VERSION 5.8 ;
BUSBITCHARS "[]" ;
DIVIDERCHAR "/" ;
UNITS
    DATABASE MICRONS 1000 ;
END UNITS

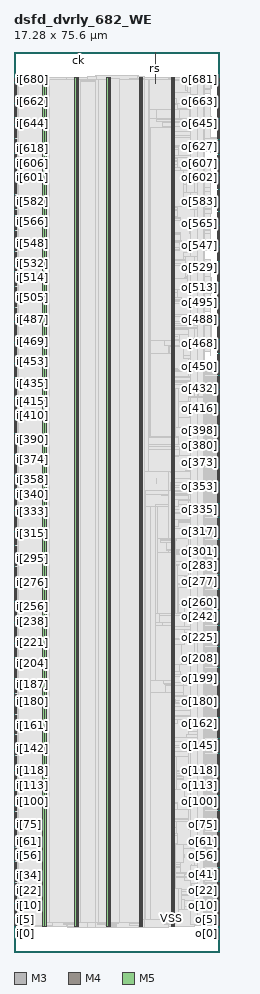
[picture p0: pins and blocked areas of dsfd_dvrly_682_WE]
MACRO dsfd_dvrly_682_WE
  FOREIGN dsfd_dvrly_682_WE 0 0 ;
  CLASS BLOCK ;
  SIZE 17.28 BY 75.6 ;
  PIN ck
    DIRECTION INPUT ;
    USE SIGNAL ;
    PORT
      LAYER M3 ;
        RECT  5.4 75.456 5.418 75.6 ;
    END
    PORT
      LAYER M3 ;
        RECT  5.4 74.683 5.418 75.468 ;
    END
  END ck
  PIN ck_o
    DIRECTION OUTPUT ;
    USE SIGNAL ;
    PORT
      LAYER M4 ;
        RECT  17.088 73.392 17.28 73.416 ;
    END
  END ck_o
  PIN i[0]
    DIRECTION INPUT ;
    USE SIGNAL ;
    PORT
      LAYER M4 ;
        RECT  0 2.208 0.192 2.232 ;
    END
  END i[0]
  PIN i[100]
    DIRECTION INPUT ;
    USE SIGNAL ;
    PORT
      LAYER M4 ;
        RECT  0 12.672 0.192 12.696 ;
    END
  END i[100]
  PIN i[101]
    DIRECTION INPUT ;
    USE SIGNAL ;
    PORT
      LAYER M4 ;
        RECT  0 12.768 0.192 12.792 ;
    END
  END i[101]
  PIN i[102]
    DIRECTION INPUT ;
    USE SIGNAL ;
    PORT
      LAYER M4 ;
        RECT  0 12.864 0.192 12.888 ;
    END
  END i[102]
  PIN i[103]
    DIRECTION INPUT ;
    USE SIGNAL ;
    PORT
      LAYER M4 ;
        RECT  0 13.008 0.192 13.032 ;
    END
  END i[103]
  PIN i[104]
    DIRECTION INPUT ;
    USE SIGNAL ;
    PORT
      LAYER M4 ;
        RECT  0 13.104 0.192 13.128 ;
    END
  END i[104]
  PIN i[105]
    DIRECTION INPUT ;
    USE SIGNAL ;
    PORT
      LAYER M4 ;
        RECT  0 13.2 0.192 13.224 ;
    END
  END i[105]
  PIN i[106]
    DIRECTION INPUT ;
    USE SIGNAL ;
    PORT
      LAYER M4 ;
        RECT  0 13.296 0.192 13.32 ;
    END
  END i[106]
  PIN i[107]
    DIRECTION INPUT ;
    USE SIGNAL ;
    PORT
      LAYER M4 ;
        RECT  0 13.392 0.192 13.416 ;
    END
  END i[107]
  PIN i[108]
    DIRECTION INPUT ;
    USE SIGNAL ;
    PORT
      LAYER M4 ;
        RECT  0 13.488 0.192 13.512 ;
    END
  END i[108]
  PIN i[109]
    DIRECTION INPUT ;
    USE SIGNAL ;
    PORT
      LAYER M4 ;
        RECT  0 13.632 0.192 13.656 ;
    END
  END i[109]
  PIN i[10]
    DIRECTION INPUT ;
    USE SIGNAL ;
    PORT
      LAYER M4 ;
        RECT  0 3.264 0.192 3.288 ;
    END
  END i[10]
  PIN i[110]
    DIRECTION INPUT ;
    USE SIGNAL ;
    PORT
      LAYER M4 ;
        RECT  0 13.728 0.192 13.752 ;
    END
  END i[110]
  PIN i[111]
    DIRECTION INPUT ;
    USE SIGNAL ;
    PORT
      LAYER M4 ;
        RECT  0 13.824 0.192 13.848 ;
    END
  END i[111]
  PIN i[112]
    DIRECTION INPUT ;
    USE SIGNAL ;
    PORT
      LAYER M4 ;
        RECT  0 13.92 0.192 13.944 ;
    END
  END i[112]
  PIN i[113]
    DIRECTION INPUT ;
    USE SIGNAL ;
    PORT
      LAYER M4 ;
        RECT  0 14.016 0.192 14.04 ;
    END
  END i[113]
  PIN i[114]
    DIRECTION INPUT ;
    USE SIGNAL ;
    PORT
      LAYER M4 ;
        RECT  0 14.16 0.192 14.184 ;
    END
  END i[114]
  PIN i[115]
    DIRECTION INPUT ;
    USE SIGNAL ;
    PORT
      LAYER M4 ;
        RECT  0 14.256 0.192 14.28 ;
    END
  END i[115]
  PIN i[116]
    DIRECTION INPUT ;
    USE SIGNAL ;
    PORT
      LAYER M4 ;
        RECT  0 14.352 0.192 14.376 ;
    END
  END i[116]
  PIN i[117]
    DIRECTION INPUT ;
    USE SIGNAL ;
    PORT
      LAYER M4 ;
        RECT  0 14.448 0.192 14.472 ;
    END
  END i[117]
  PIN i[118]
    DIRECTION INPUT ;
    USE SIGNAL ;
    PORT
      LAYER M4 ;
        RECT  0 14.544 0.192 14.568 ;
    END
  END i[118]
  PIN i[119]
    DIRECTION INPUT ;
    USE SIGNAL ;
    PORT
      LAYER M4 ;
        RECT  0 14.64 0.192 14.664 ;
    END
  END i[119]
  PIN i[11]
    DIRECTION INPUT ;
    USE SIGNAL ;
    PORT
      LAYER M4 ;
        RECT  0 3.36 0.192 3.384 ;
    END
  END i[11]
  PIN i[120]
    DIRECTION INPUT ;
    USE SIGNAL ;
    PORT
      LAYER M4 ;
        RECT  0 14.784 0.192 14.808 ;
    END
  END i[120]
  PIN i[121]
    DIRECTION INPUT ;
    USE SIGNAL ;
    PORT
      LAYER M4 ;
        RECT  0 14.88 0.192 14.904 ;
    END
  END i[121]
  PIN i[122]
    DIRECTION INPUT ;
    USE SIGNAL ;
    PORT
      LAYER M4 ;
        RECT  0 14.976 0.192 15 ;
    END
  END i[122]
  PIN i[123]
    DIRECTION INPUT ;
    USE SIGNAL ;
    PORT
      LAYER M4 ;
        RECT  0 15.072 0.192 15.096 ;
    END
  END i[123]
  PIN i[124]
    DIRECTION INPUT ;
    USE SIGNAL ;
    PORT
      LAYER M4 ;
        RECT  0 15.168 0.192 15.192 ;
    END
  END i[124]
  PIN i[125]
    DIRECTION INPUT ;
    USE SIGNAL ;
    PORT
      LAYER M4 ;
        RECT  0 15.312 0.192 15.336 ;
    END
  END i[125]
  PIN i[126]
    DIRECTION INPUT ;
    USE SIGNAL ;
    PORT
      LAYER M4 ;
        RECT  0 15.408 0.192 15.432 ;
    END
  END i[126]
  PIN i[127]
    DIRECTION INPUT ;
    USE SIGNAL ;
    PORT
      LAYER M4 ;
        RECT  0 15.504 0.192 15.528 ;
    END
  END i[127]
  PIN i[128]
    DIRECTION INPUT ;
    USE SIGNAL ;
    PORT
      LAYER M4 ;
        RECT  0 15.6 0.192 15.624 ;
    END
  END i[128]
  PIN i[129]
    DIRECTION INPUT ;
    USE SIGNAL ;
    PORT
      LAYER M4 ;
        RECT  0 15.696 0.192 15.72 ;
    END
  END i[129]
  PIN i[12]
    DIRECTION INPUT ;
    USE SIGNAL ;
    PORT
      LAYER M4 ;
        RECT  0 3.456 0.192 3.48 ;
    END
  END i[12]
  PIN i[130]
    DIRECTION INPUT ;
    USE SIGNAL ;
    PORT
      LAYER M4 ;
        RECT  0 15.792 0.192 15.816 ;
    END
  END i[130]
  PIN i[131]
    DIRECTION INPUT ;
    USE SIGNAL ;
    PORT
      LAYER M4 ;
        RECT  0 15.936 0.192 15.96 ;
    END
  END i[131]
  PIN i[132]
    DIRECTION INPUT ;
    USE SIGNAL ;
    PORT
      LAYER M4 ;
        RECT  0 16.032 0.192 16.056 ;
    END
  END i[132]
  PIN i[133]
    DIRECTION INPUT ;
    USE SIGNAL ;
    PORT
      LAYER M4 ;
        RECT  0 16.128 0.192 16.152 ;
    END
  END i[133]
  PIN i[134]
    DIRECTION INPUT ;
    USE SIGNAL ;
    PORT
      LAYER M4 ;
        RECT  0 16.224 0.192 16.248 ;
    END
  END i[134]
  PIN i[135]
    DIRECTION INPUT ;
    USE SIGNAL ;
    PORT
      LAYER M4 ;
        RECT  0 16.32 0.192 16.344 ;
    END
  END i[135]
  PIN i[136]
    DIRECTION INPUT ;
    USE SIGNAL ;
    PORT
      LAYER M4 ;
        RECT  0 16.416 0.192 16.44 ;
    END
  END i[136]
  PIN i[137]
    DIRECTION INPUT ;
    USE SIGNAL ;
    PORT
      LAYER M4 ;
        RECT  0 16.56 0.192 16.584 ;
    END
  END i[137]
  PIN i[138]
    DIRECTION INPUT ;
    USE SIGNAL ;
    PORT
      LAYER M4 ;
        RECT  0 16.656 0.192 16.68 ;
    END
  END i[138]
  PIN i[139]
    DIRECTION INPUT ;
    USE SIGNAL ;
    PORT
      LAYER M4 ;
        RECT  0 16.752 0.192 16.776 ;
    END
  END i[139]
  PIN i[13]
    DIRECTION INPUT ;
    USE SIGNAL ;
    PORT
      LAYER M4 ;
        RECT  0 3.6 0.192 3.624 ;
    END
  END i[13]
  PIN i[140]
    DIRECTION INPUT ;
    USE SIGNAL ;
    PORT
      LAYER M4 ;
        RECT  0 16.848 0.192 16.872 ;
    END
  END i[140]
  PIN i[141]
    DIRECTION INPUT ;
    USE SIGNAL ;
    PORT
      LAYER M4 ;
        RECT  0 16.944 0.192 16.968 ;
    END
  END i[141]
  PIN i[142]
    DIRECTION INPUT ;
    USE SIGNAL ;
    PORT
      LAYER M4 ;
        RECT  0 17.088 0.192 17.112 ;
    END
  END i[142]
  PIN i[143]
    DIRECTION INPUT ;
    USE SIGNAL ;
    PORT
      LAYER M4 ;
        RECT  0 17.184 0.192 17.208 ;
    END
  END i[143]
  PIN i[144]
    DIRECTION INPUT ;
    USE SIGNAL ;
    PORT
      LAYER M4 ;
        RECT  0 17.28 0.192 17.304 ;
    END
  END i[144]
  PIN i[145]
    DIRECTION INPUT ;
    USE SIGNAL ;
    PORT
      LAYER M4 ;
        RECT  0 17.376 0.192 17.4 ;
    END
  END i[145]
  PIN i[146]
    DIRECTION INPUT ;
    USE SIGNAL ;
    PORT
      LAYER M4 ;
        RECT  0 17.472 0.192 17.496 ;
    END
  END i[146]
  PIN i[147]
    DIRECTION INPUT ;
    USE SIGNAL ;
    PORT
      LAYER M4 ;
        RECT  0 17.568 0.192 17.592 ;
    END
  END i[147]
  PIN i[148]
    DIRECTION INPUT ;
    USE SIGNAL ;
    PORT
      LAYER M4 ;
        RECT  0 17.712 0.192 17.736 ;
    END
  END i[148]
  PIN i[149]
    DIRECTION INPUT ;
    USE SIGNAL ;
    PORT
      LAYER M4 ;
        RECT  0 17.808 0.192 17.832 ;
    END
  END i[149]
  PIN i[14]
    DIRECTION INPUT ;
    USE SIGNAL ;
    PORT
      LAYER M4 ;
        RECT  0 3.696 0.192 3.72 ;
    END
  END i[14]
  PIN i[150]
    DIRECTION INPUT ;
    USE SIGNAL ;
    PORT
      LAYER M4 ;
        RECT  0 17.904 0.192 17.928 ;
    END
  END i[150]
  PIN i[151]
    DIRECTION INPUT ;
    USE SIGNAL ;
    PORT
      LAYER M4 ;
        RECT  0 18 0.192 18.024 ;
    END
  END i[151]
  PIN i[152]
    DIRECTION INPUT ;
    USE SIGNAL ;
    PORT
      LAYER M4 ;
        RECT  0 18.096 0.192 18.12 ;
    END
  END i[152]
  PIN i[153]
    DIRECTION INPUT ;
    USE SIGNAL ;
    PORT
      LAYER M4 ;
        RECT  0 18.192 0.192 18.216 ;
    END
  END i[153]
  PIN i[154]
    DIRECTION INPUT ;
    USE SIGNAL ;
    PORT
      LAYER M4 ;
        RECT  0 18.336 0.192 18.36 ;
    END
  END i[154]
  PIN i[155]
    DIRECTION INPUT ;
    USE SIGNAL ;
    PORT
      LAYER M4 ;
        RECT  0 18.432 0.192 18.456 ;
    END
  END i[155]
  PIN i[156]
    DIRECTION INPUT ;
    USE SIGNAL ;
    PORT
      LAYER M4 ;
        RECT  0 18.528 0.192 18.552 ;
    END
  END i[156]
  PIN i[157]
    DIRECTION INPUT ;
    USE SIGNAL ;
    PORT
      LAYER M4 ;
        RECT  0 18.624 0.192 18.648 ;
    END
  END i[157]
  PIN i[158]
    DIRECTION INPUT ;
    USE SIGNAL ;
    PORT
      LAYER M4 ;
        RECT  0 18.72 0.192 18.744 ;
    END
  END i[158]
  PIN i[159]
    DIRECTION INPUT ;
    USE SIGNAL ;
    PORT
      LAYER M4 ;
        RECT  0 18.864 0.192 18.888 ;
    END
  END i[159]
  PIN i[15]
    DIRECTION INPUT ;
    USE SIGNAL ;
    PORT
      LAYER M4 ;
        RECT  0 3.792 0.192 3.816 ;
    END
  END i[15]
  PIN i[160]
    DIRECTION INPUT ;
    USE SIGNAL ;
    PORT
      LAYER M4 ;
        RECT  0 18.96 0.192 18.984 ;
    END
  END i[160]
  PIN i[161]
    DIRECTION INPUT ;
    USE SIGNAL ;
    PORT
      LAYER M4 ;
        RECT  0 19.056 0.192 19.08 ;
    END
  END i[161]
  PIN i[162]
    DIRECTION INPUT ;
    USE SIGNAL ;
    PORT
      LAYER M4 ;
        RECT  0 19.152 0.192 19.176 ;
    END
  END i[162]
  PIN i[163]
    DIRECTION INPUT ;
    USE SIGNAL ;
    PORT
      LAYER M4 ;
        RECT  0 19.248 0.192 19.272 ;
    END
  END i[163]
  PIN i[164]
    DIRECTION INPUT ;
    USE SIGNAL ;
    PORT
      LAYER M4 ;
        RECT  0 19.344 0.192 19.368 ;
    END
  END i[164]
  PIN i[165]
    DIRECTION INPUT ;
    USE SIGNAL ;
    PORT
      LAYER M4 ;
        RECT  0 19.488 0.192 19.512 ;
    END
  END i[165]
  PIN i[166]
    DIRECTION INPUT ;
    USE SIGNAL ;
    PORT
      LAYER M4 ;
        RECT  0 19.584 0.192 19.608 ;
    END
  END i[166]
  PIN i[167]
    DIRECTION INPUT ;
    USE SIGNAL ;
    PORT
      LAYER M4 ;
        RECT  0 19.68 0.192 19.704 ;
    END
  END i[167]
  PIN i[168]
    DIRECTION INPUT ;
    USE SIGNAL ;
    PORT
      LAYER M4 ;
        RECT  0 19.776 0.192 19.8 ;
    END
  END i[168]
  PIN i[169]
    DIRECTION INPUT ;
    USE SIGNAL ;
    PORT
      LAYER M4 ;
        RECT  0 19.872 0.192 19.896 ;
    END
  END i[169]
  PIN i[16]
    DIRECTION INPUT ;
    USE SIGNAL ;
    PORT
      LAYER M4 ;
        RECT  0 3.888 0.192 3.912 ;
    END
  END i[16]
  PIN i[170]
    DIRECTION INPUT ;
    USE SIGNAL ;
    PORT
      LAYER M4 ;
        RECT  0 20.016 0.192 20.04 ;
    END
  END i[170]
  PIN i[171]
    DIRECTION INPUT ;
    USE SIGNAL ;
    PORT
      LAYER M4 ;
        RECT  0 20.112 0.192 20.136 ;
    END
  END i[171]
  PIN i[172]
    DIRECTION INPUT ;
    USE SIGNAL ;
    PORT
      LAYER M4 ;
        RECT  0 20.208 0.192 20.232 ;
    END
  END i[172]
  PIN i[173]
    DIRECTION INPUT ;
    USE SIGNAL ;
    PORT
      LAYER M4 ;
        RECT  0 20.304 0.192 20.328 ;
    END
  END i[173]
  PIN i[174]
    DIRECTION INPUT ;
    USE SIGNAL ;
    PORT
      LAYER M4 ;
        RECT  0 20.4 0.192 20.424 ;
    END
  END i[174]
  PIN i[175]
    DIRECTION INPUT ;
    USE SIGNAL ;
    PORT
      LAYER M4 ;
        RECT  0 20.496 0.192 20.52 ;
    END
  END i[175]
  PIN i[176]
    DIRECTION INPUT ;
    USE SIGNAL ;
    PORT
      LAYER M4 ;
        RECT  0 20.64 0.192 20.664 ;
    END
  END i[176]
  PIN i[177]
    DIRECTION INPUT ;
    USE SIGNAL ;
    PORT
      LAYER M4 ;
        RECT  0 20.736 0.192 20.76 ;
    END
  END i[177]
  PIN i[178]
    DIRECTION INPUT ;
    USE SIGNAL ;
    PORT
      LAYER M4 ;
        RECT  0 20.832 0.192 20.856 ;
    END
  END i[178]
  PIN i[179]
    DIRECTION INPUT ;
    USE SIGNAL ;
    PORT
      LAYER M4 ;
        RECT  0 20.928 0.192 20.952 ;
    END
  END i[179]
  PIN i[17]
    DIRECTION INPUT ;
    USE SIGNAL ;
    PORT
      LAYER M4 ;
        RECT  0 3.984 0.192 4.008 ;
    END
  END i[17]
  PIN i[180]
    DIRECTION INPUT ;
    USE SIGNAL ;
    PORT
      LAYER M4 ;
        RECT  0 21.024 0.192 21.048 ;
    END
  END i[180]
  PIN i[181]
    DIRECTION INPUT ;
    USE SIGNAL ;
    PORT
      LAYER M4 ;
        RECT  0 21.12 0.192 21.144 ;
    END
  END i[181]
  PIN i[182]
    DIRECTION INPUT ;
    USE SIGNAL ;
    PORT
      LAYER M4 ;
        RECT  0 21.264 0.192 21.288 ;
    END
  END i[182]
  PIN i[183]
    DIRECTION INPUT ;
    USE SIGNAL ;
    PORT
      LAYER M4 ;
        RECT  0 21.36 0.192 21.384 ;
    END
  END i[183]
  PIN i[184]
    DIRECTION INPUT ;
    USE SIGNAL ;
    PORT
      LAYER M4 ;
        RECT  0 21.456 0.192 21.48 ;
    END
  END i[184]
  PIN i[185]
    DIRECTION INPUT ;
    USE SIGNAL ;
    PORT
      LAYER M4 ;
        RECT  0 21.552 0.192 21.576 ;
    END
  END i[185]
  PIN i[186]
    DIRECTION INPUT ;
    USE SIGNAL ;
    PORT
      LAYER M4 ;
        RECT  0 21.648 0.192 21.672 ;
    END
  END i[186]
  PIN i[187]
    DIRECTION INPUT ;
    USE SIGNAL ;
    PORT
      LAYER M4 ;
        RECT  0 21.792 0.192 21.816 ;
    END
  END i[187]
  PIN i[188]
    DIRECTION INPUT ;
    USE SIGNAL ;
    PORT
      LAYER M4 ;
        RECT  0 21.888 0.192 21.912 ;
    END
  END i[188]
  PIN i[189]
    DIRECTION INPUT ;
    USE SIGNAL ;
    PORT
      LAYER M4 ;
        RECT  0 21.984 0.192 22.008 ;
    END
  END i[189]
  PIN i[18]
    DIRECTION INPUT ;
    USE SIGNAL ;
    PORT
      LAYER M4 ;
        RECT  0 4.128 0.192 4.152 ;
    END
  END i[18]
  PIN i[190]
    DIRECTION INPUT ;
    USE SIGNAL ;
    PORT
      LAYER M4 ;
        RECT  0 22.08 0.192 22.104 ;
    END
  END i[190]
  PIN i[191]
    DIRECTION INPUT ;
    USE SIGNAL ;
    PORT
      LAYER M4 ;
        RECT  0 22.176 0.192 22.2 ;
    END
  END i[191]
  PIN i[192]
    DIRECTION INPUT ;
    USE SIGNAL ;
    PORT
      LAYER M4 ;
        RECT  0 22.272 0.192 22.296 ;
    END
  END i[192]
  PIN i[193]
    DIRECTION INPUT ;
    USE SIGNAL ;
    PORT
      LAYER M4 ;
        RECT  0 22.416 0.192 22.44 ;
    END
  END i[193]
  PIN i[194]
    DIRECTION INPUT ;
    USE SIGNAL ;
    PORT
      LAYER M4 ;
        RECT  0 22.512 0.192 22.536 ;
    END
  END i[194]
  PIN i[195]
    DIRECTION INPUT ;
    USE SIGNAL ;
    PORT
      LAYER M4 ;
        RECT  0 22.608 0.192 22.632 ;
    END
  END i[195]
  PIN i[196]
    DIRECTION INPUT ;
    USE SIGNAL ;
    PORT
      LAYER M4 ;
        RECT  0 22.704 0.192 22.728 ;
    END
  END i[196]
  PIN i[197]
    DIRECTION INPUT ;
    USE SIGNAL ;
    PORT
      LAYER M4 ;
        RECT  0 22.8 0.192 22.824 ;
    END
  END i[197]
  PIN i[198]
    DIRECTION INPUT ;
    USE SIGNAL ;
    PORT
      LAYER M4 ;
        RECT  0 22.896 0.192 22.92 ;
    END
  END i[198]
  PIN i[199]
    DIRECTION INPUT ;
    USE SIGNAL ;
    PORT
      LAYER M4 ;
        RECT  0 23.04 0.192 23.064 ;
    END
  END i[199]
  PIN i[19]
    DIRECTION INPUT ;
    USE SIGNAL ;
    PORT
      LAYER M4 ;
        RECT  0 4.224 0.192 4.248 ;
    END
  END i[19]
  PIN i[1]
    DIRECTION INPUT ;
    USE SIGNAL ;
    PORT
      LAYER M4 ;
        RECT  0 2.352 0.192 2.376 ;
    END
  END i[1]
  PIN i[200]
    DIRECTION INPUT ;
    USE SIGNAL ;
    PORT
      LAYER M4 ;
        RECT  0 23.136 0.192 23.16 ;
    END
  END i[200]
  PIN i[201]
    DIRECTION INPUT ;
    USE SIGNAL ;
    PORT
      LAYER M4 ;
        RECT  0 23.232 0.192 23.256 ;
    END
  END i[201]
  PIN i[202]
    DIRECTION INPUT ;
    USE SIGNAL ;
    PORT
      LAYER M4 ;
        RECT  0 23.328 0.192 23.352 ;
    END
  END i[202]
  PIN i[203]
    DIRECTION INPUT ;
    USE SIGNAL ;
    PORT
      LAYER M4 ;
        RECT  0 23.424 0.192 23.448 ;
    END
  END i[203]
  PIN i[204]
    DIRECTION INPUT ;
    USE SIGNAL ;
    PORT
      LAYER M4 ;
        RECT  0 23.568 0.192 23.592 ;
    END
  END i[204]
  PIN i[205]
    DIRECTION INPUT ;
    USE SIGNAL ;
    PORT
      LAYER M4 ;
        RECT  0 23.664 0.192 23.688 ;
    END
  END i[205]
  PIN i[206]
    DIRECTION INPUT ;
    USE SIGNAL ;
    PORT
      LAYER M4 ;
        RECT  0 23.76 0.192 23.784 ;
    END
  END i[206]
  PIN i[207]
    DIRECTION INPUT ;
    USE SIGNAL ;
    PORT
      LAYER M4 ;
        RECT  0 23.856 0.192 23.88 ;
    END
  END i[207]
  PIN i[208]
    DIRECTION INPUT ;
    USE SIGNAL ;
    PORT
      LAYER M4 ;
        RECT  0 23.952 0.192 23.976 ;
    END
  END i[208]
  PIN i[209]
    DIRECTION INPUT ;
    USE SIGNAL ;
    PORT
      LAYER M4 ;
        RECT  0 24.048 0.192 24.072 ;
    END
  END i[209]
  PIN i[20]
    DIRECTION INPUT ;
    USE SIGNAL ;
    PORT
      LAYER M4 ;
        RECT  0 4.32 0.192 4.344 ;
    END
  END i[20]
  PIN i[210]
    DIRECTION INPUT ;
    USE SIGNAL ;
    PORT
      LAYER M4 ;
        RECT  0 24.192 0.192 24.216 ;
    END
  END i[210]
  PIN i[211]
    DIRECTION INPUT ;
    USE SIGNAL ;
    PORT
      LAYER M4 ;
        RECT  0 24.288 0.192 24.312 ;
    END
  END i[211]
  PIN i[212]
    DIRECTION INPUT ;
    USE SIGNAL ;
    PORT
      LAYER M4 ;
        RECT  0 24.384 0.192 24.408 ;
    END
  END i[212]
  PIN i[213]
    DIRECTION INPUT ;
    USE SIGNAL ;
    PORT
      LAYER M4 ;
        RECT  0 24.48 0.192 24.504 ;
    END
  END i[213]
  PIN i[214]
    DIRECTION INPUT ;
    USE SIGNAL ;
    PORT
      LAYER M4 ;
        RECT  0 24.576 0.192 24.6 ;
    END
  END i[214]
  PIN i[215]
    DIRECTION INPUT ;
    USE SIGNAL ;
    PORT
      LAYER M4 ;
        RECT  0 24.672 0.192 24.696 ;
    END
  END i[215]
  PIN i[216]
    DIRECTION INPUT ;
    USE SIGNAL ;
    PORT
      LAYER M4 ;
        RECT  0 24.816 0.192 24.84 ;
    END
  END i[216]
  PIN i[217]
    DIRECTION INPUT ;
    USE SIGNAL ;
    PORT
      LAYER M4 ;
        RECT  0 24.912 0.192 24.936 ;
    END
  END i[217]
  PIN i[218]
    DIRECTION INPUT ;
    USE SIGNAL ;
    PORT
      LAYER M4 ;
        RECT  0 25.008 0.192 25.032 ;
    END
  END i[218]
  PIN i[219]
    DIRECTION INPUT ;
    USE SIGNAL ;
    PORT
      LAYER M4 ;
        RECT  0 25.104 0.192 25.128 ;
    END
  END i[219]
  PIN i[21]
    DIRECTION INPUT ;
    USE SIGNAL ;
    PORT
      LAYER M4 ;
        RECT  0 4.416 0.192 4.44 ;
    END
  END i[21]
  PIN i[220]
    DIRECTION INPUT ;
    USE SIGNAL ;
    PORT
      LAYER M4 ;
        RECT  0 25.2 0.192 25.224 ;
    END
  END i[220]
  PIN i[221]
    DIRECTION INPUT ;
    USE SIGNAL ;
    PORT
      LAYER M4 ;
        RECT  0 25.344 0.192 25.368 ;
    END
  END i[221]
  PIN i[222]
    DIRECTION INPUT ;
    USE SIGNAL ;
    PORT
      LAYER M4 ;
        RECT  0 25.44 0.192 25.464 ;
    END
  END i[222]
  PIN i[223]
    DIRECTION INPUT ;
    USE SIGNAL ;
    PORT
      LAYER M4 ;
        RECT  0 25.536 0.192 25.56 ;
    END
  END i[223]
  PIN i[224]
    DIRECTION INPUT ;
    USE SIGNAL ;
    PORT
      LAYER M4 ;
        RECT  0 25.632 0.192 25.656 ;
    END
  END i[224]
  PIN i[225]
    DIRECTION INPUT ;
    USE SIGNAL ;
    PORT
      LAYER M4 ;
        RECT  0 25.728 0.192 25.752 ;
    END
  END i[225]
  PIN i[226]
    DIRECTION INPUT ;
    USE SIGNAL ;
    PORT
      LAYER M4 ;
        RECT  0 25.824 0.192 25.848 ;
    END
  END i[226]
  PIN i[227]
    DIRECTION INPUT ;
    USE SIGNAL ;
    PORT
      LAYER M4 ;
        RECT  0 25.968 0.192 25.992 ;
    END
  END i[227]
  PIN i[228]
    DIRECTION INPUT ;
    USE SIGNAL ;
    PORT
      LAYER M4 ;
        RECT  0 26.064 0.192 26.088 ;
    END
  END i[228]
  PIN i[229]
    DIRECTION INPUT ;
    USE SIGNAL ;
    PORT
      LAYER M4 ;
        RECT  0 26.16 0.192 26.184 ;
    END
  END i[229]
  PIN i[22]
    DIRECTION INPUT ;
    USE SIGNAL ;
    PORT
      LAYER M4 ;
        RECT  0 4.512 0.192 4.536 ;
    END
  END i[22]
  PIN i[230]
    DIRECTION INPUT ;
    USE SIGNAL ;
    PORT
      LAYER M4 ;
        RECT  0 26.256 0.192 26.28 ;
    END
  END i[230]
  PIN i[231]
    DIRECTION INPUT ;
    USE SIGNAL ;
    PORT
      LAYER M4 ;
        RECT  0 26.352 0.192 26.376 ;
    END
  END i[231]
  PIN i[232]
    DIRECTION INPUT ;
    USE SIGNAL ;
    PORT
      LAYER M4 ;
        RECT  0 26.448 0.192 26.472 ;
    END
  END i[232]
  PIN i[233]
    DIRECTION INPUT ;
    USE SIGNAL ;
    PORT
      LAYER M4 ;
        RECT  0 26.592 0.192 26.616 ;
    END
  END i[233]
  PIN i[234]
    DIRECTION INPUT ;
    USE SIGNAL ;
    PORT
      LAYER M4 ;
        RECT  0 26.688 0.192 26.712 ;
    END
  END i[234]
  PIN i[235]
    DIRECTION INPUT ;
    USE SIGNAL ;
    PORT
      LAYER M4 ;
        RECT  0 26.784 0.192 26.808 ;
    END
  END i[235]
  PIN i[236]
    DIRECTION INPUT ;
    USE SIGNAL ;
    PORT
      LAYER M4 ;
        RECT  0 26.88 0.192 26.904 ;
    END
  END i[236]
  PIN i[237]
    DIRECTION INPUT ;
    USE SIGNAL ;
    PORT
      LAYER M4 ;
        RECT  0 26.976 0.192 27 ;
    END
  END i[237]
  PIN i[238]
    DIRECTION INPUT ;
    USE SIGNAL ;
    PORT
      LAYER M4 ;
        RECT  0 27.12 0.192 27.144 ;
    END
  END i[238]
  PIN i[239]
    DIRECTION INPUT ;
    USE SIGNAL ;
    PORT
      LAYER M4 ;
        RECT  0 27.216 0.192 27.24 ;
    END
  END i[239]
  PIN i[23]
    DIRECTION INPUT ;
    USE SIGNAL ;
    PORT
      LAYER M4 ;
        RECT  0 4.608 0.192 4.632 ;
    END
  END i[23]
  PIN i[240]
    DIRECTION INPUT ;
    USE SIGNAL ;
    PORT
      LAYER M4 ;
        RECT  0 27.312 0.192 27.336 ;
    END
  END i[240]
  PIN i[241]
    DIRECTION INPUT ;
    USE SIGNAL ;
    PORT
      LAYER M4 ;
        RECT  0 27.408 0.192 27.432 ;
    END
  END i[241]
  PIN i[242]
    DIRECTION INPUT ;
    USE SIGNAL ;
    PORT
      LAYER M4 ;
        RECT  0 27.504 0.192 27.528 ;
    END
  END i[242]
  PIN i[243]
    DIRECTION INPUT ;
    USE SIGNAL ;
    PORT
      LAYER M4 ;
        RECT  0 27.6 0.192 27.624 ;
    END
  END i[243]
  PIN i[244]
    DIRECTION INPUT ;
    USE SIGNAL ;
    PORT
      LAYER M4 ;
        RECT  0 27.744 0.192 27.768 ;
    END
  END i[244]
  PIN i[245]
    DIRECTION INPUT ;
    USE SIGNAL ;
    PORT
      LAYER M4 ;
        RECT  0 27.84 0.192 27.864 ;
    END
  END i[245]
  PIN i[246]
    DIRECTION INPUT ;
    USE SIGNAL ;
    PORT
      LAYER M4 ;
        RECT  0 27.936 0.192 27.96 ;
    END
  END i[246]
  PIN i[247]
    DIRECTION INPUT ;
    USE SIGNAL ;
    PORT
      LAYER M4 ;
        RECT  0 28.032 0.192 28.056 ;
    END
  END i[247]
  PIN i[248]
    DIRECTION INPUT ;
    USE SIGNAL ;
    PORT
      LAYER M4 ;
        RECT  0 28.128 0.192 28.152 ;
    END
  END i[248]
  PIN i[249]
    DIRECTION INPUT ;
    USE SIGNAL ;
    PORT
      LAYER M4 ;
        RECT  0 28.272 0.192 28.296 ;
    END
  END i[249]
  PIN i[24]
    DIRECTION INPUT ;
    USE SIGNAL ;
    PORT
      LAYER M4 ;
        RECT  0 4.752 0.192 4.776 ;
    END
  END i[24]
  PIN i[250]
    DIRECTION INPUT ;
    USE SIGNAL ;
    PORT
      LAYER M4 ;
        RECT  0 28.368 0.192 28.392 ;
    END
  END i[250]
  PIN i[251]
    DIRECTION INPUT ;
    USE SIGNAL ;
    PORT
      LAYER M4 ;
        RECT  0 28.464 0.192 28.488 ;
    END
  END i[251]
  PIN i[252]
    DIRECTION INPUT ;
    USE SIGNAL ;
    PORT
      LAYER M4 ;
        RECT  0 28.56 0.192 28.584 ;
    END
  END i[252]
  PIN i[253]
    DIRECTION INPUT ;
    USE SIGNAL ;
    PORT
      LAYER M4 ;
        RECT  0 28.656 0.192 28.68 ;
    END
  END i[253]
  PIN i[254]
    DIRECTION INPUT ;
    USE SIGNAL ;
    PORT
      LAYER M4 ;
        RECT  0 28.752 0.192 28.776 ;
    END
  END i[254]
  PIN i[255]
    DIRECTION INPUT ;
    USE SIGNAL ;
    PORT
      LAYER M4 ;
        RECT  0 28.896 0.192 28.92 ;
    END
  END i[255]
  PIN i[256]
    DIRECTION INPUT ;
    USE SIGNAL ;
    PORT
      LAYER M4 ;
        RECT  0 28.992 0.192 29.016 ;
    END
  END i[256]
  PIN i[257]
    DIRECTION INPUT ;
    USE SIGNAL ;
    PORT
      LAYER M4 ;
        RECT  0 29.088 0.192 29.112 ;
    END
  END i[257]
  PIN i[258]
    DIRECTION INPUT ;
    USE SIGNAL ;
    PORT
      LAYER M4 ;
        RECT  0 29.184 0.192 29.208 ;
    END
  END i[258]
  PIN i[259]
    DIRECTION INPUT ;
    USE SIGNAL ;
    PORT
      LAYER M4 ;
        RECT  0 29.28 0.192 29.304 ;
    END
  END i[259]
  PIN i[25]
    DIRECTION INPUT ;
    USE SIGNAL ;
    PORT
      LAYER M4 ;
        RECT  0 4.848 0.192 4.872 ;
    END
  END i[25]
  PIN i[260]
    DIRECTION INPUT ;
    USE SIGNAL ;
    PORT
      LAYER M4 ;
        RECT  0 29.376 0.192 29.4 ;
    END
  END i[260]
  PIN i[261]
    DIRECTION INPUT ;
    USE SIGNAL ;
    PORT
      LAYER M4 ;
        RECT  0 29.52 0.192 29.544 ;
    END
  END i[261]
  PIN i[262]
    DIRECTION INPUT ;
    USE SIGNAL ;
    PORT
      LAYER M4 ;
        RECT  0 29.616 0.192 29.64 ;
    END
  END i[262]
  PIN i[263]
    DIRECTION INPUT ;
    USE SIGNAL ;
    PORT
      LAYER M4 ;
        RECT  0 29.712 0.192 29.736 ;
    END
  END i[263]
  PIN i[264]
    DIRECTION INPUT ;
    USE SIGNAL ;
    PORT
      LAYER M4 ;
        RECT  0 29.808 0.192 29.832 ;
    END
  END i[264]
  PIN i[265]
    DIRECTION INPUT ;
    USE SIGNAL ;
    PORT
      LAYER M4 ;
        RECT  0 29.904 0.192 29.928 ;
    END
  END i[265]
  PIN i[266]
    DIRECTION INPUT ;
    USE SIGNAL ;
    PORT
      LAYER M4 ;
        RECT  0 30.048 0.192 30.072 ;
    END
  END i[266]
  PIN i[267]
    DIRECTION INPUT ;
    USE SIGNAL ;
    PORT
      LAYER M4 ;
        RECT  0 30.144 0.192 30.168 ;
    END
  END i[267]
  PIN i[268]
    DIRECTION INPUT ;
    USE SIGNAL ;
    PORT
      LAYER M4 ;
        RECT  0 30.24 0.192 30.264 ;
    END
  END i[268]
  PIN i[269]
    DIRECTION INPUT ;
    USE SIGNAL ;
    PORT
      LAYER M4 ;
        RECT  0 30.336 0.192 30.36 ;
    END
  END i[269]
  PIN i[26]
    DIRECTION INPUT ;
    USE SIGNAL ;
    PORT
      LAYER M4 ;
        RECT  0 4.944 0.192 4.968 ;
    END
  END i[26]
  PIN i[270]
    DIRECTION INPUT ;
    USE SIGNAL ;
    PORT
      LAYER M4 ;
        RECT  0 30.432 0.192 30.456 ;
    END
  END i[270]
  PIN i[271]
    DIRECTION INPUT ;
    USE SIGNAL ;
    PORT
      LAYER M4 ;
        RECT  0 30.528 0.192 30.552 ;
    END
  END i[271]
  PIN i[272]
    DIRECTION INPUT ;
    USE SIGNAL ;
    PORT
      LAYER M4 ;
        RECT  0 30.672 0.192 30.696 ;
    END
  END i[272]
  PIN i[273]
    DIRECTION INPUT ;
    USE SIGNAL ;
    PORT
      LAYER M4 ;
        RECT  0 30.768 0.192 30.792 ;
    END
  END i[273]
  PIN i[274]
    DIRECTION INPUT ;
    USE SIGNAL ;
    PORT
      LAYER M4 ;
        RECT  0 30.864 0.192 30.888 ;
    END
  END i[274]
  PIN i[275]
    DIRECTION INPUT ;
    USE SIGNAL ;
    PORT
      LAYER M4 ;
        RECT  0 30.96 0.192 30.984 ;
    END
  END i[275]
  PIN i[276]
    DIRECTION INPUT ;
    USE SIGNAL ;
    PORT
      LAYER M4 ;
        RECT  0 31.056 0.192 31.08 ;
    END
  END i[276]
  PIN i[277]
    DIRECTION INPUT ;
    USE SIGNAL ;
    PORT
      LAYER M4 ;
        RECT  0 31.152 0.192 31.176 ;
    END
  END i[277]
  PIN i[278]
    DIRECTION INPUT ;
    USE SIGNAL ;
    PORT
      LAYER M4 ;
        RECT  0 31.296 0.192 31.32 ;
    END
  END i[278]
  PIN i[279]
    DIRECTION INPUT ;
    USE SIGNAL ;
    PORT
      LAYER M4 ;
        RECT  0 31.392 0.192 31.416 ;
    END
  END i[279]
  PIN i[27]
    DIRECTION INPUT ;
    USE SIGNAL ;
    PORT
      LAYER M4 ;
        RECT  0 5.04 0.192 5.064 ;
    END
  END i[27]
  PIN i[280]
    DIRECTION INPUT ;
    USE SIGNAL ;
    PORT
      LAYER M4 ;
        RECT  0 31.488 0.192 31.512 ;
    END
  END i[280]
  PIN i[281]
    DIRECTION INPUT ;
    USE SIGNAL ;
    PORT
      LAYER M4 ;
        RECT  0 31.584 0.192 31.608 ;
    END
  END i[281]
  PIN i[282]
    DIRECTION INPUT ;
    USE SIGNAL ;
    PORT
      LAYER M4 ;
        RECT  0 31.68 0.192 31.704 ;
    END
  END i[282]
  PIN i[283]
    DIRECTION INPUT ;
    USE SIGNAL ;
    PORT
      LAYER M4 ;
        RECT  0 31.824 0.192 31.848 ;
    END
  END i[283]
  PIN i[284]
    DIRECTION INPUT ;
    USE SIGNAL ;
    PORT
      LAYER M4 ;
        RECT  0 31.92 0.192 31.944 ;
    END
  END i[284]
  PIN i[285]
    DIRECTION INPUT ;
    USE SIGNAL ;
    PORT
      LAYER M4 ;
        RECT  0 32.016 0.192 32.04 ;
    END
  END i[285]
  PIN i[286]
    DIRECTION INPUT ;
    USE SIGNAL ;
    PORT
      LAYER M4 ;
        RECT  0 32.112 0.192 32.136 ;
    END
  END i[286]
  PIN i[287]
    DIRECTION INPUT ;
    USE SIGNAL ;
    PORT
      LAYER M4 ;
        RECT  0 32.208 0.192 32.232 ;
    END
  END i[287]
  PIN i[288]
    DIRECTION INPUT ;
    USE SIGNAL ;
    PORT
      LAYER M4 ;
        RECT  0 32.304 0.192 32.328 ;
    END
  END i[288]
  PIN i[289]
    DIRECTION INPUT ;
    USE SIGNAL ;
    PORT
      LAYER M4 ;
        RECT  0 32.448 0.192 32.472 ;
    END
  END i[289]
  PIN i[28]
    DIRECTION INPUT ;
    USE SIGNAL ;
    PORT
      LAYER M4 ;
        RECT  0 5.136 0.192 5.16 ;
    END
  END i[28]
  PIN i[290]
    DIRECTION INPUT ;
    USE SIGNAL ;
    PORT
      LAYER M4 ;
        RECT  0 32.544 0.192 32.568 ;
    END
  END i[290]
  PIN i[291]
    DIRECTION INPUT ;
    USE SIGNAL ;
    PORT
      LAYER M4 ;
        RECT  0 32.64 0.192 32.664 ;
    END
  END i[291]
  PIN i[292]
    DIRECTION INPUT ;
    USE SIGNAL ;
    PORT
      LAYER M4 ;
        RECT  0 32.736 0.192 32.76 ;
    END
  END i[292]
  PIN i[293]
    DIRECTION INPUT ;
    USE SIGNAL ;
    PORT
      LAYER M4 ;
        RECT  0 32.832 0.192 32.856 ;
    END
  END i[293]
  PIN i[294]
    DIRECTION INPUT ;
    USE SIGNAL ;
    PORT
      LAYER M4 ;
        RECT  0 32.928 0.192 32.952 ;
    END
  END i[294]
  PIN i[295]
    DIRECTION INPUT ;
    USE SIGNAL ;
    PORT
      LAYER M4 ;
        RECT  0 33.072 0.192 33.096 ;
    END
  END i[295]
  PIN i[296]
    DIRECTION INPUT ;
    USE SIGNAL ;
    PORT
      LAYER M4 ;
        RECT  0 33.168 0.192 33.192 ;
    END
  END i[296]
  PIN i[297]
    DIRECTION INPUT ;
    USE SIGNAL ;
    PORT
      LAYER M4 ;
        RECT  0 33.264 0.192 33.288 ;
    END
  END i[297]
  PIN i[298]
    DIRECTION INPUT ;
    USE SIGNAL ;
    PORT
      LAYER M4 ;
        RECT  0 33.36 0.192 33.384 ;
    END
  END i[298]
  PIN i[299]
    DIRECTION INPUT ;
    USE SIGNAL ;
    PORT
      LAYER M4 ;
        RECT  0 33.456 0.192 33.48 ;
    END
  END i[299]
  PIN i[29]
    DIRECTION INPUT ;
    USE SIGNAL ;
    PORT
      LAYER M4 ;
        RECT  0 5.232 0.192 5.256 ;
    END
  END i[29]
  PIN i[2]
    DIRECTION INPUT ;
    USE SIGNAL ;
    PORT
      LAYER M4 ;
        RECT  0 2.448 0.192 2.472 ;
    END
  END i[2]
  PIN i[300]
    DIRECTION INPUT ;
    USE SIGNAL ;
    PORT
      LAYER M4 ;
        RECT  0 33.6 0.192 33.624 ;
    END
  END i[300]
  PIN i[301]
    DIRECTION INPUT ;
    USE SIGNAL ;
    PORT
      LAYER M4 ;
        RECT  0 33.696 0.192 33.72 ;
    END
  END i[301]
  PIN i[302]
    DIRECTION INPUT ;
    USE SIGNAL ;
    PORT
      LAYER M4 ;
        RECT  0 33.792 0.192 33.816 ;
    END
  END i[302]
  PIN i[303]
    DIRECTION INPUT ;
    USE SIGNAL ;
    PORT
      LAYER M4 ;
        RECT  0 33.888 0.192 33.912 ;
    END
  END i[303]
  PIN i[304]
    DIRECTION INPUT ;
    USE SIGNAL ;
    PORT
      LAYER M4 ;
        RECT  0 33.984 0.192 34.008 ;
    END
  END i[304]
  PIN i[305]
    DIRECTION INPUT ;
    USE SIGNAL ;
    PORT
      LAYER M4 ;
        RECT  0 34.08 0.192 34.104 ;
    END
  END i[305]
  PIN i[306]
    DIRECTION INPUT ;
    USE SIGNAL ;
    PORT
      LAYER M4 ;
        RECT  0 34.224 0.192 34.248 ;
    END
  END i[306]
  PIN i[307]
    DIRECTION INPUT ;
    USE SIGNAL ;
    PORT
      LAYER M4 ;
        RECT  0 34.32 0.192 34.344 ;
    END
  END i[307]
  PIN i[308]
    DIRECTION INPUT ;
    USE SIGNAL ;
    PORT
      LAYER M4 ;
        RECT  0 34.416 0.192 34.44 ;
    END
  END i[308]
  PIN i[309]
    DIRECTION INPUT ;
    USE SIGNAL ;
    PORT
      LAYER M4 ;
        RECT  0 34.512 0.192 34.536 ;
    END
  END i[309]
  PIN i[30]
    DIRECTION INPUT ;
    USE SIGNAL ;
    PORT
      LAYER M4 ;
        RECT  0 5.376 0.192 5.4 ;
    END
  END i[30]
  PIN i[310]
    DIRECTION INPUT ;
    USE SIGNAL ;
    PORT
      LAYER M4 ;
        RECT  0 34.608 0.192 34.632 ;
    END
  END i[310]
  PIN i[311]
    DIRECTION INPUT ;
    USE SIGNAL ;
    PORT
      LAYER M4 ;
        RECT  0 34.752 0.192 34.776 ;
    END
  END i[311]
  PIN i[312]
    DIRECTION INPUT ;
    USE SIGNAL ;
    PORT
      LAYER M4 ;
        RECT  0 34.848 0.192 34.872 ;
    END
  END i[312]
  PIN i[313]
    DIRECTION INPUT ;
    USE SIGNAL ;
    PORT
      LAYER M4 ;
        RECT  0 34.944 0.192 34.968 ;
    END
  END i[313]
  PIN i[314]
    DIRECTION INPUT ;
    USE SIGNAL ;
    PORT
      LAYER M4 ;
        RECT  0 35.04 0.192 35.064 ;
    END
  END i[314]
  PIN i[315]
    DIRECTION INPUT ;
    USE SIGNAL ;
    PORT
      LAYER M4 ;
        RECT  0 35.136 0.192 35.16 ;
    END
  END i[315]
  PIN i[316]
    DIRECTION INPUT ;
    USE SIGNAL ;
    PORT
      LAYER M4 ;
        RECT  0 35.232 0.192 35.256 ;
    END
  END i[316]
  PIN i[317]
    DIRECTION INPUT ;
    USE SIGNAL ;
    PORT
      LAYER M4 ;
        RECT  0 35.376 0.192 35.4 ;
    END
  END i[317]
  PIN i[318]
    DIRECTION INPUT ;
    USE SIGNAL ;
    PORT
      LAYER M4 ;
        RECT  0 35.472 0.192 35.496 ;
    END
  END i[318]
  PIN i[319]
    DIRECTION INPUT ;
    USE SIGNAL ;
    PORT
      LAYER M4 ;
        RECT  0 35.568 0.192 35.592 ;
    END
  END i[319]
  PIN i[31]
    DIRECTION INPUT ;
    USE SIGNAL ;
    PORT
      LAYER M4 ;
        RECT  0 5.472 0.192 5.496 ;
    END
  END i[31]
  PIN i[320]
    DIRECTION INPUT ;
    USE SIGNAL ;
    PORT
      LAYER M4 ;
        RECT  0 35.664 0.192 35.688 ;
    END
  END i[320]
  PIN i[321]
    DIRECTION INPUT ;
    USE SIGNAL ;
    PORT
      LAYER M4 ;
        RECT  0 35.76 0.192 35.784 ;
    END
  END i[321]
  PIN i[322]
    DIRECTION INPUT ;
    USE SIGNAL ;
    PORT
      LAYER M4 ;
        RECT  0 35.856 0.192 35.88 ;
    END
  END i[322]
  PIN i[323]
    DIRECTION INPUT ;
    USE SIGNAL ;
    PORT
      LAYER M4 ;
        RECT  0 36 0.192 36.024 ;
    END
  END i[323]
  PIN i[324]
    DIRECTION INPUT ;
    USE SIGNAL ;
    PORT
      LAYER M4 ;
        RECT  0 36.096 0.192 36.12 ;
    END
  END i[324]
  PIN i[325]
    DIRECTION INPUT ;
    USE SIGNAL ;
    PORT
      LAYER M4 ;
        RECT  0 36.192 0.192 36.216 ;
    END
  END i[325]
  PIN i[326]
    DIRECTION INPUT ;
    USE SIGNAL ;
    PORT
      LAYER M4 ;
        RECT  0 36.288 0.192 36.312 ;
    END
  END i[326]
  PIN i[327]
    DIRECTION INPUT ;
    USE SIGNAL ;
    PORT
      LAYER M4 ;
        RECT  0 36.384 0.192 36.408 ;
    END
  END i[327]
  PIN i[328]
    DIRECTION INPUT ;
    USE SIGNAL ;
    PORT
      LAYER M4 ;
        RECT  0 36.528 0.192 36.552 ;
    END
  END i[328]
  PIN i[329]
    DIRECTION INPUT ;
    USE SIGNAL ;
    PORT
      LAYER M4 ;
        RECT  0 36.624 0.192 36.648 ;
    END
  END i[329]
  PIN i[32]
    DIRECTION INPUT ;
    USE SIGNAL ;
    PORT
      LAYER M4 ;
        RECT  0 5.568 0.192 5.592 ;
    END
  END i[32]
  PIN i[330]
    DIRECTION INPUT ;
    USE SIGNAL ;
    PORT
      LAYER M4 ;
        RECT  0 36.72 0.192 36.744 ;
    END
  END i[330]
  PIN i[331]
    DIRECTION INPUT ;
    USE SIGNAL ;
    PORT
      LAYER M4 ;
        RECT  0 36.816 0.192 36.84 ;
    END
  END i[331]
  PIN i[332]
    DIRECTION INPUT ;
    USE SIGNAL ;
    PORT
      LAYER M4 ;
        RECT  0 36.912 0.192 36.936 ;
    END
  END i[332]
  PIN i[333]
    DIRECTION INPUT ;
    USE SIGNAL ;
    PORT
      LAYER M4 ;
        RECT  0 37.008 0.192 37.032 ;
    END
  END i[333]
  PIN i[334]
    DIRECTION INPUT ;
    USE SIGNAL ;
    PORT
      LAYER M4 ;
        RECT  0 37.152 0.192 37.176 ;
    END
  END i[334]
  PIN i[335]
    DIRECTION INPUT ;
    USE SIGNAL ;
    PORT
      LAYER M4 ;
        RECT  0 37.248 0.192 37.272 ;
    END
  END i[335]
  PIN i[336]
    DIRECTION INPUT ;
    USE SIGNAL ;
    PORT
      LAYER M4 ;
        RECT  0 37.344 0.192 37.368 ;
    END
  END i[336]
  PIN i[337]
    DIRECTION INPUT ;
    USE SIGNAL ;
    PORT
      LAYER M4 ;
        RECT  0 37.44 0.192 37.464 ;
    END
  END i[337]
  PIN i[338]
    DIRECTION INPUT ;
    USE SIGNAL ;
    PORT
      LAYER M4 ;
        RECT  0 37.536 0.192 37.56 ;
    END
  END i[338]
  PIN i[339]
    DIRECTION INPUT ;
    USE SIGNAL ;
    PORT
      LAYER M4 ;
        RECT  0 37.632 0.192 37.656 ;
    END
  END i[339]
  PIN i[33]
    DIRECTION INPUT ;
    USE SIGNAL ;
    PORT
      LAYER M4 ;
        RECT  0 5.664 0.192 5.688 ;
    END
  END i[33]
  PIN i[340]
    DIRECTION INPUT ;
    USE SIGNAL ;
    PORT
      LAYER M4 ;
        RECT  0 37.776 0.192 37.8 ;
    END
  END i[340]
  PIN i[341]
    DIRECTION INPUT ;
    USE SIGNAL ;
    PORT
      LAYER M4 ;
        RECT  0 37.872 0.192 37.896 ;
    END
  END i[341]
  PIN i[342]
    DIRECTION INPUT ;
    USE SIGNAL ;
    PORT
      LAYER M4 ;
        RECT  0 37.968 0.192 37.992 ;
    END
  END i[342]
  PIN i[343]
    DIRECTION INPUT ;
    USE SIGNAL ;
    PORT
      LAYER M4 ;
        RECT  0 38.064 0.192 38.088 ;
    END
  END i[343]
  PIN i[344]
    DIRECTION INPUT ;
    USE SIGNAL ;
    PORT
      LAYER M4 ;
        RECT  0 38.16 0.192 38.184 ;
    END
  END i[344]
  PIN i[345]
    DIRECTION INPUT ;
    USE SIGNAL ;
    PORT
      LAYER M4 ;
        RECT  0 38.304 0.192 38.328 ;
    END
  END i[345]
  PIN i[346]
    DIRECTION INPUT ;
    USE SIGNAL ;
    PORT
      LAYER M4 ;
        RECT  0 38.4 0.192 38.424 ;
    END
  END i[346]
  PIN i[347]
    DIRECTION INPUT ;
    USE SIGNAL ;
    PORT
      LAYER M4 ;
        RECT  0 38.496 0.192 38.52 ;
    END
  END i[347]
  PIN i[348]
    DIRECTION INPUT ;
    USE SIGNAL ;
    PORT
      LAYER M4 ;
        RECT  0 38.592 0.192 38.616 ;
    END
  END i[348]
  PIN i[349]
    DIRECTION INPUT ;
    USE SIGNAL ;
    PORT
      LAYER M4 ;
        RECT  0 38.688 0.192 38.712 ;
    END
  END i[349]
  PIN i[34]
    DIRECTION INPUT ;
    USE SIGNAL ;
    PORT
      LAYER M4 ;
        RECT  0 5.76 0.192 5.784 ;
    END
  END i[34]
  PIN i[350]
    DIRECTION INPUT ;
    USE SIGNAL ;
    PORT
      LAYER M4 ;
        RECT  0 38.784 0.192 38.808 ;
    END
  END i[350]
  PIN i[351]
    DIRECTION INPUT ;
    USE SIGNAL ;
    PORT
      LAYER M4 ;
        RECT  0 38.928 0.192 38.952 ;
    END
  END i[351]
  PIN i[352]
    DIRECTION INPUT ;
    USE SIGNAL ;
    PORT
      LAYER M4 ;
        RECT  0 39.024 0.192 39.048 ;
    END
  END i[352]
  PIN i[353]
    DIRECTION INPUT ;
    USE SIGNAL ;
    PORT
      LAYER M4 ;
        RECT  0 39.12 0.192 39.144 ;
    END
  END i[353]
  PIN i[354]
    DIRECTION INPUT ;
    USE SIGNAL ;
    PORT
      LAYER M4 ;
        RECT  0 39.216 0.192 39.24 ;
    END
  END i[354]
  PIN i[355]
    DIRECTION INPUT ;
    USE SIGNAL ;
    PORT
      LAYER M4 ;
        RECT  0 39.312 0.192 39.336 ;
    END
  END i[355]
  PIN i[356]
    DIRECTION INPUT ;
    USE SIGNAL ;
    PORT
      LAYER M4 ;
        RECT  0 39.408 0.192 39.432 ;
    END
  END i[356]
  PIN i[357]
    DIRECTION INPUT ;
    USE SIGNAL ;
    PORT
      LAYER M4 ;
        RECT  0 39.552 0.192 39.576 ;
    END
  END i[357]
  PIN i[358]
    DIRECTION INPUT ;
    USE SIGNAL ;
    PORT
      LAYER M4 ;
        RECT  0 39.648 0.192 39.672 ;
    END
  END i[358]
  PIN i[359]
    DIRECTION INPUT ;
    USE SIGNAL ;
    PORT
      LAYER M4 ;
        RECT  0 39.744 0.192 39.768 ;
    END
  END i[359]
  PIN i[35]
    DIRECTION INPUT ;
    USE SIGNAL ;
    PORT
      LAYER M4 ;
        RECT  0 5.904 0.192 5.928 ;
    END
  END i[35]
  PIN i[360]
    DIRECTION INPUT ;
    USE SIGNAL ;
    PORT
      LAYER M4 ;
        RECT  0 39.84 0.192 39.864 ;
    END
  END i[360]
  PIN i[361]
    DIRECTION INPUT ;
    USE SIGNAL ;
    PORT
      LAYER M4 ;
        RECT  0 39.936 0.192 39.96 ;
    END
  END i[361]
  PIN i[362]
    DIRECTION INPUT ;
    USE SIGNAL ;
    PORT
      LAYER M4 ;
        RECT  0 40.08 0.192 40.104 ;
    END
  END i[362]
  PIN i[363]
    DIRECTION INPUT ;
    USE SIGNAL ;
    PORT
      LAYER M4 ;
        RECT  0 40.176 0.192 40.2 ;
    END
  END i[363]
  PIN i[364]
    DIRECTION INPUT ;
    USE SIGNAL ;
    PORT
      LAYER M4 ;
        RECT  0 40.272 0.192 40.296 ;
    END
  END i[364]
  PIN i[365]
    DIRECTION INPUT ;
    USE SIGNAL ;
    PORT
      LAYER M4 ;
        RECT  0 40.368 0.192 40.392 ;
    END
  END i[365]
  PIN i[366]
    DIRECTION INPUT ;
    USE SIGNAL ;
    PORT
      LAYER M4 ;
        RECT  0 40.464 0.192 40.488 ;
    END
  END i[366]
  PIN i[367]
    DIRECTION INPUT ;
    USE SIGNAL ;
    PORT
      LAYER M4 ;
        RECT  0 40.56 0.192 40.584 ;
    END
  END i[367]
  PIN i[368]
    DIRECTION INPUT ;
    USE SIGNAL ;
    PORT
      LAYER M4 ;
        RECT  0 40.704 0.192 40.728 ;
    END
  END i[368]
  PIN i[369]
    DIRECTION INPUT ;
    USE SIGNAL ;
    PORT
      LAYER M4 ;
        RECT  0 40.8 0.192 40.824 ;
    END
  END i[369]
  PIN i[36]
    DIRECTION INPUT ;
    USE SIGNAL ;
    PORT
      LAYER M4 ;
        RECT  0 6 0.192 6.024 ;
    END
  END i[36]
  PIN i[370]
    DIRECTION INPUT ;
    USE SIGNAL ;
    PORT
      LAYER M4 ;
        RECT  0 40.896 0.192 40.92 ;
    END
  END i[370]
  PIN i[371]
    DIRECTION INPUT ;
    USE SIGNAL ;
    PORT
      LAYER M4 ;
        RECT  0 40.992 0.192 41.016 ;
    END
  END i[371]
  PIN i[372]
    DIRECTION INPUT ;
    USE SIGNAL ;
    PORT
      LAYER M4 ;
        RECT  0 41.088 0.192 41.112 ;
    END
  END i[372]
  PIN i[373]
    DIRECTION INPUT ;
    USE SIGNAL ;
    PORT
      LAYER M4 ;
        RECT  0 41.232 0.192 41.256 ;
    END
  END i[373]
  PIN i[374]
    DIRECTION INPUT ;
    USE SIGNAL ;
    PORT
      LAYER M4 ;
        RECT  0 41.328 0.192 41.352 ;
    END
  END i[374]
  PIN i[375]
    DIRECTION INPUT ;
    USE SIGNAL ;
    PORT
      LAYER M4 ;
        RECT  0 41.424 0.192 41.448 ;
    END
  END i[375]
  PIN i[376]
    DIRECTION INPUT ;
    USE SIGNAL ;
    PORT
      LAYER M4 ;
        RECT  0 41.52 0.192 41.544 ;
    END
  END i[376]
  PIN i[377]
    DIRECTION INPUT ;
    USE SIGNAL ;
    PORT
      LAYER M4 ;
        RECT  0 41.616 0.192 41.64 ;
    END
  END i[377]
  PIN i[378]
    DIRECTION INPUT ;
    USE SIGNAL ;
    PORT
      LAYER M4 ;
        RECT  0 41.712 0.192 41.736 ;
    END
  END i[378]
  PIN i[379]
    DIRECTION INPUT ;
    USE SIGNAL ;
    PORT
      LAYER M4 ;
        RECT  0 41.856 0.192 41.88 ;
    END
  END i[379]
  PIN i[37]
    DIRECTION INPUT ;
    USE SIGNAL ;
    PORT
      LAYER M4 ;
        RECT  0 6.096 0.192 6.12 ;
    END
  END i[37]
  PIN i[380]
    DIRECTION INPUT ;
    USE SIGNAL ;
    PORT
      LAYER M4 ;
        RECT  0 41.952 0.192 41.976 ;
    END
  END i[380]
  PIN i[381]
    DIRECTION INPUT ;
    USE SIGNAL ;
    PORT
      LAYER M4 ;
        RECT  0 42.048 0.192 42.072 ;
    END
  END i[381]
  PIN i[382]
    DIRECTION INPUT ;
    USE SIGNAL ;
    PORT
      LAYER M4 ;
        RECT  0 42.144 0.192 42.168 ;
    END
  END i[382]
  PIN i[383]
    DIRECTION INPUT ;
    USE SIGNAL ;
    PORT
      LAYER M4 ;
        RECT  0 42.24 0.192 42.264 ;
    END
  END i[383]
  PIN i[384]
    DIRECTION INPUT ;
    USE SIGNAL ;
    PORT
      LAYER M4 ;
        RECT  0 42.336 0.192 42.36 ;
    END
  END i[384]
  PIN i[385]
    DIRECTION INPUT ;
    USE SIGNAL ;
    PORT
      LAYER M4 ;
        RECT  0 42.48 0.192 42.504 ;
    END
  END i[385]
  PIN i[386]
    DIRECTION INPUT ;
    USE SIGNAL ;
    PORT
      LAYER M4 ;
        RECT  0 42.576 0.192 42.6 ;
    END
  END i[386]
  PIN i[387]
    DIRECTION INPUT ;
    USE SIGNAL ;
    PORT
      LAYER M4 ;
        RECT  0 42.672 0.192 42.696 ;
    END
  END i[387]
  PIN i[388]
    DIRECTION INPUT ;
    USE SIGNAL ;
    PORT
      LAYER M4 ;
        RECT  0 42.768 0.192 42.792 ;
    END
  END i[388]
  PIN i[389]
    DIRECTION INPUT ;
    USE SIGNAL ;
    PORT
      LAYER M4 ;
        RECT  0 42.864 0.192 42.888 ;
    END
  END i[389]
  PIN i[38]
    DIRECTION INPUT ;
    USE SIGNAL ;
    PORT
      LAYER M4 ;
        RECT  0 6.192 0.192 6.216 ;
    END
  END i[38]
  PIN i[390]
    DIRECTION INPUT ;
    USE SIGNAL ;
    PORT
      LAYER M4 ;
        RECT  0 43.008 0.192 43.032 ;
    END
  END i[390]
  PIN i[391]
    DIRECTION INPUT ;
    USE SIGNAL ;
    PORT
      LAYER M4 ;
        RECT  0 43.104 0.192 43.128 ;
    END
  END i[391]
  PIN i[392]
    DIRECTION INPUT ;
    USE SIGNAL ;
    PORT
      LAYER M4 ;
        RECT  0 43.2 0.192 43.224 ;
    END
  END i[392]
  PIN i[393]
    DIRECTION INPUT ;
    USE SIGNAL ;
    PORT
      LAYER M4 ;
        RECT  0 43.296 0.192 43.32 ;
    END
  END i[393]
  PIN i[394]
    DIRECTION INPUT ;
    USE SIGNAL ;
    PORT
      LAYER M4 ;
        RECT  0 43.392 0.192 43.416 ;
    END
  END i[394]
  PIN i[395]
    DIRECTION INPUT ;
    USE SIGNAL ;
    PORT
      LAYER M4 ;
        RECT  0 43.488 0.192 43.512 ;
    END
  END i[395]
  PIN i[396]
    DIRECTION INPUT ;
    USE SIGNAL ;
    PORT
      LAYER M4 ;
        RECT  0 43.632 0.192 43.656 ;
    END
  END i[396]
  PIN i[397]
    DIRECTION INPUT ;
    USE SIGNAL ;
    PORT
      LAYER M4 ;
        RECT  0 43.728 0.192 43.752 ;
    END
  END i[397]
  PIN i[398]
    DIRECTION INPUT ;
    USE SIGNAL ;
    PORT
      LAYER M4 ;
        RECT  0 43.824 0.192 43.848 ;
    END
  END i[398]
  PIN i[399]
    DIRECTION INPUT ;
    USE SIGNAL ;
    PORT
      LAYER M4 ;
        RECT  0 43.92 0.192 43.944 ;
    END
  END i[399]
  PIN i[39]
    DIRECTION INPUT ;
    USE SIGNAL ;
    PORT
      LAYER M4 ;
        RECT  0 6.288 0.192 6.312 ;
    END
  END i[39]
  PIN i[3]
    DIRECTION INPUT ;
    USE SIGNAL ;
    PORT
      LAYER M4 ;
        RECT  0 2.544 0.192 2.568 ;
    END
  END i[3]
  PIN i[400]
    DIRECTION INPUT ;
    USE SIGNAL ;
    PORT
      LAYER M4 ;
        RECT  0 44.016 0.192 44.04 ;
    END
  END i[400]
  PIN i[401]
    DIRECTION INPUT ;
    USE SIGNAL ;
    PORT
      LAYER M4 ;
        RECT  0 44.112 0.192 44.136 ;
    END
  END i[401]
  PIN i[402]
    DIRECTION INPUT ;
    USE SIGNAL ;
    PORT
      LAYER M4 ;
        RECT  0 44.256 0.192 44.28 ;
    END
  END i[402]
  PIN i[403]
    DIRECTION INPUT ;
    USE SIGNAL ;
    PORT
      LAYER M4 ;
        RECT  0 44.352 0.192 44.376 ;
    END
  END i[403]
  PIN i[404]
    DIRECTION INPUT ;
    USE SIGNAL ;
    PORT
      LAYER M4 ;
        RECT  0 44.448 0.192 44.472 ;
    END
  END i[404]
  PIN i[405]
    DIRECTION INPUT ;
    USE SIGNAL ;
    PORT
      LAYER M4 ;
        RECT  0 44.544 0.192 44.568 ;
    END
  END i[405]
  PIN i[406]
    DIRECTION INPUT ;
    USE SIGNAL ;
    PORT
      LAYER M4 ;
        RECT  0 44.64 0.192 44.664 ;
    END
  END i[406]
  PIN i[407]
    DIRECTION INPUT ;
    USE SIGNAL ;
    PORT
      LAYER M4 ;
        RECT  0 44.784 0.192 44.808 ;
    END
  END i[407]
  PIN i[408]
    DIRECTION INPUT ;
    USE SIGNAL ;
    PORT
      LAYER M4 ;
        RECT  0 44.88 0.192 44.904 ;
    END
  END i[408]
  PIN i[409]
    DIRECTION INPUT ;
    USE SIGNAL ;
    PORT
      LAYER M4 ;
        RECT  0 44.976 0.192 45 ;
    END
  END i[409]
  PIN i[40]
    DIRECTION INPUT ;
    USE SIGNAL ;
    PORT
      LAYER M4 ;
        RECT  0 6.384 0.192 6.408 ;
    END
  END i[40]
  PIN i[410]
    DIRECTION INPUT ;
    USE SIGNAL ;
    PORT
      LAYER M4 ;
        RECT  0 45.072 0.192 45.096 ;
    END
  END i[410]
  PIN i[411]
    DIRECTION INPUT ;
    USE SIGNAL ;
    PORT
      LAYER M4 ;
        RECT  0 45.168 0.192 45.192 ;
    END
  END i[411]
  PIN i[412]
    DIRECTION INPUT ;
    USE SIGNAL ;
    PORT
      LAYER M4 ;
        RECT  0 45.264 0.192 45.288 ;
    END
  END i[412]
  PIN i[413]
    DIRECTION INPUT ;
    USE SIGNAL ;
    PORT
      LAYER M4 ;
        RECT  0 45.408 0.192 45.432 ;
    END
  END i[413]
  PIN i[414]
    DIRECTION INPUT ;
    USE SIGNAL ;
    PORT
      LAYER M4 ;
        RECT  0 45.504 0.192 45.528 ;
    END
  END i[414]
  PIN i[415]
    DIRECTION INPUT ;
    USE SIGNAL ;
    PORT
      LAYER M4 ;
        RECT  0 45.6 0.192 45.624 ;
    END
  END i[415]
  PIN i[416]
    DIRECTION INPUT ;
    USE SIGNAL ;
    PORT
      LAYER M4 ;
        RECT  0 45.696 0.192 45.72 ;
    END
  END i[416]
  PIN i[417]
    DIRECTION INPUT ;
    USE SIGNAL ;
    PORT
      LAYER M4 ;
        RECT  0 45.792 0.192 45.816 ;
    END
  END i[417]
  PIN i[418]
    DIRECTION INPUT ;
    USE SIGNAL ;
    PORT
      LAYER M4 ;
        RECT  0 45.936 0.192 45.96 ;
    END
  END i[418]
  PIN i[419]
    DIRECTION INPUT ;
    USE SIGNAL ;
    PORT
      LAYER M4 ;
        RECT  0 46.032 0.192 46.056 ;
    END
  END i[419]
  PIN i[41]
    DIRECTION INPUT ;
    USE SIGNAL ;
    PORT
      LAYER M4 ;
        RECT  0 6.528 0.192 6.552 ;
    END
  END i[41]
  PIN i[420]
    DIRECTION INPUT ;
    USE SIGNAL ;
    PORT
      LAYER M4 ;
        RECT  0 46.128 0.192 46.152 ;
    END
  END i[420]
  PIN i[421]
    DIRECTION INPUT ;
    USE SIGNAL ;
    PORT
      LAYER M4 ;
        RECT  0 46.224 0.192 46.248 ;
    END
  END i[421]
  PIN i[422]
    DIRECTION INPUT ;
    USE SIGNAL ;
    PORT
      LAYER M4 ;
        RECT  0 46.32 0.192 46.344 ;
    END
  END i[422]
  PIN i[423]
    DIRECTION INPUT ;
    USE SIGNAL ;
    PORT
      LAYER M4 ;
        RECT  0 46.416 0.192 46.44 ;
    END
  END i[423]
  PIN i[424]
    DIRECTION INPUT ;
    USE SIGNAL ;
    PORT
      LAYER M4 ;
        RECT  0 46.56 0.192 46.584 ;
    END
  END i[424]
  PIN i[425]
    DIRECTION INPUT ;
    USE SIGNAL ;
    PORT
      LAYER M4 ;
        RECT  0 46.656 0.192 46.68 ;
    END
  END i[425]
  PIN i[426]
    DIRECTION INPUT ;
    USE SIGNAL ;
    PORT
      LAYER M4 ;
        RECT  0 46.752 0.192 46.776 ;
    END
  END i[426]
  PIN i[427]
    DIRECTION INPUT ;
    USE SIGNAL ;
    PORT
      LAYER M4 ;
        RECT  0 46.848 0.192 46.872 ;
    END
  END i[427]
  PIN i[428]
    DIRECTION INPUT ;
    USE SIGNAL ;
    PORT
      LAYER M4 ;
        RECT  0 46.944 0.192 46.968 ;
    END
  END i[428]
  PIN i[429]
    DIRECTION INPUT ;
    USE SIGNAL ;
    PORT
      LAYER M4 ;
        RECT  0 47.04 0.192 47.064 ;
    END
  END i[429]
  PIN i[42]
    DIRECTION INPUT ;
    USE SIGNAL ;
    PORT
      LAYER M4 ;
        RECT  0 6.624 0.192 6.648 ;
    END
  END i[42]
  PIN i[430]
    DIRECTION INPUT ;
    USE SIGNAL ;
    PORT
      LAYER M4 ;
        RECT  0 47.184 0.192 47.208 ;
    END
  END i[430]
  PIN i[431]
    DIRECTION INPUT ;
    USE SIGNAL ;
    PORT
      LAYER M4 ;
        RECT  0 47.28 0.192 47.304 ;
    END
  END i[431]
  PIN i[432]
    DIRECTION INPUT ;
    USE SIGNAL ;
    PORT
      LAYER M4 ;
        RECT  0 47.376 0.192 47.4 ;
    END
  END i[432]
  PIN i[433]
    DIRECTION INPUT ;
    USE SIGNAL ;
    PORT
      LAYER M4 ;
        RECT  0 47.472 0.192 47.496 ;
    END
  END i[433]
  PIN i[434]
    DIRECTION INPUT ;
    USE SIGNAL ;
    PORT
      LAYER M4 ;
        RECT  0 47.568 0.192 47.592 ;
    END
  END i[434]
  PIN i[435]
    DIRECTION INPUT ;
    USE SIGNAL ;
    PORT
      LAYER M4 ;
        RECT  0 47.712 0.192 47.736 ;
    END
  END i[435]
  PIN i[436]
    DIRECTION INPUT ;
    USE SIGNAL ;
    PORT
      LAYER M4 ;
        RECT  0 47.808 0.192 47.832 ;
    END
  END i[436]
  PIN i[437]
    DIRECTION INPUT ;
    USE SIGNAL ;
    PORT
      LAYER M4 ;
        RECT  0 47.904 0.192 47.928 ;
    END
  END i[437]
  PIN i[438]
    DIRECTION INPUT ;
    USE SIGNAL ;
    PORT
      LAYER M4 ;
        RECT  0 48 0.192 48.024 ;
    END
  END i[438]
  PIN i[439]
    DIRECTION INPUT ;
    USE SIGNAL ;
    PORT
      LAYER M4 ;
        RECT  0 48.096 0.192 48.12 ;
    END
  END i[439]
  PIN i[43]
    DIRECTION INPUT ;
    USE SIGNAL ;
    PORT
      LAYER M4 ;
        RECT  0 6.72 0.192 6.744 ;
    END
  END i[43]
  PIN i[440]
    DIRECTION INPUT ;
    USE SIGNAL ;
    PORT
      LAYER M4 ;
        RECT  0 48.192 0.192 48.216 ;
    END
  END i[440]
  PIN i[441]
    DIRECTION INPUT ;
    USE SIGNAL ;
    PORT
      LAYER M4 ;
        RECT  0 48.336 0.192 48.36 ;
    END
  END i[441]
  PIN i[442]
    DIRECTION INPUT ;
    USE SIGNAL ;
    PORT
      LAYER M4 ;
        RECT  0 48.432 0.192 48.456 ;
    END
  END i[442]
  PIN i[443]
    DIRECTION INPUT ;
    USE SIGNAL ;
    PORT
      LAYER M4 ;
        RECT  0 48.528 0.192 48.552 ;
    END
  END i[443]
  PIN i[444]
    DIRECTION INPUT ;
    USE SIGNAL ;
    PORT
      LAYER M4 ;
        RECT  0 48.624 0.192 48.648 ;
    END
  END i[444]
  PIN i[445]
    DIRECTION INPUT ;
    USE SIGNAL ;
    PORT
      LAYER M4 ;
        RECT  0 48.72 0.192 48.744 ;
    END
  END i[445]
  PIN i[446]
    DIRECTION INPUT ;
    USE SIGNAL ;
    PORT
      LAYER M4 ;
        RECT  0 48.816 0.192 48.84 ;
    END
  END i[446]
  PIN i[447]
    DIRECTION INPUT ;
    USE SIGNAL ;
    PORT
      LAYER M4 ;
        RECT  0 48.96 0.192 48.984 ;
    END
  END i[447]
  PIN i[448]
    DIRECTION INPUT ;
    USE SIGNAL ;
    PORT
      LAYER M4 ;
        RECT  0 49.056 0.192 49.08 ;
    END
  END i[448]
  PIN i[449]
    DIRECTION INPUT ;
    USE SIGNAL ;
    PORT
      LAYER M4 ;
        RECT  0 49.152 0.192 49.176 ;
    END
  END i[449]
  PIN i[44]
    DIRECTION INPUT ;
    USE SIGNAL ;
    PORT
      LAYER M4 ;
        RECT  0 6.816 0.192 6.84 ;
    END
  END i[44]
  PIN i[450]
    DIRECTION INPUT ;
    USE SIGNAL ;
    PORT
      LAYER M4 ;
        RECT  0 49.248 0.192 49.272 ;
    END
  END i[450]
  PIN i[451]
    DIRECTION INPUT ;
    USE SIGNAL ;
    PORT
      LAYER M4 ;
        RECT  0 49.344 0.192 49.368 ;
    END
  END i[451]
  PIN i[452]
    DIRECTION INPUT ;
    USE SIGNAL ;
    PORT
      LAYER M4 ;
        RECT  0 49.488 0.192 49.512 ;
    END
  END i[452]
  PIN i[453]
    DIRECTION INPUT ;
    USE SIGNAL ;
    PORT
      LAYER M4 ;
        RECT  0 49.584 0.192 49.608 ;
    END
  END i[453]
  PIN i[454]
    DIRECTION INPUT ;
    USE SIGNAL ;
    PORT
      LAYER M4 ;
        RECT  0 49.68 0.192 49.704 ;
    END
  END i[454]
  PIN i[455]
    DIRECTION INPUT ;
    USE SIGNAL ;
    PORT
      LAYER M4 ;
        RECT  0 49.776 0.192 49.8 ;
    END
  END i[455]
  PIN i[456]
    DIRECTION INPUT ;
    USE SIGNAL ;
    PORT
      LAYER M4 ;
        RECT  0 49.872 0.192 49.896 ;
    END
  END i[456]
  PIN i[457]
    DIRECTION INPUT ;
    USE SIGNAL ;
    PORT
      LAYER M4 ;
        RECT  0 49.968 0.192 49.992 ;
    END
  END i[457]
  PIN i[458]
    DIRECTION INPUT ;
    USE SIGNAL ;
    PORT
      LAYER M4 ;
        RECT  0 50.112 0.192 50.136 ;
    END
  END i[458]
  PIN i[459]
    DIRECTION INPUT ;
    USE SIGNAL ;
    PORT
      LAYER M4 ;
        RECT  0 50.208 0.192 50.232 ;
    END
  END i[459]
  PIN i[45]
    DIRECTION INPUT ;
    USE SIGNAL ;
    PORT
      LAYER M4 ;
        RECT  0 6.912 0.192 6.936 ;
    END
  END i[45]
  PIN i[460]
    DIRECTION INPUT ;
    USE SIGNAL ;
    PORT
      LAYER M4 ;
        RECT  0 50.304 0.192 50.328 ;
    END
  END i[460]
  PIN i[461]
    DIRECTION INPUT ;
    USE SIGNAL ;
    PORT
      LAYER M4 ;
        RECT  0 50.4 0.192 50.424 ;
    END
  END i[461]
  PIN i[462]
    DIRECTION INPUT ;
    USE SIGNAL ;
    PORT
      LAYER M4 ;
        RECT  0 50.496 0.192 50.52 ;
    END
  END i[462]
  PIN i[463]
    DIRECTION INPUT ;
    USE SIGNAL ;
    PORT
      LAYER M4 ;
        RECT  0 50.592 0.192 50.616 ;
    END
  END i[463]
  PIN i[464]
    DIRECTION INPUT ;
    USE SIGNAL ;
    PORT
      LAYER M4 ;
        RECT  0 50.736 0.192 50.76 ;
    END
  END i[464]
  PIN i[465]
    DIRECTION INPUT ;
    USE SIGNAL ;
    PORT
      LAYER M4 ;
        RECT  0 50.832 0.192 50.856 ;
    END
  END i[465]
  PIN i[466]
    DIRECTION INPUT ;
    USE SIGNAL ;
    PORT
      LAYER M4 ;
        RECT  0 50.928 0.192 50.952 ;
    END
  END i[466]
  PIN i[467]
    DIRECTION INPUT ;
    USE SIGNAL ;
    PORT
      LAYER M4 ;
        RECT  0 51.024 0.192 51.048 ;
    END
  END i[467]
  PIN i[468]
    DIRECTION INPUT ;
    USE SIGNAL ;
    PORT
      LAYER M4 ;
        RECT  0 51.12 0.192 51.144 ;
    END
  END i[468]
  PIN i[469]
    DIRECTION INPUT ;
    USE SIGNAL ;
    PORT
      LAYER M4 ;
        RECT  0 51.264 0.192 51.288 ;
    END
  END i[469]
  PIN i[46]
    DIRECTION INPUT ;
    USE SIGNAL ;
    PORT
      LAYER M4 ;
        RECT  0 7.056 0.192 7.08 ;
    END
  END i[46]
  PIN i[470]
    DIRECTION INPUT ;
    USE SIGNAL ;
    PORT
      LAYER M4 ;
        RECT  0 51.36 0.192 51.384 ;
    END
  END i[470]
  PIN i[471]
    DIRECTION INPUT ;
    USE SIGNAL ;
    PORT
      LAYER M4 ;
        RECT  0 51.456 0.192 51.48 ;
    END
  END i[471]
  PIN i[472]
    DIRECTION INPUT ;
    USE SIGNAL ;
    PORT
      LAYER M4 ;
        RECT  0 51.552 0.192 51.576 ;
    END
  END i[472]
  PIN i[473]
    DIRECTION INPUT ;
    USE SIGNAL ;
    PORT
      LAYER M4 ;
        RECT  0 51.648 0.192 51.672 ;
    END
  END i[473]
  PIN i[474]
    DIRECTION INPUT ;
    USE SIGNAL ;
    PORT
      LAYER M4 ;
        RECT  0 51.744 0.192 51.768 ;
    END
  END i[474]
  PIN i[475]
    DIRECTION INPUT ;
    USE SIGNAL ;
    PORT
      LAYER M4 ;
        RECT  0 51.888 0.192 51.912 ;
    END
  END i[475]
  PIN i[476]
    DIRECTION INPUT ;
    USE SIGNAL ;
    PORT
      LAYER M4 ;
        RECT  0 51.984 0.192 52.008 ;
    END
  END i[476]
  PIN i[477]
    DIRECTION INPUT ;
    USE SIGNAL ;
    PORT
      LAYER M4 ;
        RECT  0 52.08 0.192 52.104 ;
    END
  END i[477]
  PIN i[478]
    DIRECTION INPUT ;
    USE SIGNAL ;
    PORT
      LAYER M4 ;
        RECT  0 52.176 0.192 52.2 ;
    END
  END i[478]
  PIN i[479]
    DIRECTION INPUT ;
    USE SIGNAL ;
    PORT
      LAYER M4 ;
        RECT  0 52.272 0.192 52.296 ;
    END
  END i[479]
  PIN i[47]
    DIRECTION INPUT ;
    USE SIGNAL ;
    PORT
      LAYER M4 ;
        RECT  0 7.152 0.192 7.176 ;
    END
  END i[47]
  PIN i[480]
    DIRECTION INPUT ;
    USE SIGNAL ;
    PORT
      LAYER M4 ;
        RECT  0 52.416 0.192 52.44 ;
    END
  END i[480]
  PIN i[481]
    DIRECTION INPUT ;
    USE SIGNAL ;
    PORT
      LAYER M4 ;
        RECT  0 52.512 0.192 52.536 ;
    END
  END i[481]
  PIN i[482]
    DIRECTION INPUT ;
    USE SIGNAL ;
    PORT
      LAYER M4 ;
        RECT  0 52.608 0.192 52.632 ;
    END
  END i[482]
  PIN i[483]
    DIRECTION INPUT ;
    USE SIGNAL ;
    PORT
      LAYER M4 ;
        RECT  0 52.704 0.192 52.728 ;
    END
  END i[483]
  PIN i[484]
    DIRECTION INPUT ;
    USE SIGNAL ;
    PORT
      LAYER M4 ;
        RECT  0 52.8 0.192 52.824 ;
    END
  END i[484]
  PIN i[485]
    DIRECTION INPUT ;
    USE SIGNAL ;
    PORT
      LAYER M4 ;
        RECT  0 52.896 0.192 52.92 ;
    END
  END i[485]
  PIN i[486]
    DIRECTION INPUT ;
    USE SIGNAL ;
    PORT
      LAYER M4 ;
        RECT  0 53.04 0.192 53.064 ;
    END
  END i[486]
  PIN i[487]
    DIRECTION INPUT ;
    USE SIGNAL ;
    PORT
      LAYER M4 ;
        RECT  0 53.136 0.192 53.16 ;
    END
  END i[487]
  PIN i[488]
    DIRECTION INPUT ;
    USE SIGNAL ;
    PORT
      LAYER M4 ;
        RECT  0 53.232 0.192 53.256 ;
    END
  END i[488]
  PIN i[489]
    DIRECTION INPUT ;
    USE SIGNAL ;
    PORT
      LAYER M4 ;
        RECT  0 53.328 0.192 53.352 ;
    END
  END i[489]
  PIN i[48]
    DIRECTION INPUT ;
    USE SIGNAL ;
    PORT
      LAYER M4 ;
        RECT  0 7.248 0.192 7.272 ;
    END
  END i[48]
  PIN i[490]
    DIRECTION INPUT ;
    USE SIGNAL ;
    PORT
      LAYER M4 ;
        RECT  0 53.424 0.192 53.448 ;
    END
  END i[490]
  PIN i[491]
    DIRECTION INPUT ;
    USE SIGNAL ;
    PORT
      LAYER M4 ;
        RECT  0 53.52 0.192 53.544 ;
    END
  END i[491]
  PIN i[492]
    DIRECTION INPUT ;
    USE SIGNAL ;
    PORT
      LAYER M4 ;
        RECT  0 53.664 0.192 53.688 ;
    END
  END i[492]
  PIN i[493]
    DIRECTION INPUT ;
    USE SIGNAL ;
    PORT
      LAYER M4 ;
        RECT  0 53.76 0.192 53.784 ;
    END
  END i[493]
  PIN i[494]
    DIRECTION INPUT ;
    USE SIGNAL ;
    PORT
      LAYER M4 ;
        RECT  0 53.856 0.192 53.88 ;
    END
  END i[494]
  PIN i[495]
    DIRECTION INPUT ;
    USE SIGNAL ;
    PORT
      LAYER M4 ;
        RECT  0 53.952 0.192 53.976 ;
    END
  END i[495]
  PIN i[496]
    DIRECTION INPUT ;
    USE SIGNAL ;
    PORT
      LAYER M4 ;
        RECT  0 54.048 0.192 54.072 ;
    END
  END i[496]
  PIN i[497]
    DIRECTION INPUT ;
    USE SIGNAL ;
    PORT
      LAYER M4 ;
        RECT  0 54.192 0.192 54.216 ;
    END
  END i[497]
  PIN i[498]
    DIRECTION INPUT ;
    USE SIGNAL ;
    PORT
      LAYER M4 ;
        RECT  0 54.288 0.192 54.312 ;
    END
  END i[498]
  PIN i[499]
    DIRECTION INPUT ;
    USE SIGNAL ;
    PORT
      LAYER M4 ;
        RECT  0 54.384 0.192 54.408 ;
    END
  END i[499]
  PIN i[49]
    DIRECTION INPUT ;
    USE SIGNAL ;
    PORT
      LAYER M4 ;
        RECT  0 7.344 0.192 7.368 ;
    END
  END i[49]
  PIN i[4]
    DIRECTION INPUT ;
    USE SIGNAL ;
    PORT
      LAYER M4 ;
        RECT  0 2.64 0.192 2.664 ;
    END
  END i[4]
  PIN i[500]
    DIRECTION INPUT ;
    USE SIGNAL ;
    PORT
      LAYER M4 ;
        RECT  0 54.48 0.192 54.504 ;
    END
  END i[500]
  PIN i[501]
    DIRECTION INPUT ;
    USE SIGNAL ;
    PORT
      LAYER M4 ;
        RECT  0 54.576 0.192 54.6 ;
    END
  END i[501]
  PIN i[502]
    DIRECTION INPUT ;
    USE SIGNAL ;
    PORT
      LAYER M4 ;
        RECT  0 54.672 0.192 54.696 ;
    END
  END i[502]
  PIN i[503]
    DIRECTION INPUT ;
    USE SIGNAL ;
    PORT
      LAYER M4 ;
        RECT  0 54.816 0.192 54.84 ;
    END
  END i[503]
  PIN i[504]
    DIRECTION INPUT ;
    USE SIGNAL ;
    PORT
      LAYER M4 ;
        RECT  0 54.912 0.192 54.936 ;
    END
  END i[504]
  PIN i[505]
    DIRECTION INPUT ;
    USE SIGNAL ;
    PORT
      LAYER M4 ;
        RECT  0 55.008 0.192 55.032 ;
    END
  END i[505]
  PIN i[506]
    DIRECTION INPUT ;
    USE SIGNAL ;
    PORT
      LAYER M4 ;
        RECT  0 55.104 0.192 55.128 ;
    END
  END i[506]
  PIN i[507]
    DIRECTION INPUT ;
    USE SIGNAL ;
    PORT
      LAYER M4 ;
        RECT  0 55.2 0.192 55.224 ;
    END
  END i[507]
  PIN i[508]
    DIRECTION INPUT ;
    USE SIGNAL ;
    PORT
      LAYER M4 ;
        RECT  0 55.296 0.192 55.32 ;
    END
  END i[508]
  PIN i[509]
    DIRECTION INPUT ;
    USE SIGNAL ;
    PORT
      LAYER M4 ;
        RECT  0 55.44 0.192 55.464 ;
    END
  END i[509]
  PIN i[50]
    DIRECTION INPUT ;
    USE SIGNAL ;
    PORT
      LAYER M4 ;
        RECT  0 7.44 0.192 7.464 ;
    END
  END i[50]
  PIN i[510]
    DIRECTION INPUT ;
    USE SIGNAL ;
    PORT
      LAYER M4 ;
        RECT  0 55.536 0.192 55.56 ;
    END
  END i[510]
  PIN i[511]
    DIRECTION INPUT ;
    USE SIGNAL ;
    PORT
      LAYER M4 ;
        RECT  0 55.632 0.192 55.656 ;
    END
  END i[511]
  PIN i[512]
    DIRECTION INPUT ;
    USE SIGNAL ;
    PORT
      LAYER M4 ;
        RECT  0 55.728 0.192 55.752 ;
    END
  END i[512]
  PIN i[513]
    DIRECTION INPUT ;
    USE SIGNAL ;
    PORT
      LAYER M4 ;
        RECT  0 55.824 0.192 55.848 ;
    END
  END i[513]
  PIN i[514]
    DIRECTION INPUT ;
    USE SIGNAL ;
    PORT
      LAYER M4 ;
        RECT  0 55.968 0.192 55.992 ;
    END
  END i[514]
  PIN i[515]
    DIRECTION INPUT ;
    USE SIGNAL ;
    PORT
      LAYER M4 ;
        RECT  0 56.064 0.192 56.088 ;
    END
  END i[515]
  PIN i[516]
    DIRECTION INPUT ;
    USE SIGNAL ;
    PORT
      LAYER M4 ;
        RECT  0 56.16 0.192 56.184 ;
    END
  END i[516]
  PIN i[517]
    DIRECTION INPUT ;
    USE SIGNAL ;
    PORT
      LAYER M4 ;
        RECT  0 56.256 0.192 56.28 ;
    END
  END i[517]
  PIN i[518]
    DIRECTION INPUT ;
    USE SIGNAL ;
    PORT
      LAYER M4 ;
        RECT  0 56.352 0.192 56.376 ;
    END
  END i[518]
  PIN i[519]
    DIRECTION INPUT ;
    USE SIGNAL ;
    PORT
      LAYER M4 ;
        RECT  0 56.448 0.192 56.472 ;
    END
  END i[519]
  PIN i[51]
    DIRECTION INPUT ;
    USE SIGNAL ;
    PORT
      LAYER M4 ;
        RECT  0 7.536 0.192 7.56 ;
    END
  END i[51]
  PIN i[520]
    DIRECTION INPUT ;
    USE SIGNAL ;
    PORT
      LAYER M4 ;
        RECT  0 56.592 0.192 56.616 ;
    END
  END i[520]
  PIN i[521]
    DIRECTION INPUT ;
    USE SIGNAL ;
    PORT
      LAYER M4 ;
        RECT  0 56.688 0.192 56.712 ;
    END
  END i[521]
  PIN i[522]
    DIRECTION INPUT ;
    USE SIGNAL ;
    PORT
      LAYER M4 ;
        RECT  0 56.784 0.192 56.808 ;
    END
  END i[522]
  PIN i[523]
    DIRECTION INPUT ;
    USE SIGNAL ;
    PORT
      LAYER M4 ;
        RECT  0 56.88 0.192 56.904 ;
    END
  END i[523]
  PIN i[524]
    DIRECTION INPUT ;
    USE SIGNAL ;
    PORT
      LAYER M4 ;
        RECT  0 56.976 0.192 57 ;
    END
  END i[524]
  PIN i[525]
    DIRECTION INPUT ;
    USE SIGNAL ;
    PORT
      LAYER M4 ;
        RECT  0 57.072 0.192 57.096 ;
    END
  END i[525]
  PIN i[526]
    DIRECTION INPUT ;
    USE SIGNAL ;
    PORT
      LAYER M4 ;
        RECT  0 57.216 0.192 57.24 ;
    END
  END i[526]
  PIN i[527]
    DIRECTION INPUT ;
    USE SIGNAL ;
    PORT
      LAYER M4 ;
        RECT  0 57.312 0.192 57.336 ;
    END
  END i[527]
  PIN i[528]
    DIRECTION INPUT ;
    USE SIGNAL ;
    PORT
      LAYER M4 ;
        RECT  0 57.408 0.192 57.432 ;
    END
  END i[528]
  PIN i[529]
    DIRECTION INPUT ;
    USE SIGNAL ;
    PORT
      LAYER M4 ;
        RECT  0 57.504 0.192 57.528 ;
    END
  END i[529]
  PIN i[52]
    DIRECTION INPUT ;
    USE SIGNAL ;
    PORT
      LAYER M4 ;
        RECT  0 7.68 0.192 7.704 ;
    END
  END i[52]
  PIN i[530]
    DIRECTION INPUT ;
    USE SIGNAL ;
    PORT
      LAYER M4 ;
        RECT  0 57.6 0.192 57.624 ;
    END
  END i[530]
  PIN i[531]
    DIRECTION INPUT ;
    USE SIGNAL ;
    PORT
      LAYER M4 ;
        RECT  0 57.744 0.192 57.768 ;
    END
  END i[531]
  PIN i[532]
    DIRECTION INPUT ;
    USE SIGNAL ;
    PORT
      LAYER M4 ;
        RECT  0 57.84 0.192 57.864 ;
    END
  END i[532]
  PIN i[533]
    DIRECTION INPUT ;
    USE SIGNAL ;
    PORT
      LAYER M4 ;
        RECT  0 57.936 0.192 57.96 ;
    END
  END i[533]
  PIN i[534]
    DIRECTION INPUT ;
    USE SIGNAL ;
    PORT
      LAYER M4 ;
        RECT  0 58.032 0.192 58.056 ;
    END
  END i[534]
  PIN i[535]
    DIRECTION INPUT ;
    USE SIGNAL ;
    PORT
      LAYER M4 ;
        RECT  0 58.128 0.192 58.152 ;
    END
  END i[535]
  PIN i[536]
    DIRECTION INPUT ;
    USE SIGNAL ;
    PORT
      LAYER M4 ;
        RECT  0 58.224 0.192 58.248 ;
    END
  END i[536]
  PIN i[537]
    DIRECTION INPUT ;
    USE SIGNAL ;
    PORT
      LAYER M4 ;
        RECT  0 58.368 0.192 58.392 ;
    END
  END i[537]
  PIN i[538]
    DIRECTION INPUT ;
    USE SIGNAL ;
    PORT
      LAYER M4 ;
        RECT  0 58.464 0.192 58.488 ;
    END
  END i[538]
  PIN i[539]
    DIRECTION INPUT ;
    USE SIGNAL ;
    PORT
      LAYER M4 ;
        RECT  0 58.56 0.192 58.584 ;
    END
  END i[539]
  PIN i[53]
    DIRECTION INPUT ;
    USE SIGNAL ;
    PORT
      LAYER M4 ;
        RECT  0 7.776 0.192 7.8 ;
    END
  END i[53]
  PIN i[540]
    DIRECTION INPUT ;
    USE SIGNAL ;
    PORT
      LAYER M4 ;
        RECT  0 58.656 0.192 58.68 ;
    END
  END i[540]
  PIN i[541]
    DIRECTION INPUT ;
    USE SIGNAL ;
    PORT
      LAYER M4 ;
        RECT  0 58.752 0.192 58.776 ;
    END
  END i[541]
  PIN i[542]
    DIRECTION INPUT ;
    USE SIGNAL ;
    PORT
      LAYER M4 ;
        RECT  0 58.896 0.192 58.92 ;
    END
  END i[542]
  PIN i[543]
    DIRECTION INPUT ;
    USE SIGNAL ;
    PORT
      LAYER M4 ;
        RECT  0 58.992 0.192 59.016 ;
    END
  END i[543]
  PIN i[544]
    DIRECTION INPUT ;
    USE SIGNAL ;
    PORT
      LAYER M4 ;
        RECT  0 59.088 0.192 59.112 ;
    END
  END i[544]
  PIN i[545]
    DIRECTION INPUT ;
    USE SIGNAL ;
    PORT
      LAYER M4 ;
        RECT  0 59.184 0.192 59.208 ;
    END
  END i[545]
  PIN i[546]
    DIRECTION INPUT ;
    USE SIGNAL ;
    PORT
      LAYER M4 ;
        RECT  0 59.28 0.192 59.304 ;
    END
  END i[546]
  PIN i[547]
    DIRECTION INPUT ;
    USE SIGNAL ;
    PORT
      LAYER M4 ;
        RECT  0 59.376 0.192 59.4 ;
    END
  END i[547]
  PIN i[548]
    DIRECTION INPUT ;
    USE SIGNAL ;
    PORT
      LAYER M4 ;
        RECT  0 59.52 0.192 59.544 ;
    END
  END i[548]
  PIN i[549]
    DIRECTION INPUT ;
    USE SIGNAL ;
    PORT
      LAYER M4 ;
        RECT  0 59.616 0.192 59.64 ;
    END
  END i[549]
  PIN i[54]
    DIRECTION INPUT ;
    USE SIGNAL ;
    PORT
      LAYER M4 ;
        RECT  0 7.872 0.192 7.896 ;
    END
  END i[54]
  PIN i[550]
    DIRECTION INPUT ;
    USE SIGNAL ;
    PORT
      LAYER M4 ;
        RECT  0 59.712 0.192 59.736 ;
    END
  END i[550]
  PIN i[551]
    DIRECTION INPUT ;
    USE SIGNAL ;
    PORT
      LAYER M4 ;
        RECT  0 59.808 0.192 59.832 ;
    END
  END i[551]
  PIN i[552]
    DIRECTION INPUT ;
    USE SIGNAL ;
    PORT
      LAYER M4 ;
        RECT  0 59.904 0.192 59.928 ;
    END
  END i[552]
  PIN i[553]
    DIRECTION INPUT ;
    USE SIGNAL ;
    PORT
      LAYER M4 ;
        RECT  0 60 0.192 60.024 ;
    END
  END i[553]
  PIN i[554]
    DIRECTION INPUT ;
    USE SIGNAL ;
    PORT
      LAYER M4 ;
        RECT  0 60.144 0.192 60.168 ;
    END
  END i[554]
  PIN i[555]
    DIRECTION INPUT ;
    USE SIGNAL ;
    PORT
      LAYER M4 ;
        RECT  0 60.24 0.192 60.264 ;
    END
  END i[555]
  PIN i[556]
    DIRECTION INPUT ;
    USE SIGNAL ;
    PORT
      LAYER M4 ;
        RECT  0 60.336 0.192 60.36 ;
    END
  END i[556]
  PIN i[557]
    DIRECTION INPUT ;
    USE SIGNAL ;
    PORT
      LAYER M4 ;
        RECT  0 60.432 0.192 60.456 ;
    END
  END i[557]
  PIN i[558]
    DIRECTION INPUT ;
    USE SIGNAL ;
    PORT
      LAYER M4 ;
        RECT  0 60.528 0.192 60.552 ;
    END
  END i[558]
  PIN i[559]
    DIRECTION INPUT ;
    USE SIGNAL ;
    PORT
      LAYER M4 ;
        RECT  0 60.672 0.192 60.696 ;
    END
  END i[559]
  PIN i[55]
    DIRECTION INPUT ;
    USE SIGNAL ;
    PORT
      LAYER M4 ;
        RECT  0 7.968 0.192 7.992 ;
    END
  END i[55]
  PIN i[560]
    DIRECTION INPUT ;
    USE SIGNAL ;
    PORT
      LAYER M4 ;
        RECT  0 60.768 0.192 60.792 ;
    END
  END i[560]
  PIN i[561]
    DIRECTION INPUT ;
    USE SIGNAL ;
    PORT
      LAYER M4 ;
        RECT  0 60.864 0.192 60.888 ;
    END
  END i[561]
  PIN i[562]
    DIRECTION INPUT ;
    USE SIGNAL ;
    PORT
      LAYER M4 ;
        RECT  0 60.96 0.192 60.984 ;
    END
  END i[562]
  PIN i[563]
    DIRECTION INPUT ;
    USE SIGNAL ;
    PORT
      LAYER M4 ;
        RECT  0 61.056 0.192 61.08 ;
    END
  END i[563]
  PIN i[564]
    DIRECTION INPUT ;
    USE SIGNAL ;
    PORT
      LAYER M4 ;
        RECT  0 61.152 0.192 61.176 ;
    END
  END i[564]
  PIN i[565]
    DIRECTION INPUT ;
    USE SIGNAL ;
    PORT
      LAYER M4 ;
        RECT  0 61.296 0.192 61.32 ;
    END
  END i[565]
  PIN i[566]
    DIRECTION INPUT ;
    USE SIGNAL ;
    PORT
      LAYER M4 ;
        RECT  0 61.392 0.192 61.416 ;
    END
  END i[566]
  PIN i[567]
    DIRECTION INPUT ;
    USE SIGNAL ;
    PORT
      LAYER M4 ;
        RECT  0 61.488 0.192 61.512 ;
    END
  END i[567]
  PIN i[568]
    DIRECTION INPUT ;
    USE SIGNAL ;
    PORT
      LAYER M4 ;
        RECT  0 61.584 0.192 61.608 ;
    END
  END i[568]
  PIN i[569]
    DIRECTION INPUT ;
    USE SIGNAL ;
    PORT
      LAYER M4 ;
        RECT  0 61.68 0.192 61.704 ;
    END
  END i[569]
  PIN i[56]
    DIRECTION INPUT ;
    USE SIGNAL ;
    PORT
      LAYER M4 ;
        RECT  0 8.064 0.192 8.088 ;
    END
  END i[56]
  PIN i[570]
    DIRECTION INPUT ;
    USE SIGNAL ;
    PORT
      LAYER M4 ;
        RECT  0 61.776 0.192 61.8 ;
    END
  END i[570]
  PIN i[571]
    DIRECTION INPUT ;
    USE SIGNAL ;
    PORT
      LAYER M4 ;
        RECT  0 61.92 0.192 61.944 ;
    END
  END i[571]
  PIN i[572]
    DIRECTION INPUT ;
    USE SIGNAL ;
    PORT
      LAYER M4 ;
        RECT  0 62.016 0.192 62.04 ;
    END
  END i[572]
  PIN i[573]
    DIRECTION INPUT ;
    USE SIGNAL ;
    PORT
      LAYER M4 ;
        RECT  0 62.112 0.192 62.136 ;
    END
  END i[573]
  PIN i[574]
    DIRECTION INPUT ;
    USE SIGNAL ;
    PORT
      LAYER M4 ;
        RECT  0 62.208 0.192 62.232 ;
    END
  END i[574]
  PIN i[575]
    DIRECTION INPUT ;
    USE SIGNAL ;
    PORT
      LAYER M4 ;
        RECT  0 62.304 0.192 62.328 ;
    END
  END i[575]
  PIN i[576]
    DIRECTION INPUT ;
    USE SIGNAL ;
    PORT
      LAYER M4 ;
        RECT  0 62.448 0.192 62.472 ;
    END
  END i[576]
  PIN i[577]
    DIRECTION INPUT ;
    USE SIGNAL ;
    PORT
      LAYER M4 ;
        RECT  0 62.544 0.192 62.568 ;
    END
  END i[577]
  PIN i[578]
    DIRECTION INPUT ;
    USE SIGNAL ;
    PORT
      LAYER M4 ;
        RECT  0 62.64 0.192 62.664 ;
    END
  END i[578]
  PIN i[579]
    DIRECTION INPUT ;
    USE SIGNAL ;
    PORT
      LAYER M4 ;
        RECT  0 62.736 0.192 62.76 ;
    END
  END i[579]
  PIN i[57]
    DIRECTION INPUT ;
    USE SIGNAL ;
    PORT
      LAYER M4 ;
        RECT  0 8.16 0.192 8.184 ;
    END
  END i[57]
  PIN i[580]
    DIRECTION INPUT ;
    USE SIGNAL ;
    PORT
      LAYER M4 ;
        RECT  0 62.832 0.192 62.856 ;
    END
  END i[580]
  PIN i[581]
    DIRECTION INPUT ;
    USE SIGNAL ;
    PORT
      LAYER M4 ;
        RECT  0 62.928 0.192 62.952 ;
    END
  END i[581]
  PIN i[582]
    DIRECTION INPUT ;
    USE SIGNAL ;
    PORT
      LAYER M4 ;
        RECT  0 63.072 0.192 63.096 ;
    END
  END i[582]
  PIN i[583]
    DIRECTION INPUT ;
    USE SIGNAL ;
    PORT
      LAYER M4 ;
        RECT  0 63.168 0.192 63.192 ;
    END
  END i[583]
  PIN i[584]
    DIRECTION INPUT ;
    USE SIGNAL ;
    PORT
      LAYER M4 ;
        RECT  0 63.264 0.192 63.288 ;
    END
  END i[584]
  PIN i[585]
    DIRECTION INPUT ;
    USE SIGNAL ;
    PORT
      LAYER M4 ;
        RECT  0 63.36 0.192 63.384 ;
    END
  END i[585]
  PIN i[586]
    DIRECTION INPUT ;
    USE SIGNAL ;
    PORT
      LAYER M4 ;
        RECT  0 63.456 0.192 63.48 ;
    END
  END i[586]
  PIN i[587]
    DIRECTION INPUT ;
    USE SIGNAL ;
    PORT
      LAYER M4 ;
        RECT  0 63.552 0.192 63.576 ;
    END
  END i[587]
  PIN i[588]
    DIRECTION INPUT ;
    USE SIGNAL ;
    PORT
      LAYER M4 ;
        RECT  0 63.696 0.192 63.72 ;
    END
  END i[588]
  PIN i[589]
    DIRECTION INPUT ;
    USE SIGNAL ;
    PORT
      LAYER M4 ;
        RECT  0 63.792 0.192 63.816 ;
    END
  END i[589]
  PIN i[58]
    DIRECTION INPUT ;
    USE SIGNAL ;
    PORT
      LAYER M4 ;
        RECT  0 8.304 0.192 8.328 ;
    END
  END i[58]
  PIN i[590]
    DIRECTION INPUT ;
    USE SIGNAL ;
    PORT
      LAYER M4 ;
        RECT  0 63.888 0.192 63.912 ;
    END
  END i[590]
  PIN i[591]
    DIRECTION INPUT ;
    USE SIGNAL ;
    PORT
      LAYER M4 ;
        RECT  0 63.984 0.192 64.008 ;
    END
  END i[591]
  PIN i[592]
    DIRECTION INPUT ;
    USE SIGNAL ;
    PORT
      LAYER M4 ;
        RECT  0 64.08 0.192 64.104 ;
    END
  END i[592]
  PIN i[593]
    DIRECTION INPUT ;
    USE SIGNAL ;
    PORT
      LAYER M4 ;
        RECT  0 64.224 0.192 64.248 ;
    END
  END i[593]
  PIN i[594]
    DIRECTION INPUT ;
    USE SIGNAL ;
    PORT
      LAYER M4 ;
        RECT  0 64.32 0.192 64.344 ;
    END
  END i[594]
  PIN i[595]
    DIRECTION INPUT ;
    USE SIGNAL ;
    PORT
      LAYER M4 ;
        RECT  0 64.416 0.192 64.44 ;
    END
  END i[595]
  PIN i[596]
    DIRECTION INPUT ;
    USE SIGNAL ;
    PORT
      LAYER M4 ;
        RECT  0 64.512 0.192 64.536 ;
    END
  END i[596]
  PIN i[597]
    DIRECTION INPUT ;
    USE SIGNAL ;
    PORT
      LAYER M4 ;
        RECT  0 64.608 0.192 64.632 ;
    END
  END i[597]
  PIN i[598]
    DIRECTION INPUT ;
    USE SIGNAL ;
    PORT
      LAYER M4 ;
        RECT  0 64.704 0.192 64.728 ;
    END
  END i[598]
  PIN i[599]
    DIRECTION INPUT ;
    USE SIGNAL ;
    PORT
      LAYER M4 ;
        RECT  0 64.848 0.192 64.872 ;
    END
  END i[599]
  PIN i[59]
    DIRECTION INPUT ;
    USE SIGNAL ;
    PORT
      LAYER M4 ;
        RECT  0 8.4 0.192 8.424 ;
    END
  END i[59]
  PIN i[5]
    DIRECTION INPUT ;
    USE SIGNAL ;
    PORT
      LAYER M4 ;
        RECT  0 2.736 0.192 2.76 ;
    END
  END i[5]
  PIN i[600]
    DIRECTION INPUT ;
    USE SIGNAL ;
    PORT
      LAYER M4 ;
        RECT  0 64.944 0.192 64.968 ;
    END
  END i[600]
  PIN i[601]
    DIRECTION INPUT ;
    USE SIGNAL ;
    PORT
      LAYER M4 ;
        RECT  0 65.04 0.192 65.064 ;
    END
  END i[601]
  PIN i[602]
    DIRECTION INPUT ;
    USE SIGNAL ;
    PORT
      LAYER M4 ;
        RECT  0 65.136 0.192 65.16 ;
    END
  END i[602]
  PIN i[603]
    DIRECTION INPUT ;
    USE SIGNAL ;
    PORT
      LAYER M4 ;
        RECT  0 65.232 0.192 65.256 ;
    END
  END i[603]
  PIN i[604]
    DIRECTION INPUT ;
    USE SIGNAL ;
    PORT
      LAYER M4 ;
        RECT  0 65.328 0.192 65.352 ;
    END
  END i[604]
  PIN i[605]
    DIRECTION INPUT ;
    USE SIGNAL ;
    PORT
      LAYER M4 ;
        RECT  0 65.472 0.192 65.496 ;
    END
  END i[605]
  PIN i[606]
    DIRECTION INPUT ;
    USE SIGNAL ;
    PORT
      LAYER M4 ;
        RECT  0 65.568 0.192 65.592 ;
    END
  END i[606]
  PIN i[607]
    DIRECTION INPUT ;
    USE SIGNAL ;
    PORT
      LAYER M4 ;
        RECT  0 65.664 0.192 65.688 ;
    END
  END i[607]
  PIN i[608]
    DIRECTION INPUT ;
    USE SIGNAL ;
    PORT
      LAYER M4 ;
        RECT  0 65.76 0.192 65.784 ;
    END
  END i[608]
  PIN i[609]
    DIRECTION INPUT ;
    USE SIGNAL ;
    PORT
      LAYER M4 ;
        RECT  0 65.856 0.192 65.88 ;
    END
  END i[609]
  PIN i[60]
    DIRECTION INPUT ;
    USE SIGNAL ;
    PORT
      LAYER M4 ;
        RECT  0 8.496 0.192 8.52 ;
    END
  END i[60]
  PIN i[610]
    DIRECTION INPUT ;
    USE SIGNAL ;
    PORT
      LAYER M4 ;
        RECT  0 66 0.192 66.024 ;
    END
  END i[610]
  PIN i[611]
    DIRECTION INPUT ;
    USE SIGNAL ;
    PORT
      LAYER M4 ;
        RECT  0 66.096 0.192 66.12 ;
    END
  END i[611]
  PIN i[612]
    DIRECTION INPUT ;
    USE SIGNAL ;
    PORT
      LAYER M4 ;
        RECT  0 66.192 0.192 66.216 ;
    END
  END i[612]
  PIN i[613]
    DIRECTION INPUT ;
    USE SIGNAL ;
    PORT
      LAYER M4 ;
        RECT  0 66.288 0.192 66.312 ;
    END
  END i[613]
  PIN i[614]
    DIRECTION INPUT ;
    USE SIGNAL ;
    PORT
      LAYER M4 ;
        RECT  0 66.384 0.192 66.408 ;
    END
  END i[614]
  PIN i[615]
    DIRECTION INPUT ;
    USE SIGNAL ;
    PORT
      LAYER M4 ;
        RECT  0 66.48 0.192 66.504 ;
    END
  END i[615]
  PIN i[616]
    DIRECTION INPUT ;
    USE SIGNAL ;
    PORT
      LAYER M4 ;
        RECT  0 66.624 0.192 66.648 ;
    END
  END i[616]
  PIN i[617]
    DIRECTION INPUT ;
    USE SIGNAL ;
    PORT
      LAYER M4 ;
        RECT  0 66.72 0.192 66.744 ;
    END
  END i[617]
  PIN i[618]
    DIRECTION INPUT ;
    USE SIGNAL ;
    PORT
      LAYER M4 ;
        RECT  0 66.816 0.192 66.84 ;
    END
  END i[618]
  PIN i[619]
    DIRECTION INPUT ;
    USE SIGNAL ;
    PORT
      LAYER M4 ;
        RECT  0 66.912 0.192 66.936 ;
    END
  END i[619]
  PIN i[61]
    DIRECTION INPUT ;
    USE SIGNAL ;
    PORT
      LAYER M4 ;
        RECT  0 8.592 0.192 8.616 ;
    END
  END i[61]
  PIN i[620]
    DIRECTION INPUT ;
    USE SIGNAL ;
    PORT
      LAYER M4 ;
        RECT  0 67.008 0.192 67.032 ;
    END
  END i[620]
  PIN i[621]
    DIRECTION INPUT ;
    USE SIGNAL ;
    PORT
      LAYER M4 ;
        RECT  0 67.152 0.192 67.176 ;
    END
  END i[621]
  PIN i[622]
    DIRECTION INPUT ;
    USE SIGNAL ;
    PORT
      LAYER M4 ;
        RECT  0 67.248 0.192 67.272 ;
    END
  END i[622]
  PIN i[623]
    DIRECTION INPUT ;
    USE SIGNAL ;
    PORT
      LAYER M4 ;
        RECT  0 67.344 0.192 67.368 ;
    END
  END i[623]
  PIN i[624]
    DIRECTION INPUT ;
    USE SIGNAL ;
    PORT
      LAYER M4 ;
        RECT  0 67.44 0.192 67.464 ;
    END
  END i[624]
  PIN i[625]
    DIRECTION INPUT ;
    USE SIGNAL ;
    PORT
      LAYER M4 ;
        RECT  0 67.536 0.192 67.56 ;
    END
  END i[625]
  PIN i[626]
    DIRECTION INPUT ;
    USE SIGNAL ;
    PORT
      LAYER M4 ;
        RECT  0 67.632 0.192 67.656 ;
    END
  END i[626]
  PIN i[627]
    DIRECTION INPUT ;
    USE SIGNAL ;
    PORT
      LAYER M4 ;
        RECT  0 67.776 0.192 67.8 ;
    END
  END i[627]
  PIN i[628]
    DIRECTION INPUT ;
    USE SIGNAL ;
    PORT
      LAYER M4 ;
        RECT  0 67.872 0.192 67.896 ;
    END
  END i[628]
  PIN i[629]
    DIRECTION INPUT ;
    USE SIGNAL ;
    PORT
      LAYER M4 ;
        RECT  0 67.968 0.192 67.992 ;
    END
  END i[629]
  PIN i[62]
    DIRECTION INPUT ;
    USE SIGNAL ;
    PORT
      LAYER M4 ;
        RECT  0 8.688 0.192 8.712 ;
    END
  END i[62]
  PIN i[630]
    DIRECTION INPUT ;
    USE SIGNAL ;
    PORT
      LAYER M4 ;
        RECT  0 68.064 0.192 68.088 ;
    END
  END i[630]
  PIN i[631]
    DIRECTION INPUT ;
    USE SIGNAL ;
    PORT
      LAYER M4 ;
        RECT  0 68.16 0.192 68.184 ;
    END
  END i[631]
  PIN i[632]
    DIRECTION INPUT ;
    USE SIGNAL ;
    PORT
      LAYER M4 ;
        RECT  0 68.256 0.192 68.28 ;
    END
  END i[632]
  PIN i[633]
    DIRECTION INPUT ;
    USE SIGNAL ;
    PORT
      LAYER M4 ;
        RECT  0 68.4 0.192 68.424 ;
    END
  END i[633]
  PIN i[634]
    DIRECTION INPUT ;
    USE SIGNAL ;
    PORT
      LAYER M4 ;
        RECT  0 68.496 0.192 68.52 ;
    END
  END i[634]
  PIN i[635]
    DIRECTION INPUT ;
    USE SIGNAL ;
    PORT
      LAYER M4 ;
        RECT  0 68.592 0.192 68.616 ;
    END
  END i[635]
  PIN i[636]
    DIRECTION INPUT ;
    USE SIGNAL ;
    PORT
      LAYER M4 ;
        RECT  0 68.688 0.192 68.712 ;
    END
  END i[636]
  PIN i[637]
    DIRECTION INPUT ;
    USE SIGNAL ;
    PORT
      LAYER M4 ;
        RECT  0 68.784 0.192 68.808 ;
    END
  END i[637]
  PIN i[638]
    DIRECTION INPUT ;
    USE SIGNAL ;
    PORT
      LAYER M4 ;
        RECT  0 68.928 0.192 68.952 ;
    END
  END i[638]
  PIN i[639]
    DIRECTION INPUT ;
    USE SIGNAL ;
    PORT
      LAYER M4 ;
        RECT  0 69.024 0.192 69.048 ;
    END
  END i[639]
  PIN i[63]
    DIRECTION INPUT ;
    USE SIGNAL ;
    PORT
      LAYER M4 ;
        RECT  0 8.832 0.192 8.856 ;
    END
  END i[63]
  PIN i[640]
    DIRECTION INPUT ;
    USE SIGNAL ;
    PORT
      LAYER M4 ;
        RECT  0 69.12 0.192 69.144 ;
    END
  END i[640]
  PIN i[641]
    DIRECTION INPUT ;
    USE SIGNAL ;
    PORT
      LAYER M4 ;
        RECT  0 69.216 0.192 69.24 ;
    END
  END i[641]
  PIN i[642]
    DIRECTION INPUT ;
    USE SIGNAL ;
    PORT
      LAYER M4 ;
        RECT  0 69.312 0.192 69.336 ;
    END
  END i[642]
  PIN i[643]
    DIRECTION INPUT ;
    USE SIGNAL ;
    PORT
      LAYER M4 ;
        RECT  0 69.408 0.192 69.432 ;
    END
  END i[643]
  PIN i[644]
    DIRECTION INPUT ;
    USE SIGNAL ;
    PORT
      LAYER M4 ;
        RECT  0 69.552 0.192 69.576 ;
    END
  END i[644]
  PIN i[645]
    DIRECTION INPUT ;
    USE SIGNAL ;
    PORT
      LAYER M4 ;
        RECT  0 69.648 0.192 69.672 ;
    END
  END i[645]
  PIN i[646]
    DIRECTION INPUT ;
    USE SIGNAL ;
    PORT
      LAYER M4 ;
        RECT  0 69.744 0.192 69.768 ;
    END
  END i[646]
  PIN i[647]
    DIRECTION INPUT ;
    USE SIGNAL ;
    PORT
      LAYER M4 ;
        RECT  0 69.84 0.192 69.864 ;
    END
  END i[647]
  PIN i[648]
    DIRECTION INPUT ;
    USE SIGNAL ;
    PORT
      LAYER M4 ;
        RECT  0 69.936 0.192 69.96 ;
    END
  END i[648]
  PIN i[649]
    DIRECTION INPUT ;
    USE SIGNAL ;
    PORT
      LAYER M4 ;
        RECT  0 70.032 0.192 70.056 ;
    END
  END i[649]
  PIN i[64]
    DIRECTION INPUT ;
    USE SIGNAL ;
    PORT
      LAYER M4 ;
        RECT  0 8.928 0.192 8.952 ;
    END
  END i[64]
  PIN i[650]
    DIRECTION INPUT ;
    USE SIGNAL ;
    PORT
      LAYER M4 ;
        RECT  0 70.176 0.192 70.2 ;
    END
  END i[650]
  PIN i[651]
    DIRECTION INPUT ;
    USE SIGNAL ;
    PORT
      LAYER M4 ;
        RECT  0 70.272 0.192 70.296 ;
    END
  END i[651]
  PIN i[652]
    DIRECTION INPUT ;
    USE SIGNAL ;
    PORT
      LAYER M4 ;
        RECT  0 70.368 0.192 70.392 ;
    END
  END i[652]
  PIN i[653]
    DIRECTION INPUT ;
    USE SIGNAL ;
    PORT
      LAYER M4 ;
        RECT  0 70.464 0.192 70.488 ;
    END
  END i[653]
  PIN i[654]
    DIRECTION INPUT ;
    USE SIGNAL ;
    PORT
      LAYER M4 ;
        RECT  0 70.56 0.192 70.584 ;
    END
  END i[654]
  PIN i[655]
    DIRECTION INPUT ;
    USE SIGNAL ;
    PORT
      LAYER M4 ;
        RECT  0 70.704 0.192 70.728 ;
    END
  END i[655]
  PIN i[656]
    DIRECTION INPUT ;
    USE SIGNAL ;
    PORT
      LAYER M4 ;
        RECT  0 70.8 0.192 70.824 ;
    END
  END i[656]
  PIN i[657]
    DIRECTION INPUT ;
    USE SIGNAL ;
    PORT
      LAYER M4 ;
        RECT  0 70.896 0.192 70.92 ;
    END
  END i[657]
  PIN i[658]
    DIRECTION INPUT ;
    USE SIGNAL ;
    PORT
      LAYER M4 ;
        RECT  0 70.992 0.192 71.016 ;
    END
  END i[658]
  PIN i[659]
    DIRECTION INPUT ;
    USE SIGNAL ;
    PORT
      LAYER M4 ;
        RECT  0 71.088 0.192 71.112 ;
    END
  END i[659]
  PIN i[65]
    DIRECTION INPUT ;
    USE SIGNAL ;
    PORT
      LAYER M4 ;
        RECT  0 9.024 0.192 9.048 ;
    END
  END i[65]
  PIN i[660]
    DIRECTION INPUT ;
    USE SIGNAL ;
    PORT
      LAYER M4 ;
        RECT  0 71.184 0.192 71.208 ;
    END
  END i[660]
  PIN i[661]
    DIRECTION INPUT ;
    USE SIGNAL ;
    PORT
      LAYER M4 ;
        RECT  0 71.328 0.192 71.352 ;
    END
  END i[661]
  PIN i[662]
    DIRECTION INPUT ;
    USE SIGNAL ;
    PORT
      LAYER M4 ;
        RECT  0 71.424 0.192 71.448 ;
    END
  END i[662]
  PIN i[663]
    DIRECTION INPUT ;
    USE SIGNAL ;
    PORT
      LAYER M4 ;
        RECT  0 71.52 0.192 71.544 ;
    END
  END i[663]
  PIN i[664]
    DIRECTION INPUT ;
    USE SIGNAL ;
    PORT
      LAYER M4 ;
        RECT  0 71.616 0.192 71.64 ;
    END
  END i[664]
  PIN i[665]
    DIRECTION INPUT ;
    USE SIGNAL ;
    PORT
      LAYER M4 ;
        RECT  0 71.712 0.192 71.736 ;
    END
  END i[665]
  PIN i[666]
    DIRECTION INPUT ;
    USE SIGNAL ;
    PORT
      LAYER M4 ;
        RECT  0 71.856 0.192 71.88 ;
    END
  END i[666]
  PIN i[667]
    DIRECTION INPUT ;
    USE SIGNAL ;
    PORT
      LAYER M4 ;
        RECT  0 71.952 0.192 71.976 ;
    END
  END i[667]
  PIN i[668]
    DIRECTION INPUT ;
    USE SIGNAL ;
    PORT
      LAYER M4 ;
        RECT  0 72.048 0.192 72.072 ;
    END
  END i[668]
  PIN i[669]
    DIRECTION INPUT ;
    USE SIGNAL ;
    PORT
      LAYER M4 ;
        RECT  0 72.144 0.192 72.168 ;
    END
  END i[669]
  PIN i[66]
    DIRECTION INPUT ;
    USE SIGNAL ;
    PORT
      LAYER M4 ;
        RECT  0 9.12 0.192 9.144 ;
    END
  END i[66]
  PIN i[670]
    DIRECTION INPUT ;
    USE SIGNAL ;
    PORT
      LAYER M4 ;
        RECT  0 72.24 0.192 72.264 ;
    END
  END i[670]
  PIN i[671]
    DIRECTION INPUT ;
    USE SIGNAL ;
    PORT
      LAYER M4 ;
        RECT  0 72.336 0.192 72.36 ;
    END
  END i[671]
  PIN i[672]
    DIRECTION INPUT ;
    USE SIGNAL ;
    PORT
      LAYER M4 ;
        RECT  0 72.48 0.192 72.504 ;
    END
  END i[672]
  PIN i[673]
    DIRECTION INPUT ;
    USE SIGNAL ;
    PORT
      LAYER M4 ;
        RECT  0 72.576 0.192 72.6 ;
    END
  END i[673]
  PIN i[674]
    DIRECTION INPUT ;
    USE SIGNAL ;
    PORT
      LAYER M4 ;
        RECT  0 72.672 0.192 72.696 ;
    END
  END i[674]
  PIN i[675]
    DIRECTION INPUT ;
    USE SIGNAL ;
    PORT
      LAYER M4 ;
        RECT  0 72.768 0.192 72.792 ;
    END
  END i[675]
  PIN i[676]
    DIRECTION INPUT ;
    USE SIGNAL ;
    PORT
      LAYER M4 ;
        RECT  0 72.864 0.192 72.888 ;
    END
  END i[676]
  PIN i[677]
    DIRECTION INPUT ;
    USE SIGNAL ;
    PORT
      LAYER M4 ;
        RECT  0 72.96 0.192 72.984 ;
    END
  END i[677]
  PIN i[678]
    DIRECTION INPUT ;
    USE SIGNAL ;
    PORT
      LAYER M4 ;
        RECT  0 73.104 0.192 73.128 ;
    END
  END i[678]
  PIN i[679]
    DIRECTION INPUT ;
    USE SIGNAL ;
    PORT
      LAYER M4 ;
        RECT  0 73.2 0.192 73.224 ;
    END
  END i[679]
  PIN i[67]
    DIRECTION INPUT ;
    USE SIGNAL ;
    PORT
      LAYER M4 ;
        RECT  0 9.216 0.192 9.24 ;
    END
  END i[67]
  PIN i[680]
    DIRECTION INPUT ;
    USE SIGNAL ;
    PORT
      LAYER M4 ;
        RECT  0 73.296 0.192 73.32 ;
    END
  END i[680]
  PIN i[681]
    DIRECTION INPUT ;
    USE SIGNAL ;
    PORT
      LAYER M4 ;
        RECT  0 73.392 0.192 73.416 ;
    END
  END i[681]
  PIN i[68]
    DIRECTION INPUT ;
    USE SIGNAL ;
    PORT
      LAYER M4 ;
        RECT  0 9.312 0.192 9.336 ;
    END
  END i[68]
  PIN i[69]
    DIRECTION INPUT ;
    USE SIGNAL ;
    PORT
      LAYER M4 ;
        RECT  0 9.456 0.192 9.48 ;
    END
  END i[69]
  PIN i[6]
    DIRECTION INPUT ;
    USE SIGNAL ;
    PORT
      LAYER M4 ;
        RECT  0 2.832 0.192 2.856 ;
    END
  END i[6]
  PIN i[70]
    DIRECTION INPUT ;
    USE SIGNAL ;
    PORT
      LAYER M4 ;
        RECT  0 9.552 0.192 9.576 ;
    END
  END i[70]
  PIN i[71]
    DIRECTION INPUT ;
    USE SIGNAL ;
    PORT
      LAYER M4 ;
        RECT  0 9.648 0.192 9.672 ;
    END
  END i[71]
  PIN i[72]
    DIRECTION INPUT ;
    USE SIGNAL ;
    PORT
      LAYER M4 ;
        RECT  0 9.744 0.192 9.768 ;
    END
  END i[72]
  PIN i[73]
    DIRECTION INPUT ;
    USE SIGNAL ;
    PORT
      LAYER M4 ;
        RECT  0 9.84 0.192 9.864 ;
    END
  END i[73]
  PIN i[74]
    DIRECTION INPUT ;
    USE SIGNAL ;
    PORT
      LAYER M4 ;
        RECT  0 9.936 0.192 9.96 ;
    END
  END i[74]
  PIN i[75]
    DIRECTION INPUT ;
    USE SIGNAL ;
    PORT
      LAYER M4 ;
        RECT  0 10.08 0.192 10.104 ;
    END
  END i[75]
  PIN i[76]
    DIRECTION INPUT ;
    USE SIGNAL ;
    PORT
      LAYER M4 ;
        RECT  0 10.176 0.192 10.2 ;
    END
  END i[76]
  PIN i[77]
    DIRECTION INPUT ;
    USE SIGNAL ;
    PORT
      LAYER M4 ;
        RECT  0 10.272 0.192 10.296 ;
    END
  END i[77]
  PIN i[78]
    DIRECTION INPUT ;
    USE SIGNAL ;
    PORT
      LAYER M4 ;
        RECT  0 10.368 0.192 10.392 ;
    END
  END i[78]
  PIN i[79]
    DIRECTION INPUT ;
    USE SIGNAL ;
    PORT
      LAYER M4 ;
        RECT  0 10.464 0.192 10.488 ;
    END
  END i[79]
  PIN i[7]
    DIRECTION INPUT ;
    USE SIGNAL ;
    PORT
      LAYER M4 ;
        RECT  0 2.976 0.192 3 ;
    END
  END i[7]
  PIN i[80]
    DIRECTION INPUT ;
    USE SIGNAL ;
    PORT
      LAYER M4 ;
        RECT  0 10.608 0.192 10.632 ;
    END
  END i[80]
  PIN i[81]
    DIRECTION INPUT ;
    USE SIGNAL ;
    PORT
      LAYER M4 ;
        RECT  0 10.704 0.192 10.728 ;
    END
  END i[81]
  PIN i[82]
    DIRECTION INPUT ;
    USE SIGNAL ;
    PORT
      LAYER M4 ;
        RECT  0 10.8 0.192 10.824 ;
    END
  END i[82]
  PIN i[83]
    DIRECTION INPUT ;
    USE SIGNAL ;
    PORT
      LAYER M4 ;
        RECT  0 10.896 0.192 10.92 ;
    END
  END i[83]
  PIN i[84]
    DIRECTION INPUT ;
    USE SIGNAL ;
    PORT
      LAYER M4 ;
        RECT  0 10.992 0.192 11.016 ;
    END
  END i[84]
  PIN i[85]
    DIRECTION INPUT ;
    USE SIGNAL ;
    PORT
      LAYER M4 ;
        RECT  0 11.088 0.192 11.112 ;
    END
  END i[85]
  PIN i[86]
    DIRECTION INPUT ;
    USE SIGNAL ;
    PORT
      LAYER M4 ;
        RECT  0 11.232 0.192 11.256 ;
    END
  END i[86]
  PIN i[87]
    DIRECTION INPUT ;
    USE SIGNAL ;
    PORT
      LAYER M4 ;
        RECT  0 11.328 0.192 11.352 ;
    END
  END i[87]
  PIN i[88]
    DIRECTION INPUT ;
    USE SIGNAL ;
    PORT
      LAYER M4 ;
        RECT  0 11.424 0.192 11.448 ;
    END
  END i[88]
  PIN i[89]
    DIRECTION INPUT ;
    USE SIGNAL ;
    PORT
      LAYER M4 ;
        RECT  0 11.52 0.192 11.544 ;
    END
  END i[89]
  PIN i[8]
    DIRECTION INPUT ;
    USE SIGNAL ;
    PORT
      LAYER M4 ;
        RECT  0 3.072 0.192 3.096 ;
    END
  END i[8]
  PIN i[90]
    DIRECTION INPUT ;
    USE SIGNAL ;
    PORT
      LAYER M4 ;
        RECT  0 11.616 0.192 11.64 ;
    END
  END i[90]
  PIN i[91]
    DIRECTION INPUT ;
    USE SIGNAL ;
    PORT
      LAYER M4 ;
        RECT  0 11.712 0.192 11.736 ;
    END
  END i[91]
  PIN i[92]
    DIRECTION INPUT ;
    USE SIGNAL ;
    PORT
      LAYER M4 ;
        RECT  0 11.856 0.192 11.88 ;
    END
  END i[92]
  PIN i[93]
    DIRECTION INPUT ;
    USE SIGNAL ;
    PORT
      LAYER M4 ;
        RECT  0 11.952 0.192 11.976 ;
    END
  END i[93]
  PIN i[94]
    DIRECTION INPUT ;
    USE SIGNAL ;
    PORT
      LAYER M4 ;
        RECT  0 12.048 0.192 12.072 ;
    END
  END i[94]
  PIN i[95]
    DIRECTION INPUT ;
    USE SIGNAL ;
    PORT
      LAYER M4 ;
        RECT  0 12.144 0.192 12.168 ;
    END
  END i[95]
  PIN i[96]
    DIRECTION INPUT ;
    USE SIGNAL ;
    PORT
      LAYER M4 ;
        RECT  0 12.24 0.192 12.264 ;
    END
  END i[96]
  PIN i[97]
    DIRECTION INPUT ;
    USE SIGNAL ;
    PORT
      LAYER M4 ;
        RECT  0 12.384 0.192 12.408 ;
    END
  END i[97]
  PIN i[98]
    DIRECTION INPUT ;
    USE SIGNAL ;
    PORT
      LAYER M4 ;
        RECT  0 12.48 0.192 12.504 ;
    END
  END i[98]
  PIN i[99]
    DIRECTION INPUT ;
    USE SIGNAL ;
    PORT
      LAYER M4 ;
        RECT  0 12.576 0.192 12.6 ;
    END
  END i[99]
  PIN i[9]
    DIRECTION INPUT ;
    USE SIGNAL ;
    PORT
      LAYER M4 ;
        RECT  0 3.168 0.192 3.192 ;
    END
  END i[9]
  PIN o[0]
    DIRECTION OUTPUT ;
    USE SIGNAL ;
    PORT
      LAYER M4 ;
        RECT  17.088 2.208 17.28 2.232 ;
    END
  END o[0]
  PIN o[100]
    DIRECTION OUTPUT ;
    USE SIGNAL ;
    PORT
      LAYER M4 ;
        RECT  17.088 12.672 17.28 12.696 ;
    END
  END o[100]
  PIN o[101]
    DIRECTION OUTPUT ;
    USE SIGNAL ;
    PORT
      LAYER M4 ;
        RECT  17.088 12.768 17.28 12.792 ;
    END
  END o[101]
  PIN o[102]
    DIRECTION OUTPUT ;
    USE SIGNAL ;
    PORT
      LAYER M4 ;
        RECT  17.088 12.864 17.28 12.888 ;
    END
  END o[102]
  PIN o[103]
    DIRECTION OUTPUT ;
    USE SIGNAL ;
    PORT
      LAYER M4 ;
        RECT  17.088 12.96 17.28 12.984 ;
    END
  END o[103]
  PIN o[104]
    DIRECTION OUTPUT ;
    USE SIGNAL ;
    PORT
      LAYER M4 ;
        RECT  17.088 13.056 17.28 13.08 ;
    END
  END o[104]
  PIN o[105]
    DIRECTION OUTPUT ;
    USE SIGNAL ;
    PORT
      LAYER M4 ;
        RECT  17.088 13.2 17.28 13.224 ;
    END
  END o[105]
  PIN o[106]
    DIRECTION OUTPUT ;
    USE SIGNAL ;
    PORT
      LAYER M4 ;
        RECT  17.088 13.296 17.28 13.32 ;
    END
  END o[106]
  PIN o[107]
    DIRECTION OUTPUT ;
    USE SIGNAL ;
    PORT
      LAYER M4 ;
        RECT  17.088 13.392 17.28 13.416 ;
    END
  END o[107]
  PIN o[108]
    DIRECTION OUTPUT ;
    USE SIGNAL ;
    PORT
      LAYER M4 ;
        RECT  17.088 13.488 17.28 13.512 ;
    END
  END o[108]
  PIN o[109]
    DIRECTION OUTPUT ;
    USE SIGNAL ;
    PORT
      LAYER M4 ;
        RECT  17.088 13.584 17.28 13.608 ;
    END
  END o[109]
  PIN o[10]
    DIRECTION OUTPUT ;
    USE SIGNAL ;
    PORT
      LAYER M4 ;
        RECT  17.088 3.264 17.28 3.288 ;
    END
  END o[10]
  PIN o[110]
    DIRECTION OUTPUT ;
    USE SIGNAL ;
    PORT
      LAYER M4 ;
        RECT  17.088 13.728 17.28 13.752 ;
    END
  END o[110]
  PIN o[111]
    DIRECTION OUTPUT ;
    USE SIGNAL ;
    PORT
      LAYER M4 ;
        RECT  17.088 13.824 17.28 13.848 ;
    END
  END o[111]
  PIN o[112]
    DIRECTION OUTPUT ;
    USE SIGNAL ;
    PORT
      LAYER M4 ;
        RECT  17.088 13.92 17.28 13.944 ;
    END
  END o[112]
  PIN o[113]
    DIRECTION OUTPUT ;
    USE SIGNAL ;
    PORT
      LAYER M4 ;
        RECT  17.088 14.016 17.28 14.04 ;
    END
  END o[113]
  PIN o[114]
    DIRECTION OUTPUT ;
    USE SIGNAL ;
    PORT
      LAYER M4 ;
        RECT  17.088 14.112 17.28 14.136 ;
    END
  END o[114]
  PIN o[115]
    DIRECTION OUTPUT ;
    USE SIGNAL ;
    PORT
      LAYER M4 ;
        RECT  17.088 14.208 17.28 14.232 ;
    END
  END o[115]
  PIN o[116]
    DIRECTION OUTPUT ;
    USE SIGNAL ;
    PORT
      LAYER M4 ;
        RECT  17.088 14.352 17.28 14.376 ;
    END
  END o[116]
  PIN o[117]
    DIRECTION OUTPUT ;
    USE SIGNAL ;
    PORT
      LAYER M4 ;
        RECT  17.088 14.448 17.28 14.472 ;
    END
  END o[117]
  PIN o[118]
    DIRECTION OUTPUT ;
    USE SIGNAL ;
    PORT
      LAYER M4 ;
        RECT  17.088 14.544 17.28 14.568 ;
    END
  END o[118]
  PIN o[119]
    DIRECTION OUTPUT ;
    USE SIGNAL ;
    PORT
      LAYER M4 ;
        RECT  17.088 14.64 17.28 14.664 ;
    END
  END o[119]
  PIN o[11]
    DIRECTION OUTPUT ;
    USE SIGNAL ;
    PORT
      LAYER M4 ;
        RECT  17.088 3.36 17.28 3.384 ;
    END
  END o[11]
  PIN o[120]
    DIRECTION OUTPUT ;
    USE SIGNAL ;
    PORT
      LAYER M4 ;
        RECT  17.088 14.736 17.28 14.76 ;
    END
  END o[120]
  PIN o[121]
    DIRECTION OUTPUT ;
    USE SIGNAL ;
    PORT
      LAYER M4 ;
        RECT  17.088 14.832 17.28 14.856 ;
    END
  END o[121]
  PIN o[122]
    DIRECTION OUTPUT ;
    USE SIGNAL ;
    PORT
      LAYER M4 ;
        RECT  17.088 14.976 17.28 15 ;
    END
  END o[122]
  PIN o[123]
    DIRECTION OUTPUT ;
    USE SIGNAL ;
    PORT
      LAYER M4 ;
        RECT  17.088 15.072 17.28 15.096 ;
    END
  END o[123]
  PIN o[124]
    DIRECTION OUTPUT ;
    USE SIGNAL ;
    PORT
      LAYER M4 ;
        RECT  17.088 15.168 17.28 15.192 ;
    END
  END o[124]
  PIN o[125]
    DIRECTION OUTPUT ;
    USE SIGNAL ;
    PORT
      LAYER M4 ;
        RECT  17.088 15.264 17.28 15.288 ;
    END
  END o[125]
  PIN o[126]
    DIRECTION OUTPUT ;
    USE SIGNAL ;
    PORT
      LAYER M4 ;
        RECT  17.088 15.36 17.28 15.384 ;
    END
  END o[126]
  PIN o[127]
    DIRECTION OUTPUT ;
    USE SIGNAL ;
    PORT
      LAYER M4 ;
        RECT  17.088 15.456 17.28 15.48 ;
    END
  END o[127]
  PIN o[128]
    DIRECTION OUTPUT ;
    USE SIGNAL ;
    PORT
      LAYER M4 ;
        RECT  17.088 15.6 17.28 15.624 ;
    END
  END o[128]
  PIN o[129]
    DIRECTION OUTPUT ;
    USE SIGNAL ;
    PORT
      LAYER M4 ;
        RECT  17.088 15.696 17.28 15.72 ;
    END
  END o[129]
  PIN o[12]
    DIRECTION OUTPUT ;
    USE SIGNAL ;
    PORT
      LAYER M4 ;
        RECT  17.088 3.456 17.28 3.48 ;
    END
  END o[12]
  PIN o[130]
    DIRECTION OUTPUT ;
    USE SIGNAL ;
    PORT
      LAYER M4 ;
        RECT  17.088 15.792 17.28 15.816 ;
    END
  END o[130]
  PIN o[131]
    DIRECTION OUTPUT ;
    USE SIGNAL ;
    PORT
      LAYER M4 ;
        RECT  17.088 15.888 17.28 15.912 ;
    END
  END o[131]
  PIN o[132]
    DIRECTION OUTPUT ;
    USE SIGNAL ;
    PORT
      LAYER M4 ;
        RECT  17.088 15.984 17.28 16.008 ;
    END
  END o[132]
  PIN o[133]
    DIRECTION OUTPUT ;
    USE SIGNAL ;
    PORT
      LAYER M4 ;
        RECT  17.088 16.128 17.28 16.152 ;
    END
  END o[133]
  PIN o[134]
    DIRECTION OUTPUT ;
    USE SIGNAL ;
    PORT
      LAYER M4 ;
        RECT  17.088 16.224 17.28 16.248 ;
    END
  END o[134]
  PIN o[135]
    DIRECTION OUTPUT ;
    USE SIGNAL ;
    PORT
      LAYER M4 ;
        RECT  17.088 16.32 17.28 16.344 ;
    END
  END o[135]
  PIN o[136]
    DIRECTION OUTPUT ;
    USE SIGNAL ;
    PORT
      LAYER M4 ;
        RECT  17.088 16.416 17.28 16.44 ;
    END
  END o[136]
  PIN o[137]
    DIRECTION OUTPUT ;
    USE SIGNAL ;
    PORT
      LAYER M4 ;
        RECT  17.088 16.512 17.28 16.536 ;
    END
  END o[137]
  PIN o[138]
    DIRECTION OUTPUT ;
    USE SIGNAL ;
    PORT
      LAYER M4 ;
        RECT  17.088 16.608 17.28 16.632 ;
    END
  END o[138]
  PIN o[139]
    DIRECTION OUTPUT ;
    USE SIGNAL ;
    PORT
      LAYER M4 ;
        RECT  17.088 16.752 17.28 16.776 ;
    END
  END o[139]
  PIN o[13]
    DIRECTION OUTPUT ;
    USE SIGNAL ;
    PORT
      LAYER M4 ;
        RECT  17.088 3.6 17.28 3.624 ;
    END
  END o[13]
  PIN o[140]
    DIRECTION OUTPUT ;
    USE SIGNAL ;
    PORT
      LAYER M4 ;
        RECT  17.088 16.848 17.28 16.872 ;
    END
  END o[140]
  PIN o[141]
    DIRECTION OUTPUT ;
    USE SIGNAL ;
    PORT
      LAYER M4 ;
        RECT  17.088 16.944 17.28 16.968 ;
    END
  END o[141]
  PIN o[142]
    DIRECTION OUTPUT ;
    USE SIGNAL ;
    PORT
      LAYER M4 ;
        RECT  17.088 17.04 17.28 17.064 ;
    END
  END o[142]
  PIN o[143]
    DIRECTION OUTPUT ;
    USE SIGNAL ;
    PORT
      LAYER M4 ;
        RECT  17.088 17.136 17.28 17.16 ;
    END
  END o[143]
  PIN o[144]
    DIRECTION OUTPUT ;
    USE SIGNAL ;
    PORT
      LAYER M4 ;
        RECT  17.088 17.232 17.28 17.256 ;
    END
  END o[144]
  PIN o[145]
    DIRECTION OUTPUT ;
    USE SIGNAL ;
    PORT
      LAYER M4 ;
        RECT  17.088 17.376 17.28 17.4 ;
    END
  END o[145]
  PIN o[146]
    DIRECTION OUTPUT ;
    USE SIGNAL ;
    PORT
      LAYER M4 ;
        RECT  17.088 17.472 17.28 17.496 ;
    END
  END o[146]
  PIN o[147]
    DIRECTION OUTPUT ;
    USE SIGNAL ;
    PORT
      LAYER M4 ;
        RECT  17.088 17.568 17.28 17.592 ;
    END
  END o[147]
  PIN o[148]
    DIRECTION OUTPUT ;
    USE SIGNAL ;
    PORT
      LAYER M4 ;
        RECT  17.088 17.664 17.28 17.688 ;
    END
  END o[148]
  PIN o[149]
    DIRECTION OUTPUT ;
    USE SIGNAL ;
    PORT
      LAYER M4 ;
        RECT  17.088 17.76 17.28 17.784 ;
    END
  END o[149]
  PIN o[14]
    DIRECTION OUTPUT ;
    USE SIGNAL ;
    PORT
      LAYER M4 ;
        RECT  17.088 3.696 17.28 3.72 ;
    END
  END o[14]
  PIN o[150]
    DIRECTION OUTPUT ;
    USE SIGNAL ;
    PORT
      LAYER M4 ;
        RECT  17.088 17.856 17.28 17.88 ;
    END
  END o[150]
  PIN o[151]
    DIRECTION OUTPUT ;
    USE SIGNAL ;
    PORT
      LAYER M4 ;
        RECT  17.088 18 17.28 18.024 ;
    END
  END o[151]
  PIN o[152]
    DIRECTION OUTPUT ;
    USE SIGNAL ;
    PORT
      LAYER M4 ;
        RECT  17.088 18.096 17.28 18.12 ;
    END
  END o[152]
  PIN o[153]
    DIRECTION OUTPUT ;
    USE SIGNAL ;
    PORT
      LAYER M4 ;
        RECT  17.088 18.192 17.28 18.216 ;
    END
  END o[153]
  PIN o[154]
    DIRECTION OUTPUT ;
    USE SIGNAL ;
    PORT
      LAYER M4 ;
        RECT  17.088 18.288 17.28 18.312 ;
    END
  END o[154]
  PIN o[155]
    DIRECTION OUTPUT ;
    USE SIGNAL ;
    PORT
      LAYER M4 ;
        RECT  17.088 18.384 17.28 18.408 ;
    END
  END o[155]
  PIN o[156]
    DIRECTION OUTPUT ;
    USE SIGNAL ;
    PORT
      LAYER M4 ;
        RECT  17.088 18.528 17.28 18.552 ;
    END
  END o[156]
  PIN o[157]
    DIRECTION OUTPUT ;
    USE SIGNAL ;
    PORT
      LAYER M4 ;
        RECT  17.088 18.624 17.28 18.648 ;
    END
  END o[157]
  PIN o[158]
    DIRECTION OUTPUT ;
    USE SIGNAL ;
    PORT
      LAYER M4 ;
        RECT  17.088 18.72 17.28 18.744 ;
    END
  END o[158]
  PIN o[159]
    DIRECTION OUTPUT ;
    USE SIGNAL ;
    PORT
      LAYER M4 ;
        RECT  17.088 18.816 17.28 18.84 ;
    END
  END o[159]
  PIN o[15]
    DIRECTION OUTPUT ;
    USE SIGNAL ;
    PORT
      LAYER M4 ;
        RECT  17.088 3.792 17.28 3.816 ;
    END
  END o[15]
  PIN o[160]
    DIRECTION OUTPUT ;
    USE SIGNAL ;
    PORT
      LAYER M4 ;
        RECT  17.088 18.912 17.28 18.936 ;
    END
  END o[160]
  PIN o[161]
    DIRECTION OUTPUT ;
    USE SIGNAL ;
    PORT
      LAYER M4 ;
        RECT  17.088 19.008 17.28 19.032 ;
    END
  END o[161]
  PIN o[162]
    DIRECTION OUTPUT ;
    USE SIGNAL ;
    PORT
      LAYER M4 ;
        RECT  17.088 19.152 17.28 19.176 ;
    END
  END o[162]
  PIN o[163]
    DIRECTION OUTPUT ;
    USE SIGNAL ;
    PORT
      LAYER M4 ;
        RECT  17.088 19.248 17.28 19.272 ;
    END
  END o[163]
  PIN o[164]
    DIRECTION OUTPUT ;
    USE SIGNAL ;
    PORT
      LAYER M4 ;
        RECT  17.088 19.344 17.28 19.368 ;
    END
  END o[164]
  PIN o[165]
    DIRECTION OUTPUT ;
    USE SIGNAL ;
    PORT
      LAYER M4 ;
        RECT  17.088 19.44 17.28 19.464 ;
    END
  END o[165]
  PIN o[166]
    DIRECTION OUTPUT ;
    USE SIGNAL ;
    PORT
      LAYER M4 ;
        RECT  17.088 19.536 17.28 19.56 ;
    END
  END o[166]
  PIN o[167]
    DIRECTION OUTPUT ;
    USE SIGNAL ;
    PORT
      LAYER M4 ;
        RECT  17.088 19.632 17.28 19.656 ;
    END
  END o[167]
  PIN o[168]
    DIRECTION OUTPUT ;
    USE SIGNAL ;
    PORT
      LAYER M4 ;
        RECT  17.088 19.776 17.28 19.8 ;
    END
  END o[168]
  PIN o[169]
    DIRECTION OUTPUT ;
    USE SIGNAL ;
    PORT
      LAYER M4 ;
        RECT  17.088 19.872 17.28 19.896 ;
    END
  END o[169]
  PIN o[16]
    DIRECTION OUTPUT ;
    USE SIGNAL ;
    PORT
      LAYER M4 ;
        RECT  17.088 3.888 17.28 3.912 ;
    END
  END o[16]
  PIN o[170]
    DIRECTION OUTPUT ;
    USE SIGNAL ;
    PORT
      LAYER M4 ;
        RECT  17.088 19.968 17.28 19.992 ;
    END
  END o[170]
  PIN o[171]
    DIRECTION OUTPUT ;
    USE SIGNAL ;
    PORT
      LAYER M4 ;
        RECT  17.088 20.064 17.28 20.088 ;
    END
  END o[171]
  PIN o[172]
    DIRECTION OUTPUT ;
    USE SIGNAL ;
    PORT
      LAYER M4 ;
        RECT  17.088 20.16 17.28 20.184 ;
    END
  END o[172]
  PIN o[173]
    DIRECTION OUTPUT ;
    USE SIGNAL ;
    PORT
      LAYER M4 ;
        RECT  17.088 20.256 17.28 20.28 ;
    END
  END o[173]
  PIN o[174]
    DIRECTION OUTPUT ;
    USE SIGNAL ;
    PORT
      LAYER M4 ;
        RECT  17.088 20.4 17.28 20.424 ;
    END
  END o[174]
  PIN o[175]
    DIRECTION OUTPUT ;
    USE SIGNAL ;
    PORT
      LAYER M4 ;
        RECT  17.088 20.496 17.28 20.52 ;
    END
  END o[175]
  PIN o[176]
    DIRECTION OUTPUT ;
    USE SIGNAL ;
    PORT
      LAYER M4 ;
        RECT  17.088 20.592 17.28 20.616 ;
    END
  END o[176]
  PIN o[177]
    DIRECTION OUTPUT ;
    USE SIGNAL ;
    PORT
      LAYER M4 ;
        RECT  17.088 20.688 17.28 20.712 ;
    END
  END o[177]
  PIN o[178]
    DIRECTION OUTPUT ;
    USE SIGNAL ;
    PORT
      LAYER M4 ;
        RECT  17.088 20.784 17.28 20.808 ;
    END
  END o[178]
  PIN o[179]
    DIRECTION OUTPUT ;
    USE SIGNAL ;
    PORT
      LAYER M4 ;
        RECT  17.088 20.928 17.28 20.952 ;
    END
  END o[179]
  PIN o[17]
    DIRECTION OUTPUT ;
    USE SIGNAL ;
    PORT
      LAYER M4 ;
        RECT  17.088 3.984 17.28 4.008 ;
    END
  END o[17]
  PIN o[180]
    DIRECTION OUTPUT ;
    USE SIGNAL ;
    PORT
      LAYER M4 ;
        RECT  17.088 21.024 17.28 21.048 ;
    END
  END o[180]
  PIN o[181]
    DIRECTION OUTPUT ;
    USE SIGNAL ;
    PORT
      LAYER M4 ;
        RECT  17.088 21.12 17.28 21.144 ;
    END
  END o[181]
  PIN o[182]
    DIRECTION OUTPUT ;
    USE SIGNAL ;
    PORT
      LAYER M4 ;
        RECT  17.088 21.216 17.28 21.24 ;
    END
  END o[182]
  PIN o[183]
    DIRECTION OUTPUT ;
    USE SIGNAL ;
    PORT
      LAYER M4 ;
        RECT  17.088 21.312 17.28 21.336 ;
    END
  END o[183]
  PIN o[184]
    DIRECTION OUTPUT ;
    USE SIGNAL ;
    PORT
      LAYER M4 ;
        RECT  17.088 21.408 17.28 21.432 ;
    END
  END o[184]
  PIN o[185]
    DIRECTION OUTPUT ;
    USE SIGNAL ;
    PORT
      LAYER M4 ;
        RECT  17.088 21.552 17.28 21.576 ;
    END
  END o[185]
  PIN o[186]
    DIRECTION OUTPUT ;
    USE SIGNAL ;
    PORT
      LAYER M4 ;
        RECT  17.088 21.648 17.28 21.672 ;
    END
  END o[186]
  PIN o[187]
    DIRECTION OUTPUT ;
    USE SIGNAL ;
    PORT
      LAYER M4 ;
        RECT  17.088 21.744 17.28 21.768 ;
    END
  END o[187]
  PIN o[188]
    DIRECTION OUTPUT ;
    USE SIGNAL ;
    PORT
      LAYER M4 ;
        RECT  17.088 21.84 17.28 21.864 ;
    END
  END o[188]
  PIN o[189]
    DIRECTION OUTPUT ;
    USE SIGNAL ;
    PORT
      LAYER M4 ;
        RECT  17.088 21.936 17.28 21.96 ;
    END
  END o[189]
  PIN o[18]
    DIRECTION OUTPUT ;
    USE SIGNAL ;
    PORT
      LAYER M4 ;
        RECT  17.088 4.08 17.28 4.104 ;
    END
  END o[18]
  PIN o[190]
    DIRECTION OUTPUT ;
    USE SIGNAL ;
    PORT
      LAYER M4 ;
        RECT  17.088 22.032 17.28 22.056 ;
    END
  END o[190]
  PIN o[191]
    DIRECTION OUTPUT ;
    USE SIGNAL ;
    PORT
      LAYER M4 ;
        RECT  17.088 22.176 17.28 22.2 ;
    END
  END o[191]
  PIN o[192]
    DIRECTION OUTPUT ;
    USE SIGNAL ;
    PORT
      LAYER M4 ;
        RECT  17.088 22.272 17.28 22.296 ;
    END
  END o[192]
  PIN o[193]
    DIRECTION OUTPUT ;
    USE SIGNAL ;
    PORT
      LAYER M4 ;
        RECT  17.088 22.368 17.28 22.392 ;
    END
  END o[193]
  PIN o[194]
    DIRECTION OUTPUT ;
    USE SIGNAL ;
    PORT
      LAYER M4 ;
        RECT  17.088 22.464 17.28 22.488 ;
    END
  END o[194]
  PIN o[195]
    DIRECTION OUTPUT ;
    USE SIGNAL ;
    PORT
      LAYER M4 ;
        RECT  17.088 22.56 17.28 22.584 ;
    END
  END o[195]
  PIN o[196]
    DIRECTION OUTPUT ;
    USE SIGNAL ;
    PORT
      LAYER M4 ;
        RECT  17.088 22.656 17.28 22.68 ;
    END
  END o[196]
  PIN o[197]
    DIRECTION OUTPUT ;
    USE SIGNAL ;
    PORT
      LAYER M4 ;
        RECT  17.088 22.8 17.28 22.824 ;
    END
  END o[197]
  PIN o[198]
    DIRECTION OUTPUT ;
    USE SIGNAL ;
    PORT
      LAYER M4 ;
        RECT  17.088 22.896 17.28 22.92 ;
    END
  END o[198]
  PIN o[199]
    DIRECTION OUTPUT ;
    USE SIGNAL ;
    PORT
      LAYER M4 ;
        RECT  17.088 22.992 17.28 23.016 ;
    END
  END o[199]
  PIN o[19]
    DIRECTION OUTPUT ;
    USE SIGNAL ;
    PORT
      LAYER M4 ;
        RECT  17.088 4.224 17.28 4.248 ;
    END
  END o[19]
  PIN o[1]
    DIRECTION OUTPUT ;
    USE SIGNAL ;
    PORT
      LAYER M4 ;
        RECT  17.088 2.352 17.28 2.376 ;
    END
  END o[1]
  PIN o[200]
    DIRECTION OUTPUT ;
    USE SIGNAL ;
    PORT
      LAYER M4 ;
        RECT  17.088 23.088 17.28 23.112 ;
    END
  END o[200]
  PIN o[201]
    DIRECTION OUTPUT ;
    USE SIGNAL ;
    PORT
      LAYER M4 ;
        RECT  17.088 23.184 17.28 23.208 ;
    END
  END o[201]
  PIN o[202]
    DIRECTION OUTPUT ;
    USE SIGNAL ;
    PORT
      LAYER M4 ;
        RECT  17.088 23.328 17.28 23.352 ;
    END
  END o[202]
  PIN o[203]
    DIRECTION OUTPUT ;
    USE SIGNAL ;
    PORT
      LAYER M4 ;
        RECT  17.088 23.424 17.28 23.448 ;
    END
  END o[203]
  PIN o[204]
    DIRECTION OUTPUT ;
    USE SIGNAL ;
    PORT
      LAYER M4 ;
        RECT  17.088 23.52 17.28 23.544 ;
    END
  END o[204]
  PIN o[205]
    DIRECTION OUTPUT ;
    USE SIGNAL ;
    PORT
      LAYER M4 ;
        RECT  17.088 23.616 17.28 23.64 ;
    END
  END o[205]
  PIN o[206]
    DIRECTION OUTPUT ;
    USE SIGNAL ;
    PORT
      LAYER M4 ;
        RECT  17.088 23.712 17.28 23.736 ;
    END
  END o[206]
  PIN o[207]
    DIRECTION OUTPUT ;
    USE SIGNAL ;
    PORT
      LAYER M4 ;
        RECT  17.088 23.808 17.28 23.832 ;
    END
  END o[207]
  PIN o[208]
    DIRECTION OUTPUT ;
    USE SIGNAL ;
    PORT
      LAYER M4 ;
        RECT  17.088 23.952 17.28 23.976 ;
    END
  END o[208]
  PIN o[209]
    DIRECTION OUTPUT ;
    USE SIGNAL ;
    PORT
      LAYER M4 ;
        RECT  17.088 24.048 17.28 24.072 ;
    END
  END o[209]
  PIN o[20]
    DIRECTION OUTPUT ;
    USE SIGNAL ;
    PORT
      LAYER M4 ;
        RECT  17.088 4.32 17.28 4.344 ;
    END
  END o[20]
  PIN o[210]
    DIRECTION OUTPUT ;
    USE SIGNAL ;
    PORT
      LAYER M4 ;
        RECT  17.088 24.144 17.28 24.168 ;
    END
  END o[210]
  PIN o[211]
    DIRECTION OUTPUT ;
    USE SIGNAL ;
    PORT
      LAYER M4 ;
        RECT  17.088 24.24 17.28 24.264 ;
    END
  END o[211]
  PIN o[212]
    DIRECTION OUTPUT ;
    USE SIGNAL ;
    PORT
      LAYER M4 ;
        RECT  17.088 24.336 17.28 24.36 ;
    END
  END o[212]
  PIN o[213]
    DIRECTION OUTPUT ;
    USE SIGNAL ;
    PORT
      LAYER M4 ;
        RECT  17.088 24.432 17.28 24.456 ;
    END
  END o[213]
  PIN o[214]
    DIRECTION OUTPUT ;
    USE SIGNAL ;
    PORT
      LAYER M4 ;
        RECT  17.088 24.576 17.28 24.6 ;
    END
  END o[214]
  PIN o[215]
    DIRECTION OUTPUT ;
    USE SIGNAL ;
    PORT
      LAYER M4 ;
        RECT  17.088 24.672 17.28 24.696 ;
    END
  END o[215]
  PIN o[216]
    DIRECTION OUTPUT ;
    USE SIGNAL ;
    PORT
      LAYER M4 ;
        RECT  17.088 24.768 17.28 24.792 ;
    END
  END o[216]
  PIN o[217]
    DIRECTION OUTPUT ;
    USE SIGNAL ;
    PORT
      LAYER M4 ;
        RECT  17.088 24.864 17.28 24.888 ;
    END
  END o[217]
  PIN o[218]
    DIRECTION OUTPUT ;
    USE SIGNAL ;
    PORT
      LAYER M4 ;
        RECT  17.088 24.96 17.28 24.984 ;
    END
  END o[218]
  PIN o[219]
    DIRECTION OUTPUT ;
    USE SIGNAL ;
    PORT
      LAYER M4 ;
        RECT  17.088 25.056 17.28 25.08 ;
    END
  END o[219]
  PIN o[21]
    DIRECTION OUTPUT ;
    USE SIGNAL ;
    PORT
      LAYER M4 ;
        RECT  17.088 4.416 17.28 4.44 ;
    END
  END o[21]
  PIN o[220]
    DIRECTION OUTPUT ;
    USE SIGNAL ;
    PORT
      LAYER M4 ;
        RECT  17.088 25.2 17.28 25.224 ;
    END
  END o[220]
  PIN o[221]
    DIRECTION OUTPUT ;
    USE SIGNAL ;
    PORT
      LAYER M4 ;
        RECT  17.088 25.296 17.28 25.32 ;
    END
  END o[221]
  PIN o[222]
    DIRECTION OUTPUT ;
    USE SIGNAL ;
    PORT
      LAYER M4 ;
        RECT  17.088 25.392 17.28 25.416 ;
    END
  END o[222]
  PIN o[223]
    DIRECTION OUTPUT ;
    USE SIGNAL ;
    PORT
      LAYER M4 ;
        RECT  17.088 25.488 17.28 25.512 ;
    END
  END o[223]
  PIN o[224]
    DIRECTION OUTPUT ;
    USE SIGNAL ;
    PORT
      LAYER M4 ;
        RECT  17.088 25.584 17.28 25.608 ;
    END
  END o[224]
  PIN o[225]
    DIRECTION OUTPUT ;
    USE SIGNAL ;
    PORT
      LAYER M4 ;
        RECT  17.088 25.728 17.28 25.752 ;
    END
  END o[225]
  PIN o[226]
    DIRECTION OUTPUT ;
    USE SIGNAL ;
    PORT
      LAYER M4 ;
        RECT  17.088 25.824 17.28 25.848 ;
    END
  END o[226]
  PIN o[227]
    DIRECTION OUTPUT ;
    USE SIGNAL ;
    PORT
      LAYER M4 ;
        RECT  17.088 25.92 17.28 25.944 ;
    END
  END o[227]
  PIN o[228]
    DIRECTION OUTPUT ;
    USE SIGNAL ;
    PORT
      LAYER M4 ;
        RECT  17.088 26.016 17.28 26.04 ;
    END
  END o[228]
  PIN o[229]
    DIRECTION OUTPUT ;
    USE SIGNAL ;
    PORT
      LAYER M4 ;
        RECT  17.088 26.112 17.28 26.136 ;
    END
  END o[229]
  PIN o[22]
    DIRECTION OUTPUT ;
    USE SIGNAL ;
    PORT
      LAYER M4 ;
        RECT  17.088 4.512 17.28 4.536 ;
    END
  END o[22]
  PIN o[230]
    DIRECTION OUTPUT ;
    USE SIGNAL ;
    PORT
      LAYER M4 ;
        RECT  17.088 26.208 17.28 26.232 ;
    END
  END o[230]
  PIN o[231]
    DIRECTION OUTPUT ;
    USE SIGNAL ;
    PORT
      LAYER M4 ;
        RECT  17.088 26.352 17.28 26.376 ;
    END
  END o[231]
  PIN o[232]
    DIRECTION OUTPUT ;
    USE SIGNAL ;
    PORT
      LAYER M4 ;
        RECT  17.088 26.448 17.28 26.472 ;
    END
  END o[232]
  PIN o[233]
    DIRECTION OUTPUT ;
    USE SIGNAL ;
    PORT
      LAYER M4 ;
        RECT  17.088 26.544 17.28 26.568 ;
    END
  END o[233]
  PIN o[234]
    DIRECTION OUTPUT ;
    USE SIGNAL ;
    PORT
      LAYER M4 ;
        RECT  17.088 26.64 17.28 26.664 ;
    END
  END o[234]
  PIN o[235]
    DIRECTION OUTPUT ;
    USE SIGNAL ;
    PORT
      LAYER M4 ;
        RECT  17.088 26.736 17.28 26.76 ;
    END
  END o[235]
  PIN o[236]
    DIRECTION OUTPUT ;
    USE SIGNAL ;
    PORT
      LAYER M4 ;
        RECT  17.088 26.832 17.28 26.856 ;
    END
  END o[236]
  PIN o[237]
    DIRECTION OUTPUT ;
    USE SIGNAL ;
    PORT
      LAYER M4 ;
        RECT  17.088 26.976 17.28 27 ;
    END
  END o[237]
  PIN o[238]
    DIRECTION OUTPUT ;
    USE SIGNAL ;
    PORT
      LAYER M4 ;
        RECT  17.088 27.072 17.28 27.096 ;
    END
  END o[238]
  PIN o[239]
    DIRECTION OUTPUT ;
    USE SIGNAL ;
    PORT
      LAYER M4 ;
        RECT  17.088 27.168 17.28 27.192 ;
    END
  END o[239]
  PIN o[23]
    DIRECTION OUTPUT ;
    USE SIGNAL ;
    PORT
      LAYER M4 ;
        RECT  17.088 4.608 17.28 4.632 ;
    END
  END o[23]
  PIN o[240]
    DIRECTION OUTPUT ;
    USE SIGNAL ;
    PORT
      LAYER M4 ;
        RECT  17.088 27.264 17.28 27.288 ;
    END
  END o[240]
  PIN o[241]
    DIRECTION OUTPUT ;
    USE SIGNAL ;
    PORT
      LAYER M4 ;
        RECT  17.088 27.36 17.28 27.384 ;
    END
  END o[241]
  PIN o[242]
    DIRECTION OUTPUT ;
    USE SIGNAL ;
    PORT
      LAYER M4 ;
        RECT  17.088 27.504 17.28 27.528 ;
    END
  END o[242]
  PIN o[243]
    DIRECTION OUTPUT ;
    USE SIGNAL ;
    PORT
      LAYER M4 ;
        RECT  17.088 27.6 17.28 27.624 ;
    END
  END o[243]
  PIN o[244]
    DIRECTION OUTPUT ;
    USE SIGNAL ;
    PORT
      LAYER M4 ;
        RECT  17.088 27.696 17.28 27.72 ;
    END
  END o[244]
  PIN o[245]
    DIRECTION OUTPUT ;
    USE SIGNAL ;
    PORT
      LAYER M4 ;
        RECT  17.088 27.792 17.28 27.816 ;
    END
  END o[245]
  PIN o[246]
    DIRECTION OUTPUT ;
    USE SIGNAL ;
    PORT
      LAYER M4 ;
        RECT  17.088 27.888 17.28 27.912 ;
    END
  END o[246]
  PIN o[247]
    DIRECTION OUTPUT ;
    USE SIGNAL ;
    PORT
      LAYER M4 ;
        RECT  17.088 27.984 17.28 28.008 ;
    END
  END o[247]
  PIN o[248]
    DIRECTION OUTPUT ;
    USE SIGNAL ;
    PORT
      LAYER M4 ;
        RECT  17.088 28.128 17.28 28.152 ;
    END
  END o[248]
  PIN o[249]
    DIRECTION OUTPUT ;
    USE SIGNAL ;
    PORT
      LAYER M4 ;
        RECT  17.088 28.224 17.28 28.248 ;
    END
  END o[249]
  PIN o[24]
    DIRECTION OUTPUT ;
    USE SIGNAL ;
    PORT
      LAYER M4 ;
        RECT  17.088 4.752 17.28 4.776 ;
    END
  END o[24]
  PIN o[250]
    DIRECTION OUTPUT ;
    USE SIGNAL ;
    PORT
      LAYER M4 ;
        RECT  17.088 28.32 17.28 28.344 ;
    END
  END o[250]
  PIN o[251]
    DIRECTION OUTPUT ;
    USE SIGNAL ;
    PORT
      LAYER M4 ;
        RECT  17.088 28.416 17.28 28.44 ;
    END
  END o[251]
  PIN o[252]
    DIRECTION OUTPUT ;
    USE SIGNAL ;
    PORT
      LAYER M4 ;
        RECT  17.088 28.512 17.28 28.536 ;
    END
  END o[252]
  PIN o[253]
    DIRECTION OUTPUT ;
    USE SIGNAL ;
    PORT
      LAYER M4 ;
        RECT  17.088 28.608 17.28 28.632 ;
    END
  END o[253]
  PIN o[254]
    DIRECTION OUTPUT ;
    USE SIGNAL ;
    PORT
      LAYER M4 ;
        RECT  17.088 28.752 17.28 28.776 ;
    END
  END o[254]
  PIN o[255]
    DIRECTION OUTPUT ;
    USE SIGNAL ;
    PORT
      LAYER M4 ;
        RECT  17.088 28.848 17.28 28.872 ;
    END
  END o[255]
  PIN o[256]
    DIRECTION OUTPUT ;
    USE SIGNAL ;
    PORT
      LAYER M4 ;
        RECT  17.088 28.944 17.28 28.968 ;
    END
  END o[256]
  PIN o[257]
    DIRECTION OUTPUT ;
    USE SIGNAL ;
    PORT
      LAYER M4 ;
        RECT  17.088 29.04 17.28 29.064 ;
    END
  END o[257]
  PIN o[258]
    DIRECTION OUTPUT ;
    USE SIGNAL ;
    PORT
      LAYER M4 ;
        RECT  17.088 29.136 17.28 29.16 ;
    END
  END o[258]
  PIN o[259]
    DIRECTION OUTPUT ;
    USE SIGNAL ;
    PORT
      LAYER M4 ;
        RECT  17.088 29.232 17.28 29.256 ;
    END
  END o[259]
  PIN o[25]
    DIRECTION OUTPUT ;
    USE SIGNAL ;
    PORT
      LAYER M4 ;
        RECT  17.088 4.848 17.28 4.872 ;
    END
  END o[25]
  PIN o[260]
    DIRECTION OUTPUT ;
    USE SIGNAL ;
    PORT
      LAYER M4 ;
        RECT  17.088 29.376 17.28 29.4 ;
    END
  END o[260]
  PIN o[261]
    DIRECTION OUTPUT ;
    USE SIGNAL ;
    PORT
      LAYER M4 ;
        RECT  17.088 29.472 17.28 29.496 ;
    END
  END o[261]
  PIN o[262]
    DIRECTION OUTPUT ;
    USE SIGNAL ;
    PORT
      LAYER M4 ;
        RECT  17.088 29.568 17.28 29.592 ;
    END
  END o[262]
  PIN o[263]
    DIRECTION OUTPUT ;
    USE SIGNAL ;
    PORT
      LAYER M4 ;
        RECT  17.088 29.664 17.28 29.688 ;
    END
  END o[263]
  PIN o[264]
    DIRECTION OUTPUT ;
    USE SIGNAL ;
    PORT
      LAYER M4 ;
        RECT  17.088 29.76 17.28 29.784 ;
    END
  END o[264]
  PIN o[265]
    DIRECTION OUTPUT ;
    USE SIGNAL ;
    PORT
      LAYER M4 ;
        RECT  17.088 29.904 17.28 29.928 ;
    END
  END o[265]
  PIN o[266]
    DIRECTION OUTPUT ;
    USE SIGNAL ;
    PORT
      LAYER M4 ;
        RECT  17.088 30 17.28 30.024 ;
    END
  END o[266]
  PIN o[267]
    DIRECTION OUTPUT ;
    USE SIGNAL ;
    PORT
      LAYER M4 ;
        RECT  17.088 30.096 17.28 30.12 ;
    END
  END o[267]
  PIN o[268]
    DIRECTION OUTPUT ;
    USE SIGNAL ;
    PORT
      LAYER M4 ;
        RECT  17.088 30.192 17.28 30.216 ;
    END
  END o[268]
  PIN o[269]
    DIRECTION OUTPUT ;
    USE SIGNAL ;
    PORT
      LAYER M4 ;
        RECT  17.088 30.288 17.28 30.312 ;
    END
  END o[269]
  PIN o[26]
    DIRECTION OUTPUT ;
    USE SIGNAL ;
    PORT
      LAYER M4 ;
        RECT  17.088 4.944 17.28 4.968 ;
    END
  END o[26]
  PIN o[270]
    DIRECTION OUTPUT ;
    USE SIGNAL ;
    PORT
      LAYER M4 ;
        RECT  17.088 30.384 17.28 30.408 ;
    END
  END o[270]
  PIN o[271]
    DIRECTION OUTPUT ;
    USE SIGNAL ;
    PORT
      LAYER M4 ;
        RECT  17.088 30.528 17.28 30.552 ;
    END
  END o[271]
  PIN o[272]
    DIRECTION OUTPUT ;
    USE SIGNAL ;
    PORT
      LAYER M4 ;
        RECT  17.088 30.624 17.28 30.648 ;
    END
  END o[272]
  PIN o[273]
    DIRECTION OUTPUT ;
    USE SIGNAL ;
    PORT
      LAYER M4 ;
        RECT  17.088 30.72 17.28 30.744 ;
    END
  END o[273]
  PIN o[274]
    DIRECTION OUTPUT ;
    USE SIGNAL ;
    PORT
      LAYER M4 ;
        RECT  17.088 30.816 17.28 30.84 ;
    END
  END o[274]
  PIN o[275]
    DIRECTION OUTPUT ;
    USE SIGNAL ;
    PORT
      LAYER M4 ;
        RECT  17.088 30.912 17.28 30.936 ;
    END
  END o[275]
  PIN o[276]
    DIRECTION OUTPUT ;
    USE SIGNAL ;
    PORT
      LAYER M4 ;
        RECT  17.088 31.008 17.28 31.032 ;
    END
  END o[276]
  PIN o[277]
    DIRECTION OUTPUT ;
    USE SIGNAL ;
    PORT
      LAYER M4 ;
        RECT  17.088 31.152 17.28 31.176 ;
    END
  END o[277]
  PIN o[278]
    DIRECTION OUTPUT ;
    USE SIGNAL ;
    PORT
      LAYER M4 ;
        RECT  17.088 31.248 17.28 31.272 ;
    END
  END o[278]
  PIN o[279]
    DIRECTION OUTPUT ;
    USE SIGNAL ;
    PORT
      LAYER M4 ;
        RECT  17.088 31.344 17.28 31.368 ;
    END
  END o[279]
  PIN o[27]
    DIRECTION OUTPUT ;
    USE SIGNAL ;
    PORT
      LAYER M4 ;
        RECT  17.088 5.04 17.28 5.064 ;
    END
  END o[27]
  PIN o[280]
    DIRECTION OUTPUT ;
    USE SIGNAL ;
    PORT
      LAYER M4 ;
        RECT  17.088 31.44 17.28 31.464 ;
    END
  END o[280]
  PIN o[281]
    DIRECTION OUTPUT ;
    USE SIGNAL ;
    PORT
      LAYER M4 ;
        RECT  17.088 31.536 17.28 31.56 ;
    END
  END o[281]
  PIN o[282]
    DIRECTION OUTPUT ;
    USE SIGNAL ;
    PORT
      LAYER M4 ;
        RECT  17.088 31.632 17.28 31.656 ;
    END
  END o[282]
  PIN o[283]
    DIRECTION OUTPUT ;
    USE SIGNAL ;
    PORT
      LAYER M4 ;
        RECT  17.088 31.776 17.28 31.8 ;
    END
  END o[283]
  PIN o[284]
    DIRECTION OUTPUT ;
    USE SIGNAL ;
    PORT
      LAYER M4 ;
        RECT  17.088 31.872 17.28 31.896 ;
    END
  END o[284]
  PIN o[285]
    DIRECTION OUTPUT ;
    USE SIGNAL ;
    PORT
      LAYER M4 ;
        RECT  17.088 31.968 17.28 31.992 ;
    END
  END o[285]
  PIN o[286]
    DIRECTION OUTPUT ;
    USE SIGNAL ;
    PORT
      LAYER M4 ;
        RECT  17.088 32.064 17.28 32.088 ;
    END
  END o[286]
  PIN o[287]
    DIRECTION OUTPUT ;
    USE SIGNAL ;
    PORT
      LAYER M4 ;
        RECT  17.088 32.16 17.28 32.184 ;
    END
  END o[287]
  PIN o[288]
    DIRECTION OUTPUT ;
    USE SIGNAL ;
    PORT
      LAYER M4 ;
        RECT  17.088 32.304 17.28 32.328 ;
    END
  END o[288]
  PIN o[289]
    DIRECTION OUTPUT ;
    USE SIGNAL ;
    PORT
      LAYER M4 ;
        RECT  17.088 32.4 17.28 32.424 ;
    END
  END o[289]
  PIN o[28]
    DIRECTION OUTPUT ;
    USE SIGNAL ;
    PORT
      LAYER M4 ;
        RECT  17.088 5.136 17.28 5.16 ;
    END
  END o[28]
  PIN o[290]
    DIRECTION OUTPUT ;
    USE SIGNAL ;
    PORT
      LAYER M4 ;
        RECT  17.088 32.496 17.28 32.52 ;
    END
  END o[290]
  PIN o[291]
    DIRECTION OUTPUT ;
    USE SIGNAL ;
    PORT
      LAYER M4 ;
        RECT  17.088 32.592 17.28 32.616 ;
    END
  END o[291]
  PIN o[292]
    DIRECTION OUTPUT ;
    USE SIGNAL ;
    PORT
      LAYER M4 ;
        RECT  17.088 32.688 17.28 32.712 ;
    END
  END o[292]
  PIN o[293]
    DIRECTION OUTPUT ;
    USE SIGNAL ;
    PORT
      LAYER M4 ;
        RECT  17.088 32.784 17.28 32.808 ;
    END
  END o[293]
  PIN o[294]
    DIRECTION OUTPUT ;
    USE SIGNAL ;
    PORT
      LAYER M4 ;
        RECT  17.088 32.928 17.28 32.952 ;
    END
  END o[294]
  PIN o[295]
    DIRECTION OUTPUT ;
    USE SIGNAL ;
    PORT
      LAYER M4 ;
        RECT  17.088 33.024 17.28 33.048 ;
    END
  END o[295]
  PIN o[296]
    DIRECTION OUTPUT ;
    USE SIGNAL ;
    PORT
      LAYER M4 ;
        RECT  17.088 33.12 17.28 33.144 ;
    END
  END o[296]
  PIN o[297]
    DIRECTION OUTPUT ;
    USE SIGNAL ;
    PORT
      LAYER M4 ;
        RECT  17.088 33.216 17.28 33.24 ;
    END
  END o[297]
  PIN o[298]
    DIRECTION OUTPUT ;
    USE SIGNAL ;
    PORT
      LAYER M4 ;
        RECT  17.088 33.312 17.28 33.336 ;
    END
  END o[298]
  PIN o[299]
    DIRECTION OUTPUT ;
    USE SIGNAL ;
    PORT
      LAYER M4 ;
        RECT  17.088 33.408 17.28 33.432 ;
    END
  END o[299]
  PIN o[29]
    DIRECTION OUTPUT ;
    USE SIGNAL ;
    PORT
      LAYER M4 ;
        RECT  17.088 5.232 17.28 5.256 ;
    END
  END o[29]
  PIN o[2]
    DIRECTION OUTPUT ;
    USE SIGNAL ;
    PORT
      LAYER M4 ;
        RECT  17.088 2.448 17.28 2.472 ;
    END
  END o[2]
  PIN o[300]
    DIRECTION OUTPUT ;
    USE SIGNAL ;
    PORT
      LAYER M4 ;
        RECT  17.088 33.552 17.28 33.576 ;
    END
  END o[300]
  PIN o[301]
    DIRECTION OUTPUT ;
    USE SIGNAL ;
    PORT
      LAYER M4 ;
        RECT  17.088 33.648 17.28 33.672 ;
    END
  END o[301]
  PIN o[302]
    DIRECTION OUTPUT ;
    USE SIGNAL ;
    PORT
      LAYER M4 ;
        RECT  17.088 33.744 17.28 33.768 ;
    END
  END o[302]
  PIN o[303]
    DIRECTION OUTPUT ;
    USE SIGNAL ;
    PORT
      LAYER M4 ;
        RECT  17.088 33.84 17.28 33.864 ;
    END
  END o[303]
  PIN o[304]
    DIRECTION OUTPUT ;
    USE SIGNAL ;
    PORT
      LAYER M4 ;
        RECT  17.088 33.936 17.28 33.96 ;
    END
  END o[304]
  PIN o[305]
    DIRECTION OUTPUT ;
    USE SIGNAL ;
    PORT
      LAYER M4 ;
        RECT  17.088 34.032 17.28 34.056 ;
    END
  END o[305]
  PIN o[306]
    DIRECTION OUTPUT ;
    USE SIGNAL ;
    PORT
      LAYER M4 ;
        RECT  17.088 34.176 17.28 34.2 ;
    END
  END o[306]
  PIN o[307]
    DIRECTION OUTPUT ;
    USE SIGNAL ;
    PORT
      LAYER M4 ;
        RECT  17.088 34.272 17.28 34.296 ;
    END
  END o[307]
  PIN o[308]
    DIRECTION OUTPUT ;
    USE SIGNAL ;
    PORT
      LAYER M4 ;
        RECT  17.088 34.368 17.28 34.392 ;
    END
  END o[308]
  PIN o[309]
    DIRECTION OUTPUT ;
    USE SIGNAL ;
    PORT
      LAYER M4 ;
        RECT  17.088 34.464 17.28 34.488 ;
    END
  END o[309]
  PIN o[30]
    DIRECTION OUTPUT ;
    USE SIGNAL ;
    PORT
      LAYER M4 ;
        RECT  17.088 5.376 17.28 5.4 ;
    END
  END o[30]
  PIN o[310]
    DIRECTION OUTPUT ;
    USE SIGNAL ;
    PORT
      LAYER M4 ;
        RECT  17.088 34.56 17.28 34.584 ;
    END
  END o[310]
  PIN o[311]
    DIRECTION OUTPUT ;
    USE SIGNAL ;
    PORT
      LAYER M4 ;
        RECT  17.088 34.704 17.28 34.728 ;
    END
  END o[311]
  PIN o[312]
    DIRECTION OUTPUT ;
    USE SIGNAL ;
    PORT
      LAYER M4 ;
        RECT  17.088 34.8 17.28 34.824 ;
    END
  END o[312]
  PIN o[313]
    DIRECTION OUTPUT ;
    USE SIGNAL ;
    PORT
      LAYER M4 ;
        RECT  17.088 34.896 17.28 34.92 ;
    END
  END o[313]
  PIN o[314]
    DIRECTION OUTPUT ;
    USE SIGNAL ;
    PORT
      LAYER M4 ;
        RECT  17.088 34.992 17.28 35.016 ;
    END
  END o[314]
  PIN o[315]
    DIRECTION OUTPUT ;
    USE SIGNAL ;
    PORT
      LAYER M4 ;
        RECT  17.088 35.088 17.28 35.112 ;
    END
  END o[315]
  PIN o[316]
    DIRECTION OUTPUT ;
    USE SIGNAL ;
    PORT
      LAYER M4 ;
        RECT  17.088 35.184 17.28 35.208 ;
    END
  END o[316]
  PIN o[317]
    DIRECTION OUTPUT ;
    USE SIGNAL ;
    PORT
      LAYER M4 ;
        RECT  17.088 35.328 17.28 35.352 ;
    END
  END o[317]
  PIN o[318]
    DIRECTION OUTPUT ;
    USE SIGNAL ;
    PORT
      LAYER M4 ;
        RECT  17.088 35.424 17.28 35.448 ;
    END
  END o[318]
  PIN o[319]
    DIRECTION OUTPUT ;
    USE SIGNAL ;
    PORT
      LAYER M4 ;
        RECT  17.088 35.52 17.28 35.544 ;
    END
  END o[319]
  PIN o[31]
    DIRECTION OUTPUT ;
    USE SIGNAL ;
    PORT
      LAYER M4 ;
        RECT  17.088 5.472 17.28 5.496 ;
    END
  END o[31]
  PIN o[320]
    DIRECTION OUTPUT ;
    USE SIGNAL ;
    PORT
      LAYER M4 ;
        RECT  17.088 35.616 17.28 35.64 ;
    END
  END o[320]
  PIN o[321]
    DIRECTION OUTPUT ;
    USE SIGNAL ;
    PORT
      LAYER M4 ;
        RECT  17.088 35.712 17.28 35.736 ;
    END
  END o[321]
  PIN o[322]
    DIRECTION OUTPUT ;
    USE SIGNAL ;
    PORT
      LAYER M4 ;
        RECT  17.088 35.808 17.28 35.832 ;
    END
  END o[322]
  PIN o[323]
    DIRECTION OUTPUT ;
    USE SIGNAL ;
    PORT
      LAYER M4 ;
        RECT  17.088 35.952 17.28 35.976 ;
    END
  END o[323]
  PIN o[324]
    DIRECTION OUTPUT ;
    USE SIGNAL ;
    PORT
      LAYER M4 ;
        RECT  17.088 36.048 17.28 36.072 ;
    END
  END o[324]
  PIN o[325]
    DIRECTION OUTPUT ;
    USE SIGNAL ;
    PORT
      LAYER M4 ;
        RECT  17.088 36.144 17.28 36.168 ;
    END
  END o[325]
  PIN o[326]
    DIRECTION OUTPUT ;
    USE SIGNAL ;
    PORT
      LAYER M4 ;
        RECT  17.088 36.24 17.28 36.264 ;
    END
  END o[326]
  PIN o[327]
    DIRECTION OUTPUT ;
    USE SIGNAL ;
    PORT
      LAYER M4 ;
        RECT  17.088 36.336 17.28 36.36 ;
    END
  END o[327]
  PIN o[328]
    DIRECTION OUTPUT ;
    USE SIGNAL ;
    PORT
      LAYER M4 ;
        RECT  17.088 36.432 17.28 36.456 ;
    END
  END o[328]
  PIN o[329]
    DIRECTION OUTPUT ;
    USE SIGNAL ;
    PORT
      LAYER M4 ;
        RECT  17.088 36.576 17.28 36.6 ;
    END
  END o[329]
  PIN o[32]
    DIRECTION OUTPUT ;
    USE SIGNAL ;
    PORT
      LAYER M4 ;
        RECT  17.088 5.568 17.28 5.592 ;
    END
  END o[32]
  PIN o[330]
    DIRECTION OUTPUT ;
    USE SIGNAL ;
    PORT
      LAYER M4 ;
        RECT  17.088 36.672 17.28 36.696 ;
    END
  END o[330]
  PIN o[331]
    DIRECTION OUTPUT ;
    USE SIGNAL ;
    PORT
      LAYER M4 ;
        RECT  17.088 36.768 17.28 36.792 ;
    END
  END o[331]
  PIN o[332]
    DIRECTION OUTPUT ;
    USE SIGNAL ;
    PORT
      LAYER M4 ;
        RECT  17.088 36.864 17.28 36.888 ;
    END
  END o[332]
  PIN o[333]
    DIRECTION OUTPUT ;
    USE SIGNAL ;
    PORT
      LAYER M4 ;
        RECT  17.088 36.96 17.28 36.984 ;
    END
  END o[333]
  PIN o[334]
    DIRECTION OUTPUT ;
    USE SIGNAL ;
    PORT
      LAYER M4 ;
        RECT  17.088 37.104 17.28 37.128 ;
    END
  END o[334]
  PIN o[335]
    DIRECTION OUTPUT ;
    USE SIGNAL ;
    PORT
      LAYER M4 ;
        RECT  17.088 37.2 17.28 37.224 ;
    END
  END o[335]
  PIN o[336]
    DIRECTION OUTPUT ;
    USE SIGNAL ;
    PORT
      LAYER M4 ;
        RECT  17.088 37.296 17.28 37.32 ;
    END
  END o[336]
  PIN o[337]
    DIRECTION OUTPUT ;
    USE SIGNAL ;
    PORT
      LAYER M4 ;
        RECT  17.088 37.392 17.28 37.416 ;
    END
  END o[337]
  PIN o[338]
    DIRECTION OUTPUT ;
    USE SIGNAL ;
    PORT
      LAYER M4 ;
        RECT  17.088 37.488 17.28 37.512 ;
    END
  END o[338]
  PIN o[339]
    DIRECTION OUTPUT ;
    USE SIGNAL ;
    PORT
      LAYER M4 ;
        RECT  17.088 37.584 17.28 37.608 ;
    END
  END o[339]
  PIN o[33]
    DIRECTION OUTPUT ;
    USE SIGNAL ;
    PORT
      LAYER M4 ;
        RECT  17.088 5.664 17.28 5.688 ;
    END
  END o[33]
  PIN o[340]
    DIRECTION OUTPUT ;
    USE SIGNAL ;
    PORT
      LAYER M4 ;
        RECT  17.088 37.728 17.28 37.752 ;
    END
  END o[340]
  PIN o[341]
    DIRECTION OUTPUT ;
    USE SIGNAL ;
    PORT
      LAYER M4 ;
        RECT  17.088 37.824 17.28 37.848 ;
    END
  END o[341]
  PIN o[342]
    DIRECTION OUTPUT ;
    USE SIGNAL ;
    PORT
      LAYER M4 ;
        RECT  17.088 37.92 17.28 37.944 ;
    END
  END o[342]
  PIN o[343]
    DIRECTION OUTPUT ;
    USE SIGNAL ;
    PORT
      LAYER M4 ;
        RECT  17.088 38.016 17.28 38.04 ;
    END
  END o[343]
  PIN o[344]
    DIRECTION OUTPUT ;
    USE SIGNAL ;
    PORT
      LAYER M4 ;
        RECT  17.088 38.112 17.28 38.136 ;
    END
  END o[344]
  PIN o[345]
    DIRECTION OUTPUT ;
    USE SIGNAL ;
    PORT
      LAYER M4 ;
        RECT  17.088 38.208 17.28 38.232 ;
    END
  END o[345]
  PIN o[346]
    DIRECTION OUTPUT ;
    USE SIGNAL ;
    PORT
      LAYER M4 ;
        RECT  17.088 38.352 17.28 38.376 ;
    END
  END o[346]
  PIN o[347]
    DIRECTION OUTPUT ;
    USE SIGNAL ;
    PORT
      LAYER M4 ;
        RECT  17.088 38.448 17.28 38.472 ;
    END
  END o[347]
  PIN o[348]
    DIRECTION OUTPUT ;
    USE SIGNAL ;
    PORT
      LAYER M4 ;
        RECT  17.088 38.544 17.28 38.568 ;
    END
  END o[348]
  PIN o[349]
    DIRECTION OUTPUT ;
    USE SIGNAL ;
    PORT
      LAYER M4 ;
        RECT  17.088 38.64 17.28 38.664 ;
    END
  END o[349]
  PIN o[34]
    DIRECTION OUTPUT ;
    USE SIGNAL ;
    PORT
      LAYER M4 ;
        RECT  17.088 5.76 17.28 5.784 ;
    END
  END o[34]
  PIN o[350]
    DIRECTION OUTPUT ;
    USE SIGNAL ;
    PORT
      LAYER M4 ;
        RECT  17.088 38.736 17.28 38.76 ;
    END
  END o[350]
  PIN o[351]
    DIRECTION OUTPUT ;
    USE SIGNAL ;
    PORT
      LAYER M4 ;
        RECT  17.088 38.832 17.28 38.856 ;
    END
  END o[351]
  PIN o[352]
    DIRECTION OUTPUT ;
    USE SIGNAL ;
    PORT
      LAYER M4 ;
        RECT  17.088 38.976 17.28 39 ;
    END
  END o[352]
  PIN o[353]
    DIRECTION OUTPUT ;
    USE SIGNAL ;
    PORT
      LAYER M4 ;
        RECT  17.088 39.072 17.28 39.096 ;
    END
  END o[353]
  PIN o[354]
    DIRECTION OUTPUT ;
    USE SIGNAL ;
    PORT
      LAYER M4 ;
        RECT  17.088 39.168 17.28 39.192 ;
    END
  END o[354]
  PIN o[355]
    DIRECTION OUTPUT ;
    USE SIGNAL ;
    PORT
      LAYER M4 ;
        RECT  17.088 39.264 17.28 39.288 ;
    END
  END o[355]
  PIN o[356]
    DIRECTION OUTPUT ;
    USE SIGNAL ;
    PORT
      LAYER M4 ;
        RECT  17.088 39.36 17.28 39.384 ;
    END
  END o[356]
  PIN o[357]
    DIRECTION OUTPUT ;
    USE SIGNAL ;
    PORT
      LAYER M4 ;
        RECT  17.088 39.504 17.28 39.528 ;
    END
  END o[357]
  PIN o[358]
    DIRECTION OUTPUT ;
    USE SIGNAL ;
    PORT
      LAYER M4 ;
        RECT  17.088 39.6 17.28 39.624 ;
    END
  END o[358]
  PIN o[359]
    DIRECTION OUTPUT ;
    USE SIGNAL ;
    PORT
      LAYER M4 ;
        RECT  17.088 39.696 17.28 39.72 ;
    END
  END o[359]
  PIN o[35]
    DIRECTION OUTPUT ;
    USE SIGNAL ;
    PORT
      LAYER M4 ;
        RECT  17.088 5.856 17.28 5.88 ;
    END
  END o[35]
  PIN o[360]
    DIRECTION OUTPUT ;
    USE SIGNAL ;
    PORT
      LAYER M4 ;
        RECT  17.088 39.792 17.28 39.816 ;
    END
  END o[360]
  PIN o[361]
    DIRECTION OUTPUT ;
    USE SIGNAL ;
    PORT
      LAYER M4 ;
        RECT  17.088 39.888 17.28 39.912 ;
    END
  END o[361]
  PIN o[362]
    DIRECTION OUTPUT ;
    USE SIGNAL ;
    PORT
      LAYER M4 ;
        RECT  17.088 39.984 17.28 40.008 ;
    END
  END o[362]
  PIN o[363]
    DIRECTION OUTPUT ;
    USE SIGNAL ;
    PORT
      LAYER M4 ;
        RECT  17.088 40.128 17.28 40.152 ;
    END
  END o[363]
  PIN o[364]
    DIRECTION OUTPUT ;
    USE SIGNAL ;
    PORT
      LAYER M4 ;
        RECT  17.088 40.224 17.28 40.248 ;
    END
  END o[364]
  PIN o[365]
    DIRECTION OUTPUT ;
    USE SIGNAL ;
    PORT
      LAYER M4 ;
        RECT  17.088 40.32 17.28 40.344 ;
    END
  END o[365]
  PIN o[366]
    DIRECTION OUTPUT ;
    USE SIGNAL ;
    PORT
      LAYER M4 ;
        RECT  17.088 40.416 17.28 40.44 ;
    END
  END o[366]
  PIN o[367]
    DIRECTION OUTPUT ;
    USE SIGNAL ;
    PORT
      LAYER M4 ;
        RECT  17.088 40.512 17.28 40.536 ;
    END
  END o[367]
  PIN o[368]
    DIRECTION OUTPUT ;
    USE SIGNAL ;
    PORT
      LAYER M4 ;
        RECT  17.088 40.608 17.28 40.632 ;
    END
  END o[368]
  PIN o[369]
    DIRECTION OUTPUT ;
    USE SIGNAL ;
    PORT
      LAYER M4 ;
        RECT  17.088 40.752 17.28 40.776 ;
    END
  END o[369]
  PIN o[36]
    DIRECTION OUTPUT ;
    USE SIGNAL ;
    PORT
      LAYER M4 ;
        RECT  17.088 6 17.28 6.024 ;
    END
  END o[36]
  PIN o[370]
    DIRECTION OUTPUT ;
    USE SIGNAL ;
    PORT
      LAYER M4 ;
        RECT  17.088 40.848 17.28 40.872 ;
    END
  END o[370]
  PIN o[371]
    DIRECTION OUTPUT ;
    USE SIGNAL ;
    PORT
      LAYER M4 ;
        RECT  17.088 40.944 17.28 40.968 ;
    END
  END o[371]
  PIN o[372]
    DIRECTION OUTPUT ;
    USE SIGNAL ;
    PORT
      LAYER M4 ;
        RECT  17.088 41.04 17.28 41.064 ;
    END
  END o[372]
  PIN o[373]
    DIRECTION OUTPUT ;
    USE SIGNAL ;
    PORT
      LAYER M4 ;
        RECT  17.088 41.136 17.28 41.16 ;
    END
  END o[373]
  PIN o[374]
    DIRECTION OUTPUT ;
    USE SIGNAL ;
    PORT
      LAYER M4 ;
        RECT  17.088 41.232 17.28 41.256 ;
    END
  END o[374]
  PIN o[375]
    DIRECTION OUTPUT ;
    USE SIGNAL ;
    PORT
      LAYER M4 ;
        RECT  17.088 41.376 17.28 41.4 ;
    END
  END o[375]
  PIN o[376]
    DIRECTION OUTPUT ;
    USE SIGNAL ;
    PORT
      LAYER M4 ;
        RECT  17.088 41.472 17.28 41.496 ;
    END
  END o[376]
  PIN o[377]
    DIRECTION OUTPUT ;
    USE SIGNAL ;
    PORT
      LAYER M4 ;
        RECT  17.088 41.568 17.28 41.592 ;
    END
  END o[377]
  PIN o[378]
    DIRECTION OUTPUT ;
    USE SIGNAL ;
    PORT
      LAYER M4 ;
        RECT  17.088 41.664 17.28 41.688 ;
    END
  END o[378]
  PIN o[379]
    DIRECTION OUTPUT ;
    USE SIGNAL ;
    PORT
      LAYER M4 ;
        RECT  17.088 41.76 17.28 41.784 ;
    END
  END o[379]
  PIN o[37]
    DIRECTION OUTPUT ;
    USE SIGNAL ;
    PORT
      LAYER M4 ;
        RECT  17.088 6.096 17.28 6.12 ;
    END
  END o[37]
  PIN o[380]
    DIRECTION OUTPUT ;
    USE SIGNAL ;
    PORT
      LAYER M4 ;
        RECT  17.088 41.904 17.28 41.928 ;
    END
  END o[380]
  PIN o[381]
    DIRECTION OUTPUT ;
    USE SIGNAL ;
    PORT
      LAYER M4 ;
        RECT  17.088 42 17.28 42.024 ;
    END
  END o[381]
  PIN o[382]
    DIRECTION OUTPUT ;
    USE SIGNAL ;
    PORT
      LAYER M4 ;
        RECT  17.088 42.096 17.28 42.12 ;
    END
  END o[382]
  PIN o[383]
    DIRECTION OUTPUT ;
    USE SIGNAL ;
    PORT
      LAYER M4 ;
        RECT  17.088 42.192 17.28 42.216 ;
    END
  END o[383]
  PIN o[384]
    DIRECTION OUTPUT ;
    USE SIGNAL ;
    PORT
      LAYER M4 ;
        RECT  17.088 42.288 17.28 42.312 ;
    END
  END o[384]
  PIN o[385]
    DIRECTION OUTPUT ;
    USE SIGNAL ;
    PORT
      LAYER M4 ;
        RECT  17.088 42.384 17.28 42.408 ;
    END
  END o[385]
  PIN o[386]
    DIRECTION OUTPUT ;
    USE SIGNAL ;
    PORT
      LAYER M4 ;
        RECT  17.088 42.528 17.28 42.552 ;
    END
  END o[386]
  PIN o[387]
    DIRECTION OUTPUT ;
    USE SIGNAL ;
    PORT
      LAYER M4 ;
        RECT  17.088 42.624 17.28 42.648 ;
    END
  END o[387]
  PIN o[388]
    DIRECTION OUTPUT ;
    USE SIGNAL ;
    PORT
      LAYER M4 ;
        RECT  17.088 42.72 17.28 42.744 ;
    END
  END o[388]
  PIN o[389]
    DIRECTION OUTPUT ;
    USE SIGNAL ;
    PORT
      LAYER M4 ;
        RECT  17.088 42.816 17.28 42.84 ;
    END
  END o[389]
  PIN o[38]
    DIRECTION OUTPUT ;
    USE SIGNAL ;
    PORT
      LAYER M4 ;
        RECT  17.088 6.192 17.28 6.216 ;
    END
  END o[38]
  PIN o[390]
    DIRECTION OUTPUT ;
    USE SIGNAL ;
    PORT
      LAYER M4 ;
        RECT  17.088 42.912 17.28 42.936 ;
    END
  END o[390]
  PIN o[391]
    DIRECTION OUTPUT ;
    USE SIGNAL ;
    PORT
      LAYER M4 ;
        RECT  17.088 43.008 17.28 43.032 ;
    END
  END o[391]
  PIN o[392]
    DIRECTION OUTPUT ;
    USE SIGNAL ;
    PORT
      LAYER M4 ;
        RECT  17.088 43.152 17.28 43.176 ;
    END
  END o[392]
  PIN o[393]
    DIRECTION OUTPUT ;
    USE SIGNAL ;
    PORT
      LAYER M4 ;
        RECT  17.088 43.248 17.28 43.272 ;
    END
  END o[393]
  PIN o[394]
    DIRECTION OUTPUT ;
    USE SIGNAL ;
    PORT
      LAYER M4 ;
        RECT  17.088 43.344 17.28 43.368 ;
    END
  END o[394]
  PIN o[395]
    DIRECTION OUTPUT ;
    USE SIGNAL ;
    PORT
      LAYER M4 ;
        RECT  17.088 43.44 17.28 43.464 ;
    END
  END o[395]
  PIN o[396]
    DIRECTION OUTPUT ;
    USE SIGNAL ;
    PORT
      LAYER M4 ;
        RECT  17.088 43.536 17.28 43.56 ;
    END
  END o[396]
  PIN o[397]
    DIRECTION OUTPUT ;
    USE SIGNAL ;
    PORT
      LAYER M4 ;
        RECT  17.088 43.68 17.28 43.704 ;
    END
  END o[397]
  PIN o[398]
    DIRECTION OUTPUT ;
    USE SIGNAL ;
    PORT
      LAYER M4 ;
        RECT  17.088 43.776 17.28 43.8 ;
    END
  END o[398]
  PIN o[399]
    DIRECTION OUTPUT ;
    USE SIGNAL ;
    PORT
      LAYER M4 ;
        RECT  17.088 43.872 17.28 43.896 ;
    END
  END o[399]
  PIN o[39]
    DIRECTION OUTPUT ;
    USE SIGNAL ;
    PORT
      LAYER M4 ;
        RECT  17.088 6.288 17.28 6.312 ;
    END
  END o[39]
  PIN o[3]
    DIRECTION OUTPUT ;
    USE SIGNAL ;
    PORT
      LAYER M4 ;
        RECT  17.088 2.544 17.28 2.568 ;
    END
  END o[3]
  PIN o[400]
    DIRECTION OUTPUT ;
    USE SIGNAL ;
    PORT
      LAYER M4 ;
        RECT  17.088 43.968 17.28 43.992 ;
    END
  END o[400]
  PIN o[401]
    DIRECTION OUTPUT ;
    USE SIGNAL ;
    PORT
      LAYER M4 ;
        RECT  17.088 44.064 17.28 44.088 ;
    END
  END o[401]
  PIN o[402]
    DIRECTION OUTPUT ;
    USE SIGNAL ;
    PORT
      LAYER M4 ;
        RECT  17.088 44.16 17.28 44.184 ;
    END
  END o[402]
  PIN o[403]
    DIRECTION OUTPUT ;
    USE SIGNAL ;
    PORT
      LAYER M4 ;
        RECT  17.088 44.304 17.28 44.328 ;
    END
  END o[403]
  PIN o[404]
    DIRECTION OUTPUT ;
    USE SIGNAL ;
    PORT
      LAYER M4 ;
        RECT  17.088 44.4 17.28 44.424 ;
    END
  END o[404]
  PIN o[405]
    DIRECTION OUTPUT ;
    USE SIGNAL ;
    PORT
      LAYER M4 ;
        RECT  17.088 44.496 17.28 44.52 ;
    END
  END o[405]
  PIN o[406]
    DIRECTION OUTPUT ;
    USE SIGNAL ;
    PORT
      LAYER M4 ;
        RECT  17.088 44.592 17.28 44.616 ;
    END
  END o[406]
  PIN o[407]
    DIRECTION OUTPUT ;
    USE SIGNAL ;
    PORT
      LAYER M4 ;
        RECT  17.088 44.688 17.28 44.712 ;
    END
  END o[407]
  PIN o[408]
    DIRECTION OUTPUT ;
    USE SIGNAL ;
    PORT
      LAYER M4 ;
        RECT  17.088 44.784 17.28 44.808 ;
    END
  END o[408]
  PIN o[409]
    DIRECTION OUTPUT ;
    USE SIGNAL ;
    PORT
      LAYER M4 ;
        RECT  17.088 44.928 17.28 44.952 ;
    END
  END o[409]
  PIN o[40]
    DIRECTION OUTPUT ;
    USE SIGNAL ;
    PORT
      LAYER M4 ;
        RECT  17.088 6.384 17.28 6.408 ;
    END
  END o[40]
  PIN o[410]
    DIRECTION OUTPUT ;
    USE SIGNAL ;
    PORT
      LAYER M4 ;
        RECT  17.088 45.024 17.28 45.048 ;
    END
  END o[410]
  PIN o[411]
    DIRECTION OUTPUT ;
    USE SIGNAL ;
    PORT
      LAYER M4 ;
        RECT  17.088 45.12 17.28 45.144 ;
    END
  END o[411]
  PIN o[412]
    DIRECTION OUTPUT ;
    USE SIGNAL ;
    PORT
      LAYER M4 ;
        RECT  17.088 45.216 17.28 45.24 ;
    END
  END o[412]
  PIN o[413]
    DIRECTION OUTPUT ;
    USE SIGNAL ;
    PORT
      LAYER M4 ;
        RECT  17.088 45.312 17.28 45.336 ;
    END
  END o[413]
  PIN o[414]
    DIRECTION OUTPUT ;
    USE SIGNAL ;
    PORT
      LAYER M4 ;
        RECT  17.088 45.408 17.28 45.432 ;
    END
  END o[414]
  PIN o[415]
    DIRECTION OUTPUT ;
    USE SIGNAL ;
    PORT
      LAYER M4 ;
        RECT  17.088 45.552 17.28 45.576 ;
    END
  END o[415]
  PIN o[416]
    DIRECTION OUTPUT ;
    USE SIGNAL ;
    PORT
      LAYER M4 ;
        RECT  17.088 45.648 17.28 45.672 ;
    END
  END o[416]
  PIN o[417]
    DIRECTION OUTPUT ;
    USE SIGNAL ;
    PORT
      LAYER M4 ;
        RECT  17.088 45.744 17.28 45.768 ;
    END
  END o[417]
  PIN o[418]
    DIRECTION OUTPUT ;
    USE SIGNAL ;
    PORT
      LAYER M4 ;
        RECT  17.088 45.84 17.28 45.864 ;
    END
  END o[418]
  PIN o[419]
    DIRECTION OUTPUT ;
    USE SIGNAL ;
    PORT
      LAYER M4 ;
        RECT  17.088 45.936 17.28 45.96 ;
    END
  END o[419]
  PIN o[41]
    DIRECTION OUTPUT ;
    USE SIGNAL ;
    PORT
      LAYER M4 ;
        RECT  17.088 6.48 17.28 6.504 ;
    END
  END o[41]
  PIN o[420]
    DIRECTION OUTPUT ;
    USE SIGNAL ;
    PORT
      LAYER M4 ;
        RECT  17.088 46.08 17.28 46.104 ;
    END
  END o[420]
  PIN o[421]
    DIRECTION OUTPUT ;
    USE SIGNAL ;
    PORT
      LAYER M4 ;
        RECT  17.088 46.176 17.28 46.2 ;
    END
  END o[421]
  PIN o[422]
    DIRECTION OUTPUT ;
    USE SIGNAL ;
    PORT
      LAYER M4 ;
        RECT  17.088 46.272 17.28 46.296 ;
    END
  END o[422]
  PIN o[423]
    DIRECTION OUTPUT ;
    USE SIGNAL ;
    PORT
      LAYER M4 ;
        RECT  17.088 46.368 17.28 46.392 ;
    END
  END o[423]
  PIN o[424]
    DIRECTION OUTPUT ;
    USE SIGNAL ;
    PORT
      LAYER M4 ;
        RECT  17.088 46.464 17.28 46.488 ;
    END
  END o[424]
  PIN o[425]
    DIRECTION OUTPUT ;
    USE SIGNAL ;
    PORT
      LAYER M4 ;
        RECT  17.088 46.56 17.28 46.584 ;
    END
  END o[425]
  PIN o[426]
    DIRECTION OUTPUT ;
    USE SIGNAL ;
    PORT
      LAYER M4 ;
        RECT  17.088 46.704 17.28 46.728 ;
    END
  END o[426]
  PIN o[427]
    DIRECTION OUTPUT ;
    USE SIGNAL ;
    PORT
      LAYER M4 ;
        RECT  17.088 46.8 17.28 46.824 ;
    END
  END o[427]
  PIN o[428]
    DIRECTION OUTPUT ;
    USE SIGNAL ;
    PORT
      LAYER M4 ;
        RECT  17.088 46.896 17.28 46.92 ;
    END
  END o[428]
  PIN o[429]
    DIRECTION OUTPUT ;
    USE SIGNAL ;
    PORT
      LAYER M4 ;
        RECT  17.088 46.992 17.28 47.016 ;
    END
  END o[429]
  PIN o[42]
    DIRECTION OUTPUT ;
    USE SIGNAL ;
    PORT
      LAYER M4 ;
        RECT  17.088 6.624 17.28 6.648 ;
    END
  END o[42]
  PIN o[430]
    DIRECTION OUTPUT ;
    USE SIGNAL ;
    PORT
      LAYER M4 ;
        RECT  17.088 47.088 17.28 47.112 ;
    END
  END o[430]
  PIN o[431]
    DIRECTION OUTPUT ;
    USE SIGNAL ;
    PORT
      LAYER M4 ;
        RECT  17.088 47.184 17.28 47.208 ;
    END
  END o[431]
  PIN o[432]
    DIRECTION OUTPUT ;
    USE SIGNAL ;
    PORT
      LAYER M4 ;
        RECT  17.088 47.328 17.28 47.352 ;
    END
  END o[432]
  PIN o[433]
    DIRECTION OUTPUT ;
    USE SIGNAL ;
    PORT
      LAYER M4 ;
        RECT  17.088 47.424 17.28 47.448 ;
    END
  END o[433]
  PIN o[434]
    DIRECTION OUTPUT ;
    USE SIGNAL ;
    PORT
      LAYER M4 ;
        RECT  17.088 47.52 17.28 47.544 ;
    END
  END o[434]
  PIN o[435]
    DIRECTION OUTPUT ;
    USE SIGNAL ;
    PORT
      LAYER M4 ;
        RECT  17.088 47.616 17.28 47.64 ;
    END
  END o[435]
  PIN o[436]
    DIRECTION OUTPUT ;
    USE SIGNAL ;
    PORT
      LAYER M4 ;
        RECT  17.088 47.712 17.28 47.736 ;
    END
  END o[436]
  PIN o[437]
    DIRECTION OUTPUT ;
    USE SIGNAL ;
    PORT
      LAYER M4 ;
        RECT  17.088 47.808 17.28 47.832 ;
    END
  END o[437]
  PIN o[438]
    DIRECTION OUTPUT ;
    USE SIGNAL ;
    PORT
      LAYER M4 ;
        RECT  17.088 47.952 17.28 47.976 ;
    END
  END o[438]
  PIN o[439]
    DIRECTION OUTPUT ;
    USE SIGNAL ;
    PORT
      LAYER M4 ;
        RECT  17.088 48.048 17.28 48.072 ;
    END
  END o[439]
  PIN o[43]
    DIRECTION OUTPUT ;
    USE SIGNAL ;
    PORT
      LAYER M4 ;
        RECT  17.088 6.72 17.28 6.744 ;
    END
  END o[43]
  PIN o[440]
    DIRECTION OUTPUT ;
    USE SIGNAL ;
    PORT
      LAYER M4 ;
        RECT  17.088 48.144 17.28 48.168 ;
    END
  END o[440]
  PIN o[441]
    DIRECTION OUTPUT ;
    USE SIGNAL ;
    PORT
      LAYER M4 ;
        RECT  17.088 48.24 17.28 48.264 ;
    END
  END o[441]
  PIN o[442]
    DIRECTION OUTPUT ;
    USE SIGNAL ;
    PORT
      LAYER M4 ;
        RECT  17.088 48.336 17.28 48.36 ;
    END
  END o[442]
  PIN o[443]
    DIRECTION OUTPUT ;
    USE SIGNAL ;
    PORT
      LAYER M4 ;
        RECT  17.088 48.48 17.28 48.504 ;
    END
  END o[443]
  PIN o[444]
    DIRECTION OUTPUT ;
    USE SIGNAL ;
    PORT
      LAYER M4 ;
        RECT  17.088 48.576 17.28 48.6 ;
    END
  END o[444]
  PIN o[445]
    DIRECTION OUTPUT ;
    USE SIGNAL ;
    PORT
      LAYER M4 ;
        RECT  17.088 48.672 17.28 48.696 ;
    END
  END o[445]
  PIN o[446]
    DIRECTION OUTPUT ;
    USE SIGNAL ;
    PORT
      LAYER M4 ;
        RECT  17.088 48.768 17.28 48.792 ;
    END
  END o[446]
  PIN o[447]
    DIRECTION OUTPUT ;
    USE SIGNAL ;
    PORT
      LAYER M4 ;
        RECT  17.088 48.864 17.28 48.888 ;
    END
  END o[447]
  PIN o[448]
    DIRECTION OUTPUT ;
    USE SIGNAL ;
    PORT
      LAYER M4 ;
        RECT  17.088 48.96 17.28 48.984 ;
    END
  END o[448]
  PIN o[449]
    DIRECTION OUTPUT ;
    USE SIGNAL ;
    PORT
      LAYER M4 ;
        RECT  17.088 49.104 17.28 49.128 ;
    END
  END o[449]
  PIN o[44]
    DIRECTION OUTPUT ;
    USE SIGNAL ;
    PORT
      LAYER M4 ;
        RECT  17.088 6.816 17.28 6.84 ;
    END
  END o[44]
  PIN o[450]
    DIRECTION OUTPUT ;
    USE SIGNAL ;
    PORT
      LAYER M4 ;
        RECT  17.088 49.2 17.28 49.224 ;
    END
  END o[450]
  PIN o[451]
    DIRECTION OUTPUT ;
    USE SIGNAL ;
    PORT
      LAYER M4 ;
        RECT  17.088 49.296 17.28 49.32 ;
    END
  END o[451]
  PIN o[452]
    DIRECTION OUTPUT ;
    USE SIGNAL ;
    PORT
      LAYER M4 ;
        RECT  17.088 49.392 17.28 49.416 ;
    END
  END o[452]
  PIN o[453]
    DIRECTION OUTPUT ;
    USE SIGNAL ;
    PORT
      LAYER M4 ;
        RECT  17.088 49.488 17.28 49.512 ;
    END
  END o[453]
  PIN o[454]
    DIRECTION OUTPUT ;
    USE SIGNAL ;
    PORT
      LAYER M4 ;
        RECT  17.088 49.584 17.28 49.608 ;
    END
  END o[454]
  PIN o[455]
    DIRECTION OUTPUT ;
    USE SIGNAL ;
    PORT
      LAYER M4 ;
        RECT  17.088 49.728 17.28 49.752 ;
    END
  END o[455]
  PIN o[456]
    DIRECTION OUTPUT ;
    USE SIGNAL ;
    PORT
      LAYER M4 ;
        RECT  17.088 49.824 17.28 49.848 ;
    END
  END o[456]
  PIN o[457]
    DIRECTION OUTPUT ;
    USE SIGNAL ;
    PORT
      LAYER M4 ;
        RECT  17.088 49.92 17.28 49.944 ;
    END
  END o[457]
  PIN o[458]
    DIRECTION OUTPUT ;
    USE SIGNAL ;
    PORT
      LAYER M4 ;
        RECT  17.088 50.016 17.28 50.04 ;
    END
  END o[458]
  PIN o[459]
    DIRECTION OUTPUT ;
    USE SIGNAL ;
    PORT
      LAYER M4 ;
        RECT  17.088 50.112 17.28 50.136 ;
    END
  END o[459]
  PIN o[45]
    DIRECTION OUTPUT ;
    USE SIGNAL ;
    PORT
      LAYER M4 ;
        RECT  17.088 6.912 17.28 6.936 ;
    END
  END o[45]
  PIN o[460]
    DIRECTION OUTPUT ;
    USE SIGNAL ;
    PORT
      LAYER M4 ;
        RECT  17.088 50.208 17.28 50.232 ;
    END
  END o[460]
  PIN o[461]
    DIRECTION OUTPUT ;
    USE SIGNAL ;
    PORT
      LAYER M4 ;
        RECT  17.088 50.352 17.28 50.376 ;
    END
  END o[461]
  PIN o[462]
    DIRECTION OUTPUT ;
    USE SIGNAL ;
    PORT
      LAYER M4 ;
        RECT  17.088 50.448 17.28 50.472 ;
    END
  END o[462]
  PIN o[463]
    DIRECTION OUTPUT ;
    USE SIGNAL ;
    PORT
      LAYER M4 ;
        RECT  17.088 50.544 17.28 50.568 ;
    END
  END o[463]
  PIN o[464]
    DIRECTION OUTPUT ;
    USE SIGNAL ;
    PORT
      LAYER M4 ;
        RECT  17.088 50.64 17.28 50.664 ;
    END
  END o[464]
  PIN o[465]
    DIRECTION OUTPUT ;
    USE SIGNAL ;
    PORT
      LAYER M4 ;
        RECT  17.088 50.736 17.28 50.76 ;
    END
  END o[465]
  PIN o[466]
    DIRECTION OUTPUT ;
    USE SIGNAL ;
    PORT
      LAYER M4 ;
        RECT  17.088 50.88 17.28 50.904 ;
    END
  END o[466]
  PIN o[467]
    DIRECTION OUTPUT ;
    USE SIGNAL ;
    PORT
      LAYER M4 ;
        RECT  17.088 50.976 17.28 51 ;
    END
  END o[467]
  PIN o[468]
    DIRECTION OUTPUT ;
    USE SIGNAL ;
    PORT
      LAYER M4 ;
        RECT  17.088 51.072 17.28 51.096 ;
    END
  END o[468]
  PIN o[469]
    DIRECTION OUTPUT ;
    USE SIGNAL ;
    PORT
      LAYER M4 ;
        RECT  17.088 51.168 17.28 51.192 ;
    END
  END o[469]
  PIN o[46]
    DIRECTION OUTPUT ;
    USE SIGNAL ;
    PORT
      LAYER M4 ;
        RECT  17.088 7.008 17.28 7.032 ;
    END
  END o[46]
  PIN o[470]
    DIRECTION OUTPUT ;
    USE SIGNAL ;
    PORT
      LAYER M4 ;
        RECT  17.088 51.264 17.28 51.288 ;
    END
  END o[470]
  PIN o[471]
    DIRECTION OUTPUT ;
    USE SIGNAL ;
    PORT
      LAYER M4 ;
        RECT  17.088 51.36 17.28 51.384 ;
    END
  END o[471]
  PIN o[472]
    DIRECTION OUTPUT ;
    USE SIGNAL ;
    PORT
      LAYER M4 ;
        RECT  17.088 51.504 17.28 51.528 ;
    END
  END o[472]
  PIN o[473]
    DIRECTION OUTPUT ;
    USE SIGNAL ;
    PORT
      LAYER M4 ;
        RECT  17.088 51.6 17.28 51.624 ;
    END
  END o[473]
  PIN o[474]
    DIRECTION OUTPUT ;
    USE SIGNAL ;
    PORT
      LAYER M4 ;
        RECT  17.088 51.696 17.28 51.72 ;
    END
  END o[474]
  PIN o[475]
    DIRECTION OUTPUT ;
    USE SIGNAL ;
    PORT
      LAYER M4 ;
        RECT  17.088 51.792 17.28 51.816 ;
    END
  END o[475]
  PIN o[476]
    DIRECTION OUTPUT ;
    USE SIGNAL ;
    PORT
      LAYER M4 ;
        RECT  17.088 51.888 17.28 51.912 ;
    END
  END o[476]
  PIN o[477]
    DIRECTION OUTPUT ;
    USE SIGNAL ;
    PORT
      LAYER M4 ;
        RECT  17.088 51.984 17.28 52.008 ;
    END
  END o[477]
  PIN o[478]
    DIRECTION OUTPUT ;
    USE SIGNAL ;
    PORT
      LAYER M4 ;
        RECT  17.088 52.128 17.28 52.152 ;
    END
  END o[478]
  PIN o[479]
    DIRECTION OUTPUT ;
    USE SIGNAL ;
    PORT
      LAYER M4 ;
        RECT  17.088 52.224 17.28 52.248 ;
    END
  END o[479]
  PIN o[47]
    DIRECTION OUTPUT ;
    USE SIGNAL ;
    PORT
      LAYER M4 ;
        RECT  17.088 7.152 17.28 7.176 ;
    END
  END o[47]
  PIN o[480]
    DIRECTION OUTPUT ;
    USE SIGNAL ;
    PORT
      LAYER M4 ;
        RECT  17.088 52.32 17.28 52.344 ;
    END
  END o[480]
  PIN o[481]
    DIRECTION OUTPUT ;
    USE SIGNAL ;
    PORT
      LAYER M4 ;
        RECT  17.088 52.416 17.28 52.44 ;
    END
  END o[481]
  PIN o[482]
    DIRECTION OUTPUT ;
    USE SIGNAL ;
    PORT
      LAYER M4 ;
        RECT  17.088 52.512 17.28 52.536 ;
    END
  END o[482]
  PIN o[483]
    DIRECTION OUTPUT ;
    USE SIGNAL ;
    PORT
      LAYER M4 ;
        RECT  17.088 52.608 17.28 52.632 ;
    END
  END o[483]
  PIN o[484]
    DIRECTION OUTPUT ;
    USE SIGNAL ;
    PORT
      LAYER M4 ;
        RECT  17.088 52.752 17.28 52.776 ;
    END
  END o[484]
  PIN o[485]
    DIRECTION OUTPUT ;
    USE SIGNAL ;
    PORT
      LAYER M4 ;
        RECT  17.088 52.848 17.28 52.872 ;
    END
  END o[485]
  PIN o[486]
    DIRECTION OUTPUT ;
    USE SIGNAL ;
    PORT
      LAYER M4 ;
        RECT  17.088 52.944 17.28 52.968 ;
    END
  END o[486]
  PIN o[487]
    DIRECTION OUTPUT ;
    USE SIGNAL ;
    PORT
      LAYER M4 ;
        RECT  17.088 53.04 17.28 53.064 ;
    END
  END o[487]
  PIN o[488]
    DIRECTION OUTPUT ;
    USE SIGNAL ;
    PORT
      LAYER M4 ;
        RECT  17.088 53.136 17.28 53.16 ;
    END
  END o[488]
  PIN o[489]
    DIRECTION OUTPUT ;
    USE SIGNAL ;
    PORT
      LAYER M4 ;
        RECT  17.088 53.28 17.28 53.304 ;
    END
  END o[489]
  PIN o[48]
    DIRECTION OUTPUT ;
    USE SIGNAL ;
    PORT
      LAYER M4 ;
        RECT  17.088 7.248 17.28 7.272 ;
    END
  END o[48]
  PIN o[490]
    DIRECTION OUTPUT ;
    USE SIGNAL ;
    PORT
      LAYER M4 ;
        RECT  17.088 53.376 17.28 53.4 ;
    END
  END o[490]
  PIN o[491]
    DIRECTION OUTPUT ;
    USE SIGNAL ;
    PORT
      LAYER M4 ;
        RECT  17.088 53.472 17.28 53.496 ;
    END
  END o[491]
  PIN o[492]
    DIRECTION OUTPUT ;
    USE SIGNAL ;
    PORT
      LAYER M4 ;
        RECT  17.088 53.568 17.28 53.592 ;
    END
  END o[492]
  PIN o[493]
    DIRECTION OUTPUT ;
    USE SIGNAL ;
    PORT
      LAYER M4 ;
        RECT  17.088 53.664 17.28 53.688 ;
    END
  END o[493]
  PIN o[494]
    DIRECTION OUTPUT ;
    USE SIGNAL ;
    PORT
      LAYER M4 ;
        RECT  17.088 53.76 17.28 53.784 ;
    END
  END o[494]
  PIN o[495]
    DIRECTION OUTPUT ;
    USE SIGNAL ;
    PORT
      LAYER M4 ;
        RECT  17.088 53.904 17.28 53.928 ;
    END
  END o[495]
  PIN o[496]
    DIRECTION OUTPUT ;
    USE SIGNAL ;
    PORT
      LAYER M4 ;
        RECT  17.088 54 17.28 54.024 ;
    END
  END o[496]
  PIN o[497]
    DIRECTION OUTPUT ;
    USE SIGNAL ;
    PORT
      LAYER M4 ;
        RECT  17.088 54.096 17.28 54.12 ;
    END
  END o[497]
  PIN o[498]
    DIRECTION OUTPUT ;
    USE SIGNAL ;
    PORT
      LAYER M4 ;
        RECT  17.088 54.192 17.28 54.216 ;
    END
  END o[498]
  PIN o[499]
    DIRECTION OUTPUT ;
    USE SIGNAL ;
    PORT
      LAYER M4 ;
        RECT  17.088 54.288 17.28 54.312 ;
    END
  END o[499]
  PIN o[49]
    DIRECTION OUTPUT ;
    USE SIGNAL ;
    PORT
      LAYER M4 ;
        RECT  17.088 7.344 17.28 7.368 ;
    END
  END o[49]
  PIN o[4]
    DIRECTION OUTPUT ;
    USE SIGNAL ;
    PORT
      LAYER M4 ;
        RECT  17.088 2.64 17.28 2.664 ;
    END
  END o[4]
  PIN o[500]
    DIRECTION OUTPUT ;
    USE SIGNAL ;
    PORT
      LAYER M4 ;
        RECT  17.088 54.384 17.28 54.408 ;
    END
  END o[500]
  PIN o[501]
    DIRECTION OUTPUT ;
    USE SIGNAL ;
    PORT
      LAYER M4 ;
        RECT  17.088 54.528 17.28 54.552 ;
    END
  END o[501]
  PIN o[502]
    DIRECTION OUTPUT ;
    USE SIGNAL ;
    PORT
      LAYER M4 ;
        RECT  17.088 54.624 17.28 54.648 ;
    END
  END o[502]
  PIN o[503]
    DIRECTION OUTPUT ;
    USE SIGNAL ;
    PORT
      LAYER M4 ;
        RECT  17.088 54.72 17.28 54.744 ;
    END
  END o[503]
  PIN o[504]
    DIRECTION OUTPUT ;
    USE SIGNAL ;
    PORT
      LAYER M4 ;
        RECT  17.088 54.816 17.28 54.84 ;
    END
  END o[504]
  PIN o[505]
    DIRECTION OUTPUT ;
    USE SIGNAL ;
    PORT
      LAYER M4 ;
        RECT  17.088 54.912 17.28 54.936 ;
    END
  END o[505]
  PIN o[506]
    DIRECTION OUTPUT ;
    USE SIGNAL ;
    PORT
      LAYER M4 ;
        RECT  17.088 55.008 17.28 55.032 ;
    END
  END o[506]
  PIN o[507]
    DIRECTION OUTPUT ;
    USE SIGNAL ;
    PORT
      LAYER M4 ;
        RECT  17.088 55.152 17.28 55.176 ;
    END
  END o[507]
  PIN o[508]
    DIRECTION OUTPUT ;
    USE SIGNAL ;
    PORT
      LAYER M4 ;
        RECT  17.088 55.248 17.28 55.272 ;
    END
  END o[508]
  PIN o[509]
    DIRECTION OUTPUT ;
    USE SIGNAL ;
    PORT
      LAYER M4 ;
        RECT  17.088 55.344 17.28 55.368 ;
    END
  END o[509]
  PIN o[50]
    DIRECTION OUTPUT ;
    USE SIGNAL ;
    PORT
      LAYER M4 ;
        RECT  17.088 7.44 17.28 7.464 ;
    END
  END o[50]
  PIN o[510]
    DIRECTION OUTPUT ;
    USE SIGNAL ;
    PORT
      LAYER M4 ;
        RECT  17.088 55.44 17.28 55.464 ;
    END
  END o[510]
  PIN o[511]
    DIRECTION OUTPUT ;
    USE SIGNAL ;
    PORT
      LAYER M4 ;
        RECT  17.088 55.536 17.28 55.56 ;
    END
  END o[511]
  PIN o[512]
    DIRECTION OUTPUT ;
    USE SIGNAL ;
    PORT
      LAYER M4 ;
        RECT  17.088 55.68 17.28 55.704 ;
    END
  END o[512]
  PIN o[513]
    DIRECTION OUTPUT ;
    USE SIGNAL ;
    PORT
      LAYER M4 ;
        RECT  17.088 55.776 17.28 55.8 ;
    END
  END o[513]
  PIN o[514]
    DIRECTION OUTPUT ;
    USE SIGNAL ;
    PORT
      LAYER M4 ;
        RECT  17.088 55.872 17.28 55.896 ;
    END
  END o[514]
  PIN o[515]
    DIRECTION OUTPUT ;
    USE SIGNAL ;
    PORT
      LAYER M4 ;
        RECT  17.088 55.968 17.28 55.992 ;
    END
  END o[515]
  PIN o[516]
    DIRECTION OUTPUT ;
    USE SIGNAL ;
    PORT
      LAYER M4 ;
        RECT  17.088 56.064 17.28 56.088 ;
    END
  END o[516]
  PIN o[517]
    DIRECTION OUTPUT ;
    USE SIGNAL ;
    PORT
      LAYER M4 ;
        RECT  17.088 56.16 17.28 56.184 ;
    END
  END o[517]
  PIN o[518]
    DIRECTION OUTPUT ;
    USE SIGNAL ;
    PORT
      LAYER M4 ;
        RECT  17.088 56.304 17.28 56.328 ;
    END
  END o[518]
  PIN o[519]
    DIRECTION OUTPUT ;
    USE SIGNAL ;
    PORT
      LAYER M4 ;
        RECT  17.088 56.4 17.28 56.424 ;
    END
  END o[519]
  PIN o[51]
    DIRECTION OUTPUT ;
    USE SIGNAL ;
    PORT
      LAYER M4 ;
        RECT  17.088 7.536 17.28 7.56 ;
    END
  END o[51]
  PIN o[520]
    DIRECTION OUTPUT ;
    USE SIGNAL ;
    PORT
      LAYER M4 ;
        RECT  17.088 56.496 17.28 56.52 ;
    END
  END o[520]
  PIN o[521]
    DIRECTION OUTPUT ;
    USE SIGNAL ;
    PORT
      LAYER M4 ;
        RECT  17.088 56.592 17.28 56.616 ;
    END
  END o[521]
  PIN o[522]
    DIRECTION OUTPUT ;
    USE SIGNAL ;
    PORT
      LAYER M4 ;
        RECT  17.088 56.688 17.28 56.712 ;
    END
  END o[522]
  PIN o[523]
    DIRECTION OUTPUT ;
    USE SIGNAL ;
    PORT
      LAYER M4 ;
        RECT  17.088 56.784 17.28 56.808 ;
    END
  END o[523]
  PIN o[524]
    DIRECTION OUTPUT ;
    USE SIGNAL ;
    PORT
      LAYER M4 ;
        RECT  17.088 56.928 17.28 56.952 ;
    END
  END o[524]
  PIN o[525]
    DIRECTION OUTPUT ;
    USE SIGNAL ;
    PORT
      LAYER M4 ;
        RECT  17.088 57.024 17.28 57.048 ;
    END
  END o[525]
  PIN o[526]
    DIRECTION OUTPUT ;
    USE SIGNAL ;
    PORT
      LAYER M4 ;
        RECT  17.088 57.12 17.28 57.144 ;
    END
  END o[526]
  PIN o[527]
    DIRECTION OUTPUT ;
    USE SIGNAL ;
    PORT
      LAYER M4 ;
        RECT  17.088 57.216 17.28 57.24 ;
    END
  END o[527]
  PIN o[528]
    DIRECTION OUTPUT ;
    USE SIGNAL ;
    PORT
      LAYER M4 ;
        RECT  17.088 57.312 17.28 57.336 ;
    END
  END o[528]
  PIN o[529]
    DIRECTION OUTPUT ;
    USE SIGNAL ;
    PORT
      LAYER M4 ;
        RECT  17.088 57.456 17.28 57.48 ;
    END
  END o[529]
  PIN o[52]
    DIRECTION OUTPUT ;
    USE SIGNAL ;
    PORT
      LAYER M4 ;
        RECT  17.088 7.632 17.28 7.656 ;
    END
  END o[52]
  PIN o[530]
    DIRECTION OUTPUT ;
    USE SIGNAL ;
    PORT
      LAYER M4 ;
        RECT  17.088 57.552 17.28 57.576 ;
    END
  END o[530]
  PIN o[531]
    DIRECTION OUTPUT ;
    USE SIGNAL ;
    PORT
      LAYER M4 ;
        RECT  17.088 57.648 17.28 57.672 ;
    END
  END o[531]
  PIN o[532]
    DIRECTION OUTPUT ;
    USE SIGNAL ;
    PORT
      LAYER M4 ;
        RECT  17.088 57.744 17.28 57.768 ;
    END
  END o[532]
  PIN o[533]
    DIRECTION OUTPUT ;
    USE SIGNAL ;
    PORT
      LAYER M4 ;
        RECT  17.088 57.84 17.28 57.864 ;
    END
  END o[533]
  PIN o[534]
    DIRECTION OUTPUT ;
    USE SIGNAL ;
    PORT
      LAYER M4 ;
        RECT  17.088 57.936 17.28 57.96 ;
    END
  END o[534]
  PIN o[535]
    DIRECTION OUTPUT ;
    USE SIGNAL ;
    PORT
      LAYER M4 ;
        RECT  17.088 58.08 17.28 58.104 ;
    END
  END o[535]
  PIN o[536]
    DIRECTION OUTPUT ;
    USE SIGNAL ;
    PORT
      LAYER M4 ;
        RECT  17.088 58.176 17.28 58.2 ;
    END
  END o[536]
  PIN o[537]
    DIRECTION OUTPUT ;
    USE SIGNAL ;
    PORT
      LAYER M4 ;
        RECT  17.088 58.272 17.28 58.296 ;
    END
  END o[537]
  PIN o[538]
    DIRECTION OUTPUT ;
    USE SIGNAL ;
    PORT
      LAYER M4 ;
        RECT  17.088 58.368 17.28 58.392 ;
    END
  END o[538]
  PIN o[539]
    DIRECTION OUTPUT ;
    USE SIGNAL ;
    PORT
      LAYER M4 ;
        RECT  17.088 58.464 17.28 58.488 ;
    END
  END o[539]
  PIN o[53]
    DIRECTION OUTPUT ;
    USE SIGNAL ;
    PORT
      LAYER M4 ;
        RECT  17.088 7.776 17.28 7.8 ;
    END
  END o[53]
  PIN o[540]
    DIRECTION OUTPUT ;
    USE SIGNAL ;
    PORT
      LAYER M4 ;
        RECT  17.088 58.56 17.28 58.584 ;
    END
  END o[540]
  PIN o[541]
    DIRECTION OUTPUT ;
    USE SIGNAL ;
    PORT
      LAYER M4 ;
        RECT  17.088 58.704 17.28 58.728 ;
    END
  END o[541]
  PIN o[542]
    DIRECTION OUTPUT ;
    USE SIGNAL ;
    PORT
      LAYER M4 ;
        RECT  17.088 58.8 17.28 58.824 ;
    END
  END o[542]
  PIN o[543]
    DIRECTION OUTPUT ;
    USE SIGNAL ;
    PORT
      LAYER M4 ;
        RECT  17.088 58.896 17.28 58.92 ;
    END
  END o[543]
  PIN o[544]
    DIRECTION OUTPUT ;
    USE SIGNAL ;
    PORT
      LAYER M4 ;
        RECT  17.088 58.992 17.28 59.016 ;
    END
  END o[544]
  PIN o[545]
    DIRECTION OUTPUT ;
    USE SIGNAL ;
    PORT
      LAYER M4 ;
        RECT  17.088 59.088 17.28 59.112 ;
    END
  END o[545]
  PIN o[546]
    DIRECTION OUTPUT ;
    USE SIGNAL ;
    PORT
      LAYER M4 ;
        RECT  17.088 59.184 17.28 59.208 ;
    END
  END o[546]
  PIN o[547]
    DIRECTION OUTPUT ;
    USE SIGNAL ;
    PORT
      LAYER M4 ;
        RECT  17.088 59.328 17.28 59.352 ;
    END
  END o[547]
  PIN o[548]
    DIRECTION OUTPUT ;
    USE SIGNAL ;
    PORT
      LAYER M4 ;
        RECT  17.088 59.424 17.28 59.448 ;
    END
  END o[548]
  PIN o[549]
    DIRECTION OUTPUT ;
    USE SIGNAL ;
    PORT
      LAYER M4 ;
        RECT  17.088 59.52 17.28 59.544 ;
    END
  END o[549]
  PIN o[54]
    DIRECTION OUTPUT ;
    USE SIGNAL ;
    PORT
      LAYER M4 ;
        RECT  17.088 7.872 17.28 7.896 ;
    END
  END o[54]
  PIN o[550]
    DIRECTION OUTPUT ;
    USE SIGNAL ;
    PORT
      LAYER M4 ;
        RECT  17.088 59.616 17.28 59.64 ;
    END
  END o[550]
  PIN o[551]
    DIRECTION OUTPUT ;
    USE SIGNAL ;
    PORT
      LAYER M4 ;
        RECT  17.088 59.712 17.28 59.736 ;
    END
  END o[551]
  PIN o[552]
    DIRECTION OUTPUT ;
    USE SIGNAL ;
    PORT
      LAYER M4 ;
        RECT  17.088 59.856 17.28 59.88 ;
    END
  END o[552]
  PIN o[553]
    DIRECTION OUTPUT ;
    USE SIGNAL ;
    PORT
      LAYER M4 ;
        RECT  17.088 59.952 17.28 59.976 ;
    END
  END o[553]
  PIN o[554]
    DIRECTION OUTPUT ;
    USE SIGNAL ;
    PORT
      LAYER M4 ;
        RECT  17.088 60.048 17.28 60.072 ;
    END
  END o[554]
  PIN o[555]
    DIRECTION OUTPUT ;
    USE SIGNAL ;
    PORT
      LAYER M4 ;
        RECT  17.088 60.144 17.28 60.168 ;
    END
  END o[555]
  PIN o[556]
    DIRECTION OUTPUT ;
    USE SIGNAL ;
    PORT
      LAYER M4 ;
        RECT  17.088 60.24 17.28 60.264 ;
    END
  END o[556]
  PIN o[557]
    DIRECTION OUTPUT ;
    USE SIGNAL ;
    PORT
      LAYER M4 ;
        RECT  17.088 60.336 17.28 60.36 ;
    END
  END o[557]
  PIN o[558]
    DIRECTION OUTPUT ;
    USE SIGNAL ;
    PORT
      LAYER M4 ;
        RECT  17.088 60.48 17.28 60.504 ;
    END
  END o[558]
  PIN o[559]
    DIRECTION OUTPUT ;
    USE SIGNAL ;
    PORT
      LAYER M4 ;
        RECT  17.088 60.576 17.28 60.6 ;
    END
  END o[559]
  PIN o[55]
    DIRECTION OUTPUT ;
    USE SIGNAL ;
    PORT
      LAYER M4 ;
        RECT  17.088 7.968 17.28 7.992 ;
    END
  END o[55]
  PIN o[560]
    DIRECTION OUTPUT ;
    USE SIGNAL ;
    PORT
      LAYER M4 ;
        RECT  17.088 60.672 17.28 60.696 ;
    END
  END o[560]
  PIN o[561]
    DIRECTION OUTPUT ;
    USE SIGNAL ;
    PORT
      LAYER M4 ;
        RECT  17.088 60.768 17.28 60.792 ;
    END
  END o[561]
  PIN o[562]
    DIRECTION OUTPUT ;
    USE SIGNAL ;
    PORT
      LAYER M4 ;
        RECT  17.088 60.864 17.28 60.888 ;
    END
  END o[562]
  PIN o[563]
    DIRECTION OUTPUT ;
    USE SIGNAL ;
    PORT
      LAYER M4 ;
        RECT  17.088 60.96 17.28 60.984 ;
    END
  END o[563]
  PIN o[564]
    DIRECTION OUTPUT ;
    USE SIGNAL ;
    PORT
      LAYER M4 ;
        RECT  17.088 61.104 17.28 61.128 ;
    END
  END o[564]
  PIN o[565]
    DIRECTION OUTPUT ;
    USE SIGNAL ;
    PORT
      LAYER M4 ;
        RECT  17.088 61.2 17.28 61.224 ;
    END
  END o[565]
  PIN o[566]
    DIRECTION OUTPUT ;
    USE SIGNAL ;
    PORT
      LAYER M4 ;
        RECT  17.088 61.296 17.28 61.32 ;
    END
  END o[566]
  PIN o[567]
    DIRECTION OUTPUT ;
    USE SIGNAL ;
    PORT
      LAYER M4 ;
        RECT  17.088 61.392 17.28 61.416 ;
    END
  END o[567]
  PIN o[568]
    DIRECTION OUTPUT ;
    USE SIGNAL ;
    PORT
      LAYER M4 ;
        RECT  17.088 61.488 17.28 61.512 ;
    END
  END o[568]
  PIN o[569]
    DIRECTION OUTPUT ;
    USE SIGNAL ;
    PORT
      LAYER M4 ;
        RECT  17.088 61.584 17.28 61.608 ;
    END
  END o[569]
  PIN o[56]
    DIRECTION OUTPUT ;
    USE SIGNAL ;
    PORT
      LAYER M4 ;
        RECT  17.088 8.064 17.28 8.088 ;
    END
  END o[56]
  PIN o[570]
    DIRECTION OUTPUT ;
    USE SIGNAL ;
    PORT
      LAYER M4 ;
        RECT  17.088 61.728 17.28 61.752 ;
    END
  END o[570]
  PIN o[571]
    DIRECTION OUTPUT ;
    USE SIGNAL ;
    PORT
      LAYER M4 ;
        RECT  17.088 61.824 17.28 61.848 ;
    END
  END o[571]
  PIN o[572]
    DIRECTION OUTPUT ;
    USE SIGNAL ;
    PORT
      LAYER M4 ;
        RECT  17.088 61.92 17.28 61.944 ;
    END
  END o[572]
  PIN o[573]
    DIRECTION OUTPUT ;
    USE SIGNAL ;
    PORT
      LAYER M4 ;
        RECT  17.088 62.016 17.28 62.04 ;
    END
  END o[573]
  PIN o[574]
    DIRECTION OUTPUT ;
    USE SIGNAL ;
    PORT
      LAYER M4 ;
        RECT  17.088 62.112 17.28 62.136 ;
    END
  END o[574]
  PIN o[575]
    DIRECTION OUTPUT ;
    USE SIGNAL ;
    PORT
      LAYER M4 ;
        RECT  17.088 62.256 17.28 62.28 ;
    END
  END o[575]
  PIN o[576]
    DIRECTION OUTPUT ;
    USE SIGNAL ;
    PORT
      LAYER M4 ;
        RECT  17.088 62.352 17.28 62.376 ;
    END
  END o[576]
  PIN o[577]
    DIRECTION OUTPUT ;
    USE SIGNAL ;
    PORT
      LAYER M4 ;
        RECT  17.088 62.448 17.28 62.472 ;
    END
  END o[577]
  PIN o[578]
    DIRECTION OUTPUT ;
    USE SIGNAL ;
    PORT
      LAYER M4 ;
        RECT  17.088 62.544 17.28 62.568 ;
    END
  END o[578]
  PIN o[579]
    DIRECTION OUTPUT ;
    USE SIGNAL ;
    PORT
      LAYER M4 ;
        RECT  17.088 62.64 17.28 62.664 ;
    END
  END o[579]
  PIN o[57]
    DIRECTION OUTPUT ;
    USE SIGNAL ;
    PORT
      LAYER M4 ;
        RECT  17.088 8.16 17.28 8.184 ;
    END
  END o[57]
  PIN o[580]
    DIRECTION OUTPUT ;
    USE SIGNAL ;
    PORT
      LAYER M4 ;
        RECT  17.088 62.736 17.28 62.76 ;
    END
  END o[580]
  PIN o[581]
    DIRECTION OUTPUT ;
    USE SIGNAL ;
    PORT
      LAYER M4 ;
        RECT  17.088 62.88 17.28 62.904 ;
    END
  END o[581]
  PIN o[582]
    DIRECTION OUTPUT ;
    USE SIGNAL ;
    PORT
      LAYER M4 ;
        RECT  17.088 62.976 17.28 63 ;
    END
  END o[582]
  PIN o[583]
    DIRECTION OUTPUT ;
    USE SIGNAL ;
    PORT
      LAYER M4 ;
        RECT  17.088 63.072 17.28 63.096 ;
    END
  END o[583]
  PIN o[584]
    DIRECTION OUTPUT ;
    USE SIGNAL ;
    PORT
      LAYER M4 ;
        RECT  17.088 63.168 17.28 63.192 ;
    END
  END o[584]
  PIN o[585]
    DIRECTION OUTPUT ;
    USE SIGNAL ;
    PORT
      LAYER M4 ;
        RECT  17.088 63.264 17.28 63.288 ;
    END
  END o[585]
  PIN o[586]
    DIRECTION OUTPUT ;
    USE SIGNAL ;
    PORT
      LAYER M4 ;
        RECT  17.088 63.36 17.28 63.384 ;
    END
  END o[586]
  PIN o[587]
    DIRECTION OUTPUT ;
    USE SIGNAL ;
    PORT
      LAYER M4 ;
        RECT  17.088 63.504 17.28 63.528 ;
    END
  END o[587]
  PIN o[588]
    DIRECTION OUTPUT ;
    USE SIGNAL ;
    PORT
      LAYER M4 ;
        RECT  17.088 63.6 17.28 63.624 ;
    END
  END o[588]
  PIN o[589]
    DIRECTION OUTPUT ;
    USE SIGNAL ;
    PORT
      LAYER M4 ;
        RECT  17.088 63.696 17.28 63.72 ;
    END
  END o[589]
  PIN o[58]
    DIRECTION OUTPUT ;
    USE SIGNAL ;
    PORT
      LAYER M4 ;
        RECT  17.088 8.256 17.28 8.28 ;
    END
  END o[58]
  PIN o[590]
    DIRECTION OUTPUT ;
    USE SIGNAL ;
    PORT
      LAYER M4 ;
        RECT  17.088 63.792 17.28 63.816 ;
    END
  END o[590]
  PIN o[591]
    DIRECTION OUTPUT ;
    USE SIGNAL ;
    PORT
      LAYER M4 ;
        RECT  17.088 63.888 17.28 63.912 ;
    END
  END o[591]
  PIN o[592]
    DIRECTION OUTPUT ;
    USE SIGNAL ;
    PORT
      LAYER M4 ;
        RECT  17.088 63.984 17.28 64.008 ;
    END
  END o[592]
  PIN o[593]
    DIRECTION OUTPUT ;
    USE SIGNAL ;
    PORT
      LAYER M4 ;
        RECT  17.088 64.128 17.28 64.152 ;
    END
  END o[593]
  PIN o[594]
    DIRECTION OUTPUT ;
    USE SIGNAL ;
    PORT
      LAYER M4 ;
        RECT  17.088 64.224 17.28 64.248 ;
    END
  END o[594]
  PIN o[595]
    DIRECTION OUTPUT ;
    USE SIGNAL ;
    PORT
      LAYER M4 ;
        RECT  17.088 64.32 17.28 64.344 ;
    END
  END o[595]
  PIN o[596]
    DIRECTION OUTPUT ;
    USE SIGNAL ;
    PORT
      LAYER M4 ;
        RECT  17.088 64.416 17.28 64.44 ;
    END
  END o[596]
  PIN o[597]
    DIRECTION OUTPUT ;
    USE SIGNAL ;
    PORT
      LAYER M4 ;
        RECT  17.088 64.512 17.28 64.536 ;
    END
  END o[597]
  PIN o[598]
    DIRECTION OUTPUT ;
    USE SIGNAL ;
    PORT
      LAYER M4 ;
        RECT  17.088 64.656 17.28 64.68 ;
    END
  END o[598]
  PIN o[599]
    DIRECTION OUTPUT ;
    USE SIGNAL ;
    PORT
      LAYER M4 ;
        RECT  17.088 64.752 17.28 64.776 ;
    END
  END o[599]
  PIN o[59]
    DIRECTION OUTPUT ;
    USE SIGNAL ;
    PORT
      LAYER M4 ;
        RECT  17.088 8.4 17.28 8.424 ;
    END
  END o[59]
  PIN o[5]
    DIRECTION OUTPUT ;
    USE SIGNAL ;
    PORT
      LAYER M4 ;
        RECT  17.088 2.736 17.28 2.76 ;
    END
  END o[5]
  PIN o[600]
    DIRECTION OUTPUT ;
    USE SIGNAL ;
    PORT
      LAYER M4 ;
        RECT  17.088 64.848 17.28 64.872 ;
    END
  END o[600]
  PIN o[601]
    DIRECTION OUTPUT ;
    USE SIGNAL ;
    PORT
      LAYER M4 ;
        RECT  17.088 64.944 17.28 64.968 ;
    END
  END o[601]
  PIN o[602]
    DIRECTION OUTPUT ;
    USE SIGNAL ;
    PORT
      LAYER M4 ;
        RECT  17.088 65.04 17.28 65.064 ;
    END
  END o[602]
  PIN o[603]
    DIRECTION OUTPUT ;
    USE SIGNAL ;
    PORT
      LAYER M4 ;
        RECT  17.088 65.136 17.28 65.16 ;
    END
  END o[603]
  PIN o[604]
    DIRECTION OUTPUT ;
    USE SIGNAL ;
    PORT
      LAYER M4 ;
        RECT  17.088 65.28 17.28 65.304 ;
    END
  END o[604]
  PIN o[605]
    DIRECTION OUTPUT ;
    USE SIGNAL ;
    PORT
      LAYER M4 ;
        RECT  17.088 65.376 17.28 65.4 ;
    END
  END o[605]
  PIN o[606]
    DIRECTION OUTPUT ;
    USE SIGNAL ;
    PORT
      LAYER M4 ;
        RECT  17.088 65.472 17.28 65.496 ;
    END
  END o[606]
  PIN o[607]
    DIRECTION OUTPUT ;
    USE SIGNAL ;
    PORT
      LAYER M4 ;
        RECT  17.088 65.568 17.28 65.592 ;
    END
  END o[607]
  PIN o[608]
    DIRECTION OUTPUT ;
    USE SIGNAL ;
    PORT
      LAYER M4 ;
        RECT  17.088 65.664 17.28 65.688 ;
    END
  END o[608]
  PIN o[609]
    DIRECTION OUTPUT ;
    USE SIGNAL ;
    PORT
      LAYER M4 ;
        RECT  17.088 65.76 17.28 65.784 ;
    END
  END o[609]
  PIN o[60]
    DIRECTION OUTPUT ;
    USE SIGNAL ;
    PORT
      LAYER M4 ;
        RECT  17.088 8.496 17.28 8.52 ;
    END
  END o[60]
  PIN o[610]
    DIRECTION OUTPUT ;
    USE SIGNAL ;
    PORT
      LAYER M4 ;
        RECT  17.088 65.904 17.28 65.928 ;
    END
  END o[610]
  PIN o[611]
    DIRECTION OUTPUT ;
    USE SIGNAL ;
    PORT
      LAYER M4 ;
        RECT  17.088 66 17.28 66.024 ;
    END
  END o[611]
  PIN o[612]
    DIRECTION OUTPUT ;
    USE SIGNAL ;
    PORT
      LAYER M4 ;
        RECT  17.088 66.096 17.28 66.12 ;
    END
  END o[612]
  PIN o[613]
    DIRECTION OUTPUT ;
    USE SIGNAL ;
    PORT
      LAYER M4 ;
        RECT  17.088 66.192 17.28 66.216 ;
    END
  END o[613]
  PIN o[614]
    DIRECTION OUTPUT ;
    USE SIGNAL ;
    PORT
      LAYER M4 ;
        RECT  17.088 66.288 17.28 66.312 ;
    END
  END o[614]
  PIN o[615]
    DIRECTION OUTPUT ;
    USE SIGNAL ;
    PORT
      LAYER M4 ;
        RECT  17.088 66.384 17.28 66.408 ;
    END
  END o[615]
  PIN o[616]
    DIRECTION OUTPUT ;
    USE SIGNAL ;
    PORT
      LAYER M4 ;
        RECT  17.088 66.528 17.28 66.552 ;
    END
  END o[616]
  PIN o[617]
    DIRECTION OUTPUT ;
    USE SIGNAL ;
    PORT
      LAYER M4 ;
        RECT  17.088 66.624 17.28 66.648 ;
    END
  END o[617]
  PIN o[618]
    DIRECTION OUTPUT ;
    USE SIGNAL ;
    PORT
      LAYER M4 ;
        RECT  17.088 66.72 17.28 66.744 ;
    END
  END o[618]
  PIN o[619]
    DIRECTION OUTPUT ;
    USE SIGNAL ;
    PORT
      LAYER M4 ;
        RECT  17.088 66.816 17.28 66.84 ;
    END
  END o[619]
  PIN o[61]
    DIRECTION OUTPUT ;
    USE SIGNAL ;
    PORT
      LAYER M4 ;
        RECT  17.088 8.592 17.28 8.616 ;
    END
  END o[61]
  PIN o[620]
    DIRECTION OUTPUT ;
    USE SIGNAL ;
    PORT
      LAYER M4 ;
        RECT  17.088 66.912 17.28 66.936 ;
    END
  END o[620]
  PIN o[621]
    DIRECTION OUTPUT ;
    USE SIGNAL ;
    PORT
      LAYER M4 ;
        RECT  17.088 67.056 17.28 67.08 ;
    END
  END o[621]
  PIN o[622]
    DIRECTION OUTPUT ;
    USE SIGNAL ;
    PORT
      LAYER M4 ;
        RECT  17.088 67.152 17.28 67.176 ;
    END
  END o[622]
  PIN o[623]
    DIRECTION OUTPUT ;
    USE SIGNAL ;
    PORT
      LAYER M4 ;
        RECT  17.088 67.248 17.28 67.272 ;
    END
  END o[623]
  PIN o[624]
    DIRECTION OUTPUT ;
    USE SIGNAL ;
    PORT
      LAYER M4 ;
        RECT  17.088 67.344 17.28 67.368 ;
    END
  END o[624]
  PIN o[625]
    DIRECTION OUTPUT ;
    USE SIGNAL ;
    PORT
      LAYER M4 ;
        RECT  17.088 67.44 17.28 67.464 ;
    END
  END o[625]
  PIN o[626]
    DIRECTION OUTPUT ;
    USE SIGNAL ;
    PORT
      LAYER M4 ;
        RECT  17.088 67.536 17.28 67.56 ;
    END
  END o[626]
  PIN o[627]
    DIRECTION OUTPUT ;
    USE SIGNAL ;
    PORT
      LAYER M4 ;
        RECT  17.088 67.68 17.28 67.704 ;
    END
  END o[627]
  PIN o[628]
    DIRECTION OUTPUT ;
    USE SIGNAL ;
    PORT
      LAYER M4 ;
        RECT  17.088 67.776 17.28 67.8 ;
    END
  END o[628]
  PIN o[629]
    DIRECTION OUTPUT ;
    USE SIGNAL ;
    PORT
      LAYER M4 ;
        RECT  17.088 67.872 17.28 67.896 ;
    END
  END o[629]
  PIN o[62]
    DIRECTION OUTPUT ;
    USE SIGNAL ;
    PORT
      LAYER M4 ;
        RECT  17.088 8.688 17.28 8.712 ;
    END
  END o[62]
  PIN o[630]
    DIRECTION OUTPUT ;
    USE SIGNAL ;
    PORT
      LAYER M4 ;
        RECT  17.088 67.968 17.28 67.992 ;
    END
  END o[630]
  PIN o[631]
    DIRECTION OUTPUT ;
    USE SIGNAL ;
    PORT
      LAYER M4 ;
        RECT  17.088 68.064 17.28 68.088 ;
    END
  END o[631]
  PIN o[632]
    DIRECTION OUTPUT ;
    USE SIGNAL ;
    PORT
      LAYER M4 ;
        RECT  17.088 68.16 17.28 68.184 ;
    END
  END o[632]
  PIN o[633]
    DIRECTION OUTPUT ;
    USE SIGNAL ;
    PORT
      LAYER M4 ;
        RECT  17.088 68.304 17.28 68.328 ;
    END
  END o[633]
  PIN o[634]
    DIRECTION OUTPUT ;
    USE SIGNAL ;
    PORT
      LAYER M4 ;
        RECT  17.088 68.4 17.28 68.424 ;
    END
  END o[634]
  PIN o[635]
    DIRECTION OUTPUT ;
    USE SIGNAL ;
    PORT
      LAYER M4 ;
        RECT  17.088 68.496 17.28 68.52 ;
    END
  END o[635]
  PIN o[636]
    DIRECTION OUTPUT ;
    USE SIGNAL ;
    PORT
      LAYER M4 ;
        RECT  17.088 68.592 17.28 68.616 ;
    END
  END o[636]
  PIN o[637]
    DIRECTION OUTPUT ;
    USE SIGNAL ;
    PORT
      LAYER M4 ;
        RECT  17.088 68.688 17.28 68.712 ;
    END
  END o[637]
  PIN o[638]
    DIRECTION OUTPUT ;
    USE SIGNAL ;
    PORT
      LAYER M4 ;
        RECT  17.088 68.784 17.28 68.808 ;
    END
  END o[638]
  PIN o[639]
    DIRECTION OUTPUT ;
    USE SIGNAL ;
    PORT
      LAYER M4 ;
        RECT  17.088 68.928 17.28 68.952 ;
    END
  END o[639]
  PIN o[63]
    DIRECTION OUTPUT ;
    USE SIGNAL ;
    PORT
      LAYER M4 ;
        RECT  17.088 8.784 17.28 8.808 ;
    END
  END o[63]
  PIN o[640]
    DIRECTION OUTPUT ;
    USE SIGNAL ;
    PORT
      LAYER M4 ;
        RECT  17.088 69.024 17.28 69.048 ;
    END
  END o[640]
  PIN o[641]
    DIRECTION OUTPUT ;
    USE SIGNAL ;
    PORT
      LAYER M4 ;
        RECT  17.088 69.12 17.28 69.144 ;
    END
  END o[641]
  PIN o[642]
    DIRECTION OUTPUT ;
    USE SIGNAL ;
    PORT
      LAYER M4 ;
        RECT  17.088 69.216 17.28 69.24 ;
    END
  END o[642]
  PIN o[643]
    DIRECTION OUTPUT ;
    USE SIGNAL ;
    PORT
      LAYER M4 ;
        RECT  17.088 69.312 17.28 69.336 ;
    END
  END o[643]
  PIN o[644]
    DIRECTION OUTPUT ;
    USE SIGNAL ;
    PORT
      LAYER M4 ;
        RECT  17.088 69.456 17.28 69.48 ;
    END
  END o[644]
  PIN o[645]
    DIRECTION OUTPUT ;
    USE SIGNAL ;
    PORT
      LAYER M4 ;
        RECT  17.088 69.552 17.28 69.576 ;
    END
  END o[645]
  PIN o[646]
    DIRECTION OUTPUT ;
    USE SIGNAL ;
    PORT
      LAYER M4 ;
        RECT  17.088 69.648 17.28 69.672 ;
    END
  END o[646]
  PIN o[647]
    DIRECTION OUTPUT ;
    USE SIGNAL ;
    PORT
      LAYER M4 ;
        RECT  17.088 69.744 17.28 69.768 ;
    END
  END o[647]
  PIN o[648]
    DIRECTION OUTPUT ;
    USE SIGNAL ;
    PORT
      LAYER M4 ;
        RECT  17.088 69.84 17.28 69.864 ;
    END
  END o[648]
  PIN o[649]
    DIRECTION OUTPUT ;
    USE SIGNAL ;
    PORT
      LAYER M4 ;
        RECT  17.088 69.936 17.28 69.96 ;
    END
  END o[649]
  PIN o[64]
    DIRECTION OUTPUT ;
    USE SIGNAL ;
    PORT
      LAYER M4 ;
        RECT  17.088 8.88 17.28 8.904 ;
    END
  END o[64]
  PIN o[650]
    DIRECTION OUTPUT ;
    USE SIGNAL ;
    PORT
      LAYER M4 ;
        RECT  17.088 70.08 17.28 70.104 ;
    END
  END o[650]
  PIN o[651]
    DIRECTION OUTPUT ;
    USE SIGNAL ;
    PORT
      LAYER M4 ;
        RECT  17.088 70.176 17.28 70.2 ;
    END
  END o[651]
  PIN o[652]
    DIRECTION OUTPUT ;
    USE SIGNAL ;
    PORT
      LAYER M4 ;
        RECT  17.088 70.272 17.28 70.296 ;
    END
  END o[652]
  PIN o[653]
    DIRECTION OUTPUT ;
    USE SIGNAL ;
    PORT
      LAYER M4 ;
        RECT  17.088 70.368 17.28 70.392 ;
    END
  END o[653]
  PIN o[654]
    DIRECTION OUTPUT ;
    USE SIGNAL ;
    PORT
      LAYER M4 ;
        RECT  17.088 70.464 17.28 70.488 ;
    END
  END o[654]
  PIN o[655]
    DIRECTION OUTPUT ;
    USE SIGNAL ;
    PORT
      LAYER M4 ;
        RECT  17.088 70.56 17.28 70.584 ;
    END
  END o[655]
  PIN o[656]
    DIRECTION OUTPUT ;
    USE SIGNAL ;
    PORT
      LAYER M4 ;
        RECT  17.088 70.704 17.28 70.728 ;
    END
  END o[656]
  PIN o[657]
    DIRECTION OUTPUT ;
    USE SIGNAL ;
    PORT
      LAYER M4 ;
        RECT  17.088 70.8 17.28 70.824 ;
    END
  END o[657]
  PIN o[658]
    DIRECTION OUTPUT ;
    USE SIGNAL ;
    PORT
      LAYER M4 ;
        RECT  17.088 70.896 17.28 70.92 ;
    END
  END o[658]
  PIN o[659]
    DIRECTION OUTPUT ;
    USE SIGNAL ;
    PORT
      LAYER M4 ;
        RECT  17.088 70.992 17.28 71.016 ;
    END
  END o[659]
  PIN o[65]
    DIRECTION OUTPUT ;
    USE SIGNAL ;
    PORT
      LAYER M4 ;
        RECT  17.088 9.024 17.28 9.048 ;
    END
  END o[65]
  PIN o[660]
    DIRECTION OUTPUT ;
    USE SIGNAL ;
    PORT
      LAYER M4 ;
        RECT  17.088 71.088 17.28 71.112 ;
    END
  END o[660]
  PIN o[661]
    DIRECTION OUTPUT ;
    USE SIGNAL ;
    PORT
      LAYER M4 ;
        RECT  17.088 71.232 17.28 71.256 ;
    END
  END o[661]
  PIN o[662]
    DIRECTION OUTPUT ;
    USE SIGNAL ;
    PORT
      LAYER M4 ;
        RECT  17.088 71.328 17.28 71.352 ;
    END
  END o[662]
  PIN o[663]
    DIRECTION OUTPUT ;
    USE SIGNAL ;
    PORT
      LAYER M4 ;
        RECT  17.088 71.424 17.28 71.448 ;
    END
  END o[663]
  PIN o[664]
    DIRECTION OUTPUT ;
    USE SIGNAL ;
    PORT
      LAYER M4 ;
        RECT  17.088 71.52 17.28 71.544 ;
    END
  END o[664]
  PIN o[665]
    DIRECTION OUTPUT ;
    USE SIGNAL ;
    PORT
      LAYER M4 ;
        RECT  17.088 71.616 17.28 71.64 ;
    END
  END o[665]
  PIN o[666]
    DIRECTION OUTPUT ;
    USE SIGNAL ;
    PORT
      LAYER M4 ;
        RECT  17.088 71.712 17.28 71.736 ;
    END
  END o[666]
  PIN o[667]
    DIRECTION OUTPUT ;
    USE SIGNAL ;
    PORT
      LAYER M4 ;
        RECT  17.088 71.856 17.28 71.88 ;
    END
  END o[667]
  PIN o[668]
    DIRECTION OUTPUT ;
    USE SIGNAL ;
    PORT
      LAYER M4 ;
        RECT  17.088 71.952 17.28 71.976 ;
    END
  END o[668]
  PIN o[669]
    DIRECTION OUTPUT ;
    USE SIGNAL ;
    PORT
      LAYER M4 ;
        RECT  17.088 72.048 17.28 72.072 ;
    END
  END o[669]
  PIN o[66]
    DIRECTION OUTPUT ;
    USE SIGNAL ;
    PORT
      LAYER M4 ;
        RECT  17.088 9.12 17.28 9.144 ;
    END
  END o[66]
  PIN o[670]
    DIRECTION OUTPUT ;
    USE SIGNAL ;
    PORT
      LAYER M4 ;
        RECT  17.088 72.144 17.28 72.168 ;
    END
  END o[670]
  PIN o[671]
    DIRECTION OUTPUT ;
    USE SIGNAL ;
    PORT
      LAYER M4 ;
        RECT  17.088 72.24 17.28 72.264 ;
    END
  END o[671]
  PIN o[672]
    DIRECTION OUTPUT ;
    USE SIGNAL ;
    PORT
      LAYER M4 ;
        RECT  17.088 72.336 17.28 72.36 ;
    END
  END o[672]
  PIN o[673]
    DIRECTION OUTPUT ;
    USE SIGNAL ;
    PORT
      LAYER M4 ;
        RECT  17.088 72.48 17.28 72.504 ;
    END
  END o[673]
  PIN o[674]
    DIRECTION OUTPUT ;
    USE SIGNAL ;
    PORT
      LAYER M4 ;
        RECT  17.088 72.576 17.28 72.6 ;
    END
  END o[674]
  PIN o[675]
    DIRECTION OUTPUT ;
    USE SIGNAL ;
    PORT
      LAYER M4 ;
        RECT  17.088 72.672 17.28 72.696 ;
    END
  END o[675]
  PIN o[676]
    DIRECTION OUTPUT ;
    USE SIGNAL ;
    PORT
      LAYER M4 ;
        RECT  17.088 72.768 17.28 72.792 ;
    END
  END o[676]
  PIN o[677]
    DIRECTION OUTPUT ;
    USE SIGNAL ;
    PORT
      LAYER M4 ;
        RECT  17.088 72.864 17.28 72.888 ;
    END
  END o[677]
  PIN o[678]
    DIRECTION OUTPUT ;
    USE SIGNAL ;
    PORT
      LAYER M4 ;
        RECT  17.088 72.96 17.28 72.984 ;
    END
  END o[678]
  PIN o[679]
    DIRECTION OUTPUT ;
    USE SIGNAL ;
    PORT
      LAYER M4 ;
        RECT  17.088 73.104 17.28 73.128 ;
    END
  END o[679]
  PIN o[67]
    DIRECTION OUTPUT ;
    USE SIGNAL ;
    PORT
      LAYER M4 ;
        RECT  17.088 9.216 17.28 9.24 ;
    END
  END o[67]
  PIN o[680]
    DIRECTION OUTPUT ;
    USE SIGNAL ;
    PORT
      LAYER M4 ;
        RECT  17.088 73.2 17.28 73.224 ;
    END
  END o[680]
  PIN o[681]
    DIRECTION OUTPUT ;
    USE SIGNAL ;
    PORT
      LAYER M4 ;
        RECT  17.088 73.296 17.28 73.32 ;
    END
  END o[681]
  PIN o[68]
    DIRECTION OUTPUT ;
    USE SIGNAL ;
    PORT
      LAYER M4 ;
        RECT  17.088 9.312 17.28 9.336 ;
    END
  END o[68]
  PIN o[69]
    DIRECTION OUTPUT ;
    USE SIGNAL ;
    PORT
      LAYER M4 ;
        RECT  17.088 9.408 17.28 9.432 ;
    END
  END o[69]
  PIN o[6]
    DIRECTION OUTPUT ;
    USE SIGNAL ;
    PORT
      LAYER M4 ;
        RECT  17.088 2.832 17.28 2.856 ;
    END
  END o[6]
  PIN o[70]
    DIRECTION OUTPUT ;
    USE SIGNAL ;
    PORT
      LAYER M4 ;
        RECT  17.088 9.552 17.28 9.576 ;
    END
  END o[70]
  PIN o[71]
    DIRECTION OUTPUT ;
    USE SIGNAL ;
    PORT
      LAYER M4 ;
        RECT  17.088 9.648 17.28 9.672 ;
    END
  END o[71]
  PIN o[72]
    DIRECTION OUTPUT ;
    USE SIGNAL ;
    PORT
      LAYER M4 ;
        RECT  17.088 9.744 17.28 9.768 ;
    END
  END o[72]
  PIN o[73]
    DIRECTION OUTPUT ;
    USE SIGNAL ;
    PORT
      LAYER M4 ;
        RECT  17.088 9.84 17.28 9.864 ;
    END
  END o[73]
  PIN o[74]
    DIRECTION OUTPUT ;
    USE SIGNAL ;
    PORT
      LAYER M4 ;
        RECT  17.088 9.936 17.28 9.96 ;
    END
  END o[74]
  PIN o[75]
    DIRECTION OUTPUT ;
    USE SIGNAL ;
    PORT
      LAYER M4 ;
        RECT  17.088 10.032 17.28 10.056 ;
    END
  END o[75]
  PIN o[76]
    DIRECTION OUTPUT ;
    USE SIGNAL ;
    PORT
      LAYER M4 ;
        RECT  17.088 10.176 17.28 10.2 ;
    END
  END o[76]
  PIN o[77]
    DIRECTION OUTPUT ;
    USE SIGNAL ;
    PORT
      LAYER M4 ;
        RECT  17.088 10.272 17.28 10.296 ;
    END
  END o[77]
  PIN o[78]
    DIRECTION OUTPUT ;
    USE SIGNAL ;
    PORT
      LAYER M4 ;
        RECT  17.088 10.368 17.28 10.392 ;
    END
  END o[78]
  PIN o[79]
    DIRECTION OUTPUT ;
    USE SIGNAL ;
    PORT
      LAYER M4 ;
        RECT  17.088 10.464 17.28 10.488 ;
    END
  END o[79]
  PIN o[7]
    DIRECTION OUTPUT ;
    USE SIGNAL ;
    PORT
      LAYER M4 ;
        RECT  17.088 2.976 17.28 3 ;
    END
  END o[7]
  PIN o[80]
    DIRECTION OUTPUT ;
    USE SIGNAL ;
    PORT
      LAYER M4 ;
        RECT  17.088 10.56 17.28 10.584 ;
    END
  END o[80]
  PIN o[81]
    DIRECTION OUTPUT ;
    USE SIGNAL ;
    PORT
      LAYER M4 ;
        RECT  17.088 10.656 17.28 10.68 ;
    END
  END o[81]
  PIN o[82]
    DIRECTION OUTPUT ;
    USE SIGNAL ;
    PORT
      LAYER M4 ;
        RECT  17.088 10.8 17.28 10.824 ;
    END
  END o[82]
  PIN o[83]
    DIRECTION OUTPUT ;
    USE SIGNAL ;
    PORT
      LAYER M4 ;
        RECT  17.088 10.896 17.28 10.92 ;
    END
  END o[83]
  PIN o[84]
    DIRECTION OUTPUT ;
    USE SIGNAL ;
    PORT
      LAYER M4 ;
        RECT  17.088 10.992 17.28 11.016 ;
    END
  END o[84]
  PIN o[85]
    DIRECTION OUTPUT ;
    USE SIGNAL ;
    PORT
      LAYER M4 ;
        RECT  17.088 11.088 17.28 11.112 ;
    END
  END o[85]
  PIN o[86]
    DIRECTION OUTPUT ;
    USE SIGNAL ;
    PORT
      LAYER M4 ;
        RECT  17.088 11.184 17.28 11.208 ;
    END
  END o[86]
  PIN o[87]
    DIRECTION OUTPUT ;
    USE SIGNAL ;
    PORT
      LAYER M4 ;
        RECT  17.088 11.28 17.28 11.304 ;
    END
  END o[87]
  PIN o[88]
    DIRECTION OUTPUT ;
    USE SIGNAL ;
    PORT
      LAYER M4 ;
        RECT  17.088 11.424 17.28 11.448 ;
    END
  END o[88]
  PIN o[89]
    DIRECTION OUTPUT ;
    USE SIGNAL ;
    PORT
      LAYER M4 ;
        RECT  17.088 11.52 17.28 11.544 ;
    END
  END o[89]
  PIN o[8]
    DIRECTION OUTPUT ;
    USE SIGNAL ;
    PORT
      LAYER M4 ;
        RECT  17.088 3.072 17.28 3.096 ;
    END
  END o[8]
  PIN o[90]
    DIRECTION OUTPUT ;
    USE SIGNAL ;
    PORT
      LAYER M4 ;
        RECT  17.088 11.616 17.28 11.64 ;
    END
  END o[90]
  PIN o[91]
    DIRECTION OUTPUT ;
    USE SIGNAL ;
    PORT
      LAYER M4 ;
        RECT  17.088 11.712 17.28 11.736 ;
    END
  END o[91]
  PIN o[92]
    DIRECTION OUTPUT ;
    USE SIGNAL ;
    PORT
      LAYER M4 ;
        RECT  17.088 11.808 17.28 11.832 ;
    END
  END o[92]
  PIN o[93]
    DIRECTION OUTPUT ;
    USE SIGNAL ;
    PORT
      LAYER M4 ;
        RECT  17.088 11.952 17.28 11.976 ;
    END
  END o[93]
  PIN o[94]
    DIRECTION OUTPUT ;
    USE SIGNAL ;
    PORT
      LAYER M4 ;
        RECT  17.088 12.048 17.28 12.072 ;
    END
  END o[94]
  PIN o[95]
    DIRECTION OUTPUT ;
    USE SIGNAL ;
    PORT
      LAYER M4 ;
        RECT  17.088 12.144 17.28 12.168 ;
    END
  END o[95]
  PIN o[96]
    DIRECTION OUTPUT ;
    USE SIGNAL ;
    PORT
      LAYER M4 ;
        RECT  17.088 12.24 17.28 12.264 ;
    END
  END o[96]
  PIN o[97]
    DIRECTION OUTPUT ;
    USE SIGNAL ;
    PORT
      LAYER M4 ;
        RECT  17.088 12.336 17.28 12.36 ;
    END
  END o[97]
  PIN o[98]
    DIRECTION OUTPUT ;
    USE SIGNAL ;
    PORT
      LAYER M4 ;
        RECT  17.088 12.432 17.28 12.456 ;
    END
  END o[98]
  PIN o[99]
    DIRECTION OUTPUT ;
    USE SIGNAL ;
    PORT
      LAYER M4 ;
        RECT  17.088 12.576 17.28 12.6 ;
    END
  END o[99]
  PIN o[9]
    DIRECTION OUTPUT ;
    USE SIGNAL ;
    PORT
      LAYER M4 ;
        RECT  17.088 3.168 17.28 3.192 ;
    END
  END o[9]
  PIN rs
    DIRECTION INPUT ;
    USE SIGNAL ;
    PORT
      LAYER M5 ;
        RECT  11.856 75.408 11.88 75.6 ;
    END
    PORT
      LAYER M5 ;
        RECT  11.856 72.949 11.88 75.472 ;
    END
  END rs
  PIN VDD
    DIRECTION INOUT ;
    USE POWER ;
    PORT
      LAYER M5 ;
        RECT  13.392 2.151 13.512 73.449 ;
        RECT  10.692 2.151 10.812 73.449 ;
        RECT  7.992 2.151 8.112 73.449 ;
        RECT  5.292 2.151 5.412 73.449 ;
        RECT  2.592 2.151 2.712 73.449 ;
    END
  END VDD
  PIN VSS
    DIRECTION INOUT ;
    USE GROUND ;
    PORT
      LAYER M5 ;
        RECT  13.2 2.137 13.32 73.463 ;
        RECT  10.5 2.137 10.62 73.463 ;
        RECT  7.8 2.137 7.92 73.463 ;
        RECT  5.1 2.137 5.22 73.463 ;
        RECT  2.4 2.137 2.52 73.463 ;
    END
  END VSS
  # OT_OBS_CLOSED layer=M5 d_um=1.536 added=56
  OBS
    LAYER RVTN ;
     RECT  2.16 2.16 15.12 2.295 ;
     RECT  2.16 2.565 15.12 2.835 ;
     RECT  2.16 3.105 15.12 3.375 ;
     RECT  2.16 3.645 15.12 3.915 ;
     RECT  2.16 4.185 15.12 4.455 ;
     RECT  2.16 4.725 15.12 4.995 ;
     RECT  2.16 5.265 15.12 5.535 ;
     RECT  2.16 5.805 15.12 6.075 ;
     RECT  2.16 6.345 15.12 6.615 ;
     RECT  2.16 6.885 15.12 7.155 ;
     RECT  2.16 7.425 15.12 7.695 ;
     RECT  2.16 7.965 15.12 8.235 ;
     RECT  2.16 8.505 15.12 8.775 ;
     RECT  2.16 9.045 15.12 9.315 ;
     RECT  2.16 9.585 15.12 9.855 ;
     RECT  2.16 10.125 15.12 10.395 ;
     RECT  2.16 10.665 15.12 10.935 ;
     RECT  2.16 11.205 15.12 11.475 ;
     RECT  2.16 11.745 15.12 12.015 ;
     RECT  2.16 12.285 15.12 12.555 ;
     RECT  2.16 12.825 15.12 13.095 ;
     RECT  2.16 13.365 15.12 13.635 ;
     RECT  2.16 13.905 15.12 14.175 ;
     RECT  2.16 14.445 15.12 14.715 ;
     RECT  2.16 14.985 15.12 15.255 ;
     RECT  2.16 15.525 15.12 15.795 ;
     RECT  2.16 16.065 15.12 16.335 ;
     RECT  2.16 16.605 15.12 16.875 ;
     RECT  2.16 17.145 15.12 17.415 ;
     RECT  2.16 17.685 15.12 17.955 ;
     RECT  2.16 18.225 15.12 18.495 ;
     RECT  2.16 18.765 15.12 19.035 ;
     RECT  2.16 19.305 15.12 19.575 ;
     RECT  2.16 19.845 15.12 20.115 ;
     RECT  2.16 20.385 15.12 20.655 ;
     RECT  2.16 20.925 15.12 21.195 ;
     RECT  2.16 21.465 15.12 21.735 ;
     RECT  2.16 22.005 15.12 22.275 ;
     RECT  2.16 22.545 15.12 22.815 ;
     RECT  2.16 23.085 15.12 23.355 ;
     RECT  2.16 23.625 15.12 23.895 ;
     RECT  2.16 24.165 15.12 24.435 ;
     RECT  2.16 24.705 15.12 24.975 ;
     RECT  2.16 25.245 15.12 25.515 ;
     RECT  2.16 25.785 15.12 26.055 ;
     RECT  2.16 26.325 15.12 26.595 ;
     RECT  2.16 26.865 15.12 27.135 ;
     RECT  2.16 27.405 15.12 27.675 ;
     RECT  2.16 27.945 15.12 28.215 ;
     RECT  2.16 28.485 15.12 28.755 ;
     RECT  2.16 29.025 15.12 29.295 ;
     RECT  2.16 29.565 15.12 29.835 ;
     RECT  2.16 30.105 15.12 30.375 ;
     RECT  2.16 30.645 15.12 30.915 ;
     RECT  2.16 31.185 15.12 31.455 ;
     RECT  2.16 31.725 15.12 31.995 ;
     RECT  2.16 32.265 15.12 32.535 ;
     RECT  2.16 32.805 15.12 33.075 ;
     RECT  2.16 33.345 15.12 33.615 ;
     RECT  2.16 33.885 15.12 34.155 ;
     RECT  2.16 34.425 15.12 34.695 ;
     RECT  2.16 34.965 15.12 35.235 ;
     RECT  2.16 35.505 15.12 35.775 ;
     RECT  2.16 36.045 15.12 36.315 ;
     RECT  2.16 36.585 15.12 36.855 ;
     RECT  2.16 37.125 15.12 37.395 ;
     RECT  2.16 37.665 15.12 37.935 ;
     RECT  2.16 38.205 15.12 38.475 ;
     RECT  2.16 38.745 15.12 39.015 ;
     RECT  2.16 39.285 15.12 39.555 ;
     RECT  2.16 39.825 15.12 40.095 ;
     RECT  2.16 40.365 15.12 40.635 ;
     RECT  2.16 40.905 15.12 41.175 ;
     RECT  2.16 41.445 15.12 41.715 ;
     RECT  2.16 41.985 15.12 42.255 ;
     RECT  2.16 42.525 15.12 42.795 ;
     RECT  2.16 43.065 15.12 43.335 ;
     RECT  2.16 43.605 15.12 43.875 ;
     RECT  2.16 44.145 15.12 44.415 ;
     RECT  2.16 44.685 15.12 44.955 ;
     RECT  2.16 45.225 15.12 45.495 ;
     RECT  2.16 45.765 15.12 46.035 ;
     RECT  2.16 46.305 15.12 46.575 ;
     RECT  2.16 46.845 15.12 47.115 ;
     RECT  2.16 47.385 15.12 47.655 ;
     RECT  2.16 47.925 15.12 48.195 ;
     RECT  2.16 48.465 15.12 48.735 ;
     RECT  2.16 49.005 15.12 49.275 ;
     RECT  2.16 49.545 15.12 49.815 ;
     RECT  2.16 50.085 15.12 50.355 ;
     RECT  2.16 50.625 15.12 50.895 ;
     RECT  2.16 51.165 15.12 51.435 ;
     RECT  2.16 51.705 15.12 51.975 ;
     RECT  2.16 52.245 15.12 52.515 ;
     RECT  2.16 52.785 15.12 53.055 ;
     RECT  2.16 53.325 15.12 53.595 ;
     RECT  2.16 53.865 15.12 54.135 ;
     RECT  2.16 54.405 15.12 54.675 ;
     RECT  2.16 54.945 15.12 55.215 ;
     RECT  2.16 55.485 15.12 55.755 ;
     RECT  2.16 56.025 15.12 56.295 ;
     RECT  2.16 56.565 15.12 56.835 ;
     RECT  2.16 57.105 15.12 57.375 ;
     RECT  2.16 57.645 15.12 57.915 ;
     RECT  2.16 58.185 15.12 58.455 ;
     RECT  2.16 58.725 15.12 58.995 ;
     RECT  2.16 59.265 15.12 59.535 ;
     RECT  2.16 59.805 15.12 60.075 ;
     RECT  2.16 60.345 15.12 60.615 ;
     RECT  2.16 60.885 15.12 61.155 ;
     RECT  2.16 61.425 15.12 61.695 ;
     RECT  2.16 61.965 15.12 62.235 ;
     RECT  2.16 62.505 15.12 62.775 ;
     RECT  2.16 63.045 15.12 63.315 ;
     RECT  2.16 63.585 15.12 63.855 ;
     RECT  2.16 64.125 15.12 64.395 ;
     RECT  2.16 64.665 15.12 64.935 ;
     RECT  2.16 65.205 15.12 65.475 ;
     RECT  2.16 65.745 15.12 66.015 ;
     RECT  2.16 66.285 15.12 66.555 ;
     RECT  2.16 66.825 15.12 67.095 ;
     RECT  2.16 67.365 15.12 67.635 ;
     RECT  2.16 67.905 15.12 68.175 ;
     RECT  2.16 68.445 15.12 68.715 ;
     RECT  2.16 68.985 15.12 69.255 ;
     RECT  2.16 69.525 15.12 69.795 ;
     RECT  2.16 70.065 15.12 70.335 ;
     RECT  2.16 70.605 15.12 70.875 ;
     RECT  2.16 71.145 15.12 71.415 ;
     RECT  2.16 71.685 15.12 71.955 ;
     RECT  2.16 72.225 15.12 72.495 ;
     RECT  2.16 72.765 15.12 73.035 ;
     RECT  2.16 73.305 15.12 73.44 ;
    LAYER RVTP ;
     RECT  2.16 2.295 15.12 2.565 ;
     RECT  2.16 2.835 15.12 3.105 ;
     RECT  2.16 3.375 15.12 3.645 ;
     RECT  2.16 3.915 15.12 4.185 ;
     RECT  2.16 4.455 15.12 4.725 ;
     RECT  2.16 4.995 15.12 5.265 ;
     RECT  2.16 5.535 15.12 5.805 ;
     RECT  2.16 6.075 15.12 6.345 ;
     RECT  2.16 6.615 15.12 6.885 ;
     RECT  2.16 7.155 15.12 7.425 ;
     RECT  2.16 7.695 15.12 7.965 ;
     RECT  2.16 8.235 15.12 8.505 ;
     RECT  2.16 8.775 15.12 9.045 ;
     RECT  2.16 9.315 15.12 9.585 ;
     RECT  2.16 9.855 15.12 10.125 ;
     RECT  2.16 10.395 15.12 10.665 ;
     RECT  2.16 10.935 15.12 11.205 ;
     RECT  2.16 11.475 15.12 11.745 ;
     RECT  2.16 12.015 15.12 12.285 ;
     RECT  2.16 12.555 15.12 12.825 ;
     RECT  2.16 13.095 15.12 13.365 ;
     RECT  2.16 13.635 15.12 13.905 ;
     RECT  2.16 14.175 15.12 14.445 ;
     RECT  2.16 14.715 15.12 14.985 ;
     RECT  2.16 15.255 15.12 15.525 ;
     RECT  2.16 15.795 15.12 16.065 ;
     RECT  2.16 16.335 15.12 16.605 ;
     RECT  2.16 16.875 15.12 17.145 ;
     RECT  2.16 17.415 15.12 17.685 ;
     RECT  2.16 17.955 15.12 18.225 ;
     RECT  2.16 18.495 15.12 18.765 ;
     RECT  2.16 19.035 15.12 19.305 ;
     RECT  2.16 19.575 15.12 19.845 ;
     RECT  2.16 20.115 15.12 20.385 ;
     RECT  2.16 20.655 15.12 20.925 ;
     RECT  2.16 21.195 15.12 21.465 ;
     RECT  2.16 21.735 15.12 22.005 ;
     RECT  2.16 22.275 15.12 22.545 ;
     RECT  2.16 22.815 15.12 23.085 ;
     RECT  2.16 23.355 15.12 23.625 ;
     RECT  2.16 23.895 15.12 24.165 ;
     RECT  2.16 24.435 15.12 24.705 ;
     RECT  2.16 24.975 15.12 25.245 ;
     RECT  2.16 25.515 15.12 25.785 ;
     RECT  2.16 26.055 15.12 26.325 ;
     RECT  2.16 26.595 15.12 26.865 ;
     RECT  2.16 27.135 15.12 27.405 ;
     RECT  2.16 27.675 15.12 27.945 ;
     RECT  2.16 28.215 15.12 28.485 ;
     RECT  2.16 28.755 15.12 29.025 ;
     RECT  2.16 29.295 15.12 29.565 ;
     RECT  2.16 29.835 15.12 30.105 ;
     RECT  2.16 30.375 15.12 30.645 ;
     RECT  2.16 30.915 15.12 31.185 ;
     RECT  2.16 31.455 15.12 31.725 ;
     RECT  2.16 31.995 15.12 32.265 ;
     RECT  2.16 32.535 15.12 32.805 ;
     RECT  2.16 33.075 15.12 33.345 ;
     RECT  2.16 33.615 15.12 33.885 ;
     RECT  2.16 34.155 15.12 34.425 ;
     RECT  2.16 34.695 15.12 34.965 ;
     RECT  2.16 35.235 15.12 35.505 ;
     RECT  2.16 35.775 15.12 36.045 ;
     RECT  2.16 36.315 15.12 36.585 ;
     RECT  2.16 36.855 15.12 37.125 ;
     RECT  2.16 37.395 15.12 37.665 ;
     RECT  2.16 37.935 15.12 38.205 ;
     RECT  2.16 38.475 15.12 38.745 ;
     RECT  2.16 39.015 15.12 39.285 ;
     RECT  2.16 39.555 15.12 39.825 ;
     RECT  2.16 40.095 15.12 40.365 ;
     RECT  2.16 40.635 15.12 40.905 ;
     RECT  2.16 41.175 15.12 41.445 ;
     RECT  2.16 41.715 15.12 41.985 ;
     RECT  2.16 42.255 15.12 42.525 ;
     RECT  2.16 42.795 15.12 43.065 ;
     RECT  2.16 43.335 15.12 43.605 ;
     RECT  2.16 43.875 15.12 44.145 ;
     RECT  2.16 44.415 15.12 44.685 ;
     RECT  2.16 44.955 15.12 45.225 ;
     RECT  2.16 45.495 15.12 45.765 ;
     RECT  2.16 46.035 15.12 46.305 ;
     RECT  2.16 46.575 15.12 46.845 ;
     RECT  2.16 47.115 15.12 47.385 ;
     RECT  2.16 47.655 15.12 47.925 ;
     RECT  2.16 48.195 15.12 48.465 ;
     RECT  2.16 48.735 15.12 49.005 ;
     RECT  2.16 49.275 15.12 49.545 ;
     RECT  2.16 49.815 15.12 50.085 ;
     RECT  2.16 50.355 15.12 50.625 ;
     RECT  2.16 50.895 15.12 51.165 ;
     RECT  2.16 51.435 15.12 51.705 ;
     RECT  2.16 51.975 15.12 52.245 ;
     RECT  2.16 52.515 15.12 52.785 ;
     RECT  2.16 53.055 15.12 53.325 ;
     RECT  2.16 53.595 15.12 53.865 ;
     RECT  2.16 54.135 15.12 54.405 ;
     RECT  2.16 54.675 15.12 54.945 ;
     RECT  2.16 55.215 15.12 55.485 ;
     RECT  2.16 55.755 15.12 56.025 ;
     RECT  2.16 56.295 15.12 56.565 ;
     RECT  2.16 56.835 15.12 57.105 ;
     RECT  2.16 57.375 15.12 57.645 ;
     RECT  2.16 57.915 15.12 58.185 ;
     RECT  2.16 58.455 15.12 58.725 ;
     RECT  2.16 58.995 15.12 59.265 ;
     RECT  2.16 59.535 15.12 59.805 ;
     RECT  2.16 60.075 15.12 60.345 ;
     RECT  2.16 60.615 15.12 60.885 ;
     RECT  2.16 61.155 15.12 61.425 ;
     RECT  2.16 61.695 15.12 61.965 ;
     RECT  2.16 62.235 15.12 62.505 ;
     RECT  2.16 62.775 15.12 63.045 ;
     RECT  2.16 63.315 15.12 63.585 ;
     RECT  2.16 63.855 15.12 64.125 ;
     RECT  2.16 64.395 15.12 64.665 ;
     RECT  2.16 64.935 15.12 65.205 ;
     RECT  2.16 65.475 15.12 65.745 ;
     RECT  2.16 66.015 15.12 66.285 ;
     RECT  2.16 66.555 15.12 66.825 ;
     RECT  2.16 67.095 15.12 67.365 ;
     RECT  2.16 67.635 15.12 67.905 ;
     RECT  2.16 68.175 15.12 68.445 ;
     RECT  2.16 68.715 15.12 68.985 ;
     RECT  2.16 69.255 15.12 69.525 ;
     RECT  2.16 69.795 15.12 70.065 ;
     RECT  2.16 70.335 15.12 70.605 ;
     RECT  2.16 70.875 15.12 71.145 ;
     RECT  2.16 71.415 15.12 71.685 ;
     RECT  2.16 71.955 15.12 72.225 ;
     RECT  2.16 72.495 15.12 72.765 ;
     RECT  2.16 73.035 15.12 73.305 ;
    LAYER M1 ;
     RECT  2.16 2.151 15.12 73.449 ;
    LAYER M2 ;
     RECT  0.211 53.838 0.283 53.856 ;
     RECT  0.211 8.784 0.311 8.802 ;
     RECT  0.211 10.026 0.311 10.62 ;
     RECT  0.211 14.796 0.311 14.814 ;
     RECT  0.211 19.35 0.311 19.368 ;
     RECT  0.211 24.642 0.311 24.66 ;
     RECT  0.211 29.916 0.311 29.934 ;
     RECT  0.211 30.771 0.311 30.789 ;
     RECT  0.211 35.55 0.311 35.568 ;
     RECT  0.211 47.322 0.311 47.34 ;
     RECT  0.211 55.152 0.311 55.17 ;
     RECT  0.211 69.534 0.311 69.552 ;
     RECT  0.211 71.226 0.311 71.244 ;
     RECT  0.247 7.938 0.347 7.956 ;
     RECT  0.283 21.132 0.383 21.15 ;
     RECT  0.283 53.568 0.383 53.856 ;
     RECT  0.319 22.752 0.419 22.914 ;
     RECT  0.355 18.846 0.455 18.864 ;
     RECT  0.391 8.172 0.491 8.19 ;
     RECT  0.499 2.466 0.535 2.484 ;
     RECT  0.211 63.252 0.535 63.27 ;
     RECT  0.535 3.96 0.571 3.978 ;
     RECT  0.535 2.106 0.635 2.556 ;
     RECT  0.535 27.342 0.635 27.504 ;
     RECT  0.211 61.398 0.635 61.416 ;
     RECT  0.635 2.106 2.16 2.484 ;
     RECT  0.571 3.96 2.16 4.248 ;
     RECT  0.311 10.026 2.16 10.044 ;
     RECT  0.535 12.528 2.16 12.546 ;
     RECT  0.419 22.752 2.16 22.77 ;
     RECT  0.635 27.342 2.16 27.36 ;
     RECT  0.355 42.732 2.16 42.75 ;
     RECT  0.535 47.736 2.16 47.754 ;
     RECT  0.535 49.554 2.16 49.572 ;
     RECT  0.535 53.946 2.16 53.964 ;
     RECT  0.535 57.276 2.16 57.294 ;
     RECT  0.535 58.662 2.16 59.022 ;
     RECT  0.535 63.054 2.16 64.224 ;
     RECT  0.535 69.462 2.16 69.48 ;
     RECT  0.211 72.738 2.16 72.756 ;
     RECT  2.16 2.106 4.423 73.449 ;
     RECT  4.423 2.106 4.495 73.494 ;
     RECT  4.495 2.07 6.151 73.494 ;
     RECT  6.151 2.07 6.835 73.53 ;
     RECT  6.835 2.07 10.427 73.602 ;
     RECT  10.427 2.07 10.931 73.53 ;
     RECT  10.931 2.07 13.019 73.494 ;
     RECT  13.019 2.151 15.12 73.449 ;
     RECT  15.12 2.196 15.431 73.332 ;
     RECT  15.431 3.114 15.467 36.882 ;
     RECT  15.431 37.836 15.467 38.43 ;
     RECT  15.431 39.186 15.467 73.332 ;
     RECT  15.467 50.436 15.971 73.332 ;
     RECT  15.431 2.196 16.007 2.322 ;
     RECT  15.467 3.114 16.007 13.194 ;
     RECT  15.467 13.986 16.007 36.882 ;
     RECT  15.467 39.186 16.007 49.464 ;
     RECT  15.971 50.436 16.007 66.384 ;
     RECT  15.971 67.266 16.007 73.332 ;
     RECT  16.007 22.986 16.043 30.474 ;
     RECT  16.007 42.966 16.043 45.414 ;
     RECT  16.007 46.206 16.043 47.304 ;
     RECT  16.043 22.986 16.079 28.314 ;
     RECT  16.007 3.15 16.511 13.086 ;
     RECT  16.007 14.256 16.511 14.634 ;
     RECT  16.007 15.462 16.511 22.23 ;
     RECT  16.079 22.986 16.511 26.316 ;
     RECT  16.079 27.216 16.511 28.314 ;
     RECT  16.007 31.464 16.511 36.81 ;
     RECT  15.467 37.836 16.511 38.394 ;
     RECT  16.007 39.186 16.511 42.174 ;
     RECT  16.043 42.966 16.511 44.604 ;
     RECT  16.043 45.396 16.511 45.414 ;
     RECT  16.043 46.206 16.511 47.178 ;
     RECT  16.007 48.366 16.511 49.338 ;
     RECT  16.007 50.436 16.511 52.974 ;
     RECT  16.007 53.766 16.511 58.14 ;
     RECT  16.007 61.164 16.511 62.46 ;
     RECT  16.007 63.216 16.511 66.384 ;
     RECT  16.007 67.266 16.511 69.282 ;
     RECT  16.007 70.038 16.511 71.712 ;
     RECT  16.007 72.576 16.511 73.332 ;
     RECT  16.511 3.15 16.547 8.334 ;
     RECT  16.511 9.252 16.547 13.086 ;
     RECT  16.511 14.256 16.547 14.472 ;
     RECT  16.511 15.462 16.547 19.296 ;
     RECT  16.511 20.196 16.547 22.23 ;
     RECT  16.511 22.986 16.547 23.004 ;
     RECT  16.511 23.868 16.547 26.316 ;
     RECT  16.511 27.216 16.547 27.234 ;
     RECT  16.511 28.026 16.547 28.314 ;
     RECT  16.043 29.376 16.547 30.474 ;
     RECT  16.511 31.464 16.547 32.49 ;
     RECT  16.511 33.354 16.547 36.81 ;
     RECT  16.511 38.376 16.547 38.394 ;
     RECT  16.511 39.528 16.547 41.976 ;
     RECT  16.511 42.966 16.547 43.83 ;
     RECT  16.511 44.586 16.547 44.604 ;
     RECT  16.511 46.386 16.547 47.178 ;
     RECT  16.511 48.978 16.547 49.338 ;
     RECT  16.511 50.436 16.547 52.812 ;
     RECT  16.511 54.216 16.547 54.234 ;
     RECT  16.511 55.026 16.547 58.14 ;
     RECT  16.007 58.932 16.547 59.634 ;
     RECT  16.007 60.39 16.547 60.408 ;
     RECT  16.511 61.164 16.547 61.182 ;
     RECT  16.511 62.01 16.547 62.46 ;
     RECT  16.511 63.216 16.547 63.684 ;
     RECT  16.511 64.44 16.547 66.384 ;
     RECT  16.511 67.806 16.547 69.282 ;
     RECT  16.511 70.038 16.547 70.128 ;
     RECT  16.511 71.388 16.547 71.712 ;
     RECT  16.511 72.576 16.547 73.134 ;
     RECT  16.547 4.662 16.583 4.68 ;
     RECT  16.547 5.472 16.583 5.49 ;
     RECT  16.547 9.936 16.583 9.954 ;
     RECT  16.547 16.236 16.583 16.83 ;
     RECT  16.547 21.24 16.583 21.258 ;
     RECT  16.547 26.028 16.583 26.046 ;
     RECT  16.547 29.376 16.583 29.394 ;
     RECT  16.547 36.486 16.583 36.684 ;
     RECT  16.547 40.176 16.583 40.194 ;
     RECT  16.547 50.868 16.583 52.614 ;
     RECT  16.547 55.296 16.583 55.314 ;
     RECT  16.547 56.538 16.583 56.664 ;
     RECT  16.547 62.172 16.583 62.424 ;
     RECT  16.547 65.556 16.583 65.574 ;
     RECT  16.547 70.038 16.583 70.056 ;
     RECT  16.547 72.81 16.583 72.828 ;
     RECT  16.547 41.922 16.619 41.94 ;
     RECT  16.583 52.254 16.619 52.272 ;
     RECT  16.583 56.646 16.619 56.664 ;
     RECT  16.583 62.406 16.619 62.424 ;
     RECT  16.547 67.806 17.087 68.4 ;
    LAYER M3 ;
     RECT  4.5 2.065 4.518 2.143 ;
     RECT  8.568 2.101 8.586 2.143 ;
     RECT  12.996 2.065 13.014 2.143 ;
     RECT  7.815 2.143 8.586 2.191 ;
     RECT  2.415 2.143 2.505 2.203 ;
     RECT  10.515 2.143 10.605 2.227 ;
     RECT  2.304 2.203 2.505 2.263 ;
     RECT  9.9 2.227 10.605 2.263 ;
     RECT  4.5 2.143 5.205 2.299 ;
     RECT  7.704 2.191 8.586 2.299 ;
     RECT  12.996 2.143 13.305 2.299 ;
     RECT  12.924 2.299 13.305 2.335 ;
     RECT  7.02 2.299 8.586 2.371 ;
     RECT  12.6 2.335 13.305 2.371 ;
     RECT  4.14 2.299 5.205 2.413 ;
     RECT  9.684 2.263 10.605 2.413 ;
     RECT  14.832 2.347 14.85 2.443 ;
     RECT  15.984 2.191 16.002 2.443 ;
     RECT  0.54 2.101 0.558 2.461 ;
     RECT  12.6 2.371 13.878 2.489 ;
     RECT  0.504 2.461 0.558 2.491 ;
     RECT  4.14 2.413 5.397 2.497 ;
     RECT  9.684 2.413 10.797 2.525 ;
     RECT  4.14 2.497 6.102 2.533 ;
     RECT  7.02 2.371 8.766 2.533 ;
     RECT  9.684 2.525 9.738 2.533 ;
     RECT  0.504 2.491 0.63 2.561 ;
     RECT  0.504 2.561 0.558 2.573 ;
     RECT  4.14 2.533 9.738 2.605 ;
     RECT  2.304 2.263 3.222 2.641 ;
     RECT  2.268 2.641 3.222 2.765 ;
     RECT  2.304 2.765 3.222 2.875 ;
     RECT  12.6 2.489 13.806 2.875 ;
     RECT  12.132 2.875 13.806 2.911 ;
     RECT  14.832 2.443 16.002 2.971 ;
     RECT  0.504 2.573 0.522 3.005 ;
     RECT  11.88 2.911 13.806 3.029 ;
     RECT  11.88 3.029 11.898 3.181 ;
     RECT  11.808 3.181 11.898 3.209 ;
     RECT  4.068 2.605 9.738 3.259 ;
     RECT  14.832 2.971 16.542 3.293 ;
     RECT  11.808 3.209 11.826 3.299 ;
     RECT  12.708 3.029 13.806 3.299 ;
     RECT  13.032 3.299 13.806 3.344 ;
     RECT  2.304 2.875 3.258 3.379 ;
     RECT  4.068 3.259 9.774 3.379 ;
     RECT  13.215 3.344 13.806 3.541 ;
     RECT  14.832 3.293 15.426 3.541 ;
     RECT  2.304 3.379 9.774 3.577 ;
     RECT  10.515 2.525 10.797 3.577 ;
     RECT  0.252 3.115 0.27 3.787 ;
     RECT  11.592 3.649 11.61 3.839 ;
     RECT  2.304 3.577 10.797 3.875 ;
     RECT  2.304 3.875 9.774 4.013 ;
     RECT  16.524 3.293 16.542 4.072 ;
     RECT  2.304 4.013 9.378 4.109 ;
     RECT  0.252 3.787 0.594 4.253 ;
     RECT  13.215 3.541 15.426 4.363 ;
     RECT  2.304 4.109 5.397 4.379 ;
     RECT  0.252 4.253 0.342 4.541 ;
     RECT  4.068 4.379 5.397 4.649 ;
     RECT  16.488 4.072 16.542 4.657 ;
     RECT  10.515 3.875 10.797 4.729 ;
     RECT  13.104 4.363 15.426 4.729 ;
     RECT  0.252 4.541 0.27 4.733 ;
     RECT  13.032 4.729 15.426 4.747 ;
     RECT  2.304 4.379 3.258 4.765 ;
     RECT  10.515 4.729 10.854 4.801 ;
     RECT  13.032 4.747 15.462 4.829 ;
     RECT  2.268 4.765 3.258 4.877 ;
     RECT  11.988 4.621 12.006 4.919 ;
     RECT  10.515 4.801 11.178 5.099 ;
     RECT  13.215 4.829 15.462 5.099 ;
     RECT  6.156 4.109 9.378 5.131 ;
     RECT  10.515 5.099 10.926 5.161 ;
     RECT  4.068 4.649 4.194 5.197 ;
     RECT  6.12 5.131 9.378 5.197 ;
     RECT  10.116 5.161 10.926 5.197 ;
     RECT  6.12 5.197 10.926 5.213 ;
     RECT  5.004 4.649 5.397 5.224 ;
     RECT  6.12 5.213 9.702 5.224 ;
     RECT  13.215 5.099 15.426 5.261 ;
     RECT  14.796 5.261 15.426 5.267 ;
     RECT  13.215 5.261 14.022 5.369 ;
     RECT  16.488 4.657 16.578 5.495 ;
     RECT  2.304 4.877 3.258 5.737 ;
     RECT  4.032 5.197 4.194 5.737 ;
     RECT  2.304 5.737 4.194 5.773 ;
     RECT  5.004 5.224 9.702 5.773 ;
     RECT  0.252 5.755 0.27 5.803 ;
     RECT  2.304 5.773 9.702 5.837 ;
     RECT  13.215 5.369 13.59 5.845 ;
     RECT  0.252 5.803 0.342 5.851 ;
     RECT  10.515 5.213 10.926 5.851 ;
     RECT  14.796 5.267 14.886 6.007 ;
     RECT  12.528 5.845 13.59 6.029 ;
     RECT  5.115 5.837 9.702 6.043 ;
     RECT  10.515 5.851 11.43 6.079 ;
     RECT  10.515 6.079 11.466 6.151 ;
     RECT  0.252 5.851 0.414 6.221 ;
     RECT  10.515 6.151 12.474 6.269 ;
     RECT  16.488 5.495 16.542 6.269 ;
     RECT  5.115 6.043 9.774 6.385 ;
     RECT  10.515 6.269 10.854 6.385 ;
     RECT  14.328 6.007 15.462 6.539 ;
     RECT  13.215 6.029 13.59 6.619 ;
     RECT  14.328 6.539 14.886 6.619 ;
     RECT  0.252 6.221 0.342 6.653 ;
     RECT  2.304 5.837 4.194 6.655 ;
     RECT  5.115 6.385 10.854 6.655 ;
     RECT  13.215 6.619 14.886 6.719 ;
     RECT  0.324 6.653 0.342 6.749 ;
     RECT  2.304 6.655 10.854 6.809 ;
     RECT  14.832 6.719 14.886 6.845 ;
     RECT  11.952 6.269 12.474 7.087 ;
     RECT  13.215 6.719 13.95 7.087 ;
     RECT  16.524 6.269 16.542 7.087 ;
     RECT  15.984 7.087 16.542 7.181 ;
     RECT  11.952 7.087 13.95 7.195 ;
     RECT  11.772 7.195 13.95 7.349 ;
     RECT  14.868 6.845 14.886 7.349 ;
     RECT  11.772 7.349 11.79 7.421 ;
     RECT  12.6 7.349 13.95 7.501 ;
     RECT  3.96 6.809 10.797 7.699 ;
     RECT  3.96 7.699 10.854 7.727 ;
     RECT  2.304 6.809 3.186 7.771 ;
     RECT  3.96 7.727 4.302 7.771 ;
     RECT  12.6 7.501 13.986 7.771 ;
     RECT  12.6 7.771 14.13 7.889 ;
     RECT  0.252 7.723 0.27 7.915 ;
     RECT  5.112 7.727 10.854 7.933 ;
     RECT  13.215 7.889 14.13 7.933 ;
     RECT  0.252 7.915 0.342 8.155 ;
     RECT  0.252 8.155 0.414 8.167 ;
     RECT  13.215 7.933 14.346 8.195 ;
     RECT  0.252 8.167 0.486 8.237 ;
     RECT  5.112 7.933 10.926 8.267 ;
     RECT  16.488 7.181 16.542 8.339 ;
     RECT  15.408 7.501 15.462 8.395 ;
     RECT  16.488 8.339 16.506 8.395 ;
     RECT  0.252 8.237 0.414 8.429 ;
     RECT  2.304 7.771 4.302 8.429 ;
     RECT  4.176 8.429 4.302 8.539 ;
     RECT  0.252 8.429 0.306 8.587 ;
     RECT  4.176 8.539 4.374 8.671 ;
     RECT  5.112 8.267 10.797 8.671 ;
     RECT  13.215 8.195 14.022 8.671 ;
     RECT  15.408 8.395 16.506 8.683 ;
     RECT  13.104 8.671 14.022 8.707 ;
     RECT  0.216 8.587 0.306 8.807 ;
     RECT  12.168 8.311 12.186 8.815 ;
     RECT  12.924 8.707 14.022 8.941 ;
     RECT  14.832 8.683 16.506 8.941 ;
     RECT  4.176 8.671 10.797 8.969 ;
     RECT  12.132 8.815 12.186 8.969 ;
     RECT  12.924 8.941 16.506 9.041 ;
     RECT  12.924 9.041 13.878 9.053 ;
     RECT  0.252 8.807 0.27 9.101 ;
     RECT  6.3 8.969 10.797 9.113 ;
     RECT  12.924 9.053 13.77 9.121 ;
     RECT  14.832 9.041 16.506 9.149 ;
     RECT  16.488 9.149 16.506 9.211 ;
     RECT  1.152 9.115 1.17 9.293 ;
     RECT  2.304 8.429 3.438 9.307 ;
     RECT  4.176 8.969 5.562 9.509 ;
     RECT  2.196 9.307 3.438 9.545 ;
     RECT  16.488 9.211 16.542 9.643 ;
     RECT  6.3 9.113 6.57 9.751 ;
     RECT  12.708 9.121 13.77 9.787 ;
     RECT  7.308 9.113 10.797 9.859 ;
     RECT  2.304 9.545 3.438 9.883 ;
     RECT  4.176 9.509 5.49 9.883 ;
     RECT  7.308 9.859 10.854 9.883 ;
     RECT  7.308 9.883 11.43 9.887 ;
     RECT  6.264 9.751 6.57 9.895 ;
     RECT  7.308 9.887 9.702 9.895 ;
     RECT  10.515 9.887 11.43 9.959 ;
     RECT  12.456 9.787 13.77 9.959 ;
     RECT  16.488 9.643 16.578 9.959 ;
     RECT  14.832 9.149 15.426 10.027 ;
     RECT  16.488 9.959 16.542 10.027 ;
     RECT  2.304 9.883 5.49 10.121 ;
     RECT  14.832 10.027 16.542 10.291 ;
     RECT  0.216 9.931 0.234 10.411 ;
     RECT  12.456 9.959 13.662 10.471 ;
     RECT  4.032 10.121 5.49 10.603 ;
     RECT  6.264 9.895 9.702 10.603 ;
     RECT  0.216 10.411 0.306 10.625 ;
     RECT  2.304 10.121 3.258 10.637 ;
     RECT  4.032 10.603 9.702 10.867 ;
     RECT  10.515 9.959 10.797 10.867 ;
     RECT  4.032 10.867 10.797 10.895 ;
     RECT  12.384 10.471 13.662 10.939 ;
     RECT  14.652 10.291 16.542 10.939 ;
     RECT  4.068 10.895 10.797 10.975 ;
     RECT  12.384 10.939 16.542 11.128 ;
     RECT  11.988 11.128 16.542 11.129 ;
     RECT  11.988 11.129 14.922 11.281 ;
     RECT  11.808 11.281 14.922 11.399 ;
     RECT  2.34 10.637 3.258 11.407 ;
     RECT  15.984 11.129 16.542 11.453 ;
     RECT  0.252 10.625 0.27 11.645 ;
     RECT  4.068 10.975 10.89 11.659 ;
     RECT  12.06 11.399 13.95 11.669 ;
     RECT  4.068 11.659 10.926 11.849 ;
     RECT  2.304 11.407 3.258 11.947 ;
     RECT  4.068 11.849 10.797 11.947 ;
     RECT  14.76 11.399 14.922 11.981 ;
     RECT  12.132 11.669 13.95 11.984 ;
     RECT  14.832 11.981 14.922 12.181 ;
     RECT  12.132 11.984 13.734 12.479 ;
     RECT  0.288 12.139 0.414 12.523 ;
     RECT  12.348 12.479 13.734 12.551 ;
     RECT  0.288 12.523 0.558 12.571 ;
     RECT  0.288 12.571 1.17 12.605 ;
     RECT  2.304 11.947 10.797 12.623 ;
     RECT  14.832 12.181 15.426 12.631 ;
     RECT  16.524 11.453 16.542 12.631 ;
     RECT  2.304 12.623 5.397 12.785 ;
     RECT  6.192 12.623 10.797 12.845 ;
     RECT  6.192 12.845 9.702 12.893 ;
     RECT  10.515 12.845 10.797 12.991 ;
     RECT  14.832 12.631 16.542 12.991 ;
     RECT  1.152 12.605 1.17 13.037 ;
     RECT  14.292 12.991 16.542 13.091 ;
     RECT  6.192 12.893 9.63 13.181 ;
     RECT  0.288 12.605 0.414 13.325 ;
     RECT  12.348 12.551 13.497 13.339 ;
     RECT  0.396 13.325 0.414 13.421 ;
     RECT  11.988 13.339 13.497 13.559 ;
     RECT  2.304 12.785 4.338 13.627 ;
     RECT  5.076 12.785 5.397 13.627 ;
     RECT  12.24 13.559 13.497 13.627 ;
     RECT  14.292 13.091 16.002 13.627 ;
     RECT  12.24 13.627 16.002 13.631 ;
     RECT  12.996 13.631 16.002 13.667 ;
     RECT  6.3 13.181 9.63 13.711 ;
     RECT  10.515 12.991 10.854 13.711 ;
     RECT  6.3 13.711 10.854 13.829 ;
     RECT  12.24 13.631 12.258 13.829 ;
     RECT  6.3 13.829 9.702 13.865 ;
     RECT  2.304 13.627 5.397 13.873 ;
     RECT  14.256 13.667 16.002 14.009 ;
     RECT  2.304 13.873 5.562 14.011 ;
     RECT  10.515 13.829 10.854 14.099 ;
     RECT  14.256 14.009 15.426 14.207 ;
     RECT  2.268 14.011 5.562 14.243 ;
     RECT  2.304 14.243 5.562 14.449 ;
     RECT  6.3 13.865 9.45 14.449 ;
     RECT  12.996 13.667 13.497 14.449 ;
     RECT  12.996 14.449 14.202 14.521 ;
     RECT  12.78 14.521 14.202 14.611 ;
     RECT  2.304 14.449 9.45 14.647 ;
     RECT  12.42 14.611 14.202 14.719 ;
     RECT  12.06 14.719 14.202 14.765 ;
     RECT  0.252 14.251 0.27 14.791 ;
     RECT  15.408 14.207 15.426 14.818 ;
     RECT  2.304 14.647 9.666 14.819 ;
     RECT  12.78 14.765 14.202 14.819 ;
     RECT  15.408 14.818 15.462 14.909 ;
     RECT  3.96 14.819 9.666 14.971 ;
     RECT  13.104 14.819 14.202 14.971 ;
     RECT  3.96 14.971 9.774 14.989 ;
     RECT  10.515 14.099 10.797 14.989 ;
     RECT  3.96 14.989 10.797 15.019 ;
     RECT  0.216 14.791 0.306 15.101 ;
     RECT  13.104 14.971 14.886 15.197 ;
     RECT  16.488 14.203 16.542 15.253 ;
     RECT  15.984 15.253 16.542 15.293 ;
     RECT  2.304 14.819 3.222 15.691 ;
     RECT  3.96 15.019 10.818 15.691 ;
     RECT  16.488 15.293 16.542 15.728 ;
     RECT  2.304 15.691 10.818 15.739 ;
     RECT  13.215 15.197 14.886 15.763 ;
     RECT  0.252 15.101 0.306 15.773 ;
     RECT  2.304 15.739 11.43 15.827 ;
     RECT  16.524 15.728 16.542 15.883 ;
     RECT  3.96 15.827 11.43 15.899 ;
     RECT  0.288 15.773 0.306 15.965 ;
     RECT  13.215 15.763 15.426 16.027 ;
     RECT  12.564 16.027 15.426 16.033 ;
     RECT  12.564 16.033 15.462 16.157 ;
     RECT  12.564 16.157 15.426 16.267 ;
     RECT  3.96 15.899 10.926 16.295 ;
     RECT  3.996 16.295 10.926 16.349 ;
     RECT  11.988 16.267 15.426 16.367 ;
     RECT  3.996 16.349 10.854 16.439 ;
     RECT  16.524 15.883 16.578 16.501 ;
     RECT  3.996 16.439 10.797 16.835 ;
     RECT  12.276 16.367 15.426 16.879 ;
     RECT  16.488 16.501 16.578 16.879 ;
     RECT  3.996 16.835 4.374 17.069 ;
     RECT  12.276 16.879 16.578 17.165 ;
     RECT  12.276 17.165 16.542 17.339 ;
     RECT  0.252 16.603 0.27 17.419 ;
     RECT  2.304 15.827 3.222 17.455 ;
     RECT  5.115 16.835 10.797 17.455 ;
     RECT  0.252 17.419 0.342 17.501 ;
     RECT  0.324 17.501 0.342 17.597 ;
     RECT  12.024 17.491 12.258 17.609 ;
     RECT  5.115 17.455 10.854 17.681 ;
     RECT  4.176 17.069 4.374 17.689 ;
     RECT  5.115 17.681 10.797 17.689 ;
     RECT  12.996 17.339 16.542 17.693 ;
     RECT  2.304 17.455 3.402 17.803 ;
     RECT  4.176 17.689 10.797 17.879 ;
     RECT  2.268 17.803 3.402 17.915 ;
     RECT  12.996 17.693 15.426 17.987 ;
     RECT  12.996 17.987 13.77 18.059 ;
     RECT  12.132 17.609 12.258 18.121 ;
     RECT  12.996 18.059 13.518 18.121 ;
     RECT  2.304 17.915 3.402 18.173 ;
     RECT  14.508 17.987 15.426 18.293 ;
     RECT  12.132 18.121 13.518 18.329 ;
     RECT  12.132 18.329 13.497 18.419 ;
     RECT  14.652 18.293 15.426 18.523 ;
     RECT  16.488 17.693 16.542 18.523 ;
     RECT  14.652 18.523 16.542 18.563 ;
     RECT  4.176 17.879 6.57 18.571 ;
     RECT  4.068 18.571 6.57 18.667 ;
     RECT  7.308 17.879 10.797 18.667 ;
     RECT  14.652 18.563 15.426 18.797 ;
     RECT  0.432 18.811 0.45 18.841 ;
     RECT  0.36 18.841 0.45 18.869 ;
     RECT  0.36 18.869 0.378 18.893 ;
     RECT  12.528 18.419 13.497 18.959 ;
     RECT  4.068 18.667 10.797 19.039 ;
     RECT  12.564 18.959 13.497 19.201 ;
     RECT  11.664 19.111 11.682 19.229 ;
     RECT  2.304 18.173 3.258 19.309 ;
     RECT  3.996 19.039 10.797 19.309 ;
     RECT  0.252 19.147 0.306 19.345 ;
     RECT  0.216 19.345 0.306 19.517 ;
     RECT  2.304 19.309 10.797 19.535 ;
     RECT  12.564 19.201 13.734 19.543 ;
     RECT  14.832 18.797 15.426 19.543 ;
     RECT  2.304 19.535 9.594 19.643 ;
     RECT  0.288 19.517 0.306 19.675 ;
     RECT  16.524 18.563 16.542 19.768 ;
     RECT  16.488 19.768 16.542 19.805 ;
     RECT  0.288 19.675 0.378 19.853 ;
     RECT  12.564 19.543 15.426 19.853 ;
     RECT  0.288 19.853 0.306 19.901 ;
     RECT  12.924 19.853 15.426 20.309 ;
     RECT  6.192 19.643 9.594 20.587 ;
     RECT  10.515 19.535 10.797 20.587 ;
     RECT  12.924 20.309 14.886 20.587 ;
     RECT  12.708 20.587 14.886 20.624 ;
     RECT  6.192 20.587 10.797 20.635 ;
     RECT  6.192 20.635 11.466 20.687 ;
     RECT  2.304 19.643 5.397 20.695 ;
     RECT  6.192 20.687 10.797 20.695 ;
     RECT  12.888 20.624 14.886 20.849 ;
     RECT  2.304 20.695 10.797 20.861 ;
     RECT  12.996 20.849 14.886 21.115 ;
     RECT  0.288 21.115 0.306 21.127 ;
     RECT  2.304 20.861 9.738 21.155 ;
     RECT  16.524 19.805 16.542 21.211 ;
     RECT  16.524 21.211 16.578 21.263 ;
     RECT  12.996 21.115 15.426 21.433 ;
     RECT  12.996 21.433 15.462 21.569 ;
     RECT  0.288 21.127 0.378 21.581 ;
     RECT  12.996 21.569 14.274 21.775 ;
     RECT  5.115 21.155 9.738 21.811 ;
     RECT  10.515 20.861 10.797 21.811 ;
     RECT  15.408 21.569 15.462 21.811 ;
     RECT  2.304 21.155 4.302 21.928 ;
     RECT  5.115 21.811 10.797 21.928 ;
     RECT  16.524 21.263 16.542 21.928 ;
     RECT  2.304 21.928 10.797 21.931 ;
     RECT  2.304 21.931 11.43 22.001 ;
     RECT  2.304 22.001 10.962 22.199 ;
     RECT  16.488 21.928 16.542 22.235 ;
     RECT  12.708 21.775 14.274 22.351 ;
     RECT  15.408 21.811 15.498 22.351 ;
     RECT  12.708 22.351 14.49 22.363 ;
     RECT  15.408 22.351 16.002 22.363 ;
     RECT  12.708 22.363 16.002 22.379 ;
     RECT  12.708 22.379 13.497 22.441 ;
     RECT  12.636 22.441 13.497 22.513 ;
     RECT  14.256 22.379 16.002 22.541 ;
     RECT  0.252 21.643 0.27 22.747 ;
     RECT  0.252 22.747 0.342 22.781 ;
     RECT  2.304 22.199 10.797 22.784 ;
     RECT  0.324 22.781 0.342 22.795 ;
     RECT  0.324 22.795 0.486 22.928 ;
     RECT  10.515 22.784 10.797 22.981 ;
     RECT  15.408 22.541 16.002 22.981 ;
     RECT  2.304 22.784 9.666 23.021 ;
     RECT  15.408 22.981 16.542 23.021 ;
     RECT  12.564 22.513 13.497 23.161 ;
     RECT  14.256 22.541 14.598 23.161 ;
     RECT  15.408 23.021 16.506 23.213 ;
     RECT  2.304 23.021 9.45 23.279 ;
     RECT  11.952 23.161 14.598 23.279 ;
     RECT  0.468 22.928 0.486 23.357 ;
     RECT  15.984 23.213 16.506 23.357 ;
     RECT  10.515 22.981 10.854 23.521 ;
     RECT  11.952 23.279 13.986 23.521 ;
     RECT  10.515 23.521 13.986 23.549 ;
     RECT  13.215 23.549 13.986 23.585 ;
     RECT  16.488 23.357 16.506 23.803 ;
     RECT  14.832 23.419 14.886 23.935 ;
     RECT  14.832 23.935 15.462 24.061 ;
     RECT  10.515 23.549 12.33 24.089 ;
     RECT  2.304 23.279 3.222 24.091 ;
     RECT  4.176 23.279 9.45 24.097 ;
     RECT  10.515 24.089 11.502 24.097 ;
     RECT  4.068 24.097 9.45 24.133 ;
     RECT  10.26 24.097 11.502 24.133 ;
     RECT  14.796 24.061 15.462 24.169 ;
     RECT  13.215 23.585 13.914 24.331 ;
     RECT  14.724 24.169 15.462 24.331 ;
     RECT  12.24 24.089 12.33 24.359 ;
     RECT  4.068 24.133 11.502 24.395 ;
     RECT  0.252 24.091 0.27 24.427 ;
     RECT  13.215 24.331 15.462 24.431 ;
     RECT  13.215 24.431 13.842 24.511 ;
     RECT  0.252 24.427 0.306 24.571 ;
     RECT  14.616 24.431 15.462 24.571 ;
     RECT  16.488 23.803 16.542 24.571 ;
     RECT  0.252 24.571 0.414 24.637 ;
     RECT  0.216 24.637 0.414 24.701 ;
     RECT  2.304 24.091 3.33 24.709 ;
     RECT  4.068 24.395 11.394 24.709 ;
     RECT  14.616 24.571 16.542 24.737 ;
     RECT  14.616 24.737 14.634 24.941 ;
     RECT  2.304 24.709 11.394 25.043 ;
     RECT  15.408 24.737 16.542 25.079 ;
     RECT  12.564 24.511 13.842 25.195 ;
     RECT  0.252 24.701 0.27 25.277 ;
     RECT  10.296 25.043 11.394 25.277 ;
     RECT  12.564 25.195 14.022 25.285 ;
     RECT  12.456 25.285 14.022 25.321 ;
     RECT  16.488 25.079 16.542 25.349 ;
     RECT  2.304 25.043 9.414 25.475 ;
     RECT  4.14 25.475 9.414 25.583 ;
     RECT  12.384 25.321 14.022 25.825 ;
     RECT  16.524 25.349 16.542 26.011 ;
     RECT  10.296 25.277 10.89 26.015 ;
     RECT  16.524 26.011 16.578 26.051 ;
     RECT  12.384 25.825 14.346 26.257 ;
     RECT  12.096 26.257 14.346 26.321 ;
     RECT  16.524 26.051 16.542 26.321 ;
     RECT  15.408 25.079 15.462 26.347 ;
     RECT  4.14 25.583 9.378 26.491 ;
     RECT  10.296 26.015 10.854 26.491 ;
     RECT  14.328 26.321 14.346 26.527 ;
     RECT  15.408 26.347 16.074 26.527 ;
     RECT  2.304 25.475 3.33 26.635 ;
     RECT  4.14 26.491 10.854 26.635 ;
     RECT  12.096 26.321 13.497 26.671 ;
     RECT  12.024 26.671 13.497 26.789 ;
     RECT  14.328 26.527 16.074 26.861 ;
     RECT  2.304 26.635 10.854 26.941 ;
     RECT  2.268 26.941 10.854 27.005 ;
     RECT  12.492 26.789 13.497 27.067 ;
     RECT  14.328 26.861 15.462 27.067 ;
     RECT  2.304 27.005 10.854 27.095 ;
     RECT  16.488 27.163 16.542 27.239 ;
     RECT  2.376 27.095 10.854 27.245 ;
     RECT  12.492 27.067 15.462 27.365 ;
     RECT  0.54 27.337 0.558 27.451 ;
     RECT  0.54 27.451 0.63 27.509 ;
     RECT  0.54 27.509 0.558 27.533 ;
     RECT  12.492 27.365 13.497 27.643 ;
     RECT  11.844 27.643 13.497 27.68 ;
     RECT  16.488 27.239 16.506 27.979 ;
     RECT  2.412 27.245 10.854 28.123 ;
     RECT  14.328 27.365 15.462 28.147 ;
     RECT  16.488 27.979 16.542 28.147 ;
     RECT  0.252 28.027 0.27 28.253 ;
     RECT  12.24 27.68 13.497 28.291 ;
     RECT  14.328 28.147 16.542 28.291 ;
     RECT  12.24 28.291 16.542 28.445 ;
     RECT  2.304 28.123 10.854 28.489 ;
     RECT  0.324 28.363 0.414 28.493 ;
     RECT  12.24 28.445 16.038 28.493 ;
     RECT  2.304 28.489 10.89 28.651 ;
     RECT  2.268 28.651 10.89 28.715 ;
     RECT  12.24 28.493 13.497 28.831 ;
     RECT  0.324 28.493 0.342 28.925 ;
     RECT  12.168 28.831 13.497 28.949 ;
     RECT  14.292 28.493 16.038 29.021 ;
     RECT  14.292 29.021 14.85 29.261 ;
     RECT  15.984 29.021 16.038 29.363 ;
     RECT  12.852 28.949 13.497 29.371 ;
     RECT  12.852 29.371 13.734 29.561 ;
     RECT  14.508 29.261 14.85 29.597 ;
     RECT  16.488 29.371 16.578 29.597 ;
     RECT  2.304 28.715 10.854 29.669 ;
     RECT  16.488 29.597 16.542 29.795 ;
     RECT  14.616 29.597 14.85 29.899 ;
     RECT  2.304 29.669 10.797 29.903 ;
     RECT  0.252 29.035 0.27 29.911 ;
     RECT  3.996 29.903 10.797 30.029 ;
     RECT  12.852 29.561 13.626 30.037 ;
     RECT  1.152 29.899 1.17 30.077 ;
     RECT  4.068 30.029 10.797 30.173 ;
     RECT  16.524 29.795 16.542 30.479 ;
     RECT  14.616 29.899 15.426 30.523 ;
     RECT  12.636 30.037 13.626 30.541 ;
     RECT  14.616 30.523 16.002 30.541 ;
     RECT  12.636 30.541 16.002 30.571 ;
     RECT  0.216 29.911 0.306 30.763 ;
     RECT  12.564 30.571 16.002 30.839 ;
     RECT  0.216 30.763 0.45 30.893 ;
     RECT  0.216 30.893 0.306 30.941 ;
     RECT  12.564 30.839 15.498 30.947 ;
     RECT  2.304 29.903 3.222 30.955 ;
     RECT  4.068 30.173 9.666 30.955 ;
     RECT  10.515 30.173 10.797 30.955 ;
     RECT  0.216 30.941 0.234 30.989 ;
     RECT  10.515 30.955 11.43 31.109 ;
     RECT  2.304 30.955 9.666 31.189 ;
     RECT  2.268 31.189 9.666 31.325 ;
     RECT  2.304 31.325 9.666 31.339 ;
     RECT  2.304 31.339 9.738 31.435 ;
     RECT  10.515 31.109 10.797 31.435 ;
     RECT  14.292 30.947 15.498 31.523 ;
     RECT  14.292 31.523 15.462 31.559 ;
     RECT  14.292 31.559 14.634 31.709 ;
     RECT  12.564 30.947 13.554 31.801 ;
     RECT  14.292 31.709 14.49 31.801 ;
     RECT  0.252 31.723 0.27 31.853 ;
     RECT  15.408 31.559 15.462 32.269 ;
     RECT  12.564 31.801 14.49 32.305 ;
     RECT  2.304 31.435 10.797 32.341 ;
     RECT  12.06 32.305 14.49 32.443 ;
     RECT  15.408 32.269 15.498 32.443 ;
     RECT  12.06 32.443 15.498 32.459 ;
     RECT  2.268 32.341 10.797 32.477 ;
     RECT  12.6 32.459 15.498 32.525 ;
     RECT  2.304 32.477 10.797 32.531 ;
     RECT  4.032 32.531 10.797 32.729 ;
     RECT  12.6 32.525 15.426 32.765 ;
     RECT  16.524 31.243 16.542 32.923 ;
     RECT  4.032 32.729 9.558 33.035 ;
     RECT  1.152 32.923 1.17 33.053 ;
     RECT  12.24 33.241 12.258 33.293 ;
     RECT  13.215 32.765 15.426 33.403 ;
     RECT  13.215 33.403 15.462 33.511 ;
     RECT  16.488 32.923 16.542 33.511 ;
     RECT  13.215 33.511 16.542 33.581 ;
     RECT  4.068 33.035 9.558 33.583 ;
     RECT  10.515 32.729 10.797 33.583 ;
     RECT  13.215 33.581 15.462 33.611 ;
     RECT  4.068 33.583 10.797 33.619 ;
     RECT  11.736 33.421 12.006 33.619 ;
     RECT  2.304 32.531 3.222 33.629 ;
     RECT  13.215 33.611 15.426 33.691 ;
     RECT  4.068 33.619 12.006 33.809 ;
     RECT  12.816 33.691 15.426 33.809 ;
     RECT  11.988 33.809 12.006 33.965 ;
     RECT  14.508 33.809 15.426 34.187 ;
     RECT  16.524 33.581 16.542 34.357 ;
     RECT  12.816 33.809 13.59 34.393 ;
     RECT  4.068 33.809 10.818 34.456 ;
     RECT  3.492 34.456 10.818 34.465 ;
     RECT  12.312 34.393 13.59 34.591 ;
     RECT  3.42 34.465 10.818 34.603 ;
     RECT  12.312 34.591 13.626 34.619 ;
     RECT  12.564 34.619 13.626 34.691 ;
     RECT  3.42 34.603 10.854 34.733 ;
     RECT  2.304 33.629 2.697 34.735 ;
     RECT  3.42 34.733 10.818 34.735 ;
     RECT  14.616 34.187 15.426 34.987 ;
     RECT  16.488 34.357 16.542 34.987 ;
     RECT  1.152 35.035 1.17 35.131 ;
     RECT  12.564 34.691 13.497 35.168 ;
     RECT  2.304 34.735 10.818 35.195 ;
     RECT  10.515 35.195 10.818 35.261 ;
     RECT  1.152 35.131 1.242 35.309 ;
     RECT  14.616 34.987 16.542 35.339 ;
     RECT  14.616 35.339 15.462 35.401 ;
     RECT  0.288 35.275 0.306 35.545 ;
     RECT  13.215 35.168 13.497 35.581 ;
     RECT  14.58 35.401 15.462 35.581 ;
     RECT  2.304 35.195 9.738 35.645 ;
     RECT  0.216 35.545 0.306 35.837 ;
     RECT  1.152 35.309 1.17 35.837 ;
     RECT  0.216 35.837 0.27 35.885 ;
     RECT  4.068 35.645 9.738 35.941 ;
     RECT  10.515 35.261 10.797 35.941 ;
     RECT  13.215 35.581 15.462 36.085 ;
     RECT  4.068 35.941 10.797 36.091 ;
     RECT  11.952 35.545 11.97 36.091 ;
     RECT  4.068 36.091 11.97 36.121 ;
     RECT  12.78 36.085 15.462 36.121 ;
     RECT  2.304 35.645 3.258 36.187 ;
     RECT  4.068 36.121 15.462 36.239 ;
     RECT  2.268 36.187 3.258 36.347 ;
     RECT  16.524 35.339 16.542 36.418 ;
     RECT  4.068 36.239 10.797 36.517 ;
     RECT  16.524 36.418 16.578 36.797 ;
     RECT  4.032 36.517 10.797 36.815 ;
     RECT  16.524 36.797 16.542 36.815 ;
     RECT  11.736 36.239 15.462 36.859 ;
     RECT  11.736 36.859 16.002 36.893 ;
     RECT  4.068 36.815 10.797 37.093 ;
     RECT  11.844 36.893 16.002 37.133 ;
     RECT  4.068 37.093 10.89 37.471 ;
     RECT  4.068 37.471 10.926 37.561 ;
     RECT  4.068 37.561 10.998 37.579 ;
     RECT  11.844 37.133 15.426 37.589 ;
     RECT  3.996 37.579 10.998 37.613 ;
     RECT  12.348 37.589 14.634 37.625 ;
     RECT  2.304 36.347 3.258 38.011 ;
     RECT  3.996 37.613 10.797 38.011 ;
     RECT  0.252 35.885 0.27 38.093 ;
     RECT  16.488 37.723 16.506 38.141 ;
     RECT  2.304 38.011 10.797 38.237 ;
     RECT  13.068 37.625 14.634 38.371 ;
     RECT  16.524 38.347 16.542 38.399 ;
     RECT  15.408 37.589 15.426 38.407 ;
     RECT  12.348 38.371 14.634 38.443 ;
     RECT  15.408 38.407 15.462 38.443 ;
     RECT  12.348 38.443 15.462 38.477 ;
     RECT  12.924 38.477 15.462 38.717 ;
     RECT  4.068 38.237 10.797 38.749 ;
     RECT  13.104 38.717 15.462 38.765 ;
     RECT  13.104 38.765 15.426 39.011 ;
     RECT  2.304 38.237 3.114 39.019 ;
     RECT  4.068 38.749 10.854 39.019 ;
     RECT  2.304 39.019 10.854 39.181 ;
     RECT  13.104 39.011 14.886 39.209 ;
     RECT  16.488 39.163 16.506 39.355 ;
     RECT  13.104 39.209 14.85 39.479 ;
     RECT  16.488 39.355 16.542 39.691 ;
     RECT  2.304 39.181 10.926 39.749 ;
     RECT  11.952 39.325 11.97 39.749 ;
     RECT  15.984 39.691 16.542 39.785 ;
     RECT  13.215 39.479 14.85 40.019 ;
     RECT  14.436 40.019 14.85 40.123 ;
     RECT  7.38 39.749 10.926 40.171 ;
     RECT  16.488 39.785 16.542 40.171 ;
     RECT  13.215 40.019 13.497 40.261 ;
     RECT  16.488 40.171 16.578 40.289 ;
     RECT  2.304 39.749 6.606 40.361 ;
     RECT  13.104 40.261 13.497 40.405 ;
     RECT  0.252 40.171 0.27 40.445 ;
     RECT  16.524 40.289 16.578 40.445 ;
     RECT  14.436 40.123 14.886 40.469 ;
     RECT  4.032 40.361 6.606 40.531 ;
     RECT  7.38 40.171 10.962 40.531 ;
     RECT  12.996 40.405 13.497 40.639 ;
     RECT  11.988 40.699 12.006 40.711 ;
     RECT  12.78 40.639 13.497 40.711 ;
     RECT  14.832 40.469 14.886 40.837 ;
     RECT  14.832 40.837 15.426 40.973 ;
     RECT  4.032 40.531 10.962 40.981 ;
     RECT  11.988 40.711 13.497 40.981 ;
     RECT  0.324 40.459 0.342 40.987 ;
     RECT  15.408 40.973 15.426 41.071 ;
     RECT  16.524 40.445 16.542 41.071 ;
     RECT  0.324 40.987 0.594 41.165 ;
     RECT  2.304 40.361 3.222 41.215 ;
     RECT  4.032 40.981 13.497 41.215 ;
     RECT  2.304 41.215 13.497 41.369 ;
     RECT  15.408 41.071 16.542 41.411 ;
     RECT  2.304 41.369 3.222 41.611 ;
     RECT  3.96 41.369 13.497 41.611 ;
     RECT  2.268 41.611 3.222 41.675 ;
     RECT  3.96 41.611 13.806 41.707 ;
     RECT  3.96 41.707 14.022 41.747 ;
     RECT  15.408 41.411 15.462 41.881 ;
     RECT  16.488 41.411 16.542 41.917 ;
     RECT  14.868 41.881 15.462 41.953 ;
     RECT  14.724 41.953 15.462 42.053 ;
     RECT  14.796 42.053 15.462 42.179 ;
     RECT  2.304 41.675 3.222 42.187 ;
     RECT  3.96 41.747 13.914 42.187 ;
     RECT  16.488 41.917 16.614 42.413 ;
     RECT  2.304 42.187 13.914 42.493 ;
     RECT  0.252 41.323 0.306 42.523 ;
     RECT  2.304 42.493 13.95 42.593 ;
     RECT  2.304 42.593 13.842 42.605 ;
     RECT  6.12 42.605 13.842 42.629 ;
     RECT  14.832 42.179 15.462 42.691 ;
     RECT  16.488 42.413 16.542 42.691 ;
     RECT  0.252 42.523 0.342 42.727 ;
     RECT  0.252 42.727 0.378 43.051 ;
     RECT  2.304 42.605 5.397 43.061 ;
     RECT  14.832 42.691 16.542 43.061 ;
     RECT  6.408 42.629 13.842 43.259 ;
     RECT  2.304 43.061 4.194 43.331 ;
     RECT  12.348 43.259 13.842 43.331 ;
     RECT  12.348 43.331 13.554 43.373 ;
     RECT  6.408 43.259 10.854 43.375 ;
     RECT  0.252 43.051 0.414 43.387 ;
     RECT  6.192 43.375 10.854 43.529 ;
     RECT  6.192 43.529 9.666 43.565 ;
     RECT  0.252 43.387 0.522 43.579 ;
     RECT  4.104 43.331 4.194 43.807 ;
     RECT  4.932 43.061 5.397 43.807 ;
     RECT  15.984 43.061 16.542 43.835 ;
     RECT  0.252 43.579 0.558 43.901 ;
     RECT  4.104 43.807 5.397 43.912 ;
     RECT  0.504 43.901 0.558 43.949 ;
     RECT  14.832 43.061 14.886 43.963 ;
     RECT  15.984 43.835 16.506 43.963 ;
     RECT  14.832 43.963 16.506 44.059 ;
     RECT  2.304 43.331 3.366 44.077 ;
     RECT  4.104 43.912 5.454 44.077 ;
     RECT  6.192 43.565 9.558 44.077 ;
     RECT  12.78 43.373 13.554 44.104 ;
     RECT  14.436 44.059 16.506 44.104 ;
     RECT  10.515 43.529 10.854 44.141 ;
     RECT  0.504 43.949 0.522 44.285 ;
     RECT  2.304 44.077 9.558 44.347 ;
     RECT  10.515 44.141 10.818 44.347 ;
     RECT  2.304 44.347 10.818 44.411 ;
     RECT  2.304 44.411 10.797 44.483 ;
     RECT  12.78 44.104 16.506 44.581 ;
     RECT  12.78 44.581 16.542 44.621 ;
     RECT  12.78 44.621 16.038 44.683 ;
     RECT  12.564 44.683 16.038 44.689 ;
     RECT  12.312 44.689 16.038 44.765 ;
     RECT  12.348 44.765 16.038 44.879 ;
     RECT  2.304 44.483 9.63 44.915 ;
     RECT  12.348 44.879 13.914 44.915 ;
     RECT  0.252 44.779 0.27 44.957 ;
     RECT  12.348 44.915 13.842 45.005 ;
     RECT  2.415 44.915 9.63 45.265 ;
     RECT  10.515 44.483 10.797 45.265 ;
     RECT  14.724 44.879 16.038 45.391 ;
     RECT  0.288 45.211 0.306 45.403 ;
     RECT  14.724 45.391 16.506 45.527 ;
     RECT  0.288 45.403 0.414 45.595 ;
     RECT  2.415 45.265 10.89 45.599 ;
     RECT  12.456 45.005 13.842 45.689 ;
     RECT  0.288 45.595 0.558 45.739 ;
     RECT  13.032 45.689 13.842 45.773 ;
     RECT  2.415 45.599 10.797 45.787 ;
     RECT  2.34 45.787 10.797 45.869 ;
     RECT  0.252 45.739 0.558 46.013 ;
     RECT  10.26 45.869 10.797 46.013 ;
     RECT  0.252 46.013 0.486 46.061 ;
     RECT  14.832 45.527 16.506 46.264 ;
     RECT  14.328 46.264 16.506 46.267 ;
     RECT  10.515 46.013 10.797 46.345 ;
     RECT  2.34 45.869 9.522 46.381 ;
     RECT  13.032 45.773 13.497 46.471 ;
     RECT  10.515 46.345 11.322 46.607 ;
     RECT  2.304 46.381 9.522 46.643 ;
     RECT  14.328 46.267 16.542 46.643 ;
     RECT  10.515 46.607 10.854 46.741 ;
     RECT  10.26 46.741 10.854 46.829 ;
     RECT  4.068 46.643 9.522 46.849 ;
     RECT  10.26 46.829 10.797 46.849 ;
     RECT  11.844 46.777 11.862 46.885 ;
     RECT  11.844 46.885 11.934 46.921 ;
     RECT  12.888 46.471 13.497 46.921 ;
     RECT  11.844 46.921 13.497 47.039 ;
     RECT  12.168 47.039 13.497 47.047 ;
     RECT  14.328 46.643 14.742 47.047 ;
     RECT  15.948 46.643 16.542 47.213 ;
     RECT  12.168 47.047 14.742 47.219 ;
     RECT  0.252 46.061 0.27 47.308 ;
     RECT  12.168 47.219 12.186 47.309 ;
     RECT  2.304 46.643 3.258 47.425 ;
     RECT  4.068 46.849 10.797 47.425 ;
     RECT  15.948 47.213 16.038 47.453 ;
     RECT  0.216 47.308 0.306 47.501 ;
     RECT  12.96 47.219 14.742 47.659 ;
     RECT  2.304 47.425 10.797 47.731 ;
     RECT  12.96 47.659 14.85 47.803 ;
     RECT  15.948 47.453 16.002 47.803 ;
     RECT  2.304 47.731 11.43 47.849 ;
     RECT  12.96 47.803 16.002 47.885 ;
     RECT  0.54 47.731 0.558 47.933 ;
     RECT  12.96 47.885 15.426 47.965 ;
     RECT  12.888 47.965 15.426 48.271 ;
     RECT  12.672 48.271 15.426 48.433 ;
     RECT  12.384 48.433 15.426 48.467 ;
     RECT  2.304 47.849 10.797 48.667 ;
     RECT  2.304 48.667 11.178 48.695 ;
     RECT  10.515 48.695 11.178 48.731 ;
     RECT  16.452 48.235 16.506 48.763 ;
     RECT  12.384 48.467 13.878 48.839 ;
     RECT  14.796 48.467 15.426 48.937 ;
     RECT  16.452 48.763 16.542 48.937 ;
     RECT  12.384 48.839 13.842 48.965 ;
     RECT  10.515 48.731 10.854 48.989 ;
     RECT  12.384 48.965 13.698 49.001 ;
     RECT  14.796 48.937 16.542 49.243 ;
     RECT  12.384 49.001 13.497 49.279 ;
     RECT  2.304 48.695 9.774 49.343 ;
     RECT  14.724 49.243 16.542 49.343 ;
     RECT  4.032 49.343 9.774 49.373 ;
     RECT  14.724 49.343 16.002 49.378 ;
     RECT  11.988 49.279 13.497 49.379 ;
     RECT  14.688 49.378 16.002 49.517 ;
     RECT  0.252 48.475 0.27 49.549 ;
     RECT  0.252 49.549 0.558 49.565 ;
     RECT  12.564 49.379 13.497 49.577 ;
     RECT  0.54 49.565 0.558 49.613 ;
     RECT  4.032 49.373 9.702 49.613 ;
     RECT  4.032 49.613 9.594 49.775 ;
     RECT  14.688 49.517 15.462 49.855 ;
     RECT  12.6 49.577 13.497 50.081 ;
     RECT  14.22 49.855 15.462 50.081 ;
     RECT  14.256 50.081 15.462 50.117 ;
     RECT  10.515 48.989 10.797 50.251 ;
     RECT  16.524 50.107 16.542 50.443 ;
     RECT  16.488 50.443 16.542 50.549 ;
     RECT  10.515 50.251 10.854 50.629 ;
     RECT  10.515 50.629 11.43 50.669 ;
     RECT  13.032 50.081 13.497 50.827 ;
     RECT  14.256 50.117 15.426 50.827 ;
     RECT  16.524 50.549 16.542 50.863 ;
     RECT  13.032 50.827 15.426 50.891 ;
     RECT  4.068 49.775 9.594 50.899 ;
     RECT  4.068 50.899 9.774 50.935 ;
     RECT  10.515 50.669 10.797 50.935 ;
     RECT  13.032 50.891 13.878 50.935 ;
     RECT  2.304 49.343 3.258 50.999 ;
     RECT  4.068 50.935 10.797 51.097 ;
     RECT  0.252 50.491 0.27 51.197 ;
     RECT  12.6 50.935 13.878 51.331 ;
     RECT  12.348 51.331 13.878 51.437 ;
     RECT  4.032 51.097 10.797 51.451 ;
     RECT  14.832 50.891 15.426 51.539 ;
     RECT  15.408 51.539 15.426 51.595 ;
     RECT  4.032 51.451 10.854 51.629 ;
     RECT  12.564 51.437 13.878 51.871 ;
     RECT  14.616 51.637 14.634 51.871 ;
     RECT  2.304 50.999 3.222 51.883 ;
     RECT  2.268 51.883 3.222 51.935 ;
     RECT  4.032 51.629 9.594 51.979 ;
     RECT  2.304 51.935 3.222 52.015 ;
     RECT  3.996 51.979 9.594 52.015 ;
     RECT  2.304 52.015 9.594 52.169 ;
     RECT  16.524 50.863 16.578 52.249 ;
     RECT  0.252 52.075 0.27 52.253 ;
     RECT  12.564 51.871 14.634 52.321 ;
     RECT  16.524 52.249 16.614 52.349 ;
     RECT  11.844 52.321 14.634 52.411 ;
     RECT  15.408 51.595 15.462 52.411 ;
     RECT  11.844 52.411 15.462 52.439 ;
     RECT  12.456 52.439 15.462 52.603 ;
     RECT  16.524 52.349 16.578 52.603 ;
     RECT  12.456 52.603 16.578 52.619 ;
     RECT  4.032 52.169 9.594 52.744 ;
     RECT  10.515 51.629 10.854 52.795 ;
     RECT  12.456 52.619 16.542 52.817 ;
     RECT  2.304 52.169 3.222 52.861 ;
     RECT  2.268 52.861 3.222 52.925 ;
     RECT  4.032 52.744 9.702 52.939 ;
     RECT  10.515 52.795 11.43 52.939 ;
     RECT  2.304 52.925 3.222 52.951 ;
     RECT  4.032 52.939 11.43 52.979 ;
     RECT  12.456 52.817 16.506 52.979 ;
     RECT  0.252 53.035 0.27 53.083 ;
     RECT  2.304 52.951 3.294 53.257 ;
     RECT  4.032 52.979 10.797 53.257 ;
     RECT  12.456 52.979 16.002 53.401 ;
     RECT  0.252 53.083 0.342 53.548 ;
     RECT  12.348 53.401 16.002 53.597 ;
     RECT  0.252 53.548 0.378 53.833 ;
     RECT  2.304 53.257 10.797 53.869 ;
     RECT  12.348 53.597 15.426 53.905 ;
     RECT  0.216 53.833 0.378 53.941 ;
     RECT  2.304 53.869 10.962 53.941 ;
     RECT  0.216 53.941 0.558 53.981 ;
     RECT  12.204 53.905 15.426 54.059 ;
     RECT  16.488 53.752 16.506 54.187 ;
     RECT  2.304 53.941 11.034 54.211 ;
     RECT  12.204 54.059 12.222 54.211 ;
     RECT  0.252 53.981 0.558 54.221 ;
     RECT  2.304 54.211 12.222 54.473 ;
     RECT  13.104 54.059 13.986 54.605 ;
     RECT  14.832 54.059 15.426 54.607 ;
     RECT  16.488 54.187 16.542 54.607 ;
     RECT  12.168 54.473 12.222 54.707 ;
     RECT  13.14 54.605 13.986 54.707 ;
     RECT  13.212 54.707 13.986 54.841 ;
     RECT  12.168 54.707 12.186 54.869 ;
     RECT  14.832 54.607 16.542 54.941 ;
     RECT  13.212 54.841 14.094 54.977 ;
     RECT  0.252 54.221 0.342 55.132 ;
     RECT  0.216 55.132 0.342 55.229 ;
     RECT  0.288 55.229 0.342 55.277 ;
     RECT  2.304 54.473 10.998 55.291 ;
     RECT  15.408 54.941 16.542 55.291 ;
     RECT  2.304 55.291 11.61 55.409 ;
     RECT  13.212 54.977 13.698 55.421 ;
     RECT  15.408 55.291 16.578 55.469 ;
     RECT  11.592 55.409 11.61 55.589 ;
     RECT  0.324 55.277 0.342 55.661 ;
     RECT  13.215 55.421 13.698 55.723 ;
     RECT  14.472 55.651 14.49 55.723 ;
     RECT  2.304 55.409 10.818 55.859 ;
     RECT  15.408 55.469 16.542 55.859 ;
     RECT  13.215 55.723 14.49 55.867 ;
     RECT  15.408 55.859 15.426 55.867 ;
     RECT  11.916 56.029 11.934 56.059 ;
     RECT  13.215 55.867 15.426 56.129 ;
     RECT  11.916 56.059 11.97 56.191 ;
     RECT  11.916 56.191 12.402 56.237 ;
     RECT  16.524 55.859 16.542 56.299 ;
     RECT  10.515 55.859 10.818 56.333 ;
     RECT  11.916 56.237 11.97 56.333 ;
     RECT  16.524 56.299 16.578 56.395 ;
     RECT  2.304 55.859 9.594 56.489 ;
     RECT  0.252 56.443 0.27 56.573 ;
     RECT  13.215 56.129 13.497 56.587 ;
     RECT  14.328 56.129 15.426 56.633 ;
     RECT  16.524 56.395 16.614 56.669 ;
     RECT  4.068 56.489 9.594 56.731 ;
     RECT  14.364 56.633 15.426 56.779 ;
     RECT  16.524 56.669 16.542 56.779 ;
     RECT  4.068 56.731 9.666 56.795 ;
     RECT  12.744 56.587 13.497 57.001 ;
     RECT  10.515 56.333 10.797 57.109 ;
     RECT  10.515 57.109 10.854 57.307 ;
     RECT  0.54 57.271 0.558 57.341 ;
     RECT  10.224 57.307 10.854 57.343 ;
     RECT  4.068 56.795 9.45 57.541 ;
     RECT  10.224 57.343 11.43 57.541 ;
     RECT  14.364 56.779 16.542 57.541 ;
     RECT  12.348 57.001 13.497 57.569 ;
     RECT  14.256 57.541 16.542 57.569 ;
     RECT  12.924 57.569 13.497 57.649 ;
     RECT  14.256 57.569 14.418 57.649 ;
     RECT  4.068 57.541 11.43 57.721 ;
     RECT  2.304 56.489 3.33 57.983 ;
     RECT  4.068 57.721 11.97 57.983 ;
     RECT  12.924 57.649 14.418 58.109 ;
     RECT  13.212 58.109 14.418 58.145 ;
     RECT  15.408 57.569 16.542 58.145 ;
     RECT  11.952 57.983 11.97 58.157 ;
     RECT  15.408 58.145 16.002 58.451 ;
     RECT  14.256 58.145 14.418 58.459 ;
     RECT  4.068 57.983 10.926 58.495 ;
     RECT  0.252 57.643 0.27 58.589 ;
     RECT  2.304 57.983 3.222 58.685 ;
     RECT  3.996 58.495 10.926 58.721 ;
     RECT  14.256 58.459 14.886 58.721 ;
     RECT  13.212 58.145 13.518 58.891 ;
     RECT  15.984 58.451 16.002 58.891 ;
     RECT  11.808 58.927 11.826 58.939 ;
     RECT  13.212 58.891 13.878 58.999 ;
     RECT  0.54 58.657 0.558 59.309 ;
     RECT  2.304 58.685 2.898 59.467 ;
     RECT  3.996 58.721 10.854 59.515 ;
     RECT  11.808 58.939 11.898 59.515 ;
     RECT  3.996 59.515 11.898 59.563 ;
     RECT  12.636 58.999 13.878 59.563 ;
     RECT  3.996 59.563 13.878 59.701 ;
     RECT  3.996 59.701 14.058 59.729 ;
     RECT  11.988 59.729 14.058 59.801 ;
     RECT  3.996 59.729 11.142 59.837 ;
     RECT  14.832 58.721 14.886 59.851 ;
     RECT  15.984 58.891 16.542 59.851 ;
     RECT  3.996 59.837 10.926 59.873 ;
     RECT  2.304 59.467 3.222 59.881 ;
     RECT  3.996 59.873 9.558 59.881 ;
     RECT  2.304 59.881 9.558 59.999 ;
     RECT  2.304 59.999 9.486 60.035 ;
     RECT  0.324 60.091 0.342 60.139 ;
     RECT  2.304 60.035 9.378 60.221 ;
     RECT  0.252 60.139 0.342 60.269 ;
     RECT  12.384 59.801 13.95 60.269 ;
     RECT  2.304 60.221 9.342 60.305 ;
     RECT  14.832 59.851 16.542 60.313 ;
     RECT  12.636 60.269 13.95 60.377 ;
     RECT  12.888 60.377 13.95 60.413 ;
     RECT  14.76 60.313 16.542 60.575 ;
     RECT  0.252 60.269 0.27 60.605 ;
     RECT  14.832 60.575 16.542 60.701 ;
     RECT  12.888 60.413 13.518 60.845 ;
     RECT  10.515 59.873 10.926 60.961 ;
     RECT  10.515 60.961 11.394 61.003 ;
     RECT  6.3 60.305 9.342 61.087 ;
     RECT  10.08 61.003 11.394 61.087 ;
     RECT  6.3 61.087 11.394 61.133 ;
     RECT  2.304 60.305 5.397 61.147 ;
     RECT  6.3 61.133 11.358 61.147 ;
     RECT  14.832 60.701 15.426 61.321 ;
     RECT  14.364 61.321 15.426 61.385 ;
     RECT  0.216 61.384 0.234 61.387 ;
     RECT  0.216 61.387 0.558 61.393 ;
     RECT  0.216 61.393 0.63 61.421 ;
     RECT  14.364 61.385 14.382 61.457 ;
     RECT  13.215 60.845 13.518 61.465 ;
     RECT  0.54 61.421 0.63 61.469 ;
     RECT  15.408 61.385 15.426 61.483 ;
     RECT  0.54 61.469 0.558 61.517 ;
     RECT  2.304 61.147 11.358 61.529 ;
     RECT  16.524 60.701 16.542 61.579 ;
     RECT  13.215 61.465 13.986 61.661 ;
     RECT  15.408 61.483 15.462 61.723 ;
     RECT  16.488 61.579 16.542 61.723 ;
     RECT  13.215 61.661 13.698 61.771 ;
     RECT  15.408 61.723 16.542 62.011 ;
     RECT  0.324 62.251 0.342 62.299 ;
     RECT  2.304 61.529 11.286 62.303 ;
     RECT  12.672 61.771 13.698 62.311 ;
     RECT  15.408 62.011 16.578 62.347 ;
     RECT  12.528 62.311 13.698 62.401 ;
     RECT  14.868 62.347 16.578 62.401 ;
     RECT  10.515 62.303 11.286 62.429 ;
     RECT  14.868 62.401 16.614 62.437 ;
     RECT  0.324 62.299 0.414 62.443 ;
     RECT  12.528 62.401 13.77 62.509 ;
     RECT  12.132 62.509 13.77 62.635 ;
     RECT  14.724 62.437 16.614 62.635 ;
     RECT  12.132 62.635 16.614 62.669 ;
     RECT  12.132 62.669 16.542 62.699 ;
     RECT  12.24 62.699 16.542 62.771 ;
     RECT  0.288 62.443 0.414 63.049 ;
     RECT  2.304 62.303 9.738 63.085 ;
     RECT  13.104 62.771 16.542 63.101 ;
     RECT  12.24 62.771 12.258 63.239 ;
     RECT  0.288 63.049 0.558 63.247 ;
     RECT  2.304 63.085 9.774 63.247 ;
     RECT  10.515 62.429 10.818 63.247 ;
     RECT  13.104 63.101 15.426 63.248 ;
     RECT  0.216 63.247 0.558 63.259 ;
     RECT  2.304 63.247 10.818 63.383 ;
     RECT  0.216 63.259 0.666 63.389 ;
     RECT  0.252 63.389 0.666 63.485 ;
     RECT  11.988 63.589 12.006 63.629 ;
     RECT  10.515 63.383 10.818 63.643 ;
     RECT  13.176 63.248 15.426 63.821 ;
     RECT  15.408 63.821 15.426 63.883 ;
     RECT  16.488 63.101 16.542 63.883 ;
     RECT  0.252 63.485 0.558 64.013 ;
     RECT  2.304 63.383 3.222 64.171 ;
     RECT  3.96 63.383 9.702 64.171 ;
     RECT  15.408 63.883 16.542 64.253 ;
     RECT  10.515 63.643 10.854 64.399 ;
     RECT  2.304 64.171 9.702 64.435 ;
     RECT  10.515 64.399 11.358 64.435 ;
     RECT  13.176 63.821 14.49 64.435 ;
     RECT  0.54 64.013 0.558 64.445 ;
     RECT  12.852 64.435 14.49 64.471 ;
     RECT  2.304 64.435 11.358 64.589 ;
     RECT  12.708 64.471 14.49 64.633 ;
     RECT  12.708 64.633 14.562 64.651 ;
     RECT  2.304 64.589 9.45 64.685 ;
     RECT  11.988 64.651 14.562 64.697 ;
     RECT  12.456 64.697 14.562 64.769 ;
     RECT  12.456 64.769 14.094 64.859 ;
     RECT  15.408 64.253 15.426 64.877 ;
     RECT  0.396 64.843 0.414 64.973 ;
     RECT  10.515 64.589 10.854 64.973 ;
     RECT  13.215 64.859 14.094 64.973 ;
     RECT  0.324 64.987 0.342 65.035 ;
     RECT  16.524 64.253 16.542 65.035 ;
     RECT  15.984 65.035 16.542 65.129 ;
     RECT  0.252 65.035 0.342 65.165 ;
     RECT  2.304 64.685 5.397 65.213 ;
     RECT  5.004 65.213 5.397 65.309 ;
     RECT  12.456 64.859 12.474 65.399 ;
     RECT  5.115 65.309 5.397 65.515 ;
     RECT  6.264 64.685 9.45 65.515 ;
     RECT  16.488 65.129 16.542 65.551 ;
     RECT  5.115 65.515 9.45 65.563 ;
     RECT  16.488 65.551 16.578 65.597 ;
     RECT  14.832 64.903 14.85 65.659 ;
     RECT  5.115 65.563 9.702 65.677 ;
     RECT  10.515 64.973 10.797 65.677 ;
     RECT  5.115 65.677 10.797 65.813 ;
     RECT  10.515 65.813 10.797 65.821 ;
     RECT  13.215 64.973 13.95 65.939 ;
     RECT  5.115 65.813 9.774 66.055 ;
     RECT  10.515 65.821 10.818 66.083 ;
     RECT  13.215 65.939 13.698 66.181 ;
     RECT  2.304 65.213 4.194 66.253 ;
     RECT  5.112 66.055 9.774 66.253 ;
     RECT  12.672 66.181 13.698 66.361 ;
     RECT  16.488 65.597 16.542 66.389 ;
     RECT  2.304 66.253 9.774 66.515 ;
     RECT  12.6 66.361 13.698 66.523 ;
     RECT  0.252 65.165 0.27 66.557 ;
     RECT  14.832 65.659 15.426 66.619 ;
     RECT  12.024 66.523 13.698 66.659 ;
     RECT  12.708 66.659 13.698 66.712 ;
     RECT  14.832 66.619 15.966 66.712 ;
     RECT  12.708 66.712 15.966 66.749 ;
     RECT  3.996 66.515 9.774 66.763 ;
     RECT  10.515 66.083 10.797 66.763 ;
     RECT  12.708 66.749 15.462 66.929 ;
     RECT  11.592 66.757 11.61 67.019 ;
     RECT  14.832 66.929 15.462 67.163 ;
     RECT  3.996 66.763 10.797 67.291 ;
     RECT  3.996 67.291 10.962 67.361 ;
     RECT  12.708 66.929 13.842 67.441 ;
     RECT  2.304 66.515 3.258 67.531 ;
     RECT  12.528 67.441 13.842 67.579 ;
     RECT  0.252 67.387 0.27 67.661 ;
     RECT  11.7 67.579 13.842 67.675 ;
     RECT  14.832 67.163 15.426 67.675 ;
     RECT  11.7 67.675 15.426 67.712 ;
     RECT  2.268 67.531 3.258 67.771 ;
     RECT  16.488 67.147 16.506 67.801 ;
     RECT  11.7 67.712 14.994 67.829 ;
     RECT  1.728 67.771 3.258 67.837 ;
     RECT  3.996 67.361 10.797 67.837 ;
     RECT  0.288 67.819 0.378 67.867 ;
     RECT  1.728 67.837 10.797 67.901 ;
     RECT  0.288 67.867 0.45 67.997 ;
     RECT  2.304 67.901 10.797 67.997 ;
     RECT  0.288 67.997 0.378 68.093 ;
     RECT  16.488 67.801 17.082 68.107 ;
     RECT  2.34 67.997 10.797 68.135 ;
     RECT  0.288 68.093 0.306 68.141 ;
     RECT  12.024 67.829 14.994 68.207 ;
     RECT  15.984 68.107 17.082 68.333 ;
     RECT  16.524 68.333 17.082 68.429 ;
     RECT  12.78 68.207 14.994 68.587 ;
     RECT  0.252 68.443 0.27 68.621 ;
     RECT  12.024 68.207 12.042 68.747 ;
     RECT  12.78 68.587 15.462 68.957 ;
     RECT  2.34 68.135 3.258 69.115 ;
     RECT  15.408 68.957 15.462 69.151 ;
     RECT  16.524 68.429 16.542 69.151 ;
     RECT  2.304 69.115 3.258 69.331 ;
     RECT  3.996 68.135 10.797 69.331 ;
     RECT  12.78 68.957 14.634 69.331 ;
     RECT  0.252 69.403 0.27 69.457 ;
     RECT  2.304 69.331 10.797 69.493 ;
     RECT  0.252 69.457 0.558 69.529 ;
     RECT  2.304 69.493 10.962 69.533 ;
     RECT  0.216 69.529 0.558 69.677 ;
     RECT  12.492 69.331 14.634 69.691 ;
     RECT  15.408 69.151 16.542 69.691 ;
     RECT  12.492 69.691 16.542 69.763 ;
     RECT  0.216 69.677 0.306 69.821 ;
     RECT  0.216 69.821 0.234 69.869 ;
     RECT  11.988 69.763 16.542 69.965 ;
     RECT  6.12 69.533 10.962 69.979 ;
     RECT  11.988 69.965 15.426 69.979 ;
     RECT  6.12 69.979 15.426 69.989 ;
     RECT  6.228 69.989 13.914 70.025 ;
     RECT  16.488 69.965 16.542 70.033 ;
     RECT  6.228 70.025 10.926 70.061 ;
     RECT  16.488 70.033 16.578 70.205 ;
     RECT  2.304 69.533 5.397 70.339 ;
     RECT  14.724 69.989 15.426 70.601 ;
     RECT  6.228 70.061 10.797 70.637 ;
     RECT  11.988 70.025 13.914 70.771 ;
     RECT  14.724 70.601 14.886 70.771 ;
     RECT  10.515 70.637 10.797 70.807 ;
     RECT  11.988 70.771 14.886 70.807 ;
     RECT  10.515 70.807 10.962 70.877 ;
     RECT  2.304 70.339 5.49 70.939 ;
     RECT  6.228 70.637 9.738 70.939 ;
     RECT  0.252 70.843 0.27 71.083 ;
     RECT  0.252 71.083 0.414 71.212 ;
     RECT  11.916 70.807 14.886 71.249 ;
     RECT  2.304 70.939 9.738 71.323 ;
     RECT  16.488 70.205 16.506 71.323 ;
     RECT  15.984 71.323 16.506 71.375 ;
     RECT  2.268 71.323 9.738 71.383 ;
     RECT  10.515 70.877 10.854 71.383 ;
     RECT  14.472 71.249 14.886 71.411 ;
     RECT  2.268 71.383 10.854 71.419 ;
     RECT  14.832 71.411 14.886 71.419 ;
     RECT  0.216 71.212 0.414 71.549 ;
     RECT  2.232 71.419 10.854 71.549 ;
     RECT  11.916 71.249 13.626 71.717 ;
     RECT  0.324 71.549 0.414 71.803 ;
     RECT  0.324 71.803 0.486 71.933 ;
     RECT  0.324 71.933 0.414 71.981 ;
     RECT  11.916 71.717 13.497 71.987 ;
     RECT  2.304 71.549 10.854 72.121 ;
     RECT  11.916 71.987 11.97 72.121 ;
     RECT  14.832 71.419 15.462 72.139 ;
     RECT  16.524 71.383 16.542 72.139 ;
     RECT  14.832 72.139 16.542 72.149 ;
     RECT  2.304 72.121 11.97 72.329 ;
     RECT  0.324 71.981 0.342 72.365 ;
     RECT  14.544 72.187 14.634 72.391 ;
     RECT  15.408 72.149 16.542 72.491 ;
     RECT  15.984 72.491 16.542 72.509 ;
     RECT  16.488 72.509 16.542 72.571 ;
     RECT  0.216 72.571 0.27 72.761 ;
     RECT  11.916 72.329 11.97 72.811 ;
     RECT  12.744 71.987 13.497 72.811 ;
     RECT  16.488 72.571 16.578 72.833 ;
     RECT  11.916 72.811 13.497 72.869 ;
     RECT  2.304 72.329 11.142 72.959 ;
     RECT  11.916 72.869 12.15 72.989 ;
     RECT  16.488 72.833 16.542 73.139 ;
     RECT  12.924 72.869 13.497 73.187 ;
     RECT  14.364 72.391 14.634 73.195 ;
     RECT  0.252 72.761 0.27 73.229 ;
     RECT  3.96 72.959 11.142 73.229 ;
     RECT  12.132 72.989 12.15 73.229 ;
     RECT  12.924 73.187 13.446 73.229 ;
     RECT  14.256 73.195 14.634 73.243 ;
     RECT  2.304 72.959 3.222 73.265 ;
     RECT  3.96 73.229 10.926 73.265 ;
     RECT  2.304 73.265 2.97 73.277 ;
     RECT  4.104 73.265 10.926 73.277 ;
     RECT  4.104 73.277 8.874 73.301 ;
     RECT  14.256 73.243 14.85 73.301 ;
     RECT  6.156 73.301 7.905 73.325 ;
     RECT  16.488 73.139 16.506 73.337 ;
     RECT  2.304 73.277 2.505 73.373 ;
     RECT  8.856 73.301 8.874 73.373 ;
     RECT  7.776 73.325 7.905 73.409 ;
     RECT  9.684 73.277 10.926 73.409 ;
     RECT  12.996 73.229 13.446 73.409 ;
     RECT  0.324 73.243 0.342 73.421 ;
     RECT  14.832 73.301 14.85 73.421 ;
     RECT  2.415 73.373 2.505 73.457 ;
     RECT  4.428 73.301 5.205 73.457 ;
     RECT  7.815 73.409 7.905 73.457 ;
     RECT  12.996 73.409 13.305 73.457 ;
     RECT  4.428 73.457 4.446 73.499 ;
     RECT  12.996 73.457 13.014 73.499 ;
     RECT  6.156 73.325 6.93 73.535 ;
     RECT  10.404 73.409 10.926 73.535 ;
     RECT  6.84 73.535 6.858 73.607 ;
     RECT  10.404 73.535 10.422 73.607 ;
    LAYER M4 ;
     RECT  0.192 2.208 0.353 2.232 ;
     RECT  0.156 2.232 0.353 2.352 ;
     RECT  0.192 2.352 0.353 2.376 ;
     RECT  0.156 2.376 0.353 2.448 ;
     RECT  0.192 2.448 0.353 2.472 ;
     RECT  0.156 2.472 0.353 2.544 ;
     RECT  0.192 2.544 0.353 2.568 ;
     RECT  0.156 2.568 0.353 2.64 ;
     RECT  0.192 2.64 0.353 2.664 ;
     RECT  0.156 2.664 0.353 2.736 ;
     RECT  0.192 2.736 0.353 2.76 ;
     RECT  0.156 2.76 0.353 2.832 ;
     RECT  0.192 2.832 0.353 2.856 ;
     RECT  0.156 2.856 0.353 2.976 ;
     RECT  0.192 2.976 0.353 3 ;
     RECT  0.156 3 0.353 3.072 ;
     RECT  0.192 3.072 0.353 3.096 ;
     RECT  0.156 3.096 0.353 3.168 ;
     RECT  0.192 3.168 0.353 3.192 ;
     RECT  0.156 3.192 0.353 3.264 ;
     RECT  0.192 3.264 0.353 3.288 ;
     RECT  0.156 3.288 0.353 3.36 ;
     RECT  0.192 3.36 0.353 3.384 ;
     RECT  0.156 3.384 0.353 3.456 ;
     RECT  0.192 3.456 0.353 3.48 ;
     RECT  0.156 3.48 0.353 3.6 ;
     RECT  0.192 3.6 0.353 3.624 ;
     RECT  0.156 3.624 0.353 3.696 ;
     RECT  0.192 3.696 0.353 3.72 ;
     RECT  0.156 3.72 0.353 3.792 ;
     RECT  0.192 3.792 0.353 3.816 ;
     RECT  0.156 3.816 0.353 3.888 ;
     RECT  0.192 3.888 0.353 3.912 ;
     RECT  0.156 3.912 0.353 3.984 ;
     RECT  0.192 3.984 0.353 4.008 ;
     RECT  0.156 4.008 0.353 4.128 ;
     RECT  0.192 4.128 0.353 4.152 ;
     RECT  0.156 4.152 0.353 4.224 ;
     RECT  0.192 4.224 0.353 4.248 ;
     RECT  0.156 4.248 0.353 4.32 ;
     RECT  0.192 4.32 0.353 4.344 ;
     RECT  0.156 4.344 0.353 4.416 ;
     RECT  0.192 4.416 0.353 4.44 ;
     RECT  0.156 4.44 0.353 4.512 ;
     RECT  0.192 4.512 0.353 4.536 ;
     RECT  0.156 4.536 0.353 4.608 ;
     RECT  0.192 4.608 0.353 4.632 ;
     RECT  0.156 4.632 0.353 4.752 ;
     RECT  0.192 4.752 0.353 4.776 ;
     RECT  0.156 4.776 0.353 4.848 ;
     RECT  0.192 4.848 0.353 4.872 ;
     RECT  0.156 4.872 0.353 4.944 ;
     RECT  0.192 4.944 0.353 4.968 ;
     RECT  0.156 4.968 0.353 5.04 ;
     RECT  0.192 5.04 0.353 5.064 ;
     RECT  0.156 5.064 0.353 5.136 ;
     RECT  0.192 5.136 0.353 5.16 ;
     RECT  0.156 5.16 0.353 5.232 ;
     RECT  0.192 5.232 0.353 5.256 ;
     RECT  0.156 5.256 0.353 5.376 ;
     RECT  0.192 5.376 0.353 5.4 ;
     RECT  0.156 5.4 0.353 5.472 ;
     RECT  0.192 5.472 0.353 5.496 ;
     RECT  0.156 5.496 0.353 5.568 ;
     RECT  0.192 5.568 0.353 5.592 ;
     RECT  0.156 5.592 0.353 5.664 ;
     RECT  0.192 5.664 0.353 5.688 ;
     RECT  0.156 5.688 0.353 5.76 ;
     RECT  0.192 5.76 0.353 5.784 ;
     RECT  0.156 5.784 0.353 5.904 ;
     RECT  0.192 5.904 0.353 5.928 ;
     RECT  0.156 5.928 0.353 6 ;
     RECT  0.192 6 0.353 6.024 ;
     RECT  0.156 6.024 0.353 6.096 ;
     RECT  0.192 6.096 0.353 6.12 ;
     RECT  0.156 6.12 0.353 6.192 ;
     RECT  0.192 6.192 0.353 6.216 ;
     RECT  0.156 6.216 0.353 6.288 ;
     RECT  0.192 6.288 0.353 6.312 ;
     RECT  0.156 6.312 0.353 6.384 ;
     RECT  0.192 6.384 0.353 6.408 ;
     RECT  0.156 6.408 0.353 6.528 ;
     RECT  0.192 6.528 0.353 6.552 ;
     RECT  0.156 6.552 0.353 6.624 ;
     RECT  0.192 6.624 0.353 6.648 ;
     RECT  0.156 6.648 0.353 6.72 ;
     RECT  0.192 6.72 0.353 6.744 ;
     RECT  0.156 6.744 0.353 6.816 ;
     RECT  0.192 6.816 0.353 6.84 ;
     RECT  0.156 6.84 0.353 6.912 ;
     RECT  0.192 6.912 0.353 6.936 ;
     RECT  0.156 6.936 0.353 7.056 ;
     RECT  0.192 7.056 0.353 7.08 ;
     RECT  0.156 7.08 0.353 7.152 ;
     RECT  0.192 7.152 0.353 7.176 ;
     RECT  0.156 7.176 0.353 7.248 ;
     RECT  0.192 7.248 0.353 7.272 ;
     RECT  0.156 7.272 0.353 7.344 ;
     RECT  0.192 7.344 0.353 7.368 ;
     RECT  0.156 7.368 0.353 7.44 ;
     RECT  0.192 7.44 0.353 7.464 ;
     RECT  0.156 7.464 0.353 7.536 ;
     RECT  0.192 7.536 0.353 7.56 ;
     RECT  0.156 7.56 0.353 7.68 ;
     RECT  0.192 7.68 0.353 7.704 ;
     RECT  0.156 7.704 0.353 7.776 ;
     RECT  0.192 7.776 0.353 7.8 ;
     RECT  0.156 7.8 0.353 7.872 ;
     RECT  0.192 7.872 0.353 7.896 ;
     RECT  0.156 7.896 0.353 7.968 ;
     RECT  0.192 7.968 0.353 7.992 ;
     RECT  0.156 7.992 0.353 8.064 ;
     RECT  0.192 8.064 0.353 8.088 ;
     RECT  0.156 8.088 0.353 8.16 ;
     RECT  0.192 8.16 0.353 8.184 ;
     RECT  0.156 8.184 0.353 8.304 ;
     RECT  0.192 8.304 0.353 8.328 ;
     RECT  0.156 8.328 0.353 8.4 ;
     RECT  0.192 8.4 0.353 8.424 ;
     RECT  0.156 8.424 0.353 8.496 ;
     RECT  0.192 8.496 0.353 8.52 ;
     RECT  0.156 8.52 0.353 8.592 ;
     RECT  0.192 8.592 0.353 8.616 ;
     RECT  0.156 8.616 0.353 8.688 ;
     RECT  0.192 8.688 0.353 8.712 ;
     RECT  0.156 8.712 0.353 8.832 ;
     RECT  0.192 8.832 0.353 8.856 ;
     RECT  0.156 8.856 0.353 8.928 ;
     RECT  0.192 8.928 0.353 8.952 ;
     RECT  0.156 8.952 0.353 9.024 ;
     RECT  0.192 9.024 0.353 9.048 ;
     RECT  0.156 9.048 0.353 9.12 ;
     RECT  0.192 9.12 0.353 9.144 ;
     RECT  0.156 9.144 0.353 9.216 ;
     RECT  0.192 9.216 0.353 9.24 ;
     RECT  0.156 9.24 0.353 9.312 ;
     RECT  0.192 9.312 0.353 9.336 ;
     RECT  0.156 9.336 0.353 9.456 ;
     RECT  0.192 9.456 0.353 9.48 ;
     RECT  0.156 9.48 0.353 9.552 ;
     RECT  0.192 9.552 0.353 9.576 ;
     RECT  0.156 9.576 0.353 9.648 ;
     RECT  0.192 9.648 0.353 9.672 ;
     RECT  0.156 9.672 0.353 9.744 ;
     RECT  0.192 9.744 0.353 9.768 ;
     RECT  0.156 9.768 0.353 9.84 ;
     RECT  0.192 9.84 0.353 9.864 ;
     RECT  0.156 9.864 0.353 9.936 ;
     RECT  0.192 9.936 0.353 9.96 ;
     RECT  0.156 9.96 0.353 10.08 ;
     RECT  0.192 10.08 0.353 10.104 ;
     RECT  0.156 10.104 0.353 10.176 ;
     RECT  0.192 10.176 0.353 10.2 ;
     RECT  0.156 10.2 0.353 10.272 ;
     RECT  0.192 10.272 0.353 10.296 ;
     RECT  0.156 10.296 0.353 10.368 ;
     RECT  0.192 10.368 0.353 10.392 ;
     RECT  0.156 10.392 0.353 10.464 ;
     RECT  0.192 10.464 0.353 10.488 ;
     RECT  0.156 10.488 0.353 10.608 ;
     RECT  0.192 10.608 0.353 10.632 ;
     RECT  0.156 10.632 0.353 10.704 ;
     RECT  0.192 10.704 0.353 10.728 ;
     RECT  0.156 10.728 0.353 10.8 ;
     RECT  0.192 10.8 0.353 10.824 ;
     RECT  0.156 10.824 0.353 10.896 ;
     RECT  0.192 10.896 0.353 10.92 ;
     RECT  0.156 10.92 0.353 10.992 ;
     RECT  0.192 10.992 0.353 11.016 ;
     RECT  0.156 11.016 0.353 11.088 ;
     RECT  0.192 11.088 0.353 11.112 ;
     RECT  0.156 11.112 0.353 11.232 ;
     RECT  0.192 11.232 0.353 11.256 ;
     RECT  0.156 11.256 0.353 11.328 ;
     RECT  0.192 11.328 0.353 11.352 ;
     RECT  0.156 11.352 0.353 11.424 ;
     RECT  0.192 11.424 0.353 11.448 ;
     RECT  0.156 11.448 0.353 11.52 ;
     RECT  0.192 11.52 0.353 11.544 ;
     RECT  0.156 11.544 0.353 11.616 ;
     RECT  0.192 11.616 0.353 11.64 ;
     RECT  0.156 11.64 0.353 11.712 ;
     RECT  0.192 11.712 0.353 11.736 ;
     RECT  0.156 11.736 0.353 11.856 ;
     RECT  0.192 11.856 0.353 11.88 ;
     RECT  0.156 11.88 0.353 11.952 ;
     RECT  0.192 11.952 0.353 11.976 ;
     RECT  0.156 11.976 0.353 12.048 ;
     RECT  0.192 12.048 0.353 12.072 ;
     RECT  0.156 12.072 0.353 12.144 ;
     RECT  0.192 12.144 0.353 12.168 ;
     RECT  0.156 12.168 0.353 12.24 ;
     RECT  0.192 12.24 0.353 12.264 ;
     RECT  0.156 12.264 0.353 12.384 ;
     RECT  0.192 12.384 0.353 12.408 ;
     RECT  0.156 12.408 0.353 12.48 ;
     RECT  0.192 12.48 0.353 12.504 ;
     RECT  0.156 12.504 0.353 12.576 ;
     RECT  0.192 12.576 0.353 12.6 ;
     RECT  0.156 12.6 0.353 12.672 ;
     RECT  0.192 12.672 0.353 12.696 ;
     RECT  0.156 12.696 0.353 12.768 ;
     RECT  0.192 12.768 0.353 12.792 ;
     RECT  0.156 12.792 0.353 12.864 ;
     RECT  0.192 12.864 0.353 12.888 ;
     RECT  0.156 12.888 0.353 13.008 ;
     RECT  0.192 13.008 0.353 13.032 ;
     RECT  0.156 13.032 0.353 13.104 ;
     RECT  0.192 13.104 0.353 13.128 ;
     RECT  0.156 13.128 0.353 13.2 ;
     RECT  0.192 13.2 0.353 13.224 ;
     RECT  0.156 13.224 0.353 13.296 ;
     RECT  0.192 13.296 0.353 13.32 ;
     RECT  0.156 13.32 0.353 13.392 ;
     RECT  0.192 13.392 0.353 13.416 ;
     RECT  0.156 13.416 0.353 13.488 ;
     RECT  0.192 13.488 0.353 13.512 ;
     RECT  0.156 13.512 0.353 13.632 ;
     RECT  0.192 13.632 0.353 13.656 ;
     RECT  0.156 13.656 0.353 13.728 ;
     RECT  0.192 13.728 0.353 13.752 ;
     RECT  0.156 13.752 0.353 13.824 ;
     RECT  0.192 13.824 0.353 13.848 ;
     RECT  0.156 13.848 0.353 13.92 ;
     RECT  0.192 13.92 0.353 13.944 ;
     RECT  0.156 13.944 0.353 14.016 ;
     RECT  0.192 14.016 0.353 14.04 ;
     RECT  0.156 14.04 0.353 14.16 ;
     RECT  0.192 14.16 0.353 14.184 ;
     RECT  0.156 14.184 0.353 14.256 ;
     RECT  0.192 14.256 0.353 14.28 ;
     RECT  0.156 14.28 0.353 14.352 ;
     RECT  0.192 14.352 0.353 14.376 ;
     RECT  0.156 14.376 0.353 14.448 ;
     RECT  0.192 14.448 0.353 14.472 ;
     RECT  0.156 14.472 0.353 14.544 ;
     RECT  0.192 14.544 0.353 14.568 ;
     RECT  0.156 14.568 0.353 14.64 ;
     RECT  0.192 14.64 0.353 14.664 ;
     RECT  0.156 14.664 0.353 14.784 ;
     RECT  0.192 14.784 0.353 14.808 ;
     RECT  0.156 14.808 0.353 14.88 ;
     RECT  0.192 14.88 0.353 14.904 ;
     RECT  0.156 14.904 0.353 14.976 ;
     RECT  0.192 14.976 0.353 15 ;
     RECT  0.156 15 0.353 15.072 ;
     RECT  0.192 15.072 0.353 15.096 ;
     RECT  0.156 15.096 0.353 15.168 ;
     RECT  0.192 15.168 0.353 15.192 ;
     RECT  0.156 15.192 0.353 15.312 ;
     RECT  0.192 15.312 0.353 15.336 ;
     RECT  0.156 15.336 0.353 15.408 ;
     RECT  0.192 15.408 0.353 15.432 ;
     RECT  0.156 15.432 0.353 15.504 ;
     RECT  0.192 15.504 0.353 15.528 ;
     RECT  0.156 15.528 0.353 15.6 ;
     RECT  0.192 15.6 0.353 15.624 ;
     RECT  0.156 15.624 0.353 15.696 ;
     RECT  0.192 15.696 0.353 15.72 ;
     RECT  0.156 15.72 0.353 15.792 ;
     RECT  0.192 15.792 0.353 15.816 ;
     RECT  0.156 15.816 0.353 15.936 ;
     RECT  0.192 15.936 0.353 15.96 ;
     RECT  0.156 15.96 0.353 16.032 ;
     RECT  0.192 16.032 0.353 16.056 ;
     RECT  0.156 16.056 0.353 16.128 ;
     RECT  0.192 16.128 0.353 16.152 ;
     RECT  0.156 16.152 0.353 16.224 ;
     RECT  0.192 16.224 0.353 16.248 ;
     RECT  0.156 16.248 0.353 16.32 ;
     RECT  0.192 16.32 0.353 16.344 ;
     RECT  0.156 16.344 0.353 16.416 ;
     RECT  0.192 16.416 0.353 16.44 ;
     RECT  0.156 16.44 0.353 16.56 ;
     RECT  0.192 16.56 0.353 16.584 ;
     RECT  0.156 16.584 0.353 16.656 ;
     RECT  0.192 16.656 0.353 16.68 ;
     RECT  0.156 16.68 0.353 16.752 ;
     RECT  0.192 16.752 0.353 16.776 ;
     RECT  0.156 16.776 0.353 16.848 ;
     RECT  0.192 16.848 0.353 16.872 ;
     RECT  0.156 16.872 0.353 16.944 ;
     RECT  0.192 16.944 0.353 16.968 ;
     RECT  0.156 16.968 0.353 17.088 ;
     RECT  0.192 17.088 0.353 17.112 ;
     RECT  0.156 17.112 0.353 17.184 ;
     RECT  0.192 17.184 0.353 17.208 ;
     RECT  0.156 17.208 0.353 17.28 ;
     RECT  0.192 17.28 0.353 17.304 ;
     RECT  0.156 17.304 0.353 17.376 ;
     RECT  0.192 17.376 0.353 17.4 ;
     RECT  0.156 17.4 0.353 17.472 ;
     RECT  0.192 17.472 0.353 17.496 ;
     RECT  0.156 17.496 0.353 17.568 ;
     RECT  0.192 17.568 0.353 17.592 ;
     RECT  0.156 17.592 0.353 17.712 ;
     RECT  0.192 17.712 0.353 17.736 ;
     RECT  0.156 17.736 0.353 17.808 ;
     RECT  0.192 17.808 0.353 17.832 ;
     RECT  0.156 17.832 0.353 17.904 ;
     RECT  0.192 17.904 0.353 17.928 ;
     RECT  0.156 17.928 0.353 18 ;
     RECT  0.192 18 0.353 18.024 ;
     RECT  0.156 18.024 0.353 18.096 ;
     RECT  0.192 18.096 0.353 18.12 ;
     RECT  0.156 18.12 0.353 18.192 ;
     RECT  0.192 18.192 0.353 18.216 ;
     RECT  0.156 18.216 0.353 18.336 ;
     RECT  0.192 18.336 0.353 18.36 ;
     RECT  0.156 18.36 0.353 18.432 ;
     RECT  0.192 18.432 0.353 18.456 ;
     RECT  0.156 18.456 0.353 18.528 ;
     RECT  0.192 18.528 0.353 18.552 ;
     RECT  0.156 18.552 0.353 18.624 ;
     RECT  0.192 18.624 0.353 18.648 ;
     RECT  0.156 18.648 0.353 18.72 ;
     RECT  0.192 18.72 0.353 18.744 ;
     RECT  0.156 18.744 0.353 18.864 ;
     RECT  0.192 18.864 0.353 18.888 ;
     RECT  0.156 18.888 0.353 18.96 ;
     RECT  0.192 18.96 0.353 18.984 ;
     RECT  0.156 18.984 0.353 19.056 ;
     RECT  0.192 19.056 0.353 19.08 ;
     RECT  0.156 19.08 0.353 19.152 ;
     RECT  0.192 19.152 0.353 19.176 ;
     RECT  0.156 19.176 0.353 19.248 ;
     RECT  0.192 19.248 0.353 19.272 ;
     RECT  0.156 19.272 0.353 19.344 ;
     RECT  0.192 19.344 0.353 19.368 ;
     RECT  0.156 19.368 0.353 19.488 ;
     RECT  0.192 19.488 0.353 19.512 ;
     RECT  0.156 19.512 0.353 19.584 ;
     RECT  0.192 19.584 0.353 19.608 ;
     RECT  0.156 19.608 0.353 19.68 ;
     RECT  0.192 19.68 0.353 19.704 ;
     RECT  0.156 19.704 0.353 19.776 ;
     RECT  0.192 19.776 0.353 19.8 ;
     RECT  0.156 19.8 0.353 19.872 ;
     RECT  0.192 19.872 0.353 19.896 ;
     RECT  0.156 19.896 0.353 20.016 ;
     RECT  0.192 20.016 0.353 20.04 ;
     RECT  0.156 20.04 0.353 20.112 ;
     RECT  0.192 20.112 0.353 20.136 ;
     RECT  0.156 20.136 0.353 20.208 ;
     RECT  0.192 20.208 0.353 20.232 ;
     RECT  0.156 20.232 0.353 20.304 ;
     RECT  0.192 20.304 0.353 20.328 ;
     RECT  0.156 20.328 0.353 20.4 ;
     RECT  0.192 20.4 0.353 20.424 ;
     RECT  0.156 20.424 0.353 20.496 ;
     RECT  0.192 20.496 0.353 20.52 ;
     RECT  0.156 20.52 0.353 20.64 ;
     RECT  0.192 20.64 0.353 20.664 ;
     RECT  0.156 20.664 0.353 20.736 ;
     RECT  0.192 20.736 0.353 20.76 ;
     RECT  0.156 20.76 0.353 20.832 ;
     RECT  0.192 20.832 0.353 20.856 ;
     RECT  0.156 20.856 0.353 20.928 ;
     RECT  0.192 20.928 0.353 20.952 ;
     RECT  0.156 20.952 0.353 21.024 ;
     RECT  0.192 21.024 0.353 21.048 ;
     RECT  0.156 21.048 0.353 21.12 ;
     RECT  0.192 21.12 0.353 21.144 ;
     RECT  0.156 21.144 0.353 21.264 ;
     RECT  0.192 21.264 0.353 21.288 ;
     RECT  0.156 21.288 0.353 21.36 ;
     RECT  0.192 21.36 0.353 21.384 ;
     RECT  0.156 21.384 0.353 21.456 ;
     RECT  0.192 21.456 0.353 21.48 ;
     RECT  0.156 21.48 0.353 21.552 ;
     RECT  0.192 21.552 0.353 21.576 ;
     RECT  0.156 21.576 0.353 21.648 ;
     RECT  0.192 21.648 0.353 21.672 ;
     RECT  0.156 21.672 0.353 21.792 ;
     RECT  0.192 21.792 0.353 21.816 ;
     RECT  0.156 21.816 0.353 21.888 ;
     RECT  0.192 21.888 0.353 21.912 ;
     RECT  0.156 21.912 0.353 21.984 ;
     RECT  0.192 21.984 0.353 22.008 ;
     RECT  0.156 22.008 0.353 22.08 ;
     RECT  0.192 22.08 0.353 22.104 ;
     RECT  0.156 22.104 0.353 22.176 ;
     RECT  0.192 22.176 0.353 22.2 ;
     RECT  0.156 22.2 0.353 22.272 ;
     RECT  0.192 22.272 0.353 22.296 ;
     RECT  0.156 22.296 0.353 22.416 ;
     RECT  0.192 22.416 0.353 22.44 ;
     RECT  0.156 22.44 0.353 22.512 ;
     RECT  0.192 22.512 0.353 22.536 ;
     RECT  0.156 22.536 0.353 22.608 ;
     RECT  0.192 22.608 0.353 22.632 ;
     RECT  0.156 22.632 0.353 22.704 ;
     RECT  0.192 22.704 0.353 22.728 ;
     RECT  0.156 22.728 0.353 22.8 ;
     RECT  0.192 22.8 0.353 22.824 ;
     RECT  0.156 22.824 0.353 22.896 ;
     RECT  0.192 22.896 0.353 22.92 ;
     RECT  0.156 22.92 0.353 23.04 ;
     RECT  0.192 23.04 0.353 23.064 ;
     RECT  0.156 23.064 0.353 23.136 ;
     RECT  0.192 23.136 0.353 23.16 ;
     RECT  0.156 23.16 0.353 23.232 ;
     RECT  0.192 23.232 0.353 23.256 ;
     RECT  0.156 23.256 0.353 23.328 ;
     RECT  0.192 23.328 0.353 23.352 ;
     RECT  0.156 23.352 0.353 23.424 ;
     RECT  0.192 23.424 0.353 23.448 ;
     RECT  0.156 23.448 0.353 23.568 ;
     RECT  0.192 23.568 0.353 23.592 ;
     RECT  0.156 23.592 0.353 23.664 ;
     RECT  0.192 23.664 0.353 23.688 ;
     RECT  0.156 23.688 0.353 23.76 ;
     RECT  0.192 23.76 0.353 23.784 ;
     RECT  0.156 23.784 0.353 23.856 ;
     RECT  0.192 23.856 0.353 23.88 ;
     RECT  0.156 23.88 0.353 23.952 ;
     RECT  0.192 23.952 0.353 23.976 ;
     RECT  0.156 23.976 0.353 24.048 ;
     RECT  0.192 24.048 0.353 24.072 ;
     RECT  0.156 24.072 0.353 24.192 ;
     RECT  0.192 24.192 0.353 24.216 ;
     RECT  0.156 24.216 0.353 24.288 ;
     RECT  0.192 24.288 0.353 24.312 ;
     RECT  0.156 24.312 0.353 24.384 ;
     RECT  0.192 24.384 0.353 24.408 ;
     RECT  0.156 24.408 0.353 24.48 ;
     RECT  0.192 24.48 0.353 24.504 ;
     RECT  0.156 24.504 0.353 24.576 ;
     RECT  0.192 24.576 0.353 24.6 ;
     RECT  0.156 24.6 0.353 24.672 ;
     RECT  0.192 24.672 0.353 24.696 ;
     RECT  0.156 24.696 0.353 24.816 ;
     RECT  0.192 24.816 0.353 24.84 ;
     RECT  0.156 24.84 0.353 24.912 ;
     RECT  0.192 24.912 0.353 24.936 ;
     RECT  0.156 24.936 0.353 25.008 ;
     RECT  0.192 25.008 0.353 25.032 ;
     RECT  0.156 25.032 0.353 25.104 ;
     RECT  0.192 25.104 0.353 25.128 ;
     RECT  0.156 25.128 0.353 25.2 ;
     RECT  0.192 25.2 0.353 25.224 ;
     RECT  0.156 25.224 0.353 25.344 ;
     RECT  0.192 25.344 0.353 25.368 ;
     RECT  0.156 25.368 0.353 25.44 ;
     RECT  0.192 25.44 0.353 25.464 ;
     RECT  0.156 25.464 0.353 25.536 ;
     RECT  0.192 25.536 0.353 25.56 ;
     RECT  0.156 25.56 0.353 25.632 ;
     RECT  0.192 25.632 0.353 25.656 ;
     RECT  0.156 25.656 0.353 25.728 ;
     RECT  0.192 25.728 0.353 25.752 ;
     RECT  0.156 25.752 0.353 25.824 ;
     RECT  0.192 25.824 0.353 25.848 ;
     RECT  0.156 25.848 0.353 25.968 ;
     RECT  0.192 25.968 0.353 25.992 ;
     RECT  0.156 25.992 0.353 26.064 ;
     RECT  0.192 26.064 0.353 26.088 ;
     RECT  0.156 26.088 0.353 26.16 ;
     RECT  0.192 26.16 0.353 26.184 ;
     RECT  0.156 26.184 0.353 26.256 ;
     RECT  0.192 26.256 0.353 26.28 ;
     RECT  0.156 26.28 0.353 26.352 ;
     RECT  0.192 26.352 0.353 26.376 ;
     RECT  0.156 26.376 0.353 26.448 ;
     RECT  0.192 26.448 0.353 26.472 ;
     RECT  0.156 26.472 0.353 26.592 ;
     RECT  0.192 26.592 0.353 26.616 ;
     RECT  0.156 26.616 0.353 26.688 ;
     RECT  0.192 26.688 0.353 26.712 ;
     RECT  0.156 26.712 0.353 26.784 ;
     RECT  0.192 26.784 0.353 26.808 ;
     RECT  0.156 26.808 0.353 26.88 ;
     RECT  0.192 26.88 0.353 26.904 ;
     RECT  0.156 26.904 0.353 26.976 ;
     RECT  0.192 26.976 0.353 27 ;
     RECT  0.156 27 0.353 27.12 ;
     RECT  0.192 27.12 0.353 27.144 ;
     RECT  0.156 27.144 0.353 27.216 ;
     RECT  0.192 27.216 0.353 27.24 ;
     RECT  0.156 27.24 0.353 27.312 ;
     RECT  0.192 27.312 0.353 27.336 ;
     RECT  0.156 27.336 0.353 27.408 ;
     RECT  0.192 27.408 0.353 27.432 ;
     RECT  0.156 27.432 0.353 27.504 ;
     RECT  0.192 27.504 0.353 27.528 ;
     RECT  0.156 27.528 0.353 27.6 ;
     RECT  0.192 27.6 0.353 27.624 ;
     RECT  0.156 27.624 0.353 27.744 ;
     RECT  0.192 27.744 0.353 27.768 ;
     RECT  0.156 27.768 0.353 27.84 ;
     RECT  0.192 27.84 0.353 27.864 ;
     RECT  0.156 27.864 0.353 27.936 ;
     RECT  0.192 27.936 0.353 27.96 ;
     RECT  0.156 27.96 0.353 28.032 ;
     RECT  0.192 28.032 0.353 28.056 ;
     RECT  0.156 28.056 0.353 28.128 ;
     RECT  0.192 28.128 0.353 28.152 ;
     RECT  0.156 28.152 0.353 28.272 ;
     RECT  0.192 28.272 0.353 28.296 ;
     RECT  0.156 28.296 0.353 28.368 ;
     RECT  0.192 28.368 0.353 28.392 ;
     RECT  0.156 28.392 0.353 28.464 ;
     RECT  0.192 28.464 0.353 28.488 ;
     RECT  0.156 28.488 0.353 28.56 ;
     RECT  0.192 28.56 0.353 28.584 ;
     RECT  0.156 28.584 0.353 28.656 ;
     RECT  0.192 28.656 0.353 28.68 ;
     RECT  0.156 28.68 0.353 28.752 ;
     RECT  0.192 28.752 0.353 28.776 ;
     RECT  0.156 28.776 0.353 28.896 ;
     RECT  0.192 28.896 0.353 28.92 ;
     RECT  0.156 28.92 0.353 28.992 ;
     RECT  0.192 28.992 0.353 29.016 ;
     RECT  0.156 29.016 0.353 29.088 ;
     RECT  0.192 29.088 0.353 29.112 ;
     RECT  0.156 29.112 0.353 29.184 ;
     RECT  0.192 29.184 0.353 29.208 ;
     RECT  0.156 29.208 0.353 29.28 ;
     RECT  0.192 29.28 0.353 29.304 ;
     RECT  0.156 29.304 0.353 29.376 ;
     RECT  0.192 29.376 0.353 29.4 ;
     RECT  0.156 29.4 0.353 29.52 ;
     RECT  0.192 29.52 0.353 29.544 ;
     RECT  0.156 29.544 0.353 29.616 ;
     RECT  0.192 29.616 0.353 29.64 ;
     RECT  0.156 29.64 0.353 29.712 ;
     RECT  0.192 29.712 0.353 29.736 ;
     RECT  0.156 29.736 0.353 29.808 ;
     RECT  0.192 29.808 0.353 29.832 ;
     RECT  0.156 29.832 0.353 29.904 ;
     RECT  0.192 29.904 0.353 29.928 ;
     RECT  0.156 29.928 0.353 30.048 ;
     RECT  0.192 30.048 0.353 30.072 ;
     RECT  0.156 30.072 0.353 30.144 ;
     RECT  0.192 30.144 0.353 30.168 ;
     RECT  0.156 30.168 0.353 30.24 ;
     RECT  0.192 30.24 0.353 30.264 ;
     RECT  0.156 30.264 0.353 30.336 ;
     RECT  0.192 30.336 0.353 30.36 ;
     RECT  0.156 30.36 0.353 30.432 ;
     RECT  0.192 30.432 0.353 30.456 ;
     RECT  0.156 30.456 0.353 30.528 ;
     RECT  0.192 30.528 0.353 30.552 ;
     RECT  0.156 30.552 0.353 30.672 ;
     RECT  0.192 30.672 0.353 30.696 ;
     RECT  0.156 30.696 0.353 30.768 ;
     RECT  0.192 30.768 0.353 30.792 ;
     RECT  0.156 30.792 0.353 30.864 ;
     RECT  0.192 30.864 0.353 30.888 ;
     RECT  0.156 30.888 0.353 30.96 ;
     RECT  0.192 30.96 0.353 30.984 ;
     RECT  0.156 30.984 0.353 31.056 ;
     RECT  0.192 31.056 0.353 31.08 ;
     RECT  0.156 31.08 0.353 31.152 ;
     RECT  0.192 31.152 0.353 31.176 ;
     RECT  0.156 31.176 0.353 31.296 ;
     RECT  0.192 31.296 0.353 31.32 ;
     RECT  0.156 31.32 0.353 31.392 ;
     RECT  0.192 31.392 0.353 31.416 ;
     RECT  0.156 31.416 0.353 31.488 ;
     RECT  0.192 31.488 0.353 31.512 ;
     RECT  0.156 31.512 0.353 31.584 ;
     RECT  0.192 31.584 0.353 31.608 ;
     RECT  0.156 31.608 0.353 31.68 ;
     RECT  0.192 31.68 0.353 31.704 ;
     RECT  0.156 31.704 0.353 31.824 ;
     RECT  0.192 31.824 0.353 31.848 ;
     RECT  0.156 31.848 0.353 31.92 ;
     RECT  0.192 31.92 0.353 31.944 ;
     RECT  0.156 31.944 0.353 32.016 ;
     RECT  0.192 32.016 0.353 32.04 ;
     RECT  0.156 32.04 0.353 32.112 ;
     RECT  0.192 32.112 0.353 32.136 ;
     RECT  0.156 32.136 0.353 32.208 ;
     RECT  0.192 32.208 0.353 32.232 ;
     RECT  0.156 32.232 0.353 32.304 ;
     RECT  0.192 32.304 0.353 32.328 ;
     RECT  0.156 32.328 0.353 32.448 ;
     RECT  0.192 32.448 0.353 32.472 ;
     RECT  0.156 32.472 0.353 32.544 ;
     RECT  0.192 32.544 0.353 32.568 ;
     RECT  0.156 32.568 0.353 32.64 ;
     RECT  0.192 32.64 0.353 32.664 ;
     RECT  0.156 32.664 0.353 32.736 ;
     RECT  0.192 32.736 0.353 32.76 ;
     RECT  0.156 32.76 0.353 32.832 ;
     RECT  0.192 32.832 0.353 32.856 ;
     RECT  0.156 32.856 0.353 32.928 ;
     RECT  0.192 32.928 0.353 32.952 ;
     RECT  0.156 32.952 0.353 33.072 ;
     RECT  0.192 33.072 0.353 33.096 ;
     RECT  0.156 33.096 0.353 33.168 ;
     RECT  0.192 33.168 0.353 33.192 ;
     RECT  0.156 33.192 0.353 33.264 ;
     RECT  0.192 33.264 0.353 33.288 ;
     RECT  0.156 33.288 0.353 33.36 ;
     RECT  0.192 33.36 0.353 33.384 ;
     RECT  0.156 33.384 0.353 33.456 ;
     RECT  0.192 33.456 0.353 33.48 ;
     RECT  0.156 33.48 0.353 33.6 ;
     RECT  0.192 33.6 0.353 33.624 ;
     RECT  0.156 33.624 0.353 33.696 ;
     RECT  0.192 33.696 0.353 33.72 ;
     RECT  0.156 33.72 0.353 33.792 ;
     RECT  0.192 33.792 0.353 33.816 ;
     RECT  0.156 33.816 0.353 33.888 ;
     RECT  0.192 33.888 0.353 33.912 ;
     RECT  0.156 33.912 0.353 33.984 ;
     RECT  0.192 33.984 0.353 34.008 ;
     RECT  0.156 34.008 0.353 34.08 ;
     RECT  0.192 34.08 0.353 34.104 ;
     RECT  0.156 34.104 0.353 34.224 ;
     RECT  0.192 34.224 0.353 34.248 ;
     RECT  0.156 34.248 0.353 34.32 ;
     RECT  0.192 34.32 0.353 34.344 ;
     RECT  0.156 34.344 0.353 34.416 ;
     RECT  0.192 34.416 0.353 34.44 ;
     RECT  0.156 34.44 0.353 34.512 ;
     RECT  0.192 34.512 0.353 34.536 ;
     RECT  0.156 34.536 0.353 34.608 ;
     RECT  0.192 34.608 0.353 34.632 ;
     RECT  0.156 34.632 0.353 34.752 ;
     RECT  0.192 34.752 0.353 34.776 ;
     RECT  0.156 34.776 0.353 34.848 ;
     RECT  0.192 34.848 0.353 34.872 ;
     RECT  0.156 34.872 0.353 34.944 ;
     RECT  0.192 34.944 0.353 34.968 ;
     RECT  0.156 34.968 0.353 35.04 ;
     RECT  0.192 35.04 0.353 35.064 ;
     RECT  0.156 35.064 0.353 35.136 ;
     RECT  0.192 35.136 0.353 35.16 ;
     RECT  0.156 35.16 0.353 35.232 ;
     RECT  0.192 35.232 0.353 35.256 ;
     RECT  0.156 35.256 0.353 35.376 ;
     RECT  0.192 35.376 0.353 35.4 ;
     RECT  0.156 35.4 0.353 35.472 ;
     RECT  0.192 35.472 0.353 35.496 ;
     RECT  0.156 35.496 0.353 35.568 ;
     RECT  0.192 35.568 0.353 35.592 ;
     RECT  0.156 35.592 0.353 35.664 ;
     RECT  0.192 35.664 0.353 35.688 ;
     RECT  0.156 35.688 0.353 35.76 ;
     RECT  0.192 35.76 0.353 35.784 ;
     RECT  0.156 35.784 0.353 35.856 ;
     RECT  0.192 35.856 0.353 35.88 ;
     RECT  0.156 35.88 0.353 36 ;
     RECT  0.192 36 0.353 36.024 ;
     RECT  0.156 36.024 0.353 36.096 ;
     RECT  0.192 36.096 0.353 36.12 ;
     RECT  0.156 36.12 0.353 36.192 ;
     RECT  0.192 36.192 0.353 36.216 ;
     RECT  0.156 36.216 0.353 36.288 ;
     RECT  0.192 36.288 0.353 36.312 ;
     RECT  0.156 36.312 0.353 36.384 ;
     RECT  0.192 36.384 0.353 36.408 ;
     RECT  0.156 36.408 0.353 36.528 ;
     RECT  0.192 36.528 0.353 36.552 ;
     RECT  0.156 36.552 0.353 36.624 ;
     RECT  0.192 36.624 0.353 36.648 ;
     RECT  0.156 36.648 0.353 36.72 ;
     RECT  0.192 36.72 0.353 36.744 ;
     RECT  0.156 36.744 0.353 36.816 ;
     RECT  0.192 36.816 0.353 36.84 ;
     RECT  0.156 36.84 0.353 36.912 ;
     RECT  0.192 36.912 0.353 36.936 ;
     RECT  0.156 36.936 0.353 37.008 ;
     RECT  0.192 37.008 0.353 37.032 ;
     RECT  0.156 37.032 0.353 37.152 ;
     RECT  0.192 37.152 0.353 37.176 ;
     RECT  0.156 37.176 0.353 37.248 ;
     RECT  0.192 37.248 0.353 37.272 ;
     RECT  0.156 37.272 0.353 37.344 ;
     RECT  0.192 37.344 0.353 37.368 ;
     RECT  0.156 37.368 0.353 37.44 ;
     RECT  0.192 37.44 0.353 37.464 ;
     RECT  0.156 37.464 0.353 37.536 ;
     RECT  0.192 37.536 0.353 37.56 ;
     RECT  0.156 37.56 0.353 37.632 ;
     RECT  0.192 37.632 0.353 37.656 ;
     RECT  0.156 37.656 0.353 37.776 ;
     RECT  0.192 37.776 0.353 37.8 ;
     RECT  0.156 37.8 0.353 37.872 ;
     RECT  0.192 37.872 0.353 37.896 ;
     RECT  0.156 37.896 0.353 37.968 ;
     RECT  0.192 37.968 0.353 37.992 ;
     RECT  0.156 37.992 0.353 38.064 ;
     RECT  0.192 38.064 0.353 38.088 ;
     RECT  0.156 38.088 0.353 38.16 ;
     RECT  0.192 38.16 0.353 38.184 ;
     RECT  0.156 38.184 0.353 38.304 ;
     RECT  0.192 38.304 0.353 38.328 ;
     RECT  0.156 38.328 0.353 38.4 ;
     RECT  0.192 38.4 0.353 38.424 ;
     RECT  0.156 38.424 0.353 38.496 ;
     RECT  0.192 38.496 0.353 38.52 ;
     RECT  0.156 38.52 0.353 38.592 ;
     RECT  0.192 38.592 0.353 38.616 ;
     RECT  0.156 38.616 0.353 38.688 ;
     RECT  0.192 38.688 0.353 38.712 ;
     RECT  0.156 38.712 0.353 38.784 ;
     RECT  0.192 38.784 0.353 38.808 ;
     RECT  0.156 38.808 0.353 38.928 ;
     RECT  0.192 38.928 0.353 38.952 ;
     RECT  0.156 38.952 0.353 39.024 ;
     RECT  0.192 39.024 0.353 39.048 ;
     RECT  0.156 39.048 0.353 39.12 ;
     RECT  0.192 39.12 0.353 39.144 ;
     RECT  0.156 39.144 0.353 39.216 ;
     RECT  0.192 39.216 0.353 39.24 ;
     RECT  0.156 39.24 0.353 39.312 ;
     RECT  0.192 39.312 0.353 39.336 ;
     RECT  0.156 39.336 0.353 39.408 ;
     RECT  0.192 39.408 0.353 39.432 ;
     RECT  0.156 39.432 0.353 39.552 ;
     RECT  0.192 39.552 0.353 39.576 ;
     RECT  0.156 39.576 0.353 39.648 ;
     RECT  0.192 39.648 0.353 39.672 ;
     RECT  0.156 39.672 0.353 39.744 ;
     RECT  0.192 39.744 0.353 39.768 ;
     RECT  0.156 39.768 0.353 39.84 ;
     RECT  0.192 39.84 0.353 39.864 ;
     RECT  0.156 39.864 0.353 39.936 ;
     RECT  0.192 39.936 0.353 39.96 ;
     RECT  0.156 39.96 0.353 40.08 ;
     RECT  0.192 40.08 0.353 40.104 ;
     RECT  0.156 40.104 0.353 40.176 ;
     RECT  0.192 40.176 0.353 40.2 ;
     RECT  0.156 40.2 0.353 40.272 ;
     RECT  0.192 40.272 0.353 40.296 ;
     RECT  0.156 40.296 0.353 40.368 ;
     RECT  0.192 40.368 0.353 40.392 ;
     RECT  0.156 40.392 0.353 40.464 ;
     RECT  0.192 40.464 0.353 40.488 ;
     RECT  0.156 40.488 0.353 40.56 ;
     RECT  0.192 40.56 0.353 40.584 ;
     RECT  0.156 40.584 0.353 40.704 ;
     RECT  0.192 40.704 0.353 40.728 ;
     RECT  0.156 40.728 0.353 40.8 ;
     RECT  0.192 40.8 0.353 40.824 ;
     RECT  0.156 40.824 0.353 40.896 ;
     RECT  0.192 40.896 0.353 40.92 ;
     RECT  0.156 40.92 0.353 40.992 ;
     RECT  0.192 40.992 0.353 41.016 ;
     RECT  0.156 41.016 0.353 41.088 ;
     RECT  0.192 41.088 0.353 41.112 ;
     RECT  0.156 41.112 0.353 41.232 ;
     RECT  0.192 41.232 0.353 41.256 ;
     RECT  0.156 41.256 0.353 41.328 ;
     RECT  0.192 41.328 0.353 41.352 ;
     RECT  0.156 41.352 0.353 41.424 ;
     RECT  0.192 41.424 0.353 41.448 ;
     RECT  0.156 41.448 0.353 41.52 ;
     RECT  0.192 41.52 0.353 41.544 ;
     RECT  0.156 41.544 0.353 41.616 ;
     RECT  0.192 41.616 0.353 41.64 ;
     RECT  0.156 41.64 0.353 41.712 ;
     RECT  0.192 41.712 0.353 41.736 ;
     RECT  0.156 41.736 0.353 41.856 ;
     RECT  0.192 41.856 0.353 41.88 ;
     RECT  0.156 41.88 0.353 41.952 ;
     RECT  0.192 41.952 0.353 41.976 ;
     RECT  0.156 41.976 0.353 42.048 ;
     RECT  0.192 42.048 0.353 42.072 ;
     RECT  0.156 42.072 0.353 42.144 ;
     RECT  0.192 42.144 0.353 42.168 ;
     RECT  0.156 42.168 0.353 42.24 ;
     RECT  0.192 42.24 0.353 42.264 ;
     RECT  0.156 42.264 0.353 42.336 ;
     RECT  0.192 42.336 0.353 42.36 ;
     RECT  0.156 42.36 0.353 42.48 ;
     RECT  0.192 42.48 0.353 42.504 ;
     RECT  0.156 42.504 0.353 42.576 ;
     RECT  0.192 42.576 0.353 42.6 ;
     RECT  0.156 42.6 0.353 42.672 ;
     RECT  0.192 42.672 0.353 42.696 ;
     RECT  0.156 42.696 0.353 42.768 ;
     RECT  0.192 42.768 0.353 42.792 ;
     RECT  0.156 42.792 0.353 42.864 ;
     RECT  0.192 42.864 0.353 42.888 ;
     RECT  0.156 42.888 0.353 43.008 ;
     RECT  0.192 43.008 0.353 43.032 ;
     RECT  0.156 43.032 0.353 43.104 ;
     RECT  0.192 43.104 0.353 43.128 ;
     RECT  0.156 43.128 0.353 43.2 ;
     RECT  0.192 43.2 0.353 43.224 ;
     RECT  0.156 43.224 0.353 43.296 ;
     RECT  0.192 43.296 0.353 43.32 ;
     RECT  0.156 43.32 0.353 43.392 ;
     RECT  0.192 43.392 0.353 43.416 ;
     RECT  0.156 43.416 0.353 43.488 ;
     RECT  0.192 43.488 0.353 43.512 ;
     RECT  0.156 43.512 0.353 43.632 ;
     RECT  0.192 43.632 0.353 43.656 ;
     RECT  0.156 43.656 0.353 43.728 ;
     RECT  0.192 43.728 0.353 43.752 ;
     RECT  0.156 43.752 0.353 43.824 ;
     RECT  0.192 43.824 0.353 43.848 ;
     RECT  0.156 43.848 0.353 43.92 ;
     RECT  0.192 43.92 0.353 43.944 ;
     RECT  0.156 43.944 0.353 44.016 ;
     RECT  0.192 44.016 0.353 44.04 ;
     RECT  0.156 44.04 0.353 44.112 ;
     RECT  0.192 44.112 0.353 44.136 ;
     RECT  0.156 44.136 0.353 44.256 ;
     RECT  0.192 44.256 0.353 44.28 ;
     RECT  0.156 44.28 0.353 44.352 ;
     RECT  0.192 44.352 0.353 44.376 ;
     RECT  0.156 44.376 0.353 44.448 ;
     RECT  0.192 44.448 0.353 44.472 ;
     RECT  0.156 44.472 0.353 44.544 ;
     RECT  0.192 44.544 0.353 44.568 ;
     RECT  0.156 44.568 0.353 44.64 ;
     RECT  0.192 44.64 0.353 44.664 ;
     RECT  0.156 44.664 0.353 44.784 ;
     RECT  0.192 44.784 0.353 44.808 ;
     RECT  0.156 44.808 0.353 44.88 ;
     RECT  0.192 44.88 0.353 44.904 ;
     RECT  0.156 44.904 0.353 44.976 ;
     RECT  0.192 44.976 0.353 45 ;
     RECT  0.156 45 0.353 45.072 ;
     RECT  0.192 45.072 0.353 45.096 ;
     RECT  0.156 45.096 0.353 45.168 ;
     RECT  0.192 45.168 0.353 45.192 ;
     RECT  0.156 45.192 0.353 45.264 ;
     RECT  0.192 45.264 0.353 45.288 ;
     RECT  0.156 45.288 0.353 45.408 ;
     RECT  0.192 45.408 0.353 45.432 ;
     RECT  0.156 45.432 0.353 45.504 ;
     RECT  0.192 45.504 0.353 45.528 ;
     RECT  0.156 45.528 0.353 45.6 ;
     RECT  0.192 45.6 0.353 45.624 ;
     RECT  0.156 45.624 0.353 45.696 ;
     RECT  0.192 45.696 0.353 45.72 ;
     RECT  0.156 45.72 0.353 45.792 ;
     RECT  0.192 45.792 0.353 45.816 ;
     RECT  0.156 45.816 0.353 45.936 ;
     RECT  0.192 45.936 0.353 45.96 ;
     RECT  0.156 45.96 0.353 46.032 ;
     RECT  0.192 46.032 0.353 46.056 ;
     RECT  0.156 46.056 0.353 46.128 ;
     RECT  0.192 46.128 0.353 46.152 ;
     RECT  0.156 46.152 0.353 46.224 ;
     RECT  0.192 46.224 0.353 46.248 ;
     RECT  0.156 46.248 0.353 46.32 ;
     RECT  0.192 46.32 0.353 46.344 ;
     RECT  0.156 46.344 0.353 46.416 ;
     RECT  0.192 46.416 0.353 46.44 ;
     RECT  0.156 46.44 0.353 46.56 ;
     RECT  0.192 46.56 0.353 46.584 ;
     RECT  0.156 46.584 0.353 46.656 ;
     RECT  0.192 46.656 0.353 46.68 ;
     RECT  0.156 46.68 0.353 46.752 ;
     RECT  0.192 46.752 0.353 46.776 ;
     RECT  0.156 46.776 0.353 46.848 ;
     RECT  0.192 46.848 0.353 46.872 ;
     RECT  0.156 46.872 0.353 46.944 ;
     RECT  0.192 46.944 0.353 46.968 ;
     RECT  0.156 46.968 0.353 47.04 ;
     RECT  0.192 47.04 0.353 47.064 ;
     RECT  0.156 47.064 0.353 47.184 ;
     RECT  0.192 47.184 0.353 47.208 ;
     RECT  0.156 47.208 0.353 47.28 ;
     RECT  0.192 47.28 0.353 47.304 ;
     RECT  0.156 47.304 0.353 47.376 ;
     RECT  0.192 47.376 0.353 47.4 ;
     RECT  0.156 47.4 0.353 47.472 ;
     RECT  0.192 47.472 0.353 47.496 ;
     RECT  0.156 47.496 0.353 47.568 ;
     RECT  0.192 47.568 0.353 47.592 ;
     RECT  0.156 47.592 0.353 47.712 ;
     RECT  0.192 47.712 0.353 47.736 ;
     RECT  0.156 47.736 0.353 47.808 ;
     RECT  0.192 47.808 0.353 47.832 ;
     RECT  0.156 47.832 0.353 47.904 ;
     RECT  0.192 47.904 0.353 47.928 ;
     RECT  0.156 47.928 0.353 48 ;
     RECT  0.192 48 0.353 48.024 ;
     RECT  0.156 48.024 0.353 48.096 ;
     RECT  0.192 48.096 0.353 48.12 ;
     RECT  0.156 48.12 0.353 48.192 ;
     RECT  0.192 48.192 0.353 48.216 ;
     RECT  0.156 48.216 0.353 48.336 ;
     RECT  0.192 48.336 0.353 48.36 ;
     RECT  0.156 48.36 0.353 48.432 ;
     RECT  0.192 48.432 0.353 48.456 ;
     RECT  0.156 48.456 0.353 48.528 ;
     RECT  0.192 48.528 0.353 48.552 ;
     RECT  0.156 48.552 0.353 48.624 ;
     RECT  0.192 48.624 0.353 48.648 ;
     RECT  0.156 48.648 0.353 48.72 ;
     RECT  0.192 48.72 0.353 48.744 ;
     RECT  0.156 48.744 0.353 48.816 ;
     RECT  0.192 48.816 0.353 48.84 ;
     RECT  0.156 48.84 0.353 48.96 ;
     RECT  0.192 48.96 0.353 48.984 ;
     RECT  0.156 48.984 0.353 49.056 ;
     RECT  0.192 49.056 0.353 49.08 ;
     RECT  0.156 49.08 0.353 49.152 ;
     RECT  0.192 49.152 0.353 49.176 ;
     RECT  0.156 49.176 0.353 49.248 ;
     RECT  0.192 49.248 0.353 49.272 ;
     RECT  0.156 49.272 0.353 49.344 ;
     RECT  0.192 49.344 0.353 49.368 ;
     RECT  0.156 49.368 0.353 49.488 ;
     RECT  0.192 49.488 0.353 49.512 ;
     RECT  0.156 49.512 0.353 49.584 ;
     RECT  0.192 49.584 0.353 49.608 ;
     RECT  0.156 49.608 0.353 49.68 ;
     RECT  0.192 49.68 0.353 49.704 ;
     RECT  0.156 49.704 0.353 49.776 ;
     RECT  0.192 49.776 0.353 49.8 ;
     RECT  0.156 49.8 0.353 49.872 ;
     RECT  0.192 49.872 0.353 49.896 ;
     RECT  0.156 49.896 0.353 49.968 ;
     RECT  0.192 49.968 0.353 49.992 ;
     RECT  0.156 49.992 0.353 50.112 ;
     RECT  0.192 50.112 0.353 50.136 ;
     RECT  0.156 50.136 0.353 50.208 ;
     RECT  0.192 50.208 0.353 50.232 ;
     RECT  0.156 50.232 0.353 50.304 ;
     RECT  0.192 50.304 0.353 50.328 ;
     RECT  0.156 50.328 0.353 50.4 ;
     RECT  0.192 50.4 0.353 50.424 ;
     RECT  0.156 50.424 0.353 50.496 ;
     RECT  0.192 50.496 0.353 50.52 ;
     RECT  0.156 50.52 0.353 50.592 ;
     RECT  0.192 50.592 0.353 50.616 ;
     RECT  0.156 50.616 0.353 50.736 ;
     RECT  0.192 50.736 0.353 50.76 ;
     RECT  0.156 50.76 0.353 50.832 ;
     RECT  0.192 50.832 0.353 50.856 ;
     RECT  0.156 50.856 0.353 50.928 ;
     RECT  0.192 50.928 0.353 50.952 ;
     RECT  0.156 50.952 0.353 51.024 ;
     RECT  0.192 51.024 0.353 51.048 ;
     RECT  0.156 51.048 0.353 51.12 ;
     RECT  0.192 51.12 0.353 51.144 ;
     RECT  0.156 51.144 0.353 51.264 ;
     RECT  0.192 51.264 0.353 51.288 ;
     RECT  0.156 51.288 0.353 51.36 ;
     RECT  0.192 51.36 0.353 51.384 ;
     RECT  0.156 51.384 0.353 51.456 ;
     RECT  0.192 51.456 0.353 51.48 ;
     RECT  0.156 51.48 0.353 51.552 ;
     RECT  0.192 51.552 0.353 51.576 ;
     RECT  0.156 51.576 0.353 51.648 ;
     RECT  0.192 51.648 0.353 51.672 ;
     RECT  0.156 51.672 0.353 51.744 ;
     RECT  0.192 51.744 0.353 51.768 ;
     RECT  0.156 51.768 0.353 51.888 ;
     RECT  0.192 51.888 0.353 51.912 ;
     RECT  0.156 51.912 0.353 51.984 ;
     RECT  0.192 51.984 0.353 52.008 ;
     RECT  0.156 52.008 0.353 52.08 ;
     RECT  0.192 52.08 0.353 52.104 ;
     RECT  0.156 52.104 0.353 52.176 ;
     RECT  0.192 52.176 0.353 52.2 ;
     RECT  0.156 52.2 0.353 52.272 ;
     RECT  0.192 52.272 0.353 52.296 ;
     RECT  0.156 52.296 0.353 52.416 ;
     RECT  0.192 52.416 0.353 52.44 ;
     RECT  0.156 52.44 0.353 52.512 ;
     RECT  0.192 52.512 0.353 52.536 ;
     RECT  0.156 52.536 0.353 52.608 ;
     RECT  0.192 52.608 0.353 52.632 ;
     RECT  0.156 52.632 0.353 52.704 ;
     RECT  0.192 52.704 0.353 52.728 ;
     RECT  0.156 52.728 0.353 52.8 ;
     RECT  0.192 52.8 0.353 52.824 ;
     RECT  0.156 52.824 0.353 52.896 ;
     RECT  0.192 52.896 0.353 52.92 ;
     RECT  0.156 52.92 0.353 53.04 ;
     RECT  0.192 53.04 0.353 53.064 ;
     RECT  0.156 53.064 0.353 53.136 ;
     RECT  0.192 53.136 0.353 53.16 ;
     RECT  0.156 53.16 0.353 53.232 ;
     RECT  0.192 53.232 0.353 53.256 ;
     RECT  0.156 53.256 0.353 53.328 ;
     RECT  0.192 53.328 0.353 53.352 ;
     RECT  0.156 53.352 0.353 53.424 ;
     RECT  0.192 53.424 0.353 53.448 ;
     RECT  0.156 53.448 0.353 53.52 ;
     RECT  0.192 53.52 0.353 53.544 ;
     RECT  0.156 53.544 0.353 53.664 ;
     RECT  0.192 53.664 0.353 53.688 ;
     RECT  0.156 53.688 0.353 53.76 ;
     RECT  0.192 53.76 0.353 53.784 ;
     RECT  0.156 53.784 0.353 53.856 ;
     RECT  0.192 53.856 0.353 53.88 ;
     RECT  0.156 53.88 0.353 53.952 ;
     RECT  0.192 53.952 0.353 53.976 ;
     RECT  0.156 53.976 0.353 54.048 ;
     RECT  0.192 54.048 0.353 54.072 ;
     RECT  0.156 54.072 0.353 54.192 ;
     RECT  0.192 54.192 0.353 54.216 ;
     RECT  0.156 54.216 0.353 54.288 ;
     RECT  0.192 54.288 0.353 54.312 ;
     RECT  0.156 54.312 0.353 54.384 ;
     RECT  0.192 54.384 0.353 54.408 ;
     RECT  0.156 54.408 0.353 54.48 ;
     RECT  0.192 54.48 0.353 54.504 ;
     RECT  0.156 54.504 0.353 54.576 ;
     RECT  0.192 54.576 0.353 54.6 ;
     RECT  0.156 54.6 0.353 54.672 ;
     RECT  0.192 54.672 0.353 54.696 ;
     RECT  0.156 54.696 0.353 54.816 ;
     RECT  0.192 54.816 0.353 54.84 ;
     RECT  0.156 54.84 0.353 54.912 ;
     RECT  0.192 54.912 0.353 54.936 ;
     RECT  0.156 54.936 0.353 55.008 ;
     RECT  0.192 55.008 0.353 55.032 ;
     RECT  0.156 55.032 0.353 55.104 ;
     RECT  0.192 55.104 0.353 55.128 ;
     RECT  0.156 55.128 0.353 55.2 ;
     RECT  0.192 55.2 0.353 55.224 ;
     RECT  0.156 55.224 0.353 55.296 ;
     RECT  0.192 55.296 0.353 55.32 ;
     RECT  0.156 55.32 0.353 55.44 ;
     RECT  0.192 55.44 0.353 55.464 ;
     RECT  0.156 55.464 0.353 55.536 ;
     RECT  0.192 55.536 0.353 55.56 ;
     RECT  0.156 55.56 0.353 55.632 ;
     RECT  0.192 55.632 0.353 55.656 ;
     RECT  0.156 55.656 0.353 55.728 ;
     RECT  0.192 55.728 0.353 55.752 ;
     RECT  0.156 55.752 0.353 55.824 ;
     RECT  0.192 55.824 0.353 55.848 ;
     RECT  0.156 55.848 0.353 55.968 ;
     RECT  0.192 55.968 0.353 55.992 ;
     RECT  0.156 55.992 0.353 56.064 ;
     RECT  0.192 56.064 0.353 56.088 ;
     RECT  0.156 56.088 0.353 56.16 ;
     RECT  0.192 56.16 0.353 56.184 ;
     RECT  0.156 56.184 0.353 56.256 ;
     RECT  0.192 56.256 0.353 56.28 ;
     RECT  0.156 56.28 0.353 56.352 ;
     RECT  0.192 56.352 0.353 56.376 ;
     RECT  0.156 56.376 0.353 56.448 ;
     RECT  0.192 56.448 0.353 56.472 ;
     RECT  0.156 56.472 0.353 56.592 ;
     RECT  0.192 56.592 0.353 56.616 ;
     RECT  0.156 56.616 0.353 56.688 ;
     RECT  0.192 56.688 0.353 56.712 ;
     RECT  0.156 56.712 0.353 56.784 ;
     RECT  0.192 56.784 0.353 56.808 ;
     RECT  0.156 56.808 0.353 56.88 ;
     RECT  0.192 56.88 0.353 56.904 ;
     RECT  0.156 56.904 0.353 56.976 ;
     RECT  0.192 56.976 0.353 57 ;
     RECT  0.156 57 0.353 57.072 ;
     RECT  0.192 57.072 0.353 57.096 ;
     RECT  0.156 57.096 0.353 57.216 ;
     RECT  0.192 57.216 0.353 57.24 ;
     RECT  0.156 57.24 0.353 57.312 ;
     RECT  0.192 57.312 0.353 57.336 ;
     RECT  0.156 57.336 0.353 57.408 ;
     RECT  0.192 57.408 0.353 57.432 ;
     RECT  0.156 57.432 0.353 57.504 ;
     RECT  0.192 57.504 0.353 57.528 ;
     RECT  0.156 57.528 0.353 57.6 ;
     RECT  0.192 57.6 0.353 57.624 ;
     RECT  0.156 57.624 0.353 57.744 ;
     RECT  0.192 57.744 0.353 57.768 ;
     RECT  0.156 57.768 0.353 57.84 ;
     RECT  0.192 57.84 0.353 57.864 ;
     RECT  0.156 57.864 0.353 57.936 ;
     RECT  0.192 57.936 0.353 57.96 ;
     RECT  0.156 57.96 0.353 58.032 ;
     RECT  0.192 58.032 0.353 58.056 ;
     RECT  0.156 58.056 0.353 58.128 ;
     RECT  0.192 58.128 0.353 58.152 ;
     RECT  0.156 58.152 0.353 58.224 ;
     RECT  0.192 58.224 0.353 58.248 ;
     RECT  0.156 58.248 0.353 58.368 ;
     RECT  0.192 58.368 0.353 58.392 ;
     RECT  0.156 58.392 0.353 58.464 ;
     RECT  0.192 58.464 0.353 58.488 ;
     RECT  0.156 58.488 0.353 58.56 ;
     RECT  0.192 58.56 0.353 58.584 ;
     RECT  0.156 58.584 0.353 58.656 ;
     RECT  0.192 58.656 0.353 58.68 ;
     RECT  0.156 58.68 0.353 58.752 ;
     RECT  0.192 58.752 0.353 58.776 ;
     RECT  0.156 58.776 0.353 58.896 ;
     RECT  0.192 58.896 0.353 58.92 ;
     RECT  0.156 58.92 0.353 58.992 ;
     RECT  0.192 58.992 0.353 59.016 ;
     RECT  0.156 59.016 0.353 59.088 ;
     RECT  0.192 59.088 0.353 59.112 ;
     RECT  0.156 59.112 0.353 59.184 ;
     RECT  0.192 59.184 0.353 59.208 ;
     RECT  0.156 59.208 0.353 59.28 ;
     RECT  0.192 59.28 0.353 59.304 ;
     RECT  0.156 59.304 0.353 59.376 ;
     RECT  0.192 59.376 0.353 59.4 ;
     RECT  0.156 59.4 0.353 59.52 ;
     RECT  0.192 59.52 0.353 59.544 ;
     RECT  0.156 59.544 0.353 59.616 ;
     RECT  0.192 59.616 0.353 59.64 ;
     RECT  0.156 59.64 0.353 59.712 ;
     RECT  0.192 59.712 0.353 59.736 ;
     RECT  0.156 59.736 0.353 59.808 ;
     RECT  0.192 59.808 0.353 59.832 ;
     RECT  0.156 59.832 0.353 59.904 ;
     RECT  0.192 59.904 0.353 59.928 ;
     RECT  0.156 59.928 0.353 60 ;
     RECT  0.192 60 0.353 60.024 ;
     RECT  0.156 60.024 0.353 60.144 ;
     RECT  0.192 60.144 0.353 60.168 ;
     RECT  0.156 60.168 0.353 60.24 ;
     RECT  0.192 60.24 0.353 60.264 ;
     RECT  0.156 60.264 0.353 60.336 ;
     RECT  0.192 60.336 0.353 60.36 ;
     RECT  0.156 60.36 0.353 60.432 ;
     RECT  0.192 60.432 0.353 60.456 ;
     RECT  0.156 60.456 0.353 60.528 ;
     RECT  0.192 60.528 0.353 60.552 ;
     RECT  0.156 60.552 0.353 60.672 ;
     RECT  0.192 60.672 0.353 60.696 ;
     RECT  0.156 60.696 0.353 60.768 ;
     RECT  0.192 60.768 0.353 60.792 ;
     RECT  0.156 60.792 0.353 60.864 ;
     RECT  0.192 60.864 0.353 60.888 ;
     RECT  0.156 60.888 0.353 60.96 ;
     RECT  0.192 60.96 0.353 60.984 ;
     RECT  0.156 60.984 0.353 61.056 ;
     RECT  0.192 61.056 0.353 61.08 ;
     RECT  0.156 61.08 0.353 61.152 ;
     RECT  0.192 61.152 0.353 61.176 ;
     RECT  0.156 61.176 0.353 61.296 ;
     RECT  0.192 61.296 0.353 61.32 ;
     RECT  0.156 61.32 0.353 61.392 ;
     RECT  0.192 61.392 0.353 61.416 ;
     RECT  0.156 61.416 0.353 61.488 ;
     RECT  0.192 61.488 0.353 61.512 ;
     RECT  0.156 61.512 0.353 61.584 ;
     RECT  0.192 61.584 0.353 61.608 ;
     RECT  0.156 61.608 0.353 61.68 ;
     RECT  0.192 61.68 0.353 61.704 ;
     RECT  0.156 61.704 0.353 61.776 ;
     RECT  0.192 61.776 0.353 61.8 ;
     RECT  0.156 61.8 0.353 61.92 ;
     RECT  0.192 61.92 0.353 61.944 ;
     RECT  0.156 61.944 0.353 62.016 ;
     RECT  0.192 62.016 0.353 62.04 ;
     RECT  0.156 62.04 0.353 62.112 ;
     RECT  0.192 62.112 0.353 62.136 ;
     RECT  0.156 62.136 0.353 62.208 ;
     RECT  0.192 62.208 0.353 62.232 ;
     RECT  0.156 62.232 0.353 62.304 ;
     RECT  0.192 62.304 0.353 62.328 ;
     RECT  0.156 62.328 0.353 62.448 ;
     RECT  0.192 62.448 0.353 62.472 ;
     RECT  0.156 62.472 0.353 62.544 ;
     RECT  0.192 62.544 0.353 62.568 ;
     RECT  0.156 62.568 0.353 62.64 ;
     RECT  0.192 62.64 0.353 62.664 ;
     RECT  0.156 62.664 0.353 62.736 ;
     RECT  0.192 62.736 0.353 62.76 ;
     RECT  0.156 62.76 0.353 62.832 ;
     RECT  0.192 62.832 0.353 62.856 ;
     RECT  0.156 62.856 0.353 62.928 ;
     RECT  0.192 62.928 0.353 62.952 ;
     RECT  0.156 62.952 0.353 63.072 ;
     RECT  0.192 63.072 0.353 63.096 ;
     RECT  0.156 63.096 0.353 63.168 ;
     RECT  0.192 63.168 0.353 63.192 ;
     RECT  0.156 63.192 0.353 63.264 ;
     RECT  0.192 63.264 0.353 63.288 ;
     RECT  0.156 63.288 0.353 63.36 ;
     RECT  0.192 63.36 0.353 63.384 ;
     RECT  0.156 63.384 0.353 63.456 ;
     RECT  0.192 63.456 0.353 63.48 ;
     RECT  0.156 63.48 0.353 63.552 ;
     RECT  0.192 63.552 0.353 63.576 ;
     RECT  0.156 63.576 0.353 63.696 ;
     RECT  0.192 63.696 0.353 63.72 ;
     RECT  0.156 63.72 0.353 63.792 ;
     RECT  0.192 63.792 0.353 63.816 ;
     RECT  0.156 63.816 0.353 63.888 ;
     RECT  0.192 63.888 0.353 63.912 ;
     RECT  0.156 63.912 0.353 63.984 ;
     RECT  0.192 63.984 0.353 64.008 ;
     RECT  0.156 64.008 0.353 64.08 ;
     RECT  0.192 64.08 0.353 64.104 ;
     RECT  0.156 64.104 0.353 64.224 ;
     RECT  0.192 64.224 0.353 64.248 ;
     RECT  0.156 64.248 0.353 64.32 ;
     RECT  0.192 64.32 0.353 64.344 ;
     RECT  0.156 64.344 0.353 64.416 ;
     RECT  0.192 64.416 0.353 64.44 ;
     RECT  0.156 64.44 0.353 64.512 ;
     RECT  0.192 64.512 0.353 64.536 ;
     RECT  0.156 64.536 0.353 64.608 ;
     RECT  0.192 64.608 0.353 64.632 ;
     RECT  0.156 64.632 0.353 64.704 ;
     RECT  0.192 64.704 0.353 64.728 ;
     RECT  0.156 64.728 0.353 64.848 ;
     RECT  0.192 64.848 0.353 64.872 ;
     RECT  0.156 64.872 0.353 64.944 ;
     RECT  0.192 64.944 0.353 64.968 ;
     RECT  0.156 64.968 0.353 65.04 ;
     RECT  0.192 65.04 0.353 65.064 ;
     RECT  0.156 65.064 0.353 65.136 ;
     RECT  0.192 65.136 0.353 65.16 ;
     RECT  0.156 65.16 0.353 65.232 ;
     RECT  0.192 65.232 0.353 65.256 ;
     RECT  0.156 65.256 0.353 65.328 ;
     RECT  0.192 65.328 0.353 65.352 ;
     RECT  0.156 65.352 0.353 65.472 ;
     RECT  0.192 65.472 0.353 65.496 ;
     RECT  0.156 65.496 0.353 65.568 ;
     RECT  0.192 65.568 0.353 65.592 ;
     RECT  0.156 65.592 0.353 65.664 ;
     RECT  0.192 65.664 0.353 65.688 ;
     RECT  0.156 65.688 0.353 65.76 ;
     RECT  0.192 65.76 0.353 65.784 ;
     RECT  0.156 65.784 0.353 65.856 ;
     RECT  0.192 65.856 0.353 65.88 ;
     RECT  0.156 65.88 0.353 66 ;
     RECT  0.192 66 0.353 66.024 ;
     RECT  0.156 66.024 0.353 66.096 ;
     RECT  0.192 66.096 0.353 66.12 ;
     RECT  0.156 66.12 0.353 66.192 ;
     RECT  0.192 66.192 0.353 66.216 ;
     RECT  0.156 66.216 0.353 66.288 ;
     RECT  0.192 66.288 0.353 66.312 ;
     RECT  0.156 66.312 0.353 66.384 ;
     RECT  0.192 66.384 0.353 66.408 ;
     RECT  0.156 66.408 0.353 66.48 ;
     RECT  0.192 66.48 0.353 66.504 ;
     RECT  0.156 66.504 0.353 66.624 ;
     RECT  0.192 66.624 0.353 66.648 ;
     RECT  0.156 66.648 0.353 66.72 ;
     RECT  0.192 66.72 0.353 66.744 ;
     RECT  0.156 66.744 0.353 66.816 ;
     RECT  0.192 66.816 0.353 66.84 ;
     RECT  0.156 66.84 0.353 66.912 ;
     RECT  0.192 66.912 0.353 66.936 ;
     RECT  0.156 66.936 0.353 67.008 ;
     RECT  0.192 67.008 0.353 67.032 ;
     RECT  0.156 67.032 0.353 67.152 ;
     RECT  0.192 67.152 0.353 67.176 ;
     RECT  0.156 67.176 0.353 67.248 ;
     RECT  0.192 67.248 0.353 67.272 ;
     RECT  0.156 67.272 0.353 67.344 ;
     RECT  0.192 67.344 0.353 67.368 ;
     RECT  0.156 67.368 0.353 67.44 ;
     RECT  0.192 67.44 0.353 67.464 ;
     RECT  0.156 67.464 0.353 67.536 ;
     RECT  0.192 67.536 0.353 67.56 ;
     RECT  0.156 67.56 0.353 67.632 ;
     RECT  0.192 67.632 0.353 67.656 ;
     RECT  0.156 67.656 0.353 67.776 ;
     RECT  0.192 67.776 0.353 67.8 ;
     RECT  0.156 67.8 0.353 67.872 ;
     RECT  0.192 67.872 0.353 67.896 ;
     RECT  0.156 67.896 0.353 67.968 ;
     RECT  0.192 67.968 0.353 67.992 ;
     RECT  0.156 67.992 0.353 68.064 ;
     RECT  0.192 68.064 0.353 68.088 ;
     RECT  0.156 68.088 0.353 68.16 ;
     RECT  0.192 68.16 0.353 68.184 ;
     RECT  0.156 68.184 0.353 68.256 ;
     RECT  0.192 68.256 0.353 68.28 ;
     RECT  0.156 68.28 0.353 68.4 ;
     RECT  0.192 68.4 0.353 68.424 ;
     RECT  0.156 68.424 0.353 68.496 ;
     RECT  0.192 68.496 0.353 68.52 ;
     RECT  0.156 68.52 0.353 68.592 ;
     RECT  0.192 68.592 0.353 68.616 ;
     RECT  0.156 68.616 0.353 68.688 ;
     RECT  0.192 68.688 0.353 68.712 ;
     RECT  0.156 68.712 0.353 68.784 ;
     RECT  0.192 68.784 0.353 68.808 ;
     RECT  0.156 68.808 0.353 68.928 ;
     RECT  0.192 68.928 0.353 68.952 ;
     RECT  0.156 68.952 0.353 69.024 ;
     RECT  0.192 69.024 0.353 69.048 ;
     RECT  0.156 69.048 0.353 69.12 ;
     RECT  0.192 69.12 0.353 69.144 ;
     RECT  0.156 69.144 0.353 69.216 ;
     RECT  0.192 69.216 0.353 69.24 ;
     RECT  0.156 69.24 0.353 69.312 ;
     RECT  0.192 69.312 0.353 69.336 ;
     RECT  0.156 69.336 0.353 69.408 ;
     RECT  0.192 69.408 0.353 69.432 ;
     RECT  0.156 69.432 0.353 69.552 ;
     RECT  0.192 69.552 0.353 69.576 ;
     RECT  0.156 69.576 0.353 69.648 ;
     RECT  0.192 69.648 0.353 69.672 ;
     RECT  0.156 69.672 0.353 69.744 ;
     RECT  0.192 69.744 0.353 69.768 ;
     RECT  0.156 69.768 0.353 69.84 ;
     RECT  0.192 69.84 0.353 69.864 ;
     RECT  0.156 69.864 0.353 69.936 ;
     RECT  0.192 69.936 0.353 69.96 ;
     RECT  0.156 69.96 0.353 70.032 ;
     RECT  0.192 70.032 0.353 70.056 ;
     RECT  0.156 70.056 0.353 70.176 ;
     RECT  0.192 70.176 0.353 70.2 ;
     RECT  0.156 70.2 0.353 70.272 ;
     RECT  0.192 70.272 0.353 70.296 ;
     RECT  0.156 70.296 0.353 70.368 ;
     RECT  0.192 70.368 0.353 70.392 ;
     RECT  0.156 70.392 0.353 70.464 ;
     RECT  0.192 70.464 0.353 70.488 ;
     RECT  0.156 70.488 0.353 70.56 ;
     RECT  0.192 70.56 0.353 70.584 ;
     RECT  0.156 70.584 0.353 70.704 ;
     RECT  0.192 70.704 0.353 70.728 ;
     RECT  0.156 70.728 0.353 70.8 ;
     RECT  0.192 70.8 0.353 70.824 ;
     RECT  0.156 70.824 0.353 70.896 ;
     RECT  0.192 70.896 0.353 70.92 ;
     RECT  0.156 70.92 0.353 70.992 ;
     RECT  0.192 70.992 0.353 71.016 ;
     RECT  0.156 71.016 0.353 71.088 ;
     RECT  0.192 71.088 0.353 71.112 ;
     RECT  0.156 71.112 0.353 71.184 ;
     RECT  0.192 71.184 0.353 71.208 ;
     RECT  0.156 71.208 0.353 71.328 ;
     RECT  0.192 71.328 0.353 71.352 ;
     RECT  0.156 71.352 0.353 71.424 ;
     RECT  0.192 71.424 0.353 71.448 ;
     RECT  0.156 71.448 0.353 71.52 ;
     RECT  0.192 71.52 0.353 71.544 ;
     RECT  0.156 71.544 0.353 71.616 ;
     RECT  0.192 71.616 0.353 71.64 ;
     RECT  0.156 71.64 0.353 71.712 ;
     RECT  0.192 71.712 0.353 71.736 ;
     RECT  0.156 71.736 0.353 71.856 ;
     RECT  0.192 71.856 0.353 71.88 ;
     RECT  0.156 71.88 0.353 71.952 ;
     RECT  0.192 71.952 0.353 71.976 ;
     RECT  0.156 71.976 0.353 72.048 ;
     RECT  0.192 72.048 0.353 72.072 ;
     RECT  0.156 72.072 0.353 72.144 ;
     RECT  0.192 72.144 0.353 72.168 ;
     RECT  0.156 72.168 0.353 72.24 ;
     RECT  0.192 72.24 0.353 72.264 ;
     RECT  0.156 72.264 0.353 72.336 ;
     RECT  0.192 72.336 0.353 72.36 ;
     RECT  0.156 72.36 0.353 72.48 ;
     RECT  0.192 72.48 0.353 72.504 ;
     RECT  0.156 72.504 0.353 72.576 ;
     RECT  0.192 72.576 0.353 72.6 ;
     RECT  0.156 72.6 0.353 72.672 ;
     RECT  0.192 72.672 0.353 72.696 ;
     RECT  0.156 72.696 0.353 72.768 ;
     RECT  0.192 72.768 0.353 72.792 ;
     RECT  0.156 72.792 0.353 72.864 ;
     RECT  0.192 72.864 0.353 72.888 ;
     RECT  0.156 72.888 0.353 72.96 ;
     RECT  0.192 72.96 0.353 72.984 ;
     RECT  0.156 72.984 0.353 73.104 ;
     RECT  0.192 73.104 0.353 73.128 ;
     RECT  0.156 73.128 0.353 73.2 ;
     RECT  0.192 73.2 0.353 73.224 ;
     RECT  0.156 73.224 0.353 73.296 ;
     RECT  0.192 73.296 0.353 73.32 ;
     RECT  0.156 73.32 0.353 73.392 ;
     RECT  0.192 73.392 0.353 73.416 ;
     RECT  0.353 2.208 2.408 73.32 ;
     RECT  2.408 2.148 2.512 73.452 ;
     RECT  2.512 2.352 2.585 73.272 ;
     RECT  2.585 2.418 2.704 73.272 ;
     RECT  2.704 2.448 2.981 73.272 ;
     RECT  2.981 2.496 5.108 73.272 ;
     RECT  5.108 2.148 5.212 73.452 ;
     RECT  5.212 2.418 5.404 73.272 ;
     RECT  5.404 2.496 5.573 73.272 ;
     RECT  5.389 74.688 5.603 74.712 ;
     RECT  5.573 2.496 6.829 73.128 ;
     RECT  6.829 2.496 7.117 73.272 ;
     RECT  7.117 2.496 7.765 73.32 ;
     RECT  7.765 2.496 7.808 73.368 ;
     RECT  7.808 2.148 7.912 73.452 ;
     RECT  7.912 2.418 8.104 73.368 ;
     RECT  8.104 2.448 8.885 73.368 ;
     RECT  8.885 2.448 10.508 73.32 ;
     RECT  10.508 2.148 10.612 73.452 ;
     RECT  10.612 2.418 10.804 73.272 ;
     RECT  10.804 2.736 10.937 73.272 ;
     RECT  10.937 2.736 11.009 38.76 ;
     RECT  10.937 40.368 11.261 73.272 ;
     RECT  11.261 43.344 11.405 73.272 ;
     RECT  11.009 2.736 11.441 37.416 ;
     RECT  11.405 43.344 11.441 69.24 ;
     RECT  11.441 22.848 11.873 37.416 ;
     RECT  11.873 28.464 12.017 37.416 ;
     RECT  12.017 34.704 12.949 37.416 ;
     RECT  11.009 38.448 12.949 38.76 ;
     RECT  11.441 2.736 13.208 21.816 ;
     RECT  11.873 22.848 13.208 27.432 ;
     RECT  12.017 28.464 13.208 33.576 ;
     RECT  12.949 34.704 13.208 38.76 ;
     RECT  11.261 40.368 13.208 42.216 ;
     RECT  11.441 43.344 13.208 50.28 ;
     RECT  11.441 51.408 13.208 69.24 ;
     RECT  11.405 70.8 13.208 73.272 ;
     RECT  13.208 2.148 13.312 73.452 ;
     RECT  13.312 2.418 13.504 73.272 ;
     RECT  13.504 20.976 13.565 21.192 ;
     RECT  13.504 28.464 13.565 33.576 ;
     RECT  13.504 43.824 13.565 47.304 ;
     RECT  13.504 6.288 13.601 9.048 ;
     RECT  13.504 13.632 13.637 16.392 ;
     RECT  13.565 28.464 13.709 32.472 ;
     RECT  13.504 51.696 13.709 51.72 ;
     RECT  13.504 70.8 13.709 71.16 ;
     RECT  13.504 35.712 13.781 36.36 ;
     RECT  13.504 37.392 13.781 38.04 ;
     RECT  13.504 3.024 13.817 5.304 ;
     RECT  13.709 28.464 13.817 30.6 ;
     RECT  13.565 44.064 13.817 47.304 ;
     RECT  13.781 37.584 13.853 38.04 ;
     RECT  13.504 57.84 13.997 57.864 ;
     RECT  13.504 61.632 13.997 61.656 ;
     RECT  13.817 3.6 14.033 5.304 ;
     RECT  13.504 24.144 14.033 25.8 ;
     RECT  13.601 7.536 14.249 9.048 ;
     RECT  13.504 62.64 14.249 65.688 ;
     RECT  14.033 3.6 14.357 4.44 ;
     RECT  13.504 72.192 14.533 72.216 ;
     RECT  13.504 73.2 14.533 73.272 ;
     RECT  13.504 55.68 14.605 56.616 ;
     RECT  13.504 11.232 14.641 11.976 ;
     RECT  13.709 31.632 14.641 32.472 ;
     RECT  13.565 33.552 14.641 33.576 ;
     RECT  13.637 15.216 14.677 16.392 ;
     RECT  14.641 17.472 14.677 17.496 ;
     RECT  13.504 48.336 14.677 48.792 ;
     RECT  13.817 46.272 14.681 47.304 ;
     RECT  13.601 6.288 14.785 6.312 ;
     RECT  14.357 3.6 14.821 3.816 ;
     RECT  14.785 5.76 14.821 6.312 ;
     RECT  14.249 8.688 14.821 9.048 ;
     RECT  14.641 10.32 14.821 11.976 ;
     RECT  13.637 13.632 14.821 13.656 ;
     RECT  14.677 15.216 14.821 17.496 ;
     RECT  13.504 19.776 14.821 19.8 ;
     RECT  13.565 20.976 14.821 21 ;
     RECT  13.504 22.656 14.821 22.68 ;
     RECT  14.033 24.144 14.821 24.936 ;
     RECT  13.817 29.232 14.821 30.6 ;
     RECT  14.641 31.632 14.821 33.576 ;
     RECT  13.504 34.704 14.821 34.728 ;
     RECT  13.781 36.336 14.821 36.36 ;
     RECT  13.853 37.92 14.821 38.04 ;
     RECT  13.504 39.744 14.821 40.392 ;
     RECT  13.504 41.712 14.821 41.736 ;
     RECT  13.817 44.064 14.821 44.904 ;
     RECT  14.681 46.272 14.821 46.584 ;
     RECT  14.677 48.336 14.821 49.416 ;
     RECT  13.504 53.568 14.821 54.456 ;
     RECT  14.605 55.68 14.821 57.432 ;
     RECT  13.504 59.184 14.821 59.208 ;
     RECT  14.249 62.64 14.821 63.816 ;
     RECT  14.249 64.944 14.821 65.688 ;
     RECT  13.504 66.72 14.821 66.744 ;
     RECT  13.504 67.776 14.821 68.376 ;
     RECT  13.709 70.8 14.821 70.824 ;
     RECT  14.533 72.192 14.821 73.272 ;
     RECT  14.821 18.912 14.857 21.336 ;
     RECT  14.821 22.368 14.857 24.936 ;
     RECT  14.821 27.888 14.857 46.584 ;
     RECT  14.821 64.944 14.857 70.824 ;
     RECT  14.821 2.352 15.397 3.816 ;
     RECT  14.821 5.76 15.397 7.272 ;
     RECT  14.821 8.688 15.397 17.88 ;
     RECT  14.857 18.912 15.397 24.936 ;
     RECT  14.857 26.544 15.397 46.584 ;
     RECT  14.821 47.712 15.397 51.384 ;
     RECT  14.821 53.136 15.397 57.432 ;
     RECT  14.821 58.464 15.397 61.32 ;
     RECT  14.821 62.352 15.397 63.816 ;
     RECT  14.857 64.944 15.397 71.016 ;
     RECT  14.821 72.048 15.397 73.416 ;
     RECT  15.397 2.352 15.937 46.584 ;
     RECT  15.397 47.712 15.937 73.416 ;
     RECT  15.937 2.352 15.973 73.416 ;
     RECT  15.973 2.208 17.088 2.232 ;
     RECT  15.973 2.232 17.1 2.352 ;
     RECT  15.973 2.352 17.088 2.376 ;
     RECT  15.973 2.376 17.1 2.448 ;
     RECT  15.973 2.448 17.088 2.472 ;
     RECT  15.973 2.472 17.1 2.544 ;
     RECT  15.973 2.544 17.088 2.568 ;
     RECT  15.973 2.568 17.1 2.64 ;
     RECT  15.973 2.64 17.088 2.664 ;
     RECT  15.973 2.664 17.1 2.736 ;
     RECT  15.973 2.736 17.088 2.76 ;
     RECT  15.973 2.76 17.1 2.832 ;
     RECT  15.973 2.832 17.088 2.856 ;
     RECT  15.973 2.856 17.1 2.976 ;
     RECT  15.973 2.976 17.088 3 ;
     RECT  15.973 3 17.1 3.072 ;
     RECT  15.973 3.072 17.088 3.096 ;
     RECT  15.973 3.096 17.1 3.168 ;
     RECT  15.973 3.168 17.088 3.192 ;
     RECT  15.973 3.192 17.1 3.264 ;
     RECT  15.973 3.264 17.088 3.288 ;
     RECT  15.973 3.288 17.1 3.36 ;
     RECT  15.973 3.36 17.088 3.384 ;
     RECT  15.973 3.384 17.1 3.456 ;
     RECT  15.973 3.456 17.088 3.48 ;
     RECT  15.973 3.48 17.1 3.6 ;
     RECT  15.973 3.6 17.088 3.624 ;
     RECT  15.973 3.624 17.1 3.696 ;
     RECT  15.973 3.696 17.088 3.72 ;
     RECT  15.973 3.72 17.1 3.792 ;
     RECT  15.973 3.792 17.088 3.816 ;
     RECT  15.973 3.816 17.1 3.888 ;
     RECT  15.973 3.888 17.088 3.912 ;
     RECT  15.973 3.912 17.1 3.984 ;
     RECT  15.973 3.984 17.088 4.008 ;
     RECT  15.973 4.008 17.1 4.08 ;
     RECT  15.973 4.08 17.088 4.104 ;
     RECT  15.973 4.104 17.1 4.224 ;
     RECT  15.973 4.224 17.088 4.248 ;
     RECT  15.973 4.248 17.1 4.32 ;
     RECT  15.973 4.32 17.088 4.344 ;
     RECT  15.973 4.344 17.1 4.416 ;
     RECT  15.973 4.416 17.088 4.44 ;
     RECT  15.973 4.44 17.1 4.512 ;
     RECT  15.973 4.512 17.088 4.536 ;
     RECT  15.973 4.536 17.1 4.608 ;
     RECT  15.973 4.608 17.088 4.632 ;
     RECT  15.973 4.632 17.1 4.752 ;
     RECT  15.973 4.752 17.088 4.776 ;
     RECT  15.973 4.776 17.1 4.848 ;
     RECT  15.973 4.848 17.088 4.872 ;
     RECT  15.973 4.872 17.1 4.944 ;
     RECT  15.973 4.944 17.088 4.968 ;
     RECT  15.973 4.968 17.1 5.04 ;
     RECT  15.973 5.04 17.088 5.064 ;
     RECT  15.973 5.064 17.1 5.136 ;
     RECT  15.973 5.136 17.088 5.16 ;
     RECT  15.973 5.16 17.1 5.232 ;
     RECT  15.973 5.232 17.088 5.256 ;
     RECT  15.973 5.256 17.1 5.376 ;
     RECT  15.973 5.376 17.088 5.4 ;
     RECT  15.973 5.4 17.1 5.472 ;
     RECT  15.973 5.472 17.088 5.496 ;
     RECT  15.973 5.496 17.1 5.568 ;
     RECT  15.973 5.568 17.088 5.592 ;
     RECT  15.973 5.592 17.1 5.664 ;
     RECT  15.973 5.664 17.088 5.688 ;
     RECT  15.973 5.688 17.1 5.76 ;
     RECT  15.973 5.76 17.088 5.784 ;
     RECT  15.973 5.784 17.1 5.856 ;
     RECT  15.973 5.856 17.088 5.88 ;
     RECT  15.973 5.88 17.1 6 ;
     RECT  15.973 6 17.088 6.024 ;
     RECT  15.973 6.024 17.1 6.096 ;
     RECT  15.973 6.096 17.088 6.12 ;
     RECT  15.973 6.12 17.1 6.192 ;
     RECT  15.973 6.192 17.088 6.216 ;
     RECT  15.973 6.216 17.1 6.288 ;
     RECT  15.973 6.288 17.088 6.312 ;
     RECT  15.973 6.312 17.1 6.384 ;
     RECT  15.973 6.384 17.088 6.408 ;
     RECT  15.973 6.408 17.1 6.48 ;
     RECT  15.973 6.48 17.088 6.504 ;
     RECT  15.973 6.504 17.1 6.624 ;
     RECT  15.973 6.624 17.088 6.648 ;
     RECT  15.973 6.648 17.1 6.72 ;
     RECT  15.973 6.72 17.088 6.744 ;
     RECT  15.973 6.744 17.1 6.816 ;
     RECT  15.973 6.816 17.088 6.84 ;
     RECT  15.973 6.84 17.1 6.912 ;
     RECT  15.973 6.912 17.088 6.936 ;
     RECT  15.973 6.936 17.1 7.008 ;
     RECT  15.973 7.008 17.088 7.032 ;
     RECT  15.973 7.032 17.1 7.152 ;
     RECT  15.973 7.152 17.088 7.176 ;
     RECT  15.973 7.176 17.1 7.248 ;
     RECT  15.973 7.248 17.088 7.272 ;
     RECT  15.973 7.272 17.1 7.344 ;
     RECT  15.973 7.344 17.088 7.368 ;
     RECT  15.973 7.368 17.1 7.44 ;
     RECT  15.973 7.44 17.088 7.464 ;
     RECT  15.973 7.464 17.1 7.536 ;
     RECT  15.973 7.536 17.088 7.56 ;
     RECT  15.973 7.56 17.1 7.632 ;
     RECT  15.973 7.632 17.088 7.656 ;
     RECT  15.973 7.656 17.1 7.776 ;
     RECT  15.973 7.776 17.088 7.8 ;
     RECT  15.973 7.8 17.1 7.872 ;
     RECT  15.973 7.872 17.088 7.896 ;
     RECT  15.973 7.896 17.1 7.968 ;
     RECT  15.973 7.968 17.088 7.992 ;
     RECT  15.973 7.992 17.1 8.064 ;
     RECT  15.973 8.064 17.088 8.088 ;
     RECT  15.973 8.088 17.1 8.16 ;
     RECT  15.973 8.16 17.088 8.184 ;
     RECT  15.973 8.184 17.1 8.256 ;
     RECT  15.973 8.256 17.088 8.28 ;
     RECT  15.973 8.28 17.1 8.4 ;
     RECT  15.973 8.4 17.088 8.424 ;
     RECT  15.973 8.424 17.1 8.496 ;
     RECT  15.973 8.496 17.088 8.52 ;
     RECT  15.973 8.52 17.1 8.592 ;
     RECT  15.973 8.592 17.088 8.616 ;
     RECT  15.973 8.616 17.1 8.688 ;
     RECT  15.973 8.688 17.088 8.712 ;
     RECT  15.973 8.712 17.1 8.784 ;
     RECT  15.973 8.784 17.088 8.808 ;
     RECT  15.973 8.808 17.1 8.88 ;
     RECT  15.973 8.88 17.088 8.904 ;
     RECT  15.973 8.904 17.1 9.024 ;
     RECT  15.973 9.024 17.088 9.048 ;
     RECT  15.973 9.048 17.1 9.12 ;
     RECT  15.973 9.12 17.088 9.144 ;
     RECT  15.973 9.144 17.1 9.216 ;
     RECT  15.973 9.216 17.088 9.24 ;
     RECT  15.973 9.24 17.1 9.312 ;
     RECT  15.973 9.312 17.088 9.336 ;
     RECT  15.973 9.336 17.1 9.408 ;
     RECT  15.973 9.408 17.088 9.432 ;
     RECT  15.973 9.432 17.1 9.552 ;
     RECT  15.973 9.552 17.088 9.576 ;
     RECT  15.973 9.576 17.1 9.648 ;
     RECT  15.973 9.648 17.088 9.672 ;
     RECT  15.973 9.672 17.1 9.744 ;
     RECT  15.973 9.744 17.088 9.768 ;
     RECT  15.973 9.768 17.1 9.84 ;
     RECT  15.973 9.84 17.088 9.864 ;
     RECT  15.973 9.864 17.1 9.936 ;
     RECT  15.973 9.936 17.088 9.96 ;
     RECT  15.973 9.96 17.1 10.032 ;
     RECT  15.973 10.032 17.088 10.056 ;
     RECT  15.973 10.056 17.1 10.176 ;
     RECT  15.973 10.176 17.088 10.2 ;
     RECT  15.973 10.2 17.1 10.272 ;
     RECT  15.973 10.272 17.088 10.296 ;
     RECT  15.973 10.296 17.1 10.368 ;
     RECT  15.973 10.368 17.088 10.392 ;
     RECT  15.973 10.392 17.1 10.464 ;
     RECT  15.973 10.464 17.088 10.488 ;
     RECT  15.973 10.488 17.1 10.56 ;
     RECT  15.973 10.56 17.088 10.584 ;
     RECT  15.973 10.584 17.1 10.656 ;
     RECT  15.973 10.656 17.088 10.68 ;
     RECT  15.973 10.68 17.1 10.8 ;
     RECT  15.973 10.8 17.088 10.824 ;
     RECT  15.973 10.824 17.1 10.896 ;
     RECT  15.973 10.896 17.088 10.92 ;
     RECT  15.973 10.92 17.1 10.992 ;
     RECT  15.973 10.992 17.088 11.016 ;
     RECT  15.973 11.016 17.1 11.088 ;
     RECT  15.973 11.088 17.088 11.112 ;
     RECT  15.973 11.112 17.1 11.184 ;
     RECT  15.973 11.184 17.088 11.208 ;
     RECT  15.973 11.208 17.1 11.28 ;
     RECT  15.973 11.28 17.088 11.304 ;
     RECT  15.973 11.304 17.1 11.424 ;
     RECT  15.973 11.424 17.088 11.448 ;
     RECT  15.973 11.448 17.1 11.52 ;
     RECT  15.973 11.52 17.088 11.544 ;
     RECT  15.973 11.544 17.1 11.616 ;
     RECT  15.973 11.616 17.088 11.64 ;
     RECT  15.973 11.64 17.1 11.712 ;
     RECT  15.973 11.712 17.088 11.736 ;
     RECT  15.973 11.736 17.1 11.808 ;
     RECT  15.973 11.808 17.088 11.832 ;
     RECT  15.973 11.832 17.1 11.952 ;
     RECT  15.973 11.952 17.088 11.976 ;
     RECT  15.973 11.976 17.1 12.048 ;
     RECT  15.973 12.048 17.088 12.072 ;
     RECT  15.973 12.072 17.1 12.144 ;
     RECT  15.973 12.144 17.088 12.168 ;
     RECT  15.973 12.168 17.1 12.24 ;
     RECT  15.973 12.24 17.088 12.264 ;
     RECT  15.973 12.264 17.1 12.336 ;
     RECT  15.973 12.336 17.088 12.36 ;
     RECT  15.973 12.36 17.1 12.432 ;
     RECT  15.973 12.432 17.088 12.456 ;
     RECT  15.973 12.456 17.1 12.576 ;
     RECT  15.973 12.576 17.088 12.6 ;
     RECT  15.973 12.6 17.1 12.672 ;
     RECT  15.973 12.672 17.088 12.696 ;
     RECT  15.973 12.696 17.1 12.768 ;
     RECT  15.973 12.768 17.088 12.792 ;
     RECT  15.973 12.792 17.1 12.864 ;
     RECT  15.973 12.864 17.088 12.888 ;
     RECT  15.973 12.888 17.1 12.96 ;
     RECT  15.973 12.96 17.088 12.984 ;
     RECT  15.973 12.984 17.1 13.056 ;
     RECT  15.973 13.056 17.088 13.08 ;
     RECT  15.973 13.08 17.1 13.2 ;
     RECT  15.973 13.2 17.088 13.224 ;
     RECT  15.973 13.224 17.1 13.296 ;
     RECT  15.973 13.296 17.088 13.32 ;
     RECT  15.973 13.32 17.1 13.392 ;
     RECT  15.973 13.392 17.088 13.416 ;
     RECT  15.973 13.416 17.1 13.488 ;
     RECT  15.973 13.488 17.088 13.512 ;
     RECT  15.973 13.512 17.1 13.584 ;
     RECT  15.973 13.584 17.088 13.608 ;
     RECT  15.973 13.608 17.1 13.728 ;
     RECT  15.973 13.728 17.088 13.752 ;
     RECT  15.973 13.752 17.1 13.824 ;
     RECT  15.973 13.824 17.088 13.848 ;
     RECT  15.973 13.848 17.1 13.92 ;
     RECT  15.973 13.92 17.088 13.944 ;
     RECT  15.973 13.944 17.1 14.016 ;
     RECT  15.973 14.016 17.088 14.04 ;
     RECT  15.973 14.04 17.1 14.112 ;
     RECT  15.973 14.112 17.088 14.136 ;
     RECT  15.973 14.136 17.1 14.208 ;
     RECT  15.973 14.208 17.088 14.232 ;
     RECT  15.973 14.232 17.1 14.352 ;
     RECT  15.973 14.352 17.088 14.376 ;
     RECT  15.973 14.376 17.1 14.448 ;
     RECT  15.973 14.448 17.088 14.472 ;
     RECT  15.973 14.472 17.1 14.544 ;
     RECT  15.973 14.544 17.088 14.568 ;
     RECT  15.973 14.568 17.1 14.64 ;
     RECT  15.973 14.64 17.088 14.664 ;
     RECT  15.973 14.664 17.1 14.736 ;
     RECT  15.973 14.736 17.088 14.76 ;
     RECT  15.973 14.76 17.1 14.832 ;
     RECT  15.973 14.832 17.088 14.856 ;
     RECT  15.973 14.856 17.1 14.976 ;
     RECT  15.973 14.976 17.088 15 ;
     RECT  15.973 15 17.1 15.072 ;
     RECT  15.973 15.072 17.088 15.096 ;
     RECT  15.973 15.096 17.1 15.168 ;
     RECT  15.973 15.168 17.088 15.192 ;
     RECT  15.973 15.192 17.1 15.264 ;
     RECT  15.973 15.264 17.088 15.288 ;
     RECT  15.973 15.288 17.1 15.36 ;
     RECT  15.973 15.36 17.088 15.384 ;
     RECT  15.973 15.384 17.1 15.456 ;
     RECT  15.973 15.456 17.088 15.48 ;
     RECT  15.973 15.48 17.1 15.6 ;
     RECT  15.973 15.6 17.088 15.624 ;
     RECT  15.973 15.624 17.1 15.696 ;
     RECT  15.973 15.696 17.088 15.72 ;
     RECT  15.973 15.72 17.1 15.792 ;
     RECT  15.973 15.792 17.088 15.816 ;
     RECT  15.973 15.816 17.1 15.888 ;
     RECT  15.973 15.888 17.088 15.912 ;
     RECT  15.973 15.912 17.1 15.984 ;
     RECT  15.973 15.984 17.088 16.008 ;
     RECT  15.973 16.008 17.1 16.128 ;
     RECT  15.973 16.128 17.088 16.152 ;
     RECT  15.973 16.152 17.1 16.224 ;
     RECT  15.973 16.224 17.088 16.248 ;
     RECT  15.973 16.248 17.1 16.32 ;
     RECT  15.973 16.32 17.088 16.344 ;
     RECT  15.973 16.344 17.1 16.416 ;
     RECT  15.973 16.416 17.088 16.44 ;
     RECT  15.973 16.44 17.1 16.512 ;
     RECT  15.973 16.512 17.088 16.536 ;
     RECT  15.973 16.536 17.1 16.608 ;
     RECT  15.973 16.608 17.088 16.632 ;
     RECT  15.973 16.632 17.1 16.752 ;
     RECT  15.973 16.752 17.088 16.776 ;
     RECT  15.973 16.776 17.1 16.848 ;
     RECT  15.973 16.848 17.088 16.872 ;
     RECT  15.973 16.872 17.1 16.944 ;
     RECT  15.973 16.944 17.088 16.968 ;
     RECT  15.973 16.968 17.1 17.04 ;
     RECT  15.973 17.04 17.088 17.064 ;
     RECT  15.973 17.064 17.1 17.136 ;
     RECT  15.973 17.136 17.088 17.16 ;
     RECT  15.973 17.16 17.1 17.232 ;
     RECT  15.973 17.232 17.088 17.256 ;
     RECT  15.973 17.256 17.1 17.376 ;
     RECT  15.973 17.376 17.088 17.4 ;
     RECT  15.973 17.4 17.1 17.472 ;
     RECT  15.973 17.472 17.088 17.496 ;
     RECT  15.973 17.496 17.1 17.568 ;
     RECT  15.973 17.568 17.088 17.592 ;
     RECT  15.973 17.592 17.1 17.664 ;
     RECT  15.973 17.664 17.088 17.688 ;
     RECT  15.973 17.688 17.1 17.76 ;
     RECT  15.973 17.76 17.088 17.784 ;
     RECT  15.973 17.784 17.1 17.856 ;
     RECT  15.973 17.856 17.088 17.88 ;
     RECT  15.973 17.88 17.1 18 ;
     RECT  15.973 18 17.088 18.024 ;
     RECT  15.973 18.024 17.1 18.096 ;
     RECT  15.973 18.096 17.088 18.12 ;
     RECT  15.973 18.12 17.1 18.192 ;
     RECT  15.973 18.192 17.088 18.216 ;
     RECT  15.973 18.216 17.1 18.288 ;
     RECT  15.973 18.288 17.088 18.312 ;
     RECT  15.973 18.312 17.1 18.384 ;
     RECT  15.973 18.384 17.088 18.408 ;
     RECT  15.973 18.408 17.1 18.528 ;
     RECT  15.973 18.528 17.088 18.552 ;
     RECT  15.973 18.552 17.1 18.624 ;
     RECT  15.973 18.624 17.088 18.648 ;
     RECT  15.973 18.648 17.1 18.72 ;
     RECT  15.973 18.72 17.088 18.744 ;
     RECT  15.973 18.744 17.1 18.816 ;
     RECT  15.973 18.816 17.088 18.84 ;
     RECT  15.973 18.84 17.1 18.912 ;
     RECT  15.973 18.912 17.088 18.936 ;
     RECT  15.973 18.936 17.1 19.008 ;
     RECT  15.973 19.008 17.088 19.032 ;
     RECT  15.973 19.032 17.1 19.152 ;
     RECT  15.973 19.152 17.088 19.176 ;
     RECT  15.973 19.176 17.1 19.248 ;
     RECT  15.973 19.248 17.088 19.272 ;
     RECT  15.973 19.272 17.1 19.344 ;
     RECT  15.973 19.344 17.088 19.368 ;
     RECT  15.973 19.368 17.1 19.44 ;
     RECT  15.973 19.44 17.088 19.464 ;
     RECT  15.973 19.464 17.1 19.536 ;
     RECT  15.973 19.536 17.088 19.56 ;
     RECT  15.973 19.56 17.1 19.632 ;
     RECT  15.973 19.632 17.088 19.656 ;
     RECT  15.973 19.656 17.1 19.776 ;
     RECT  15.973 19.776 17.088 19.8 ;
     RECT  15.973 19.8 17.1 19.872 ;
     RECT  15.973 19.872 17.088 19.896 ;
     RECT  15.973 19.896 17.1 19.968 ;
     RECT  15.973 19.968 17.088 19.992 ;
     RECT  15.973 19.992 17.1 20.064 ;
     RECT  15.973 20.064 17.088 20.088 ;
     RECT  15.973 20.088 17.1 20.16 ;
     RECT  15.973 20.16 17.088 20.184 ;
     RECT  15.973 20.184 17.1 20.256 ;
     RECT  15.973 20.256 17.088 20.28 ;
     RECT  15.973 20.28 17.1 20.4 ;
     RECT  15.973 20.4 17.088 20.424 ;
     RECT  15.973 20.424 17.1 20.496 ;
     RECT  15.973 20.496 17.088 20.52 ;
     RECT  15.973 20.52 17.1 20.592 ;
     RECT  15.973 20.592 17.088 20.616 ;
     RECT  15.973 20.616 17.1 20.688 ;
     RECT  15.973 20.688 17.088 20.712 ;
     RECT  15.973 20.712 17.1 20.784 ;
     RECT  15.973 20.784 17.088 20.808 ;
     RECT  15.973 20.808 17.1 20.928 ;
     RECT  15.973 20.928 17.088 20.952 ;
     RECT  15.973 20.952 17.1 21.024 ;
     RECT  15.973 21.024 17.088 21.048 ;
     RECT  15.973 21.048 17.1 21.12 ;
     RECT  15.973 21.12 17.088 21.144 ;
     RECT  15.973 21.144 17.1 21.216 ;
     RECT  15.973 21.216 17.088 21.24 ;
     RECT  15.973 21.24 17.1 21.312 ;
     RECT  15.973 21.312 17.088 21.336 ;
     RECT  15.973 21.336 17.1 21.408 ;
     RECT  15.973 21.408 17.088 21.432 ;
     RECT  15.973 21.432 17.1 21.552 ;
     RECT  15.973 21.552 17.088 21.576 ;
     RECT  15.973 21.576 17.1 21.648 ;
     RECT  15.973 21.648 17.088 21.672 ;
     RECT  15.973 21.672 17.1 21.744 ;
     RECT  15.973 21.744 17.088 21.768 ;
     RECT  15.973 21.768 17.1 21.84 ;
     RECT  15.973 21.84 17.088 21.864 ;
     RECT  15.973 21.864 17.1 21.936 ;
     RECT  15.973 21.936 17.088 21.96 ;
     RECT  15.973 21.96 17.1 22.032 ;
     RECT  15.973 22.032 17.088 22.056 ;
     RECT  15.973 22.056 17.1 22.176 ;
     RECT  15.973 22.176 17.088 22.2 ;
     RECT  15.973 22.2 17.1 22.272 ;
     RECT  15.973 22.272 17.088 22.296 ;
     RECT  15.973 22.296 17.1 22.368 ;
     RECT  15.973 22.368 17.088 22.392 ;
     RECT  15.973 22.392 17.1 22.464 ;
     RECT  15.973 22.464 17.088 22.488 ;
     RECT  15.973 22.488 17.1 22.56 ;
     RECT  15.973 22.56 17.088 22.584 ;
     RECT  15.973 22.584 17.1 22.656 ;
     RECT  15.973 22.656 17.088 22.68 ;
     RECT  15.973 22.68 17.1 22.8 ;
     RECT  15.973 22.8 17.088 22.824 ;
     RECT  15.973 22.824 17.1 22.896 ;
     RECT  15.973 22.896 17.088 22.92 ;
     RECT  15.973 22.92 17.1 22.992 ;
     RECT  15.973 22.992 17.088 23.016 ;
     RECT  15.973 23.016 17.1 23.088 ;
     RECT  15.973 23.088 17.088 23.112 ;
     RECT  15.973 23.112 17.1 23.184 ;
     RECT  15.973 23.184 17.088 23.208 ;
     RECT  15.973 23.208 17.1 23.328 ;
     RECT  15.973 23.328 17.088 23.352 ;
     RECT  15.973 23.352 17.1 23.424 ;
     RECT  15.973 23.424 17.088 23.448 ;
     RECT  15.973 23.448 17.1 23.52 ;
     RECT  15.973 23.52 17.088 23.544 ;
     RECT  15.973 23.544 17.1 23.616 ;
     RECT  15.973 23.616 17.088 23.64 ;
     RECT  15.973 23.64 17.1 23.712 ;
     RECT  15.973 23.712 17.088 23.736 ;
     RECT  15.973 23.736 17.1 23.808 ;
     RECT  15.973 23.808 17.088 23.832 ;
     RECT  15.973 23.832 17.1 23.952 ;
     RECT  15.973 23.952 17.088 23.976 ;
     RECT  15.973 23.976 17.1 24.048 ;
     RECT  15.973 24.048 17.088 24.072 ;
     RECT  15.973 24.072 17.1 24.144 ;
     RECT  15.973 24.144 17.088 24.168 ;
     RECT  15.973 24.168 17.1 24.24 ;
     RECT  15.973 24.24 17.088 24.264 ;
     RECT  15.973 24.264 17.1 24.336 ;
     RECT  15.973 24.336 17.088 24.36 ;
     RECT  15.973 24.36 17.1 24.432 ;
     RECT  15.973 24.432 17.088 24.456 ;
     RECT  15.973 24.456 17.1 24.576 ;
     RECT  15.973 24.576 17.088 24.6 ;
     RECT  15.973 24.6 17.1 24.672 ;
     RECT  15.973 24.672 17.088 24.696 ;
     RECT  15.973 24.696 17.1 24.768 ;
     RECT  15.973 24.768 17.088 24.792 ;
     RECT  15.973 24.792 17.1 24.864 ;
     RECT  15.973 24.864 17.088 24.888 ;
     RECT  15.973 24.888 17.1 24.96 ;
     RECT  15.973 24.96 17.088 24.984 ;
     RECT  15.973 24.984 17.1 25.056 ;
     RECT  15.973 25.056 17.088 25.08 ;
     RECT  15.973 25.08 17.1 25.2 ;
     RECT  15.973 25.2 17.088 25.224 ;
     RECT  15.973 25.224 17.1 25.296 ;
     RECT  15.973 25.296 17.088 25.32 ;
     RECT  15.973 25.32 17.1 25.392 ;
     RECT  15.973 25.392 17.088 25.416 ;
     RECT  15.973 25.416 17.1 25.488 ;
     RECT  15.973 25.488 17.088 25.512 ;
     RECT  15.973 25.512 17.1 25.584 ;
     RECT  15.973 25.584 17.088 25.608 ;
     RECT  15.973 25.608 17.1 25.728 ;
     RECT  15.973 25.728 17.088 25.752 ;
     RECT  15.973 25.752 17.1 25.824 ;
     RECT  15.973 25.824 17.088 25.848 ;
     RECT  15.973 25.848 17.1 25.92 ;
     RECT  15.973 25.92 17.088 25.944 ;
     RECT  15.973 25.944 17.1 26.016 ;
     RECT  15.973 26.016 17.088 26.04 ;
     RECT  15.973 26.04 17.1 26.112 ;
     RECT  15.973 26.112 17.088 26.136 ;
     RECT  15.973 26.136 17.1 26.208 ;
     RECT  15.973 26.208 17.088 26.232 ;
     RECT  15.973 26.232 17.1 26.352 ;
     RECT  15.973 26.352 17.088 26.376 ;
     RECT  15.973 26.376 17.1 26.448 ;
     RECT  15.973 26.448 17.088 26.472 ;
     RECT  15.973 26.472 17.1 26.544 ;
     RECT  15.973 26.544 17.088 26.568 ;
     RECT  15.973 26.568 17.1 26.64 ;
     RECT  15.973 26.64 17.088 26.664 ;
     RECT  15.973 26.664 17.1 26.736 ;
     RECT  15.973 26.736 17.088 26.76 ;
     RECT  15.973 26.76 17.1 26.832 ;
     RECT  15.973 26.832 17.088 26.856 ;
     RECT  15.973 26.856 17.1 26.976 ;
     RECT  15.973 26.976 17.088 27 ;
     RECT  15.973 27 17.1 27.072 ;
     RECT  15.973 27.072 17.088 27.096 ;
     RECT  15.973 27.096 17.1 27.168 ;
     RECT  15.973 27.168 17.088 27.192 ;
     RECT  15.973 27.192 17.1 27.264 ;
     RECT  15.973 27.264 17.088 27.288 ;
     RECT  15.973 27.288 17.1 27.36 ;
     RECT  15.973 27.36 17.088 27.384 ;
     RECT  15.973 27.384 17.1 27.504 ;
     RECT  15.973 27.504 17.088 27.528 ;
     RECT  15.973 27.528 17.1 27.6 ;
     RECT  15.973 27.6 17.088 27.624 ;
     RECT  15.973 27.624 17.1 27.696 ;
     RECT  15.973 27.696 17.088 27.72 ;
     RECT  15.973 27.72 17.1 27.792 ;
     RECT  15.973 27.792 17.088 27.816 ;
     RECT  15.973 27.816 17.1 27.888 ;
     RECT  15.973 27.888 17.088 27.912 ;
     RECT  15.973 27.912 17.1 27.984 ;
     RECT  15.973 27.984 17.088 28.008 ;
     RECT  15.973 28.008 17.1 28.128 ;
     RECT  15.973 28.128 17.088 28.152 ;
     RECT  15.973 28.152 17.1 28.224 ;
     RECT  15.973 28.224 17.088 28.248 ;
     RECT  15.973 28.248 17.1 28.32 ;
     RECT  15.973 28.32 17.088 28.344 ;
     RECT  15.973 28.344 17.1 28.416 ;
     RECT  15.973 28.416 17.088 28.44 ;
     RECT  15.973 28.44 17.1 28.512 ;
     RECT  15.973 28.512 17.088 28.536 ;
     RECT  15.973 28.536 17.1 28.608 ;
     RECT  15.973 28.608 17.088 28.632 ;
     RECT  15.973 28.632 17.1 28.752 ;
     RECT  15.973 28.752 17.088 28.776 ;
     RECT  15.973 28.776 17.1 28.848 ;
     RECT  15.973 28.848 17.088 28.872 ;
     RECT  15.973 28.872 17.1 28.944 ;
     RECT  15.973 28.944 17.088 28.968 ;
     RECT  15.973 28.968 17.1 29.04 ;
     RECT  15.973 29.04 17.088 29.064 ;
     RECT  15.973 29.064 17.1 29.136 ;
     RECT  15.973 29.136 17.088 29.16 ;
     RECT  15.973 29.16 17.1 29.232 ;
     RECT  15.973 29.232 17.088 29.256 ;
     RECT  15.973 29.256 17.1 29.376 ;
     RECT  15.973 29.376 17.088 29.4 ;
     RECT  15.973 29.4 17.1 29.472 ;
     RECT  15.973 29.472 17.088 29.496 ;
     RECT  15.973 29.496 17.1 29.568 ;
     RECT  15.973 29.568 17.088 29.592 ;
     RECT  15.973 29.592 17.1 29.664 ;
     RECT  15.973 29.664 17.088 29.688 ;
     RECT  15.973 29.688 17.1 29.76 ;
     RECT  15.973 29.76 17.088 29.784 ;
     RECT  15.973 29.784 17.1 29.904 ;
     RECT  15.973 29.904 17.088 29.928 ;
     RECT  15.973 29.928 17.1 30 ;
     RECT  15.973 30 17.088 30.024 ;
     RECT  15.973 30.024 17.1 30.096 ;
     RECT  15.973 30.096 17.088 30.12 ;
     RECT  15.973 30.12 17.1 30.192 ;
     RECT  15.973 30.192 17.088 30.216 ;
     RECT  15.973 30.216 17.1 30.288 ;
     RECT  15.973 30.288 17.088 30.312 ;
     RECT  15.973 30.312 17.1 30.384 ;
     RECT  15.973 30.384 17.088 30.408 ;
     RECT  15.973 30.408 17.1 30.528 ;
     RECT  15.973 30.528 17.088 30.552 ;
     RECT  15.973 30.552 17.1 30.624 ;
     RECT  15.973 30.624 17.088 30.648 ;
     RECT  15.973 30.648 17.1 30.72 ;
     RECT  15.973 30.72 17.088 30.744 ;
     RECT  15.973 30.744 17.1 30.816 ;
     RECT  15.973 30.816 17.088 30.84 ;
     RECT  15.973 30.84 17.1 30.912 ;
     RECT  15.973 30.912 17.088 30.936 ;
     RECT  15.973 30.936 17.1 31.008 ;
     RECT  15.973 31.008 17.088 31.032 ;
     RECT  15.973 31.032 17.1 31.152 ;
     RECT  15.973 31.152 17.088 31.176 ;
     RECT  15.973 31.176 17.1 31.248 ;
     RECT  15.973 31.248 17.088 31.272 ;
     RECT  15.973 31.272 17.1 31.344 ;
     RECT  15.973 31.344 17.088 31.368 ;
     RECT  15.973 31.368 17.1 31.44 ;
     RECT  15.973 31.44 17.088 31.464 ;
     RECT  15.973 31.464 17.1 31.536 ;
     RECT  15.973 31.536 17.088 31.56 ;
     RECT  15.973 31.56 17.1 31.632 ;
     RECT  15.973 31.632 17.088 31.656 ;
     RECT  15.973 31.656 17.1 31.776 ;
     RECT  15.973 31.776 17.088 31.8 ;
     RECT  15.973 31.8 17.1 31.872 ;
     RECT  15.973 31.872 17.088 31.896 ;
     RECT  15.973 31.896 17.1 31.968 ;
     RECT  15.973 31.968 17.088 31.992 ;
     RECT  15.973 31.992 17.1 32.064 ;
     RECT  15.973 32.064 17.088 32.088 ;
     RECT  15.973 32.088 17.1 32.16 ;
     RECT  15.973 32.16 17.088 32.184 ;
     RECT  15.973 32.184 17.1 32.304 ;
     RECT  15.973 32.304 17.088 32.328 ;
     RECT  15.973 32.328 17.1 32.4 ;
     RECT  15.973 32.4 17.088 32.424 ;
     RECT  15.973 32.424 17.1 32.496 ;
     RECT  15.973 32.496 17.088 32.52 ;
     RECT  15.973 32.52 17.1 32.592 ;
     RECT  15.973 32.592 17.088 32.616 ;
     RECT  15.973 32.616 17.1 32.688 ;
     RECT  15.973 32.688 17.088 32.712 ;
     RECT  15.973 32.712 17.1 32.784 ;
     RECT  15.973 32.784 17.088 32.808 ;
     RECT  15.973 32.808 17.1 32.928 ;
     RECT  15.973 32.928 17.088 32.952 ;
     RECT  15.973 32.952 17.1 33.024 ;
     RECT  15.973 33.024 17.088 33.048 ;
     RECT  15.973 33.048 17.1 33.12 ;
     RECT  15.973 33.12 17.088 33.144 ;
     RECT  15.973 33.144 17.1 33.216 ;
     RECT  15.973 33.216 17.088 33.24 ;
     RECT  15.973 33.24 17.1 33.312 ;
     RECT  15.973 33.312 17.088 33.336 ;
     RECT  15.973 33.336 17.1 33.408 ;
     RECT  15.973 33.408 17.088 33.432 ;
     RECT  15.973 33.432 17.1 33.552 ;
     RECT  15.973 33.552 17.088 33.576 ;
     RECT  15.973 33.576 17.1 33.648 ;
     RECT  15.973 33.648 17.088 33.672 ;
     RECT  15.973 33.672 17.1 33.744 ;
     RECT  15.973 33.744 17.088 33.768 ;
     RECT  15.973 33.768 17.1 33.84 ;
     RECT  15.973 33.84 17.088 33.864 ;
     RECT  15.973 33.864 17.1 33.936 ;
     RECT  15.973 33.936 17.088 33.96 ;
     RECT  15.973 33.96 17.1 34.032 ;
     RECT  15.973 34.032 17.088 34.056 ;
     RECT  15.973 34.056 17.1 34.176 ;
     RECT  15.973 34.176 17.088 34.2 ;
     RECT  15.973 34.2 17.1 34.272 ;
     RECT  15.973 34.272 17.088 34.296 ;
     RECT  15.973 34.296 17.1 34.368 ;
     RECT  15.973 34.368 17.088 34.392 ;
     RECT  15.973 34.392 17.1 34.464 ;
     RECT  15.973 34.464 17.088 34.488 ;
     RECT  15.973 34.488 17.1 34.56 ;
     RECT  15.973 34.56 17.088 34.584 ;
     RECT  15.973 34.584 17.1 34.704 ;
     RECT  15.973 34.704 17.088 34.728 ;
     RECT  15.973 34.728 17.1 34.8 ;
     RECT  15.973 34.8 17.088 34.824 ;
     RECT  15.973 34.824 17.1 34.896 ;
     RECT  15.973 34.896 17.088 34.92 ;
     RECT  15.973 34.92 17.1 34.992 ;
     RECT  15.973 34.992 17.088 35.016 ;
     RECT  15.973 35.016 17.1 35.088 ;
     RECT  15.973 35.088 17.088 35.112 ;
     RECT  15.973 35.112 17.1 35.184 ;
     RECT  15.973 35.184 17.088 35.208 ;
     RECT  15.973 35.208 17.1 35.328 ;
     RECT  15.973 35.328 17.088 35.352 ;
     RECT  15.973 35.352 17.1 35.424 ;
     RECT  15.973 35.424 17.088 35.448 ;
     RECT  15.973 35.448 17.1 35.52 ;
     RECT  15.973 35.52 17.088 35.544 ;
     RECT  15.973 35.544 17.1 35.616 ;
     RECT  15.973 35.616 17.088 35.64 ;
     RECT  15.973 35.64 17.1 35.712 ;
     RECT  15.973 35.712 17.088 35.736 ;
     RECT  15.973 35.736 17.1 35.808 ;
     RECT  15.973 35.808 17.088 35.832 ;
     RECT  15.973 35.832 17.1 35.952 ;
     RECT  15.973 35.952 17.088 35.976 ;
     RECT  15.973 35.976 17.1 36.048 ;
     RECT  15.973 36.048 17.088 36.072 ;
     RECT  15.973 36.072 17.1 36.144 ;
     RECT  15.973 36.144 17.088 36.168 ;
     RECT  15.973 36.168 17.1 36.24 ;
     RECT  15.973 36.24 17.088 36.264 ;
     RECT  15.973 36.264 17.1 36.336 ;
     RECT  15.973 36.336 17.088 36.36 ;
     RECT  15.973 36.36 17.1 36.432 ;
     RECT  15.973 36.432 17.088 36.456 ;
     RECT  15.973 36.456 17.1 36.576 ;
     RECT  15.973 36.576 17.088 36.6 ;
     RECT  15.973 36.6 17.1 36.672 ;
     RECT  15.973 36.672 17.088 36.696 ;
     RECT  15.973 36.696 17.1 36.768 ;
     RECT  15.973 36.768 17.088 36.792 ;
     RECT  15.973 36.792 17.1 36.864 ;
     RECT  15.973 36.864 17.088 36.888 ;
     RECT  15.973 36.888 17.1 36.96 ;
     RECT  15.973 36.96 17.088 36.984 ;
     RECT  15.973 36.984 17.1 37.104 ;
     RECT  15.973 37.104 17.088 37.128 ;
     RECT  15.973 37.128 17.1 37.2 ;
     RECT  15.973 37.2 17.088 37.224 ;
     RECT  15.973 37.224 17.1 37.296 ;
     RECT  15.973 37.296 17.088 37.32 ;
     RECT  15.973 37.32 17.1 37.392 ;
     RECT  15.973 37.392 17.088 37.416 ;
     RECT  15.973 37.416 17.1 37.488 ;
     RECT  15.973 37.488 17.088 37.512 ;
     RECT  15.973 37.512 17.1 37.584 ;
     RECT  15.973 37.584 17.088 37.608 ;
     RECT  15.973 37.608 17.1 37.728 ;
     RECT  15.973 37.728 17.088 37.752 ;
     RECT  15.973 37.752 17.1 37.824 ;
     RECT  15.973 37.824 17.088 37.848 ;
     RECT  15.973 37.848 17.1 37.92 ;
     RECT  15.973 37.92 17.088 37.944 ;
     RECT  15.973 37.944 17.1 38.016 ;
     RECT  15.973 38.016 17.088 38.04 ;
     RECT  15.973 38.04 17.1 38.112 ;
     RECT  15.973 38.112 17.088 38.136 ;
     RECT  15.973 38.136 17.1 38.208 ;
     RECT  15.973 38.208 17.088 38.232 ;
     RECT  15.973 38.232 17.1 38.352 ;
     RECT  15.973 38.352 17.088 38.376 ;
     RECT  15.973 38.376 17.1 38.448 ;
     RECT  15.973 38.448 17.088 38.472 ;
     RECT  15.973 38.472 17.1 38.544 ;
     RECT  15.973 38.544 17.088 38.568 ;
     RECT  15.973 38.568 17.1 38.64 ;
     RECT  15.973 38.64 17.088 38.664 ;
     RECT  15.973 38.664 17.1 38.736 ;
     RECT  15.973 38.736 17.088 38.76 ;
     RECT  15.973 38.76 17.1 38.832 ;
     RECT  15.973 38.832 17.088 38.856 ;
     RECT  15.973 38.856 17.1 38.976 ;
     RECT  15.973 38.976 17.088 39 ;
     RECT  15.973 39 17.1 39.072 ;
     RECT  15.973 39.072 17.088 39.096 ;
     RECT  15.973 39.096 17.1 39.168 ;
     RECT  15.973 39.168 17.088 39.192 ;
     RECT  15.973 39.192 17.1 39.264 ;
     RECT  15.973 39.264 17.088 39.288 ;
     RECT  15.973 39.288 17.1 39.36 ;
     RECT  15.973 39.36 17.088 39.384 ;
     RECT  15.973 39.384 17.1 39.504 ;
     RECT  15.973 39.504 17.088 39.528 ;
     RECT  15.973 39.528 17.1 39.6 ;
     RECT  15.973 39.6 17.088 39.624 ;
     RECT  15.973 39.624 17.1 39.696 ;
     RECT  15.973 39.696 17.088 39.72 ;
     RECT  15.973 39.72 17.1 39.792 ;
     RECT  15.973 39.792 17.088 39.816 ;
     RECT  15.973 39.816 17.1 39.888 ;
     RECT  15.973 39.888 17.088 39.912 ;
     RECT  15.973 39.912 17.1 39.984 ;
     RECT  15.973 39.984 17.088 40.008 ;
     RECT  15.973 40.008 17.1 40.128 ;
     RECT  15.973 40.128 17.088 40.152 ;
     RECT  15.973 40.152 17.1 40.224 ;
     RECT  15.973 40.224 17.088 40.248 ;
     RECT  15.973 40.248 17.1 40.32 ;
     RECT  15.973 40.32 17.088 40.344 ;
     RECT  15.973 40.344 17.1 40.416 ;
     RECT  15.973 40.416 17.088 40.44 ;
     RECT  15.973 40.44 17.1 40.512 ;
     RECT  15.973 40.512 17.088 40.536 ;
     RECT  15.973 40.536 17.1 40.608 ;
     RECT  15.973 40.608 17.088 40.632 ;
     RECT  15.973 40.632 17.1 40.752 ;
     RECT  15.973 40.752 17.088 40.776 ;
     RECT  15.973 40.776 17.1 40.848 ;
     RECT  15.973 40.848 17.088 40.872 ;
     RECT  15.973 40.872 17.1 40.944 ;
     RECT  15.973 40.944 17.088 40.968 ;
     RECT  15.973 40.968 17.1 41.04 ;
     RECT  15.973 41.04 17.088 41.064 ;
     RECT  15.973 41.064 17.1 41.136 ;
     RECT  15.973 41.136 17.088 41.16 ;
     RECT  15.973 41.16 17.1 41.232 ;
     RECT  15.973 41.232 17.088 41.256 ;
     RECT  15.973 41.256 17.1 41.376 ;
     RECT  15.973 41.376 17.088 41.4 ;
     RECT  15.973 41.4 17.1 41.472 ;
     RECT  15.973 41.472 17.088 41.496 ;
     RECT  15.973 41.496 17.1 41.568 ;
     RECT  15.973 41.568 17.088 41.592 ;
     RECT  15.973 41.592 17.1 41.664 ;
     RECT  15.973 41.664 17.088 41.688 ;
     RECT  15.973 41.688 17.1 41.76 ;
     RECT  15.973 41.76 17.088 41.784 ;
     RECT  15.973 41.784 17.1 41.904 ;
     RECT  15.973 41.904 17.088 41.928 ;
     RECT  15.973 41.928 17.1 42 ;
     RECT  15.973 42 17.088 42.024 ;
     RECT  15.973 42.024 17.1 42.096 ;
     RECT  15.973 42.096 17.088 42.12 ;
     RECT  15.973 42.12 17.1 42.192 ;
     RECT  15.973 42.192 17.088 42.216 ;
     RECT  15.973 42.216 17.1 42.288 ;
     RECT  15.973 42.288 17.088 42.312 ;
     RECT  15.973 42.312 17.1 42.384 ;
     RECT  15.973 42.384 17.088 42.408 ;
     RECT  15.973 42.408 17.1 42.528 ;
     RECT  15.973 42.528 17.088 42.552 ;
     RECT  15.973 42.552 17.1 42.624 ;
     RECT  15.973 42.624 17.088 42.648 ;
     RECT  15.973 42.648 17.1 42.72 ;
     RECT  15.973 42.72 17.088 42.744 ;
     RECT  15.973 42.744 17.1 42.816 ;
     RECT  15.973 42.816 17.088 42.84 ;
     RECT  15.973 42.84 17.1 42.912 ;
     RECT  15.973 42.912 17.088 42.936 ;
     RECT  15.973 42.936 17.1 43.008 ;
     RECT  15.973 43.008 17.088 43.032 ;
     RECT  15.973 43.032 17.1 43.152 ;
     RECT  15.973 43.152 17.088 43.176 ;
     RECT  15.973 43.176 17.1 43.248 ;
     RECT  15.973 43.248 17.088 43.272 ;
     RECT  15.973 43.272 17.1 43.344 ;
     RECT  15.973 43.344 17.088 43.368 ;
     RECT  15.973 43.368 17.1 43.44 ;
     RECT  15.973 43.44 17.088 43.464 ;
     RECT  15.973 43.464 17.1 43.536 ;
     RECT  15.973 43.536 17.088 43.56 ;
     RECT  15.973 43.56 17.1 43.68 ;
     RECT  15.973 43.68 17.088 43.704 ;
     RECT  15.973 43.704 17.1 43.776 ;
     RECT  15.973 43.776 17.088 43.8 ;
     RECT  15.973 43.8 17.1 43.872 ;
     RECT  15.973 43.872 17.088 43.896 ;
     RECT  15.973 43.896 17.1 43.968 ;
     RECT  15.973 43.968 17.088 43.992 ;
     RECT  15.973 43.992 17.1 44.064 ;
     RECT  15.973 44.064 17.088 44.088 ;
     RECT  15.973 44.088 17.1 44.16 ;
     RECT  15.973 44.16 17.088 44.184 ;
     RECT  15.973 44.184 17.1 44.304 ;
     RECT  15.973 44.304 17.088 44.328 ;
     RECT  15.973 44.328 17.1 44.4 ;
     RECT  15.973 44.4 17.088 44.424 ;
     RECT  15.973 44.424 17.1 44.496 ;
     RECT  15.973 44.496 17.088 44.52 ;
     RECT  15.973 44.52 17.1 44.592 ;
     RECT  15.973 44.592 17.088 44.616 ;
     RECT  15.973 44.616 17.1 44.688 ;
     RECT  15.973 44.688 17.088 44.712 ;
     RECT  15.973 44.712 17.1 44.784 ;
     RECT  15.973 44.784 17.088 44.808 ;
     RECT  15.973 44.808 17.1 44.928 ;
     RECT  15.973 44.928 17.088 44.952 ;
     RECT  15.973 44.952 17.1 45.024 ;
     RECT  15.973 45.024 17.088 45.048 ;
     RECT  15.973 45.048 17.1 45.12 ;
     RECT  15.973 45.12 17.088 45.144 ;
     RECT  15.973 45.144 17.1 45.216 ;
     RECT  15.973 45.216 17.088 45.24 ;
     RECT  15.973 45.24 17.1 45.312 ;
     RECT  15.973 45.312 17.088 45.336 ;
     RECT  15.973 45.336 17.1 45.408 ;
     RECT  15.973 45.408 17.088 45.432 ;
     RECT  15.973 45.432 17.1 45.552 ;
     RECT  15.973 45.552 17.088 45.576 ;
     RECT  15.973 45.576 17.1 45.648 ;
     RECT  15.973 45.648 17.088 45.672 ;
     RECT  15.973 45.672 17.1 45.744 ;
     RECT  15.973 45.744 17.088 45.768 ;
     RECT  15.973 45.768 17.1 45.84 ;
     RECT  15.973 45.84 17.088 45.864 ;
     RECT  15.973 45.864 17.1 45.936 ;
     RECT  15.973 45.936 17.088 45.96 ;
     RECT  15.973 45.96 17.1 46.08 ;
     RECT  15.973 46.08 17.088 46.104 ;
     RECT  15.973 46.104 17.1 46.176 ;
     RECT  15.973 46.176 17.088 46.2 ;
     RECT  15.973 46.2 17.1 46.272 ;
     RECT  15.973 46.272 17.088 46.296 ;
     RECT  15.973 46.296 17.1 46.368 ;
     RECT  15.973 46.368 17.088 46.392 ;
     RECT  15.973 46.392 17.1 46.464 ;
     RECT  15.973 46.464 17.088 46.488 ;
     RECT  15.973 46.488 17.1 46.56 ;
     RECT  15.973 46.56 17.088 46.584 ;
     RECT  15.973 46.584 17.1 46.704 ;
     RECT  15.973 46.704 17.088 46.728 ;
     RECT  15.973 46.728 17.1 46.8 ;
     RECT  15.973 46.8 17.088 46.824 ;
     RECT  15.973 46.824 17.1 46.896 ;
     RECT  15.973 46.896 17.088 46.92 ;
     RECT  15.973 46.92 17.1 46.992 ;
     RECT  15.973 46.992 17.088 47.016 ;
     RECT  15.973 47.016 17.1 47.088 ;
     RECT  15.973 47.088 17.088 47.112 ;
     RECT  15.973 47.112 17.1 47.184 ;
     RECT  15.973 47.184 17.088 47.208 ;
     RECT  15.973 47.208 17.1 47.328 ;
     RECT  15.973 47.328 17.088 47.352 ;
     RECT  15.973 47.352 17.1 47.424 ;
     RECT  15.973 47.424 17.088 47.448 ;
     RECT  15.973 47.448 17.1 47.52 ;
     RECT  15.973 47.52 17.088 47.544 ;
     RECT  15.973 47.544 17.1 47.616 ;
     RECT  15.973 47.616 17.088 47.64 ;
     RECT  15.973 47.64 17.1 47.712 ;
     RECT  15.973 47.712 17.088 47.736 ;
     RECT  15.973 47.736 17.1 47.808 ;
     RECT  15.973 47.808 17.088 47.832 ;
     RECT  15.973 47.832 17.1 47.952 ;
     RECT  15.973 47.952 17.088 47.976 ;
     RECT  15.973 47.976 17.1 48.048 ;
     RECT  15.973 48.048 17.088 48.072 ;
     RECT  15.973 48.072 17.1 48.144 ;
     RECT  15.973 48.144 17.088 48.168 ;
     RECT  15.973 48.168 17.1 48.24 ;
     RECT  15.973 48.24 17.088 48.264 ;
     RECT  15.973 48.264 17.1 48.336 ;
     RECT  15.973 48.336 17.088 48.36 ;
     RECT  15.973 48.36 17.1 48.48 ;
     RECT  15.973 48.48 17.088 48.504 ;
     RECT  15.973 48.504 17.1 48.576 ;
     RECT  15.973 48.576 17.088 48.6 ;
     RECT  15.973 48.6 17.1 48.672 ;
     RECT  15.973 48.672 17.088 48.696 ;
     RECT  15.973 48.696 17.1 48.768 ;
     RECT  15.973 48.768 17.088 48.792 ;
     RECT  15.973 48.792 17.1 48.864 ;
     RECT  15.973 48.864 17.088 48.888 ;
     RECT  15.973 48.888 17.1 48.96 ;
     RECT  15.973 48.96 17.088 48.984 ;
     RECT  15.973 48.984 17.1 49.104 ;
     RECT  15.973 49.104 17.088 49.128 ;
     RECT  15.973 49.128 17.1 49.2 ;
     RECT  15.973 49.2 17.088 49.224 ;
     RECT  15.973 49.224 17.1 49.296 ;
     RECT  15.973 49.296 17.088 49.32 ;
     RECT  15.973 49.32 17.1 49.392 ;
     RECT  15.973 49.392 17.088 49.416 ;
     RECT  15.973 49.416 17.1 49.488 ;
     RECT  15.973 49.488 17.088 49.512 ;
     RECT  15.973 49.512 17.1 49.584 ;
     RECT  15.973 49.584 17.088 49.608 ;
     RECT  15.973 49.608 17.1 49.728 ;
     RECT  15.973 49.728 17.088 49.752 ;
     RECT  15.973 49.752 17.1 49.824 ;
     RECT  15.973 49.824 17.088 49.848 ;
     RECT  15.973 49.848 17.1 49.92 ;
     RECT  15.973 49.92 17.088 49.944 ;
     RECT  15.973 49.944 17.1 50.016 ;
     RECT  15.973 50.016 17.088 50.04 ;
     RECT  15.973 50.04 17.1 50.112 ;
     RECT  15.973 50.112 17.088 50.136 ;
     RECT  15.973 50.136 17.1 50.208 ;
     RECT  15.973 50.208 17.088 50.232 ;
     RECT  15.973 50.232 17.1 50.352 ;
     RECT  15.973 50.352 17.088 50.376 ;
     RECT  15.973 50.376 17.1 50.448 ;
     RECT  15.973 50.448 17.088 50.472 ;
     RECT  15.973 50.472 17.1 50.544 ;
     RECT  15.973 50.544 17.088 50.568 ;
     RECT  15.973 50.568 17.1 50.64 ;
     RECT  15.973 50.64 17.088 50.664 ;
     RECT  15.973 50.664 17.1 50.736 ;
     RECT  15.973 50.736 17.088 50.76 ;
     RECT  15.973 50.76 17.1 50.88 ;
     RECT  15.973 50.88 17.088 50.904 ;
     RECT  15.973 50.904 17.1 50.976 ;
     RECT  15.973 50.976 17.088 51 ;
     RECT  15.973 51 17.1 51.072 ;
     RECT  15.973 51.072 17.088 51.096 ;
     RECT  15.973 51.096 17.1 51.168 ;
     RECT  15.973 51.168 17.088 51.192 ;
     RECT  15.973 51.192 17.1 51.264 ;
     RECT  15.973 51.264 17.088 51.288 ;
     RECT  15.973 51.288 17.1 51.36 ;
     RECT  15.973 51.36 17.088 51.384 ;
     RECT  15.973 51.384 17.1 51.504 ;
     RECT  15.973 51.504 17.088 51.528 ;
     RECT  15.973 51.528 17.1 51.6 ;
     RECT  15.973 51.6 17.088 51.624 ;
     RECT  15.973 51.624 17.1 51.696 ;
     RECT  15.973 51.696 17.088 51.72 ;
     RECT  15.973 51.72 17.1 51.792 ;
     RECT  15.973 51.792 17.088 51.816 ;
     RECT  15.973 51.816 17.1 51.888 ;
     RECT  15.973 51.888 17.088 51.912 ;
     RECT  15.973 51.912 17.1 51.984 ;
     RECT  15.973 51.984 17.088 52.008 ;
     RECT  15.973 52.008 17.1 52.128 ;
     RECT  15.973 52.128 17.088 52.152 ;
     RECT  15.973 52.152 17.1 52.224 ;
     RECT  15.973 52.224 17.088 52.248 ;
     RECT  15.973 52.248 17.1 52.32 ;
     RECT  15.973 52.32 17.088 52.344 ;
     RECT  15.973 52.344 17.1 52.416 ;
     RECT  15.973 52.416 17.088 52.44 ;
     RECT  15.973 52.44 17.1 52.512 ;
     RECT  15.973 52.512 17.088 52.536 ;
     RECT  15.973 52.536 17.1 52.608 ;
     RECT  15.973 52.608 17.088 52.632 ;
     RECT  15.973 52.632 17.1 52.752 ;
     RECT  15.973 52.752 17.088 52.776 ;
     RECT  15.973 52.776 17.1 52.848 ;
     RECT  15.973 52.848 17.088 52.872 ;
     RECT  15.973 52.872 17.1 52.944 ;
     RECT  15.973 52.944 17.088 52.968 ;
     RECT  15.973 52.968 17.1 53.04 ;
     RECT  15.973 53.04 17.088 53.064 ;
     RECT  15.973 53.064 17.1 53.136 ;
     RECT  15.973 53.136 17.088 53.16 ;
     RECT  15.973 53.16 17.1 53.28 ;
     RECT  15.973 53.28 17.088 53.304 ;
     RECT  15.973 53.304 17.1 53.376 ;
     RECT  15.973 53.376 17.088 53.4 ;
     RECT  15.973 53.4 17.1 53.472 ;
     RECT  15.973 53.472 17.088 53.496 ;
     RECT  15.973 53.496 17.1 53.568 ;
     RECT  15.973 53.568 17.088 53.592 ;
     RECT  15.973 53.592 17.1 53.664 ;
     RECT  15.973 53.664 17.088 53.688 ;
     RECT  15.973 53.688 17.1 53.76 ;
     RECT  15.973 53.76 17.088 53.784 ;
     RECT  15.973 53.784 17.1 53.904 ;
     RECT  15.973 53.904 17.088 53.928 ;
     RECT  15.973 53.928 17.1 54 ;
     RECT  15.973 54 17.088 54.024 ;
     RECT  15.973 54.024 17.1 54.096 ;
     RECT  15.973 54.096 17.088 54.12 ;
     RECT  15.973 54.12 17.1 54.192 ;
     RECT  15.973 54.192 17.088 54.216 ;
     RECT  15.973 54.216 17.1 54.288 ;
     RECT  15.973 54.288 17.088 54.312 ;
     RECT  15.973 54.312 17.1 54.384 ;
     RECT  15.973 54.384 17.088 54.408 ;
     RECT  15.973 54.408 17.1 54.528 ;
     RECT  15.973 54.528 17.088 54.552 ;
     RECT  15.973 54.552 17.1 54.624 ;
     RECT  15.973 54.624 17.088 54.648 ;
     RECT  15.973 54.648 17.1 54.72 ;
     RECT  15.973 54.72 17.088 54.744 ;
     RECT  15.973 54.744 17.1 54.816 ;
     RECT  15.973 54.816 17.088 54.84 ;
     RECT  15.973 54.84 17.1 54.912 ;
     RECT  15.973 54.912 17.088 54.936 ;
     RECT  15.973 54.936 17.1 55.008 ;
     RECT  15.973 55.008 17.088 55.032 ;
     RECT  15.973 55.032 17.1 55.152 ;
     RECT  15.973 55.152 17.088 55.176 ;
     RECT  15.973 55.176 17.1 55.248 ;
     RECT  15.973 55.248 17.088 55.272 ;
     RECT  15.973 55.272 17.1 55.344 ;
     RECT  15.973 55.344 17.088 55.368 ;
     RECT  15.973 55.368 17.1 55.44 ;
     RECT  15.973 55.44 17.088 55.464 ;
     RECT  15.973 55.464 17.1 55.536 ;
     RECT  15.973 55.536 17.088 55.56 ;
     RECT  15.973 55.56 17.1 55.68 ;
     RECT  15.973 55.68 17.088 55.704 ;
     RECT  15.973 55.704 17.1 55.776 ;
     RECT  15.973 55.776 17.088 55.8 ;
     RECT  15.973 55.8 17.1 55.872 ;
     RECT  15.973 55.872 17.088 55.896 ;
     RECT  15.973 55.896 17.1 55.968 ;
     RECT  15.973 55.968 17.088 55.992 ;
     RECT  15.973 55.992 17.1 56.064 ;
     RECT  15.973 56.064 17.088 56.088 ;
     RECT  15.973 56.088 17.1 56.16 ;
     RECT  15.973 56.16 17.088 56.184 ;
     RECT  15.973 56.184 17.1 56.304 ;
     RECT  15.973 56.304 17.088 56.328 ;
     RECT  15.973 56.328 17.1 56.4 ;
     RECT  15.973 56.4 17.088 56.424 ;
     RECT  15.973 56.424 17.1 56.496 ;
     RECT  15.973 56.496 17.088 56.52 ;
     RECT  15.973 56.52 17.1 56.592 ;
     RECT  15.973 56.592 17.088 56.616 ;
     RECT  15.973 56.616 17.1 56.688 ;
     RECT  15.973 56.688 17.088 56.712 ;
     RECT  15.973 56.712 17.1 56.784 ;
     RECT  15.973 56.784 17.088 56.808 ;
     RECT  15.973 56.808 17.1 56.928 ;
     RECT  15.973 56.928 17.088 56.952 ;
     RECT  15.973 56.952 17.1 57.024 ;
     RECT  15.973 57.024 17.088 57.048 ;
     RECT  15.973 57.048 17.1 57.12 ;
     RECT  15.973 57.12 17.088 57.144 ;
     RECT  15.973 57.144 17.1 57.216 ;
     RECT  15.973 57.216 17.088 57.24 ;
     RECT  15.973 57.24 17.1 57.312 ;
     RECT  15.973 57.312 17.088 57.336 ;
     RECT  15.973 57.336 17.1 57.456 ;
     RECT  15.973 57.456 17.088 57.48 ;
     RECT  15.973 57.48 17.1 57.552 ;
     RECT  15.973 57.552 17.088 57.576 ;
     RECT  15.973 57.576 17.1 57.648 ;
     RECT  15.973 57.648 17.088 57.672 ;
     RECT  15.973 57.672 17.1 57.744 ;
     RECT  15.973 57.744 17.088 57.768 ;
     RECT  15.973 57.768 17.1 57.84 ;
     RECT  15.973 57.84 17.088 57.864 ;
     RECT  15.973 57.864 17.1 57.936 ;
     RECT  15.973 57.936 17.088 57.96 ;
     RECT  15.973 57.96 17.1 58.08 ;
     RECT  15.973 58.08 17.088 58.104 ;
     RECT  15.973 58.104 17.1 58.176 ;
     RECT  15.973 58.176 17.088 58.2 ;
     RECT  15.973 58.2 17.1 58.272 ;
     RECT  15.973 58.272 17.088 58.296 ;
     RECT  15.973 58.296 17.1 58.368 ;
     RECT  15.973 58.368 17.088 58.392 ;
     RECT  15.973 58.392 17.1 58.464 ;
     RECT  15.973 58.464 17.088 58.488 ;
     RECT  15.973 58.488 17.1 58.56 ;
     RECT  15.973 58.56 17.088 58.584 ;
     RECT  15.973 58.584 17.1 58.704 ;
     RECT  15.973 58.704 17.088 58.728 ;
     RECT  15.973 58.728 17.1 58.8 ;
     RECT  15.973 58.8 17.088 58.824 ;
     RECT  15.973 58.824 17.1 58.896 ;
     RECT  15.973 58.896 17.088 58.92 ;
     RECT  15.973 58.92 17.1 58.992 ;
     RECT  15.973 58.992 17.088 59.016 ;
     RECT  15.973 59.016 17.1 59.088 ;
     RECT  15.973 59.088 17.088 59.112 ;
     RECT  15.973 59.112 17.1 59.184 ;
     RECT  15.973 59.184 17.088 59.208 ;
     RECT  15.973 59.208 17.1 59.328 ;
     RECT  15.973 59.328 17.088 59.352 ;
     RECT  15.973 59.352 17.1 59.424 ;
     RECT  15.973 59.424 17.088 59.448 ;
     RECT  15.973 59.448 17.1 59.52 ;
     RECT  15.973 59.52 17.088 59.544 ;
     RECT  15.973 59.544 17.1 59.616 ;
     RECT  15.973 59.616 17.088 59.64 ;
     RECT  15.973 59.64 17.1 59.712 ;
     RECT  15.973 59.712 17.088 59.736 ;
     RECT  15.973 59.736 17.1 59.856 ;
     RECT  15.973 59.856 17.088 59.88 ;
     RECT  15.973 59.88 17.1 59.952 ;
     RECT  15.973 59.952 17.088 59.976 ;
     RECT  15.973 59.976 17.1 60.048 ;
     RECT  15.973 60.048 17.088 60.072 ;
     RECT  15.973 60.072 17.1 60.144 ;
     RECT  15.973 60.144 17.088 60.168 ;
     RECT  15.973 60.168 17.1 60.24 ;
     RECT  15.973 60.24 17.088 60.264 ;
     RECT  15.973 60.264 17.1 60.336 ;
     RECT  15.973 60.336 17.088 60.36 ;
     RECT  15.973 60.36 17.1 60.48 ;
     RECT  15.973 60.48 17.088 60.504 ;
     RECT  15.973 60.504 17.1 60.576 ;
     RECT  15.973 60.576 17.088 60.6 ;
     RECT  15.973 60.6 17.1 60.672 ;
     RECT  15.973 60.672 17.088 60.696 ;
     RECT  15.973 60.696 17.1 60.768 ;
     RECT  15.973 60.768 17.088 60.792 ;
     RECT  15.973 60.792 17.1 60.864 ;
     RECT  15.973 60.864 17.088 60.888 ;
     RECT  15.973 60.888 17.1 60.96 ;
     RECT  15.973 60.96 17.088 60.984 ;
     RECT  15.973 60.984 17.1 61.104 ;
     RECT  15.973 61.104 17.088 61.128 ;
     RECT  15.973 61.128 17.1 61.2 ;
     RECT  15.973 61.2 17.088 61.224 ;
     RECT  15.973 61.224 17.1 61.296 ;
     RECT  15.973 61.296 17.088 61.32 ;
     RECT  15.973 61.32 17.1 61.392 ;
     RECT  15.973 61.392 17.088 61.416 ;
     RECT  15.973 61.416 17.1 61.488 ;
     RECT  15.973 61.488 17.088 61.512 ;
     RECT  15.973 61.512 17.1 61.584 ;
     RECT  15.973 61.584 17.088 61.608 ;
     RECT  15.973 61.608 17.1 61.728 ;
     RECT  15.973 61.728 17.088 61.752 ;
     RECT  15.973 61.752 17.1 61.824 ;
     RECT  15.973 61.824 17.088 61.848 ;
     RECT  15.973 61.848 17.1 61.92 ;
     RECT  15.973 61.92 17.088 61.944 ;
     RECT  15.973 61.944 17.1 62.016 ;
     RECT  15.973 62.016 17.088 62.04 ;
     RECT  15.973 62.04 17.1 62.112 ;
     RECT  15.973 62.112 17.088 62.136 ;
     RECT  15.973 62.136 17.1 62.256 ;
     RECT  15.973 62.256 17.088 62.28 ;
     RECT  15.973 62.28 17.1 62.352 ;
     RECT  15.973 62.352 17.088 62.376 ;
     RECT  15.973 62.376 17.1 62.448 ;
     RECT  15.973 62.448 17.088 62.472 ;
     RECT  15.973 62.472 17.1 62.544 ;
     RECT  15.973 62.544 17.088 62.568 ;
     RECT  15.973 62.568 17.1 62.64 ;
     RECT  15.973 62.64 17.088 62.664 ;
     RECT  15.973 62.664 17.1 62.736 ;
     RECT  15.973 62.736 17.088 62.76 ;
     RECT  15.973 62.76 17.1 62.88 ;
     RECT  15.973 62.88 17.088 62.904 ;
     RECT  15.973 62.904 17.1 62.976 ;
     RECT  15.973 62.976 17.088 63 ;
     RECT  15.973 63 17.1 63.072 ;
     RECT  15.973 63.072 17.088 63.096 ;
     RECT  15.973 63.096 17.1 63.168 ;
     RECT  15.973 63.168 17.088 63.192 ;
     RECT  15.973 63.192 17.1 63.264 ;
     RECT  15.973 63.264 17.088 63.288 ;
     RECT  15.973 63.288 17.1 63.36 ;
     RECT  15.973 63.36 17.088 63.384 ;
     RECT  15.973 63.384 17.1 63.504 ;
     RECT  15.973 63.504 17.088 63.528 ;
     RECT  15.973 63.528 17.1 63.6 ;
     RECT  15.973 63.6 17.088 63.624 ;
     RECT  15.973 63.624 17.1 63.696 ;
     RECT  15.973 63.696 17.088 63.72 ;
     RECT  15.973 63.72 17.1 63.792 ;
     RECT  15.973 63.792 17.088 63.816 ;
     RECT  15.973 63.816 17.1 63.888 ;
     RECT  15.973 63.888 17.088 63.912 ;
     RECT  15.973 63.912 17.1 63.984 ;
     RECT  15.973 63.984 17.088 64.008 ;
     RECT  15.973 64.008 17.1 64.128 ;
     RECT  15.973 64.128 17.088 64.152 ;
     RECT  15.973 64.152 17.1 64.224 ;
     RECT  15.973 64.224 17.088 64.248 ;
     RECT  15.973 64.248 17.1 64.32 ;
     RECT  15.973 64.32 17.088 64.344 ;
     RECT  15.973 64.344 17.1 64.416 ;
     RECT  15.973 64.416 17.088 64.44 ;
     RECT  15.973 64.44 17.1 64.512 ;
     RECT  15.973 64.512 17.088 64.536 ;
     RECT  15.973 64.536 17.1 64.656 ;
     RECT  15.973 64.656 17.088 64.68 ;
     RECT  15.973 64.68 17.1 64.752 ;
     RECT  15.973 64.752 17.088 64.776 ;
     RECT  15.973 64.776 17.1 64.848 ;
     RECT  15.973 64.848 17.088 64.872 ;
     RECT  15.973 64.872 17.1 64.944 ;
     RECT  15.973 64.944 17.088 64.968 ;
     RECT  15.973 64.968 17.1 65.04 ;
     RECT  15.973 65.04 17.088 65.064 ;
     RECT  15.973 65.064 17.1 65.136 ;
     RECT  15.973 65.136 17.088 65.16 ;
     RECT  15.973 65.16 17.1 65.28 ;
     RECT  15.973 65.28 17.088 65.304 ;
     RECT  15.973 65.304 17.1 65.376 ;
     RECT  15.973 65.376 17.088 65.4 ;
     RECT  15.973 65.4 17.1 65.472 ;
     RECT  15.973 65.472 17.088 65.496 ;
     RECT  15.973 65.496 17.1 65.568 ;
     RECT  15.973 65.568 17.088 65.592 ;
     RECT  15.973 65.592 17.1 65.664 ;
     RECT  15.973 65.664 17.088 65.688 ;
     RECT  15.973 65.688 17.1 65.76 ;
     RECT  15.973 65.76 17.088 65.784 ;
     RECT  15.973 65.784 17.1 65.904 ;
     RECT  15.973 65.904 17.088 65.928 ;
     RECT  15.973 65.928 17.1 66 ;
     RECT  15.973 66 17.088 66.024 ;
     RECT  15.973 66.024 17.1 66.096 ;
     RECT  15.973 66.096 17.088 66.12 ;
     RECT  15.973 66.12 17.1 66.192 ;
     RECT  15.973 66.192 17.088 66.216 ;
     RECT  15.973 66.216 17.1 66.288 ;
     RECT  15.973 66.288 17.088 66.312 ;
     RECT  15.973 66.312 17.1 66.384 ;
     RECT  15.973 66.384 17.088 66.408 ;
     RECT  15.973 66.408 17.1 66.528 ;
     RECT  15.973 66.528 17.088 66.552 ;
     RECT  15.973 66.552 17.1 66.624 ;
     RECT  15.973 66.624 17.088 66.648 ;
     RECT  15.973 66.648 17.1 66.72 ;
     RECT  15.973 66.72 17.088 66.744 ;
     RECT  15.973 66.744 17.1 66.816 ;
     RECT  15.973 66.816 17.088 66.84 ;
     RECT  15.973 66.84 17.1 66.912 ;
     RECT  15.973 66.912 17.088 66.936 ;
     RECT  15.973 66.936 17.1 67.056 ;
     RECT  15.973 67.056 17.088 67.08 ;
     RECT  15.973 67.08 17.1 67.152 ;
     RECT  15.973 67.152 17.088 67.176 ;
     RECT  15.973 67.176 17.1 67.248 ;
     RECT  15.973 67.248 17.088 67.272 ;
     RECT  15.973 67.272 17.1 67.344 ;
     RECT  15.973 67.344 17.088 67.368 ;
     RECT  15.973 67.368 17.1 67.44 ;
     RECT  15.973 67.44 17.088 67.464 ;
     RECT  15.973 67.464 17.1 67.536 ;
     RECT  15.973 67.536 17.088 67.56 ;
     RECT  15.973 67.56 17.1 67.68 ;
     RECT  15.973 67.68 17.088 67.704 ;
     RECT  15.973 67.704 17.1 67.776 ;
     RECT  15.973 67.776 17.088 67.8 ;
     RECT  15.973 67.8 17.1 67.872 ;
     RECT  15.973 67.872 17.088 67.896 ;
     RECT  15.973 67.896 17.1 67.968 ;
     RECT  15.973 67.968 17.088 67.992 ;
     RECT  15.973 67.992 17.1 68.064 ;
     RECT  15.973 68.064 17.088 68.088 ;
     RECT  15.973 68.088 17.1 68.16 ;
     RECT  15.973 68.16 17.088 68.184 ;
     RECT  15.973 68.184 17.1 68.304 ;
     RECT  15.973 68.304 17.088 68.328 ;
     RECT  15.973 68.328 17.1 68.4 ;
     RECT  15.973 68.4 17.088 68.424 ;
     RECT  15.973 68.424 17.1 68.496 ;
     RECT  15.973 68.496 17.088 68.52 ;
     RECT  15.973 68.52 17.1 68.592 ;
     RECT  15.973 68.592 17.088 68.616 ;
     RECT  15.973 68.616 17.1 68.688 ;
     RECT  15.973 68.688 17.088 68.712 ;
     RECT  15.973 68.712 17.1 68.784 ;
     RECT  15.973 68.784 17.088 68.808 ;
     RECT  15.973 68.808 17.1 68.928 ;
     RECT  15.973 68.928 17.088 68.952 ;
     RECT  15.973 68.952 17.1 69.024 ;
     RECT  15.973 69.024 17.088 69.048 ;
     RECT  15.973 69.048 17.1 69.12 ;
     RECT  15.973 69.12 17.088 69.144 ;
     RECT  15.973 69.144 17.1 69.216 ;
     RECT  15.973 69.216 17.088 69.24 ;
     RECT  15.973 69.24 17.1 69.312 ;
     RECT  15.973 69.312 17.088 69.336 ;
     RECT  15.973 69.336 17.1 69.456 ;
     RECT  15.973 69.456 17.088 69.48 ;
     RECT  15.973 69.48 17.1 69.552 ;
     RECT  15.973 69.552 17.088 69.576 ;
     RECT  15.973 69.576 17.1 69.648 ;
     RECT  15.973 69.648 17.088 69.672 ;
     RECT  15.973 69.672 17.1 69.744 ;
     RECT  15.973 69.744 17.088 69.768 ;
     RECT  15.973 69.768 17.1 69.84 ;
     RECT  15.973 69.84 17.088 69.864 ;
     RECT  15.973 69.864 17.1 69.936 ;
     RECT  15.973 69.936 17.088 69.96 ;
     RECT  15.973 69.96 17.1 70.08 ;
     RECT  15.973 70.08 17.088 70.104 ;
     RECT  15.973 70.104 17.1 70.176 ;
     RECT  15.973 70.176 17.088 70.2 ;
     RECT  15.973 70.2 17.1 70.272 ;
     RECT  15.973 70.272 17.088 70.296 ;
     RECT  15.973 70.296 17.1 70.368 ;
     RECT  15.973 70.368 17.088 70.392 ;
     RECT  15.973 70.392 17.1 70.464 ;
     RECT  15.973 70.464 17.088 70.488 ;
     RECT  15.973 70.488 17.1 70.56 ;
     RECT  15.973 70.56 17.088 70.584 ;
     RECT  15.973 70.584 17.1 70.704 ;
     RECT  15.973 70.704 17.088 70.728 ;
     RECT  15.973 70.728 17.1 70.8 ;
     RECT  15.973 70.8 17.088 70.824 ;
     RECT  15.973 70.824 17.1 70.896 ;
     RECT  15.973 70.896 17.088 70.92 ;
     RECT  15.973 70.92 17.1 70.992 ;
     RECT  15.973 70.992 17.088 71.016 ;
     RECT  15.973 71.016 17.1 71.088 ;
     RECT  15.973 71.088 17.088 71.112 ;
     RECT  15.973 71.112 17.1 71.232 ;
     RECT  15.973 71.232 17.088 71.256 ;
     RECT  15.973 71.256 17.1 71.328 ;
     RECT  15.973 71.328 17.088 71.352 ;
     RECT  15.973 71.352 17.1 71.424 ;
     RECT  15.973 71.424 17.088 71.448 ;
     RECT  15.973 71.448 17.1 71.52 ;
     RECT  15.973 71.52 17.088 71.544 ;
     RECT  15.973 71.544 17.1 71.616 ;
     RECT  15.973 71.616 17.088 71.64 ;
     RECT  15.973 71.64 17.1 71.712 ;
     RECT  15.973 71.712 17.088 71.736 ;
     RECT  15.973 71.736 17.1 71.856 ;
     RECT  15.973 71.856 17.088 71.88 ;
     RECT  15.973 71.88 17.1 71.952 ;
     RECT  15.973 71.952 17.088 71.976 ;
     RECT  15.973 71.976 17.1 72.048 ;
     RECT  15.973 72.048 17.088 72.072 ;
     RECT  15.973 72.072 17.1 72.144 ;
     RECT  15.973 72.144 17.088 72.168 ;
     RECT  15.973 72.168 17.1 72.24 ;
     RECT  15.973 72.24 17.088 72.264 ;
     RECT  15.973 72.264 17.1 72.336 ;
     RECT  15.973 72.336 17.088 72.36 ;
     RECT  15.973 72.36 17.1 72.48 ;
     RECT  15.973 72.48 17.088 72.504 ;
     RECT  15.973 72.504 17.1 72.576 ;
     RECT  15.973 72.576 17.088 72.6 ;
     RECT  15.973 72.6 17.1 72.672 ;
     RECT  15.973 72.672 17.088 72.696 ;
     RECT  15.973 72.696 17.1 72.768 ;
     RECT  15.973 72.768 17.088 72.792 ;
     RECT  15.973 72.792 17.1 72.864 ;
     RECT  15.973 72.864 17.088 72.888 ;
     RECT  15.973 72.888 17.1 72.96 ;
     RECT  15.973 72.96 17.088 72.984 ;
     RECT  15.973 72.984 17.1 73.104 ;
     RECT  15.973 73.104 17.088 73.128 ;
     RECT  15.973 73.128 17.1 73.2 ;
     RECT  15.973 73.2 17.088 73.224 ;
     RECT  15.973 73.224 17.1 73.296 ;
     RECT  15.973 73.296 17.088 73.32 ;
     RECT  15.973 73.32 17.1 73.392 ;
     RECT  15.973 73.392 17.088 73.416 ;
    LAYER M5 ;
     RECT  2.4 2.137 2.52 2.151 ;
     RECT  5.1 2.137 5.22 2.151 ;
     RECT  7.8 2.137 7.92 2.151 ;
     RECT  10.5 2.137 10.62 2.151 ;
     RECT  13.2 2.137 13.32 2.151 ;
     RECT  7.8 2.151 8.112 2.581 ;
     RECT  5.1 2.151 5.412 3.301 ;
     RECT  7.8 2.581 8.568 3.685 ;
     RECT  7.248 3.685 8.568 3.923 ;
     RECT  7.8 3.923 8.568 3.925 ;
     RECT  7.8 3.925 9 5.173 ;
     RECT  7.8 5.173 9.096 5.363 ;
     RECT  5.1 3.301 5.928 7.187 ;
     RECT  3.936 6.709 3.96 8.003 ;
     RECT  2.4 2.151 2.712 9.205 ;
     RECT  2.304 9.205 2.712 9.347 ;
     RECT  2.4 9.347 2.712 9.589 ;
     RECT  2.4 9.589 3.432 10.307 ;
     RECT  10.5 2.151 10.812 10.885 ;
     RECT  10.32 10.885 10.812 11.027 ;
     RECT  7.8 5.363 9 12.085 ;
     RECT  2.4 10.307 2.712 12.325 ;
     RECT  0.192 12.277 0.216 12.515 ;
     RECT  5.1 7.187 5.784 12.517 ;
     RECT  6.864 12.085 9 12.517 ;
     RECT  5.1 12.517 9 12.565 ;
     RECT  4.128 12.565 9 12.803 ;
     RECT  5.1 12.803 9 13.477 ;
     RECT  5.1 13.477 9.144 13.619 ;
     RECT  7.8 13.619 9.144 13.763 ;
     RECT  2.4 12.325 2.904 15.491 ;
     RECT  7.8 13.763 9 17.507 ;
     RECT  0.192 19.717 0.216 19.907 ;
     RECT  5.1 13.619 6.36 22.165 ;
     RECT  7.8 17.507 8.712 22.165 ;
     RECT  2.4 15.491 2.712 22.741 ;
     RECT  2.4 22.741 3.384 23.411 ;
     RECT  5.1 22.165 8.712 23.605 ;
     RECT  5.1 23.605 8.904 23.891 ;
     RECT  2.4 23.411 3.096 26.867 ;
     RECT  2.4 26.867 2.712 27.877 ;
     RECT  5.1 23.891 8.712 28.451 ;
     RECT  0.288 27.973 0.312 28.499 ;
     RECT  2.4 27.877 3.24 28.739 ;
     RECT  7.2 28.451 8.712 29.173 ;
     RECT  7.2 29.173 9.096 29.363 ;
     RECT  5.1 28.451 6.072 29.509 ;
     RECT  7.2 29.363 9 29.603 ;
     RECT  4.704 29.509 6.072 29.651 ;
     RECT  5.1 29.651 6.072 30.181 ;
     RECT  7.2 29.603 8.112 30.181 ;
     RECT  0.336 30.853 0.36 30.995 ;
     RECT  5.1 30.181 8.112 31.379 ;
     RECT  7.8 31.379 8.112 31.381 ;
     RECT  5.1 31.379 6.456 31.475 ;
     RECT  7.8 31.381 8.232 31.619 ;
     RECT  9.12 31.717 9.144 31.907 ;
     RECT  5.1 31.475 6.072 32.437 ;
     RECT  2.4 28.739 2.712 33.301 ;
     RECT  2.304 33.301 2.712 33.491 ;
     RECT  2.4 33.491 2.712 33.589 ;
     RECT  5.1 32.437 6.408 33.683 ;
     RECT  2.4 33.589 3.432 34.453 ;
     RECT  2.304 34.453 3.432 34.597 ;
     RECT  2.304 34.597 3.528 34.643 ;
     RECT  7.8 31.619 8.112 34.741 ;
     RECT  2.4 34.643 3.528 34.787 ;
     RECT  5.1 33.683 6.072 34.933 ;
     RECT  4.272 34.933 6.072 35.219 ;
     RECT  4.368 35.219 6.072 35.315 ;
     RECT  0.288 35.269 0.312 35.555 ;
     RECT  7.8 34.741 9.096 36.227 ;
     RECT  10.5 11.027 10.812 37.477 ;
     RECT  9.6 37.477 10.812 37.619 ;
     RECT  5.1 35.315 6.072 37.621 ;
     RECT  7.8 36.227 8.568 38.149 ;
     RECT  5.1 37.621 6.216 38.581 ;
     RECT  7.8 38.149 8.808 38.581 ;
     RECT  2.4 34.787 2.712 38.773 ;
     RECT  3.936 38.677 3.96 38.773 ;
     RECT  2.4 38.773 3.96 38.819 ;
     RECT  2.4 38.819 3.192 39.109 ;
     RECT  2.064 39.109 3.192 39.299 ;
     RECT  2.4 39.299 3.192 39.539 ;
     RECT  5.1 38.581 8.808 41.027 ;
     RECT  5.1 41.027 6.696 42.323 ;
     RECT  5.1 42.323 6.216 46.789 ;
     RECT  7.8 41.027 8.808 50.917 ;
     RECT  4.992 46.789 6.216 51.443 ;
     RECT  7.8 50.917 9.096 53.029 ;
     RECT  5.1 51.443 6.216 54.179 ;
     RECT  7.344 53.029 9.096 54.179 ;
     RECT  2.4 39.539 2.712 55.765 ;
     RECT  7.344 54.179 8.112 55.861 ;
     RECT  2.4 55.765 3.288 57.059 ;
     RECT  5.1 54.179 5.592 57.541 ;
     RECT  7.344 55.861 8.808 57.877 ;
     RECT  10.5 37.619 10.812 57.877 ;
     RECT  7.344 57.877 10.812 58.163 ;
     RECT  7.344 58.163 8.808 58.597 ;
     RECT  2.4 57.059 3.24 59.221 ;
     RECT  2.4 59.221 3.768 59.507 ;
     RECT  6.864 58.597 8.808 59.845 ;
     RECT  5.1 57.541 5.688 60.083 ;
     RECT  6.672 59.845 8.808 60.611 ;
     RECT  2.4 59.507 2.712 61.525 ;
     RECT  3.744 59.507 3.768 61.525 ;
     RECT  6.864 60.611 8.808 61.573 ;
     RECT  2.4 61.525 3.768 61.619 ;
     RECT  2.4 61.619 3.336 61.717 ;
     RECT  2.304 61.717 3.336 61.907 ;
     RECT  2.4 61.907 3.336 62.195 ;
     RECT  0.192 62.389 0.216 62.579 ;
     RECT  5.1 60.083 5.592 64.213 ;
     RECT  0.288 64.789 0.312 64.979 ;
     RECT  6.864 61.573 8.952 64.981 ;
     RECT  5.1 64.213 5.688 65.027 ;
     RECT  6.768 64.981 8.952 65.027 ;
     RECT  2.4 62.195 2.712 66.901 ;
     RECT  7.8 65.027 8.952 66.997 ;
     RECT  2.304 66.901 2.712 67.139 ;
     RECT  7.8 66.997 9.288 67.667 ;
     RECT  7.8 67.667 8.232 67.859 ;
     RECT  5.1 65.027 5.592 68.341 ;
     RECT  7.8 67.859 8.112 68.965 ;
     RECT  2.4 67.139 2.712 69.253 ;
     RECT  9.264 67.667 9.288 69.397 ;
     RECT  10.5 58.163 10.812 69.397 ;
     RECT  2.4 69.253 2.808 69.443 ;
     RECT  9.264 69.397 10.812 69.443 ;
     RECT  7.8 68.965 8.232 70.019 ;
     RECT  4.944 68.341 5.592 70.069 ;
     RECT  6.768 65.027 6.792 70.163 ;
     RECT  3.984 70.069 5.592 70.309 ;
     RECT  3.888 70.309 5.592 70.595 ;
     RECT  2.4 69.443 2.712 71.365 ;
     RECT  2.256 71.365 2.712 71.555 ;
     RECT  0.288 71.029 0.312 71.987 ;
     RECT  7.8 70.019 8.112 72.469 ;
     RECT  6.864 72.469 8.112 72.803 ;
     RECT  3.984 70.595 4.008 72.949 ;
     RECT  3.888 72.949 4.008 72.995 ;
     RECT  3.888 72.995 3.912 73.091 ;
     RECT  9.648 69.443 10.812 73.235 ;
     RECT  2.4 71.555 2.712 73.449 ;
     RECT  7.8 72.803 8.112 73.449 ;
     RECT  10.5 73.235 10.812 73.449 ;
     RECT  13.2 2.151 13.512 73.449 ;
     RECT  2.4 73.449 2.52 73.463 ;
     RECT  5.1 70.595 5.592 73.463 ;
     RECT  7.8 73.449 7.92 73.463 ;
     RECT  10.5 73.449 10.62 73.463 ;
     RECT  13.2 73.449 13.32 73.463 ;
     RECT  5.568 73.463 5.592 74.723 ;
     RECT  5.928 3.685 7.248 3.923 ;
     RECT  9 3.925 10.5 5.173 ;
     RECT  9.096 5.173 10.5 5.363 ;
     RECT  9 5.363 10.5 10.885 ;
     RECT  2.712 6.709 3.936 8.003 ;
     RECT  3.96 6.709 5.1 8.003 ;
     RECT  9 10.885 10.32 11.027 ;
     RECT  9 11.027 10.5 13.477 ;
     RECT  5.784 12.085 6.864 12.517 ;
     RECT  2.904 12.565 4.128 12.803 ;
     RECT  9.144 13.477 10.5 13.763 ;
     RECT  6.36 13.619 7.8 22.165 ;
     RECT  9 13.763 10.5 17.507 ;
     RECT  2.712 26.867 3.096 27.877 ;
     RECT  6.072 28.451 7.2 30.181 ;
     RECT  9.096 29.173 10.5 29.363 ;
     RECT  9 29.363 10.5 29.603 ;
     RECT  6.456 31.379 7.8 31.475 ;
     RECT  6.072 31.475 7.8 32.437 ;
     RECT  8.112 31.619 8.232 31.717 ;
     RECT  8.112 31.717 9.12 31.907 ;
     RECT  9.144 31.717 10.5 31.907 ;
     RECT  6.408 32.437 7.8 33.683 ;
     RECT  2.304 33.491 2.4 34.453 ;
     RECT  9.096 34.741 10.5 36.227 ;
     RECT  8.568 36.227 10.5 37.477 ;
     RECT  8.568 37.477 9.6 37.619 ;
     RECT  8.568 37.619 8.808 38.149 ;
     RECT  2.712 38.677 3.936 38.773 ;
     RECT  3.96 38.677 5.1 38.819 ;
     RECT  6.696 41.027 7.8 42.323 ;
     RECT  9.096 50.917 10.5 54.179 ;
     RECT  6.216 53.029 7.344 54.179 ;
     RECT  5.688 58.597 6.864 59.845 ;
     RECT  3.768 59.221 5.1 61.619 ;
     RECT  2.712 59.507 3.744 61.525 ;
     RECT  5.688 59.845 6.672 60.083 ;
     RECT  5.592 60.083 6.672 60.611 ;
     RECT  5.592 60.611 6.864 64.213 ;
     RECT  5.688 64.213 6.864 64.981 ;
     RECT  5.688 64.981 6.768 65.027 ;
     RECT  5.592 65.027 6.768 70.163 ;
     RECT  6.792 65.027 7.8 70.163 ;
     RECT  9.288 66.997 10.5 69.397 ;
     RECT  8.232 67.667 9.264 67.859 ;
     RECT  8.112 67.859 9.264 68.965 ;
     RECT  8.232 68.965 9.264 69.443 ;
     RECT  2.712 69.443 2.808 70.069 ;
     RECT  8.232 69.443 9.648 70.019 ;
     RECT  2.712 70.069 3.984 70.309 ;
     RECT  2.712 70.309 3.888 70.595 ;
     RECT  2.712 70.595 3.984 72.949 ;
     RECT  4.008 70.595 5.1 72.995 ;
     RECT  5.592 72.469 6.864 72.803 ;
     RECT  2.712 72.949 3.888 73.091 ;
     RECT  3.912 72.995 5.1 73.091 ;
  END
END dsfd_dvrly_682_WE
END LIBRARY
